VERSION 5.8 ;
BUSBITCHARS "[]" ;
DIVIDERCHAR "/" ;
UNITS
    DATABASE MICRONS 1000 ;
END UNITS

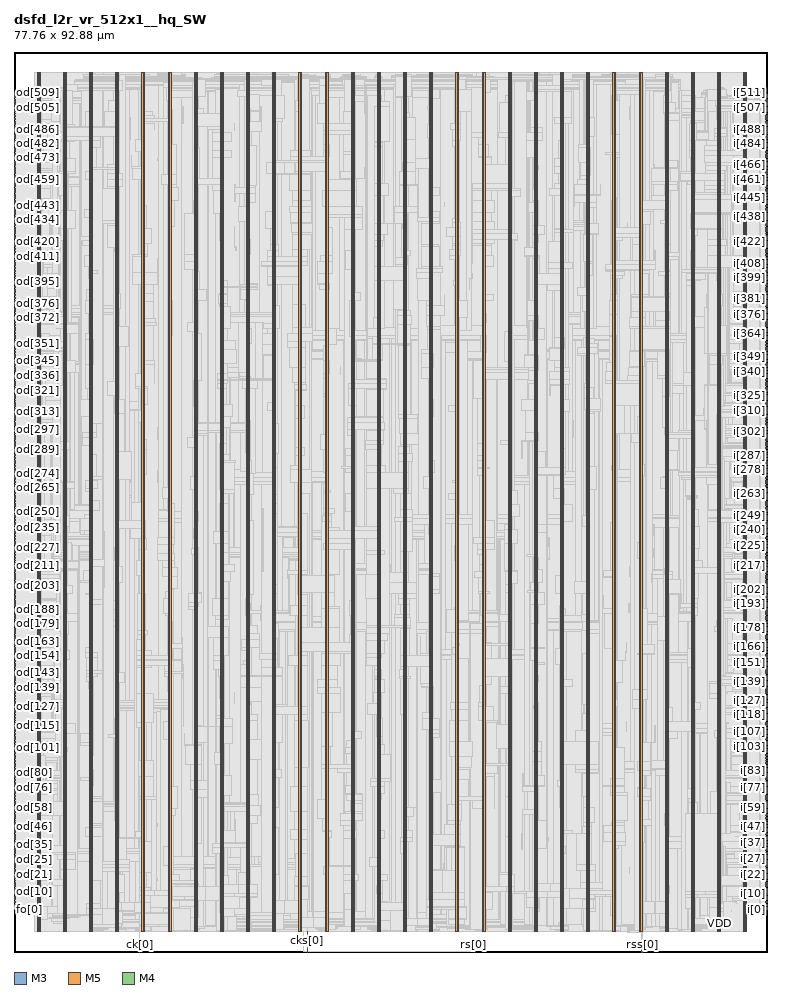
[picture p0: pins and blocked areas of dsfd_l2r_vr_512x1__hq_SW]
MACRO dsfd_l2r_vr_512x1__hq_SW
  FOREIGN dsfd_l2r_vr_512x1__hq_SW 0 0 ;
  CLASS BLOCK ;
  SIZE 77.76 BY 92.88 ;
  PIN ck[0]
    DIRECTION INPUT ;
    USE SIGNAL ;
    PORT
      LAYER M3 ;
        RECT  12.96 0 12.978 0.144 ;
    END
    PORT
      LAYER M3 ;
        RECT  12.96 0.108 12.978 0.173 ;
    END
  END ck[0]
  PIN cks[0]
    DIRECTION INPUT ;
    USE SIGNAL ;
    PORT
      LAYER M5 ;
        RECT  30.24 0 30.264 0.192 ;
    END
    PORT
      LAYER M5 ;
        RECT  30.24 0.144 30.264 2.137 ;
    END
  END cks[0]
  PIN fo[0]
    DIRECTION OUTPUT ;
    USE SIGNAL ;
    PORT
      LAYER M4 ;
        RECT  0 4.416 0.192 4.44 ;
    END
  END fo[0]
  PIN i[0]
    DIRECTION INPUT ;
    USE SIGNAL ;
    PORT
      LAYER M4 ;
        RECT  77.568 4.416 77.76 4.44 ;
    END
  END i[0]
  PIN i[100]
    DIRECTION INPUT ;
    USE SIGNAL ;
    PORT
      LAYER M4 ;
        RECT  77.568 20.736 77.76 20.76 ;
    END
  END i[100]
  PIN i[101]
    DIRECTION INPUT ;
    USE SIGNAL ;
    PORT
      LAYER M4 ;
        RECT  77.568 20.88 77.76 20.904 ;
    END
  END i[101]
  PIN i[102]
    DIRECTION INPUT ;
    USE SIGNAL ;
    PORT
      LAYER M4 ;
        RECT  77.568 21.072 77.76 21.096 ;
    END
  END i[102]
  PIN i[103]
    DIRECTION INPUT ;
    USE SIGNAL ;
    PORT
      LAYER M4 ;
        RECT  77.568 21.216 77.76 21.24 ;
    END
  END i[103]
  PIN i[104]
    DIRECTION INPUT ;
    USE SIGNAL ;
    PORT
      LAYER M4 ;
        RECT  77.568 21.408 77.76 21.432 ;
    END
  END i[104]
  PIN i[105]
    DIRECTION INPUT ;
    USE SIGNAL ;
    PORT
      LAYER M4 ;
        RECT  77.568 21.552 77.76 21.576 ;
    END
  END i[105]
  PIN i[106]
    DIRECTION INPUT ;
    USE SIGNAL ;
    PORT
      LAYER M4 ;
        RECT  77.568 21.696 77.76 21.72 ;
    END
  END i[106]
  PIN i[107]
    DIRECTION INPUT ;
    USE SIGNAL ;
    PORT
      LAYER M4 ;
        RECT  77.568 21.888 77.76 21.912 ;
    END
  END i[107]
  PIN i[108]
    DIRECTION INPUT ;
    USE SIGNAL ;
    PORT
      LAYER M4 ;
        RECT  77.568 22.032 77.76 22.056 ;
    END
  END i[108]
  PIN i[109]
    DIRECTION INPUT ;
    USE SIGNAL ;
    PORT
      LAYER M4 ;
        RECT  77.568 22.224 77.76 22.248 ;
    END
  END i[109]
  PIN i[10]
    DIRECTION INPUT ;
    USE SIGNAL ;
    PORT
      LAYER M4 ;
        RECT  77.568 6.048 77.76 6.072 ;
    END
  END i[10]
  PIN i[110]
    DIRECTION INPUT ;
    USE SIGNAL ;
    PORT
      LAYER M4 ;
        RECT  77.568 22.368 77.76 22.392 ;
    END
  END i[110]
  PIN i[111]
    DIRECTION INPUT ;
    USE SIGNAL ;
    PORT
      LAYER M4 ;
        RECT  77.568 22.512 77.76 22.536 ;
    END
  END i[111]
  PIN i[112]
    DIRECTION INPUT ;
    USE SIGNAL ;
    PORT
      LAYER M4 ;
        RECT  77.568 22.704 77.76 22.728 ;
    END
  END i[112]
  PIN i[113]
    DIRECTION INPUT ;
    USE SIGNAL ;
    PORT
      LAYER M4 ;
        RECT  77.568 22.848 77.76 22.872 ;
    END
  END i[113]
  PIN i[114]
    DIRECTION INPUT ;
    USE SIGNAL ;
    PORT
      LAYER M4 ;
        RECT  77.568 23.04 77.76 23.064 ;
    END
  END i[114]
  PIN i[115]
    DIRECTION INPUT ;
    USE SIGNAL ;
    PORT
      LAYER M4 ;
        RECT  77.568 23.184 77.76 23.208 ;
    END
  END i[115]
  PIN i[116]
    DIRECTION INPUT ;
    USE SIGNAL ;
    PORT
      LAYER M4 ;
        RECT  77.568 23.328 77.76 23.352 ;
    END
  END i[116]
  PIN i[117]
    DIRECTION INPUT ;
    USE SIGNAL ;
    PORT
      LAYER M4 ;
        RECT  77.568 23.52 77.76 23.544 ;
    END
  END i[117]
  PIN i[118]
    DIRECTION INPUT ;
    USE SIGNAL ;
    PORT
      LAYER M4 ;
        RECT  77.568 23.664 77.76 23.688 ;
    END
  END i[118]
  PIN i[119]
    DIRECTION INPUT ;
    USE SIGNAL ;
    PORT
      LAYER M4 ;
        RECT  77.568 23.856 77.76 23.88 ;
    END
  END i[119]
  PIN i[11]
    DIRECTION INPUT ;
    USE SIGNAL ;
    PORT
      LAYER M4 ;
        RECT  77.568 6.192 77.76 6.216 ;
    END
  END i[11]
  PIN i[120]
    DIRECTION INPUT ;
    USE SIGNAL ;
    PORT
      LAYER M4 ;
        RECT  77.568 24 77.76 24.024 ;
    END
  END i[120]
  PIN i[121]
    DIRECTION INPUT ;
    USE SIGNAL ;
    PORT
      LAYER M4 ;
        RECT  77.568 24.144 77.76 24.168 ;
    END
  END i[121]
  PIN i[122]
    DIRECTION INPUT ;
    USE SIGNAL ;
    PORT
      LAYER M4 ;
        RECT  77.568 24.336 77.76 24.36 ;
    END
  END i[122]
  PIN i[123]
    DIRECTION INPUT ;
    USE SIGNAL ;
    PORT
      LAYER M4 ;
        RECT  77.568 24.48 77.76 24.504 ;
    END
  END i[123]
  PIN i[124]
    DIRECTION INPUT ;
    USE SIGNAL ;
    PORT
      LAYER M4 ;
        RECT  77.568 24.672 77.76 24.696 ;
    END
  END i[124]
  PIN i[125]
    DIRECTION INPUT ;
    USE SIGNAL ;
    PORT
      LAYER M4 ;
        RECT  77.568 24.816 77.76 24.84 ;
    END
  END i[125]
  PIN i[126]
    DIRECTION INPUT ;
    USE SIGNAL ;
    PORT
      LAYER M4 ;
        RECT  77.568 24.96 77.76 24.984 ;
    END
  END i[126]
  PIN i[127]
    DIRECTION INPUT ;
    USE SIGNAL ;
    PORT
      LAYER M4 ;
        RECT  77.568 25.152 77.76 25.176 ;
    END
  END i[127]
  PIN i[128]
    DIRECTION INPUT ;
    USE SIGNAL ;
    PORT
      LAYER M4 ;
        RECT  77.568 25.296 77.76 25.32 ;
    END
  END i[128]
  PIN i[129]
    DIRECTION INPUT ;
    USE SIGNAL ;
    PORT
      LAYER M4 ;
        RECT  77.568 25.488 77.76 25.512 ;
    END
  END i[129]
  PIN i[12]
    DIRECTION INPUT ;
    USE SIGNAL ;
    PORT
      LAYER M4 ;
        RECT  77.568 6.384 77.76 6.408 ;
    END
  END i[12]
  PIN i[130]
    DIRECTION INPUT ;
    USE SIGNAL ;
    PORT
      LAYER M4 ;
        RECT  77.568 25.632 77.76 25.656 ;
    END
  END i[130]
  PIN i[131]
    DIRECTION INPUT ;
    USE SIGNAL ;
    PORT
      LAYER M4 ;
        RECT  77.568 25.824 77.76 25.848 ;
    END
  END i[131]
  PIN i[132]
    DIRECTION INPUT ;
    USE SIGNAL ;
    PORT
      LAYER M4 ;
        RECT  77.568 25.968 77.76 25.992 ;
    END
  END i[132]
  PIN i[133]
    DIRECTION INPUT ;
    USE SIGNAL ;
    PORT
      LAYER M4 ;
        RECT  77.568 26.112 77.76 26.136 ;
    END
  END i[133]
  PIN i[134]
    DIRECTION INPUT ;
    USE SIGNAL ;
    PORT
      LAYER M4 ;
        RECT  77.568 26.304 77.76 26.328 ;
    END
  END i[134]
  PIN i[135]
    DIRECTION INPUT ;
    USE SIGNAL ;
    PORT
      LAYER M4 ;
        RECT  77.568 26.448 77.76 26.472 ;
    END
  END i[135]
  PIN i[136]
    DIRECTION INPUT ;
    USE SIGNAL ;
    PORT
      LAYER M4 ;
        RECT  77.568 26.64 77.76 26.664 ;
    END
  END i[136]
  PIN i[137]
    DIRECTION INPUT ;
    USE SIGNAL ;
    PORT
      LAYER M4 ;
        RECT  77.568 26.784 77.76 26.808 ;
    END
  END i[137]
  PIN i[138]
    DIRECTION INPUT ;
    USE SIGNAL ;
    PORT
      LAYER M4 ;
        RECT  77.568 26.928 77.76 26.952 ;
    END
  END i[138]
  PIN i[139]
    DIRECTION INPUT ;
    USE SIGNAL ;
    PORT
      LAYER M4 ;
        RECT  77.568 27.12 77.76 27.144 ;
    END
  END i[139]
  PIN i[13]
    DIRECTION INPUT ;
    USE SIGNAL ;
    PORT
      LAYER M4 ;
        RECT  77.568 6.528 77.76 6.552 ;
    END
  END i[13]
  PIN i[140]
    DIRECTION INPUT ;
    USE SIGNAL ;
    PORT
      LAYER M4 ;
        RECT  77.568 27.264 77.76 27.288 ;
    END
  END i[140]
  PIN i[141]
    DIRECTION INPUT ;
    USE SIGNAL ;
    PORT
      LAYER M4 ;
        RECT  77.568 27.456 77.76 27.48 ;
    END
  END i[141]
  PIN i[142]
    DIRECTION INPUT ;
    USE SIGNAL ;
    PORT
      LAYER M4 ;
        RECT  77.568 27.6 77.76 27.624 ;
    END
  END i[142]
  PIN i[143]
    DIRECTION INPUT ;
    USE SIGNAL ;
    PORT
      LAYER M4 ;
        RECT  77.568 27.744 77.76 27.768 ;
    END
  END i[143]
  PIN i[144]
    DIRECTION INPUT ;
    USE SIGNAL ;
    PORT
      LAYER M4 ;
        RECT  77.568 27.936 77.76 27.96 ;
    END
  END i[144]
  PIN i[145]
    DIRECTION INPUT ;
    USE SIGNAL ;
    PORT
      LAYER M4 ;
        RECT  77.568 28.08 77.76 28.104 ;
    END
  END i[145]
  PIN i[146]
    DIRECTION INPUT ;
    USE SIGNAL ;
    PORT
      LAYER M4 ;
        RECT  77.568 28.272 77.76 28.296 ;
    END
  END i[146]
  PIN i[147]
    DIRECTION INPUT ;
    USE SIGNAL ;
    PORT
      LAYER M4 ;
        RECT  77.568 28.416 77.76 28.44 ;
    END
  END i[147]
  PIN i[148]
    DIRECTION INPUT ;
    USE SIGNAL ;
    PORT
      LAYER M4 ;
        RECT  77.568 28.56 77.76 28.584 ;
    END
  END i[148]
  PIN i[149]
    DIRECTION INPUT ;
    USE SIGNAL ;
    PORT
      LAYER M4 ;
        RECT  77.568 28.752 77.76 28.776 ;
    END
  END i[149]
  PIN i[14]
    DIRECTION INPUT ;
    USE SIGNAL ;
    PORT
      LAYER M4 ;
        RECT  77.568 6.72 77.76 6.744 ;
    END
  END i[14]
  PIN i[150]
    DIRECTION INPUT ;
    USE SIGNAL ;
    PORT
      LAYER M4 ;
        RECT  77.568 28.896 77.76 28.92 ;
    END
  END i[150]
  PIN i[151]
    DIRECTION INPUT ;
    USE SIGNAL ;
    PORT
      LAYER M4 ;
        RECT  77.568 29.088 77.76 29.112 ;
    END
  END i[151]
  PIN i[152]
    DIRECTION INPUT ;
    USE SIGNAL ;
    PORT
      LAYER M4 ;
        RECT  77.568 29.232 77.76 29.256 ;
    END
  END i[152]
  PIN i[153]
    DIRECTION INPUT ;
    USE SIGNAL ;
    PORT
      LAYER M4 ;
        RECT  77.568 29.376 77.76 29.4 ;
    END
  END i[153]
  PIN i[154]
    DIRECTION INPUT ;
    USE SIGNAL ;
    PORT
      LAYER M4 ;
        RECT  77.568 29.568 77.76 29.592 ;
    END
  END i[154]
  PIN i[155]
    DIRECTION INPUT ;
    USE SIGNAL ;
    PORT
      LAYER M4 ;
        RECT  77.568 29.712 77.76 29.736 ;
    END
  END i[155]
  PIN i[156]
    DIRECTION INPUT ;
    USE SIGNAL ;
    PORT
      LAYER M4 ;
        RECT  77.568 29.904 77.76 29.928 ;
    END
  END i[156]
  PIN i[157]
    DIRECTION INPUT ;
    USE SIGNAL ;
    PORT
      LAYER M4 ;
        RECT  77.568 30.048 77.76 30.072 ;
    END
  END i[157]
  PIN i[158]
    DIRECTION INPUT ;
    USE SIGNAL ;
    PORT
      LAYER M4 ;
        RECT  77.568 30.192 77.76 30.216 ;
    END
  END i[158]
  PIN i[159]
    DIRECTION INPUT ;
    USE SIGNAL ;
    PORT
      LAYER M4 ;
        RECT  77.568 30.384 77.76 30.408 ;
    END
  END i[159]
  PIN i[15]
    DIRECTION INPUT ;
    USE SIGNAL ;
    PORT
      LAYER M4 ;
        RECT  77.568 6.864 77.76 6.888 ;
    END
  END i[15]
  PIN i[160]
    DIRECTION INPUT ;
    USE SIGNAL ;
    PORT
      LAYER M4 ;
        RECT  77.568 30.528 77.76 30.552 ;
    END
  END i[160]
  PIN i[161]
    DIRECTION INPUT ;
    USE SIGNAL ;
    PORT
      LAYER M4 ;
        RECT  77.568 30.72 77.76 30.744 ;
    END
  END i[161]
  PIN i[162]
    DIRECTION INPUT ;
    USE SIGNAL ;
    PORT
      LAYER M4 ;
        RECT  77.568 30.864 77.76 30.888 ;
    END
  END i[162]
  PIN i[163]
    DIRECTION INPUT ;
    USE SIGNAL ;
    PORT
      LAYER M4 ;
        RECT  77.568 31.008 77.76 31.032 ;
    END
  END i[163]
  PIN i[164]
    DIRECTION INPUT ;
    USE SIGNAL ;
    PORT
      LAYER M4 ;
        RECT  77.568 31.2 77.76 31.224 ;
    END
  END i[164]
  PIN i[165]
    DIRECTION INPUT ;
    USE SIGNAL ;
    PORT
      LAYER M4 ;
        RECT  77.568 31.344 77.76 31.368 ;
    END
  END i[165]
  PIN i[166]
    DIRECTION INPUT ;
    USE SIGNAL ;
    PORT
      LAYER M4 ;
        RECT  77.568 31.536 77.76 31.56 ;
    END
  END i[166]
  PIN i[167]
    DIRECTION INPUT ;
    USE SIGNAL ;
    PORT
      LAYER M4 ;
        RECT  77.568 31.68 77.76 31.704 ;
    END
  END i[167]
  PIN i[168]
    DIRECTION INPUT ;
    USE SIGNAL ;
    PORT
      LAYER M4 ;
        RECT  77.568 31.824 77.76 31.848 ;
    END
  END i[168]
  PIN i[169]
    DIRECTION INPUT ;
    USE SIGNAL ;
    PORT
      LAYER M4 ;
        RECT  77.568 32.016 77.76 32.04 ;
    END
  END i[169]
  PIN i[16]
    DIRECTION INPUT ;
    USE SIGNAL ;
    PORT
      LAYER M4 ;
        RECT  77.568 7.008 77.76 7.032 ;
    END
  END i[16]
  PIN i[170]
    DIRECTION INPUT ;
    USE SIGNAL ;
    PORT
      LAYER M4 ;
        RECT  77.568 32.16 77.76 32.184 ;
    END
  END i[170]
  PIN i[171]
    DIRECTION INPUT ;
    USE SIGNAL ;
    PORT
      LAYER M4 ;
        RECT  77.568 32.352 77.76 32.376 ;
    END
  END i[171]
  PIN i[172]
    DIRECTION INPUT ;
    USE SIGNAL ;
    PORT
      LAYER M4 ;
        RECT  77.568 32.496 77.76 32.52 ;
    END
  END i[172]
  PIN i[173]
    DIRECTION INPUT ;
    USE SIGNAL ;
    PORT
      LAYER M4 ;
        RECT  77.568 32.64 77.76 32.664 ;
    END
  END i[173]
  PIN i[174]
    DIRECTION INPUT ;
    USE SIGNAL ;
    PORT
      LAYER M4 ;
        RECT  77.568 32.832 77.76 32.856 ;
    END
  END i[174]
  PIN i[175]
    DIRECTION INPUT ;
    USE SIGNAL ;
    PORT
      LAYER M4 ;
        RECT  77.568 32.976 77.76 33 ;
    END
  END i[175]
  PIN i[176]
    DIRECTION INPUT ;
    USE SIGNAL ;
    PORT
      LAYER M4 ;
        RECT  77.568 33.168 77.76 33.192 ;
    END
  END i[176]
  PIN i[177]
    DIRECTION INPUT ;
    USE SIGNAL ;
    PORT
      LAYER M4 ;
        RECT  77.568 33.312 77.76 33.336 ;
    END
  END i[177]
  PIN i[178]
    DIRECTION INPUT ;
    USE SIGNAL ;
    PORT
      LAYER M4 ;
        RECT  77.568 33.456 77.76 33.48 ;
    END
  END i[178]
  PIN i[179]
    DIRECTION INPUT ;
    USE SIGNAL ;
    PORT
      LAYER M4 ;
        RECT  77.568 33.648 77.76 33.672 ;
    END
  END i[179]
  PIN i[17]
    DIRECTION INPUT ;
    USE SIGNAL ;
    PORT
      LAYER M4 ;
        RECT  77.568 7.2 77.76 7.224 ;
    END
  END i[17]
  PIN i[180]
    DIRECTION INPUT ;
    USE SIGNAL ;
    PORT
      LAYER M4 ;
        RECT  77.568 33.792 77.76 33.816 ;
    END
  END i[180]
  PIN i[181]
    DIRECTION INPUT ;
    USE SIGNAL ;
    PORT
      LAYER M4 ;
        RECT  77.568 33.984 77.76 34.008 ;
    END
  END i[181]
  PIN i[182]
    DIRECTION INPUT ;
    USE SIGNAL ;
    PORT
      LAYER M4 ;
        RECT  77.568 34.128 77.76 34.152 ;
    END
  END i[182]
  PIN i[183]
    DIRECTION INPUT ;
    USE SIGNAL ;
    PORT
      LAYER M4 ;
        RECT  77.568 34.272 77.76 34.296 ;
    END
  END i[183]
  PIN i[184]
    DIRECTION INPUT ;
    USE SIGNAL ;
    PORT
      LAYER M4 ;
        RECT  77.568 34.464 77.76 34.488 ;
    END
  END i[184]
  PIN i[185]
    DIRECTION INPUT ;
    USE SIGNAL ;
    PORT
      LAYER M4 ;
        RECT  77.568 34.608 77.76 34.632 ;
    END
  END i[185]
  PIN i[186]
    DIRECTION INPUT ;
    USE SIGNAL ;
    PORT
      LAYER M4 ;
        RECT  77.568 34.8 77.76 34.824 ;
    END
  END i[186]
  PIN i[187]
    DIRECTION INPUT ;
    USE SIGNAL ;
    PORT
      LAYER M4 ;
        RECT  77.568 34.944 77.76 34.968 ;
    END
  END i[187]
  PIN i[188]
    DIRECTION INPUT ;
    USE SIGNAL ;
    PORT
      LAYER M4 ;
        RECT  77.568 35.088 77.76 35.112 ;
    END
  END i[188]
  PIN i[189]
    DIRECTION INPUT ;
    USE SIGNAL ;
    PORT
      LAYER M4 ;
        RECT  77.568 35.28 77.76 35.304 ;
    END
  END i[189]
  PIN i[18]
    DIRECTION INPUT ;
    USE SIGNAL ;
    PORT
      LAYER M4 ;
        RECT  77.568 7.344 77.76 7.368 ;
    END
  END i[18]
  PIN i[190]
    DIRECTION INPUT ;
    USE SIGNAL ;
    PORT
      LAYER M4 ;
        RECT  77.568 35.424 77.76 35.448 ;
    END
  END i[190]
  PIN i[191]
    DIRECTION INPUT ;
    USE SIGNAL ;
    PORT
      LAYER M4 ;
        RECT  77.568 35.616 77.76 35.64 ;
    END
  END i[191]
  PIN i[192]
    DIRECTION INPUT ;
    USE SIGNAL ;
    PORT
      LAYER M4 ;
        RECT  77.568 35.76 77.76 35.784 ;
    END
  END i[192]
  PIN i[193]
    DIRECTION INPUT ;
    USE SIGNAL ;
    PORT
      LAYER M4 ;
        RECT  77.568 35.904 77.76 35.928 ;
    END
  END i[193]
  PIN i[194]
    DIRECTION INPUT ;
    USE SIGNAL ;
    PORT
      LAYER M4 ;
        RECT  77.568 36.096 77.76 36.12 ;
    END
  END i[194]
  PIN i[195]
    DIRECTION INPUT ;
    USE SIGNAL ;
    PORT
      LAYER M4 ;
        RECT  77.568 36.24 77.76 36.264 ;
    END
  END i[195]
  PIN i[196]
    DIRECTION INPUT ;
    USE SIGNAL ;
    PORT
      LAYER M4 ;
        RECT  77.568 36.432 77.76 36.456 ;
    END
  END i[196]
  PIN i[197]
    DIRECTION INPUT ;
    USE SIGNAL ;
    PORT
      LAYER M4 ;
        RECT  77.568 36.576 77.76 36.6 ;
    END
  END i[197]
  PIN i[198]
    DIRECTION INPUT ;
    USE SIGNAL ;
    PORT
      LAYER M4 ;
        RECT  77.568 36.72 77.76 36.744 ;
    END
  END i[198]
  PIN i[199]
    DIRECTION INPUT ;
    USE SIGNAL ;
    PORT
      LAYER M4 ;
        RECT  77.568 36.912 77.76 36.936 ;
    END
  END i[199]
  PIN i[19]
    DIRECTION INPUT ;
    USE SIGNAL ;
    PORT
      LAYER M4 ;
        RECT  77.568 7.536 77.76 7.56 ;
    END
  END i[19]
  PIN i[1]
    DIRECTION INPUT ;
    USE SIGNAL ;
    PORT
      LAYER M4 ;
        RECT  77.568 4.56 77.76 4.584 ;
    END
  END i[1]
  PIN i[200]
    DIRECTION INPUT ;
    USE SIGNAL ;
    PORT
      LAYER M4 ;
        RECT  77.568 37.056 77.76 37.08 ;
    END
  END i[200]
  PIN i[201]
    DIRECTION INPUT ;
    USE SIGNAL ;
    PORT
      LAYER M4 ;
        RECT  77.568 37.248 77.76 37.272 ;
    END
  END i[201]
  PIN i[202]
    DIRECTION INPUT ;
    USE SIGNAL ;
    PORT
      LAYER M4 ;
        RECT  77.568 37.392 77.76 37.416 ;
    END
  END i[202]
  PIN i[203]
    DIRECTION INPUT ;
    USE SIGNAL ;
    PORT
      LAYER M4 ;
        RECT  77.568 37.536 77.76 37.56 ;
    END
  END i[203]
  PIN i[204]
    DIRECTION INPUT ;
    USE SIGNAL ;
    PORT
      LAYER M4 ;
        RECT  77.568 37.728 77.76 37.752 ;
    END
  END i[204]
  PIN i[205]
    DIRECTION INPUT ;
    USE SIGNAL ;
    PORT
      LAYER M4 ;
        RECT  77.568 37.872 77.76 37.896 ;
    END
  END i[205]
  PIN i[206]
    DIRECTION INPUT ;
    USE SIGNAL ;
    PORT
      LAYER M4 ;
        RECT  77.568 38.064 77.76 38.088 ;
    END
  END i[206]
  PIN i[207]
    DIRECTION INPUT ;
    USE SIGNAL ;
    PORT
      LAYER M4 ;
        RECT  77.568 38.208 77.76 38.232 ;
    END
  END i[207]
  PIN i[208]
    DIRECTION INPUT ;
    USE SIGNAL ;
    PORT
      LAYER M4 ;
        RECT  77.568 38.352 77.76 38.376 ;
    END
  END i[208]
  PIN i[209]
    DIRECTION INPUT ;
    USE SIGNAL ;
    PORT
      LAYER M4 ;
        RECT  77.568 38.544 77.76 38.568 ;
    END
  END i[209]
  PIN i[20]
    DIRECTION INPUT ;
    USE SIGNAL ;
    PORT
      LAYER M4 ;
        RECT  77.568 7.68 77.76 7.704 ;
    END
  END i[20]
  PIN i[210]
    DIRECTION INPUT ;
    USE SIGNAL ;
    PORT
      LAYER M4 ;
        RECT  77.568 38.688 77.76 38.712 ;
    END
  END i[210]
  PIN i[211]
    DIRECTION INPUT ;
    USE SIGNAL ;
    PORT
      LAYER M4 ;
        RECT  77.568 38.88 77.76 38.904 ;
    END
  END i[211]
  PIN i[212]
    DIRECTION INPUT ;
    USE SIGNAL ;
    PORT
      LAYER M4 ;
        RECT  77.568 39.024 77.76 39.048 ;
    END
  END i[212]
  PIN i[213]
    DIRECTION INPUT ;
    USE SIGNAL ;
    PORT
      LAYER M4 ;
        RECT  77.568 39.168 77.76 39.192 ;
    END
  END i[213]
  PIN i[214]
    DIRECTION INPUT ;
    USE SIGNAL ;
    PORT
      LAYER M4 ;
        RECT  77.568 39.36 77.76 39.384 ;
    END
  END i[214]
  PIN i[215]
    DIRECTION INPUT ;
    USE SIGNAL ;
    PORT
      LAYER M4 ;
        RECT  77.568 39.504 77.76 39.528 ;
    END
  END i[215]
  PIN i[216]
    DIRECTION INPUT ;
    USE SIGNAL ;
    PORT
      LAYER M4 ;
        RECT  77.568 39.696 77.76 39.72 ;
    END
  END i[216]
  PIN i[217]
    DIRECTION INPUT ;
    USE SIGNAL ;
    PORT
      LAYER M4 ;
        RECT  77.568 39.84 77.76 39.864 ;
    END
  END i[217]
  PIN i[218]
    DIRECTION INPUT ;
    USE SIGNAL ;
    PORT
      LAYER M4 ;
        RECT  77.568 39.984 77.76 40.008 ;
    END
  END i[218]
  PIN i[219]
    DIRECTION INPUT ;
    USE SIGNAL ;
    PORT
      LAYER M4 ;
        RECT  77.568 40.176 77.76 40.2 ;
    END
  END i[219]
  PIN i[21]
    DIRECTION INPUT ;
    USE SIGNAL ;
    PORT
      LAYER M4 ;
        RECT  77.568 7.824 77.76 7.848 ;
    END
  END i[21]
  PIN i[220]
    DIRECTION INPUT ;
    USE SIGNAL ;
    PORT
      LAYER M4 ;
        RECT  77.568 40.32 77.76 40.344 ;
    END
  END i[220]
  PIN i[221]
    DIRECTION INPUT ;
    USE SIGNAL ;
    PORT
      LAYER M4 ;
        RECT  77.568 40.512 77.76 40.536 ;
    END
  END i[221]
  PIN i[222]
    DIRECTION INPUT ;
    USE SIGNAL ;
    PORT
      LAYER M4 ;
        RECT  77.568 40.656 77.76 40.68 ;
    END
  END i[222]
  PIN i[223]
    DIRECTION INPUT ;
    USE SIGNAL ;
    PORT
      LAYER M4 ;
        RECT  77.568 40.8 77.76 40.824 ;
    END
  END i[223]
  PIN i[224]
    DIRECTION INPUT ;
    USE SIGNAL ;
    PORT
      LAYER M4 ;
        RECT  77.568 40.992 77.76 41.016 ;
    END
  END i[224]
  PIN i[225]
    DIRECTION INPUT ;
    USE SIGNAL ;
    PORT
      LAYER M4 ;
        RECT  77.568 41.136 77.76 41.16 ;
    END
  END i[225]
  PIN i[226]
    DIRECTION INPUT ;
    USE SIGNAL ;
    PORT
      LAYER M4 ;
        RECT  77.568 41.328 77.76 41.352 ;
    END
  END i[226]
  PIN i[227]
    DIRECTION INPUT ;
    USE SIGNAL ;
    PORT
      LAYER M4 ;
        RECT  77.568 41.472 77.76 41.496 ;
    END
  END i[227]
  PIN i[228]
    DIRECTION INPUT ;
    USE SIGNAL ;
    PORT
      LAYER M4 ;
        RECT  77.568 41.616 77.76 41.64 ;
    END
  END i[228]
  PIN i[229]
    DIRECTION INPUT ;
    USE SIGNAL ;
    PORT
      LAYER M4 ;
        RECT  77.568 41.808 77.76 41.832 ;
    END
  END i[229]
  PIN i[22]
    DIRECTION INPUT ;
    USE SIGNAL ;
    PORT
      LAYER M4 ;
        RECT  77.568 8.016 77.76 8.04 ;
    END
  END i[22]
  PIN i[230]
    DIRECTION INPUT ;
    USE SIGNAL ;
    PORT
      LAYER M4 ;
        RECT  77.568 41.952 77.76 41.976 ;
    END
  END i[230]
  PIN i[231]
    DIRECTION INPUT ;
    USE SIGNAL ;
    PORT
      LAYER M4 ;
        RECT  77.568 42.144 77.76 42.168 ;
    END
  END i[231]
  PIN i[232]
    DIRECTION INPUT ;
    USE SIGNAL ;
    PORT
      LAYER M4 ;
        RECT  77.568 42.288 77.76 42.312 ;
    END
  END i[232]
  PIN i[233]
    DIRECTION INPUT ;
    USE SIGNAL ;
    PORT
      LAYER M4 ;
        RECT  77.568 42.432 77.76 42.456 ;
    END
  END i[233]
  PIN i[234]
    DIRECTION INPUT ;
    USE SIGNAL ;
    PORT
      LAYER M4 ;
        RECT  77.568 42.624 77.76 42.648 ;
    END
  END i[234]
  PIN i[235]
    DIRECTION INPUT ;
    USE SIGNAL ;
    PORT
      LAYER M4 ;
        RECT  77.568 42.768 77.76 42.792 ;
    END
  END i[235]
  PIN i[236]
    DIRECTION INPUT ;
    USE SIGNAL ;
    PORT
      LAYER M4 ;
        RECT  77.568 42.96 77.76 42.984 ;
    END
  END i[236]
  PIN i[237]
    DIRECTION INPUT ;
    USE SIGNAL ;
    PORT
      LAYER M4 ;
        RECT  77.568 43.104 77.76 43.128 ;
    END
  END i[237]
  PIN i[238]
    DIRECTION INPUT ;
    USE SIGNAL ;
    PORT
      LAYER M4 ;
        RECT  77.568 43.248 77.76 43.272 ;
    END
  END i[238]
  PIN i[239]
    DIRECTION INPUT ;
    USE SIGNAL ;
    PORT
      LAYER M4 ;
        RECT  77.568 43.44 77.76 43.464 ;
    END
  END i[239]
  PIN i[23]
    DIRECTION INPUT ;
    USE SIGNAL ;
    PORT
      LAYER M4 ;
        RECT  77.568 8.16 77.76 8.184 ;
    END
  END i[23]
  PIN i[240]
    DIRECTION INPUT ;
    USE SIGNAL ;
    PORT
      LAYER M4 ;
        RECT  77.568 43.584 77.76 43.608 ;
    END
  END i[240]
  PIN i[241]
    DIRECTION INPUT ;
    USE SIGNAL ;
    PORT
      LAYER M4 ;
        RECT  77.568 43.776 77.76 43.8 ;
    END
  END i[241]
  PIN i[242]
    DIRECTION INPUT ;
    USE SIGNAL ;
    PORT
      LAYER M4 ;
        RECT  77.568 43.92 77.76 43.944 ;
    END
  END i[242]
  PIN i[243]
    DIRECTION INPUT ;
    USE SIGNAL ;
    PORT
      LAYER M4 ;
        RECT  77.568 44.064 77.76 44.088 ;
    END
  END i[243]
  PIN i[244]
    DIRECTION INPUT ;
    USE SIGNAL ;
    PORT
      LAYER M4 ;
        RECT  77.568 44.256 77.76 44.28 ;
    END
  END i[244]
  PIN i[245]
    DIRECTION INPUT ;
    USE SIGNAL ;
    PORT
      LAYER M4 ;
        RECT  77.568 44.4 77.76 44.424 ;
    END
  END i[245]
  PIN i[246]
    DIRECTION INPUT ;
    USE SIGNAL ;
    PORT
      LAYER M4 ;
        RECT  77.568 44.592 77.76 44.616 ;
    END
  END i[246]
  PIN i[247]
    DIRECTION INPUT ;
    USE SIGNAL ;
    PORT
      LAYER M4 ;
        RECT  77.568 44.736 77.76 44.76 ;
    END
  END i[247]
  PIN i[248]
    DIRECTION INPUT ;
    USE SIGNAL ;
    PORT
      LAYER M4 ;
        RECT  77.568 44.88 77.76 44.904 ;
    END
  END i[248]
  PIN i[249]
    DIRECTION INPUT ;
    USE SIGNAL ;
    PORT
      LAYER M4 ;
        RECT  77.568 45.072 77.76 45.096 ;
    END
  END i[249]
  PIN i[24]
    DIRECTION INPUT ;
    USE SIGNAL ;
    PORT
      LAYER M4 ;
        RECT  77.568 8.352 77.76 8.376 ;
    END
  END i[24]
  PIN i[250]
    DIRECTION INPUT ;
    USE SIGNAL ;
    PORT
      LAYER M4 ;
        RECT  77.568 45.216 77.76 45.24 ;
    END
  END i[250]
  PIN i[251]
    DIRECTION INPUT ;
    USE SIGNAL ;
    PORT
      LAYER M4 ;
        RECT  77.568 45.408 77.76 45.432 ;
    END
  END i[251]
  PIN i[252]
    DIRECTION INPUT ;
    USE SIGNAL ;
    PORT
      LAYER M4 ;
        RECT  77.568 45.552 77.76 45.576 ;
    END
  END i[252]
  PIN i[253]
    DIRECTION INPUT ;
    USE SIGNAL ;
    PORT
      LAYER M4 ;
        RECT  77.568 45.696 77.76 45.72 ;
    END
  END i[253]
  PIN i[254]
    DIRECTION INPUT ;
    USE SIGNAL ;
    PORT
      LAYER M4 ;
        RECT  77.568 45.888 77.76 45.912 ;
    END
  END i[254]
  PIN i[255]
    DIRECTION INPUT ;
    USE SIGNAL ;
    PORT
      LAYER M4 ;
        RECT  77.568 46.032 77.76 46.056 ;
    END
  END i[255]
  PIN i[256]
    DIRECTION INPUT ;
    USE SIGNAL ;
    PORT
      LAYER M4 ;
        RECT  77.568 46.224 77.76 46.248 ;
    END
  END i[256]
  PIN i[257]
    DIRECTION INPUT ;
    USE SIGNAL ;
    PORT
      LAYER M4 ;
        RECT  77.568 46.368 77.76 46.392 ;
    END
  END i[257]
  PIN i[258]
    DIRECTION INPUT ;
    USE SIGNAL ;
    PORT
      LAYER M4 ;
        RECT  77.568 46.512 77.76 46.536 ;
    END
  END i[258]
  PIN i[259]
    DIRECTION INPUT ;
    USE SIGNAL ;
    PORT
      LAYER M4 ;
        RECT  77.568 46.704 77.76 46.728 ;
    END
  END i[259]
  PIN i[25]
    DIRECTION INPUT ;
    USE SIGNAL ;
    PORT
      LAYER M4 ;
        RECT  77.568 8.496 77.76 8.52 ;
    END
  END i[25]
  PIN i[260]
    DIRECTION INPUT ;
    USE SIGNAL ;
    PORT
      LAYER M4 ;
        RECT  77.568 46.848 77.76 46.872 ;
    END
  END i[260]
  PIN i[261]
    DIRECTION INPUT ;
    USE SIGNAL ;
    PORT
      LAYER M4 ;
        RECT  77.568 47.04 77.76 47.064 ;
    END
  END i[261]
  PIN i[262]
    DIRECTION INPUT ;
    USE SIGNAL ;
    PORT
      LAYER M4 ;
        RECT  77.568 47.184 77.76 47.208 ;
    END
  END i[262]
  PIN i[263]
    DIRECTION INPUT ;
    USE SIGNAL ;
    PORT
      LAYER M4 ;
        RECT  77.568 47.328 77.76 47.352 ;
    END
  END i[263]
  PIN i[264]
    DIRECTION INPUT ;
    USE SIGNAL ;
    PORT
      LAYER M4 ;
        RECT  77.568 47.52 77.76 47.544 ;
    END
  END i[264]
  PIN i[265]
    DIRECTION INPUT ;
    USE SIGNAL ;
    PORT
      LAYER M4 ;
        RECT  77.568 47.664 77.76 47.688 ;
    END
  END i[265]
  PIN i[266]
    DIRECTION INPUT ;
    USE SIGNAL ;
    PORT
      LAYER M4 ;
        RECT  77.568 47.856 77.76 47.88 ;
    END
  END i[266]
  PIN i[267]
    DIRECTION INPUT ;
    USE SIGNAL ;
    PORT
      LAYER M4 ;
        RECT  77.568 48 77.76 48.024 ;
    END
  END i[267]
  PIN i[268]
    DIRECTION INPUT ;
    USE SIGNAL ;
    PORT
      LAYER M4 ;
        RECT  77.568 48.144 77.76 48.168 ;
    END
  END i[268]
  PIN i[269]
    DIRECTION INPUT ;
    USE SIGNAL ;
    PORT
      LAYER M4 ;
        RECT  77.568 48.336 77.76 48.36 ;
    END
  END i[269]
  PIN i[26]
    DIRECTION INPUT ;
    USE SIGNAL ;
    PORT
      LAYER M4 ;
        RECT  77.568 8.64 77.76 8.664 ;
    END
  END i[26]
  PIN i[270]
    DIRECTION INPUT ;
    USE SIGNAL ;
    PORT
      LAYER M4 ;
        RECT  77.568 48.48 77.76 48.504 ;
    END
  END i[270]
  PIN i[271]
    DIRECTION INPUT ;
    USE SIGNAL ;
    PORT
      LAYER M4 ;
        RECT  77.568 48.672 77.76 48.696 ;
    END
  END i[271]
  PIN i[272]
    DIRECTION INPUT ;
    USE SIGNAL ;
    PORT
      LAYER M4 ;
        RECT  77.568 48.816 77.76 48.84 ;
    END
  END i[272]
  PIN i[273]
    DIRECTION INPUT ;
    USE SIGNAL ;
    PORT
      LAYER M4 ;
        RECT  77.568 48.96 77.76 48.984 ;
    END
  END i[273]
  PIN i[274]
    DIRECTION INPUT ;
    USE SIGNAL ;
    PORT
      LAYER M4 ;
        RECT  77.568 49.152 77.76 49.176 ;
    END
  END i[274]
  PIN i[275]
    DIRECTION INPUT ;
    USE SIGNAL ;
    PORT
      LAYER M4 ;
        RECT  77.568 49.296 77.76 49.32 ;
    END
  END i[275]
  PIN i[276]
    DIRECTION INPUT ;
    USE SIGNAL ;
    PORT
      LAYER M4 ;
        RECT  77.568 49.488 77.76 49.512 ;
    END
  END i[276]
  PIN i[277]
    DIRECTION INPUT ;
    USE SIGNAL ;
    PORT
      LAYER M4 ;
        RECT  77.568 49.632 77.76 49.656 ;
    END
  END i[277]
  PIN i[278]
    DIRECTION INPUT ;
    USE SIGNAL ;
    PORT
      LAYER M4 ;
        RECT  77.568 49.776 77.76 49.8 ;
    END
  END i[278]
  PIN i[279]
    DIRECTION INPUT ;
    USE SIGNAL ;
    PORT
      LAYER M4 ;
        RECT  77.568 49.968 77.76 49.992 ;
    END
  END i[279]
  PIN i[27]
    DIRECTION INPUT ;
    USE SIGNAL ;
    PORT
      LAYER M4 ;
        RECT  77.568 8.832 77.76 8.856 ;
    END
  END i[27]
  PIN i[280]
    DIRECTION INPUT ;
    USE SIGNAL ;
    PORT
      LAYER M4 ;
        RECT  77.568 50.112 77.76 50.136 ;
    END
  END i[280]
  PIN i[281]
    DIRECTION INPUT ;
    USE SIGNAL ;
    PORT
      LAYER M4 ;
        RECT  77.568 50.304 77.76 50.328 ;
    END
  END i[281]
  PIN i[282]
    DIRECTION INPUT ;
    USE SIGNAL ;
    PORT
      LAYER M4 ;
        RECT  77.568 50.448 77.76 50.472 ;
    END
  END i[282]
  PIN i[283]
    DIRECTION INPUT ;
    USE SIGNAL ;
    PORT
      LAYER M4 ;
        RECT  77.568 50.592 77.76 50.616 ;
    END
  END i[283]
  PIN i[284]
    DIRECTION INPUT ;
    USE SIGNAL ;
    PORT
      LAYER M4 ;
        RECT  77.568 50.784 77.76 50.808 ;
    END
  END i[284]
  PIN i[285]
    DIRECTION INPUT ;
    USE SIGNAL ;
    PORT
      LAYER M4 ;
        RECT  77.568 50.928 77.76 50.952 ;
    END
  END i[285]
  PIN i[286]
    DIRECTION INPUT ;
    USE SIGNAL ;
    PORT
      LAYER M4 ;
        RECT  77.568 51.12 77.76 51.144 ;
    END
  END i[286]
  PIN i[287]
    DIRECTION INPUT ;
    USE SIGNAL ;
    PORT
      LAYER M4 ;
        RECT  77.568 51.264 77.76 51.288 ;
    END
  END i[287]
  PIN i[288]
    DIRECTION INPUT ;
    USE SIGNAL ;
    PORT
      LAYER M4 ;
        RECT  77.568 51.408 77.76 51.432 ;
    END
  END i[288]
  PIN i[289]
    DIRECTION INPUT ;
    USE SIGNAL ;
    PORT
      LAYER M4 ;
        RECT  77.568 51.6 77.76 51.624 ;
    END
  END i[289]
  PIN i[28]
    DIRECTION INPUT ;
    USE SIGNAL ;
    PORT
      LAYER M4 ;
        RECT  77.568 8.976 77.76 9 ;
    END
  END i[28]
  PIN i[290]
    DIRECTION INPUT ;
    USE SIGNAL ;
    PORT
      LAYER M4 ;
        RECT  77.568 51.744 77.76 51.768 ;
    END
  END i[290]
  PIN i[291]
    DIRECTION INPUT ;
    USE SIGNAL ;
    PORT
      LAYER M4 ;
        RECT  77.568 51.936 77.76 51.96 ;
    END
  END i[291]
  PIN i[292]
    DIRECTION INPUT ;
    USE SIGNAL ;
    PORT
      LAYER M4 ;
        RECT  77.568 52.08 77.76 52.104 ;
    END
  END i[292]
  PIN i[293]
    DIRECTION INPUT ;
    USE SIGNAL ;
    PORT
      LAYER M4 ;
        RECT  77.568 52.224 77.76 52.248 ;
    END
  END i[293]
  PIN i[294]
    DIRECTION INPUT ;
    USE SIGNAL ;
    PORT
      LAYER M4 ;
        RECT  77.568 52.416 77.76 52.44 ;
    END
  END i[294]
  PIN i[295]
    DIRECTION INPUT ;
    USE SIGNAL ;
    PORT
      LAYER M4 ;
        RECT  77.568 52.56 77.76 52.584 ;
    END
  END i[295]
  PIN i[296]
    DIRECTION INPUT ;
    USE SIGNAL ;
    PORT
      LAYER M4 ;
        RECT  77.568 52.752 77.76 52.776 ;
    END
  END i[296]
  PIN i[297]
    DIRECTION INPUT ;
    USE SIGNAL ;
    PORT
      LAYER M4 ;
        RECT  77.568 52.896 77.76 52.92 ;
    END
  END i[297]
  PIN i[298]
    DIRECTION INPUT ;
    USE SIGNAL ;
    PORT
      LAYER M4 ;
        RECT  77.568 53.04 77.76 53.064 ;
    END
  END i[298]
  PIN i[299]
    DIRECTION INPUT ;
    USE SIGNAL ;
    PORT
      LAYER M4 ;
        RECT  77.568 53.232 77.76 53.256 ;
    END
  END i[299]
  PIN i[29]
    DIRECTION INPUT ;
    USE SIGNAL ;
    PORT
      LAYER M4 ;
        RECT  77.568 9.168 77.76 9.192 ;
    END
  END i[29]
  PIN i[2]
    DIRECTION INPUT ;
    USE SIGNAL ;
    PORT
      LAYER M4 ;
        RECT  77.568 4.752 77.76 4.776 ;
    END
  END i[2]
  PIN i[300]
    DIRECTION INPUT ;
    USE SIGNAL ;
    PORT
      LAYER M4 ;
        RECT  77.568 53.376 77.76 53.4 ;
    END
  END i[300]
  PIN i[301]
    DIRECTION INPUT ;
    USE SIGNAL ;
    PORT
      LAYER M4 ;
        RECT  77.568 53.568 77.76 53.592 ;
    END
  END i[301]
  PIN i[302]
    DIRECTION INPUT ;
    USE SIGNAL ;
    PORT
      LAYER M4 ;
        RECT  77.568 53.712 77.76 53.736 ;
    END
  END i[302]
  PIN i[303]
    DIRECTION INPUT ;
    USE SIGNAL ;
    PORT
      LAYER M4 ;
        RECT  77.568 53.904 77.76 53.928 ;
    END
  END i[303]
  PIN i[304]
    DIRECTION INPUT ;
    USE SIGNAL ;
    PORT
      LAYER M4 ;
        RECT  77.568 54.048 77.76 54.072 ;
    END
  END i[304]
  PIN i[305]
    DIRECTION INPUT ;
    USE SIGNAL ;
    PORT
      LAYER M4 ;
        RECT  77.568 54.192 77.76 54.216 ;
    END
  END i[305]
  PIN i[306]
    DIRECTION INPUT ;
    USE SIGNAL ;
    PORT
      LAYER M4 ;
        RECT  77.568 54.384 77.76 54.408 ;
    END
  END i[306]
  PIN i[307]
    DIRECTION INPUT ;
    USE SIGNAL ;
    PORT
      LAYER M4 ;
        RECT  77.568 54.528 77.76 54.552 ;
    END
  END i[307]
  PIN i[308]
    DIRECTION INPUT ;
    USE SIGNAL ;
    PORT
      LAYER M4 ;
        RECT  77.568 54.72 77.76 54.744 ;
    END
  END i[308]
  PIN i[309]
    DIRECTION INPUT ;
    USE SIGNAL ;
    PORT
      LAYER M4 ;
        RECT  77.568 54.864 77.76 54.888 ;
    END
  END i[309]
  PIN i[30]
    DIRECTION INPUT ;
    USE SIGNAL ;
    PORT
      LAYER M4 ;
        RECT  77.568 9.312 77.76 9.336 ;
    END
  END i[30]
  PIN i[310]
    DIRECTION INPUT ;
    USE SIGNAL ;
    PORT
      LAYER M4 ;
        RECT  77.568 55.008 77.76 55.032 ;
    END
  END i[310]
  PIN i[311]
    DIRECTION INPUT ;
    USE SIGNAL ;
    PORT
      LAYER M4 ;
        RECT  77.568 55.2 77.76 55.224 ;
    END
  END i[311]
  PIN i[312]
    DIRECTION INPUT ;
    USE SIGNAL ;
    PORT
      LAYER M4 ;
        RECT  77.568 55.344 77.76 55.368 ;
    END
  END i[312]
  PIN i[313]
    DIRECTION INPUT ;
    USE SIGNAL ;
    PORT
      LAYER M4 ;
        RECT  77.568 55.536 77.76 55.56 ;
    END
  END i[313]
  PIN i[314]
    DIRECTION INPUT ;
    USE SIGNAL ;
    PORT
      LAYER M4 ;
        RECT  77.568 55.68 77.76 55.704 ;
    END
  END i[314]
  PIN i[315]
    DIRECTION INPUT ;
    USE SIGNAL ;
    PORT
      LAYER M4 ;
        RECT  77.568 55.824 77.76 55.848 ;
    END
  END i[315]
  PIN i[316]
    DIRECTION INPUT ;
    USE SIGNAL ;
    PORT
      LAYER M4 ;
        RECT  77.568 56.016 77.76 56.04 ;
    END
  END i[316]
  PIN i[317]
    DIRECTION INPUT ;
    USE SIGNAL ;
    PORT
      LAYER M4 ;
        RECT  77.568 56.16 77.76 56.184 ;
    END
  END i[317]
  PIN i[318]
    DIRECTION INPUT ;
    USE SIGNAL ;
    PORT
      LAYER M4 ;
        RECT  77.568 56.352 77.76 56.376 ;
    END
  END i[318]
  PIN i[319]
    DIRECTION INPUT ;
    USE SIGNAL ;
    PORT
      LAYER M4 ;
        RECT  77.568 56.496 77.76 56.52 ;
    END
  END i[319]
  PIN i[31]
    DIRECTION INPUT ;
    USE SIGNAL ;
    PORT
      LAYER M4 ;
        RECT  77.568 9.456 77.76 9.48 ;
    END
  END i[31]
  PIN i[320]
    DIRECTION INPUT ;
    USE SIGNAL ;
    PORT
      LAYER M4 ;
        RECT  77.568 56.64 77.76 56.664 ;
    END
  END i[320]
  PIN i[321]
    DIRECTION INPUT ;
    USE SIGNAL ;
    PORT
      LAYER M4 ;
        RECT  77.568 56.832 77.76 56.856 ;
    END
  END i[321]
  PIN i[322]
    DIRECTION INPUT ;
    USE SIGNAL ;
    PORT
      LAYER M4 ;
        RECT  77.568 56.976 77.76 57 ;
    END
  END i[322]
  PIN i[323]
    DIRECTION INPUT ;
    USE SIGNAL ;
    PORT
      LAYER M4 ;
        RECT  77.568 57.168 77.76 57.192 ;
    END
  END i[323]
  PIN i[324]
    DIRECTION INPUT ;
    USE SIGNAL ;
    PORT
      LAYER M4 ;
        RECT  77.568 57.312 77.76 57.336 ;
    END
  END i[324]
  PIN i[325]
    DIRECTION INPUT ;
    USE SIGNAL ;
    PORT
      LAYER M4 ;
        RECT  77.568 57.456 77.76 57.48 ;
    END
  END i[325]
  PIN i[326]
    DIRECTION INPUT ;
    USE SIGNAL ;
    PORT
      LAYER M4 ;
        RECT  77.568 57.648 77.76 57.672 ;
    END
  END i[326]
  PIN i[327]
    DIRECTION INPUT ;
    USE SIGNAL ;
    PORT
      LAYER M4 ;
        RECT  77.568 57.792 77.76 57.816 ;
    END
  END i[327]
  PIN i[328]
    DIRECTION INPUT ;
    USE SIGNAL ;
    PORT
      LAYER M4 ;
        RECT  77.568 57.984 77.76 58.008 ;
    END
  END i[328]
  PIN i[329]
    DIRECTION INPUT ;
    USE SIGNAL ;
    PORT
      LAYER M4 ;
        RECT  77.568 58.128 77.76 58.152 ;
    END
  END i[329]
  PIN i[32]
    DIRECTION INPUT ;
    USE SIGNAL ;
    PORT
      LAYER M4 ;
        RECT  77.568 9.648 77.76 9.672 ;
    END
  END i[32]
  PIN i[330]
    DIRECTION INPUT ;
    USE SIGNAL ;
    PORT
      LAYER M4 ;
        RECT  77.568 58.272 77.76 58.296 ;
    END
  END i[330]
  PIN i[331]
    DIRECTION INPUT ;
    USE SIGNAL ;
    PORT
      LAYER M4 ;
        RECT  77.568 58.464 77.76 58.488 ;
    END
  END i[331]
  PIN i[332]
    DIRECTION INPUT ;
    USE SIGNAL ;
    PORT
      LAYER M4 ;
        RECT  77.568 58.608 77.76 58.632 ;
    END
  END i[332]
  PIN i[333]
    DIRECTION INPUT ;
    USE SIGNAL ;
    PORT
      LAYER M4 ;
        RECT  77.568 58.8 77.76 58.824 ;
    END
  END i[333]
  PIN i[334]
    DIRECTION INPUT ;
    USE SIGNAL ;
    PORT
      LAYER M4 ;
        RECT  77.568 58.944 77.76 58.968 ;
    END
  END i[334]
  PIN i[335]
    DIRECTION INPUT ;
    USE SIGNAL ;
    PORT
      LAYER M4 ;
        RECT  77.568 59.088 77.76 59.112 ;
    END
  END i[335]
  PIN i[336]
    DIRECTION INPUT ;
    USE SIGNAL ;
    PORT
      LAYER M4 ;
        RECT  77.568 59.28 77.76 59.304 ;
    END
  END i[336]
  PIN i[337]
    DIRECTION INPUT ;
    USE SIGNAL ;
    PORT
      LAYER M4 ;
        RECT  77.568 59.424 77.76 59.448 ;
    END
  END i[337]
  PIN i[338]
    DIRECTION INPUT ;
    USE SIGNAL ;
    PORT
      LAYER M4 ;
        RECT  77.568 59.616 77.76 59.64 ;
    END
  END i[338]
  PIN i[339]
    DIRECTION INPUT ;
    USE SIGNAL ;
    PORT
      LAYER M4 ;
        RECT  77.568 59.76 77.76 59.784 ;
    END
  END i[339]
  PIN i[33]
    DIRECTION INPUT ;
    USE SIGNAL ;
    PORT
      LAYER M4 ;
        RECT  77.568 9.792 77.76 9.816 ;
    END
  END i[33]
  PIN i[340]
    DIRECTION INPUT ;
    USE SIGNAL ;
    PORT
      LAYER M4 ;
        RECT  77.568 59.904 77.76 59.928 ;
    END
  END i[340]
  PIN i[341]
    DIRECTION INPUT ;
    USE SIGNAL ;
    PORT
      LAYER M4 ;
        RECT  77.568 60.096 77.76 60.12 ;
    END
  END i[341]
  PIN i[342]
    DIRECTION INPUT ;
    USE SIGNAL ;
    PORT
      LAYER M4 ;
        RECT  77.568 60.24 77.76 60.264 ;
    END
  END i[342]
  PIN i[343]
    DIRECTION INPUT ;
    USE SIGNAL ;
    PORT
      LAYER M4 ;
        RECT  77.568 60.432 77.76 60.456 ;
    END
  END i[343]
  PIN i[344]
    DIRECTION INPUT ;
    USE SIGNAL ;
    PORT
      LAYER M4 ;
        RECT  77.568 60.576 77.76 60.6 ;
    END
  END i[344]
  PIN i[345]
    DIRECTION INPUT ;
    USE SIGNAL ;
    PORT
      LAYER M4 ;
        RECT  77.568 60.72 77.76 60.744 ;
    END
  END i[345]
  PIN i[346]
    DIRECTION INPUT ;
    USE SIGNAL ;
    PORT
      LAYER M4 ;
        RECT  77.568 60.912 77.76 60.936 ;
    END
  END i[346]
  PIN i[347]
    DIRECTION INPUT ;
    USE SIGNAL ;
    PORT
      LAYER M4 ;
        RECT  77.568 61.056 77.76 61.08 ;
    END
  END i[347]
  PIN i[348]
    DIRECTION INPUT ;
    USE SIGNAL ;
    PORT
      LAYER M4 ;
        RECT  77.568 61.248 77.76 61.272 ;
    END
  END i[348]
  PIN i[349]
    DIRECTION INPUT ;
    USE SIGNAL ;
    PORT
      LAYER M4 ;
        RECT  77.568 61.392 77.76 61.416 ;
    END
  END i[349]
  PIN i[34]
    DIRECTION INPUT ;
    USE SIGNAL ;
    PORT
      LAYER M4 ;
        RECT  77.568 9.984 77.76 10.008 ;
    END
  END i[34]
  PIN i[350]
    DIRECTION INPUT ;
    USE SIGNAL ;
    PORT
      LAYER M4 ;
        RECT  77.568 61.536 77.76 61.56 ;
    END
  END i[350]
  PIN i[351]
    DIRECTION INPUT ;
    USE SIGNAL ;
    PORT
      LAYER M4 ;
        RECT  77.568 61.728 77.76 61.752 ;
    END
  END i[351]
  PIN i[352]
    DIRECTION INPUT ;
    USE SIGNAL ;
    PORT
      LAYER M4 ;
        RECT  77.568 61.872 77.76 61.896 ;
    END
  END i[352]
  PIN i[353]
    DIRECTION INPUT ;
    USE SIGNAL ;
    PORT
      LAYER M4 ;
        RECT  77.568 62.064 77.76 62.088 ;
    END
  END i[353]
  PIN i[354]
    DIRECTION INPUT ;
    USE SIGNAL ;
    PORT
      LAYER M4 ;
        RECT  77.568 62.208 77.76 62.232 ;
    END
  END i[354]
  PIN i[355]
    DIRECTION INPUT ;
    USE SIGNAL ;
    PORT
      LAYER M4 ;
        RECT  77.568 62.352 77.76 62.376 ;
    END
  END i[355]
  PIN i[356]
    DIRECTION INPUT ;
    USE SIGNAL ;
    PORT
      LAYER M4 ;
        RECT  77.568 62.544 77.76 62.568 ;
    END
  END i[356]
  PIN i[357]
    DIRECTION INPUT ;
    USE SIGNAL ;
    PORT
      LAYER M4 ;
        RECT  77.568 62.688 77.76 62.712 ;
    END
  END i[357]
  PIN i[358]
    DIRECTION INPUT ;
    USE SIGNAL ;
    PORT
      LAYER M4 ;
        RECT  77.568 62.88 77.76 62.904 ;
    END
  END i[358]
  PIN i[359]
    DIRECTION INPUT ;
    USE SIGNAL ;
    PORT
      LAYER M4 ;
        RECT  77.568 63.024 77.76 63.048 ;
    END
  END i[359]
  PIN i[35]
    DIRECTION INPUT ;
    USE SIGNAL ;
    PORT
      LAYER M4 ;
        RECT  77.568 10.128 77.76 10.152 ;
    END
  END i[35]
  PIN i[360]
    DIRECTION INPUT ;
    USE SIGNAL ;
    PORT
      LAYER M4 ;
        RECT  77.568 63.168 77.76 63.192 ;
    END
  END i[360]
  PIN i[361]
    DIRECTION INPUT ;
    USE SIGNAL ;
    PORT
      LAYER M4 ;
        RECT  77.568 63.36 77.76 63.384 ;
    END
  END i[361]
  PIN i[362]
    DIRECTION INPUT ;
    USE SIGNAL ;
    PORT
      LAYER M4 ;
        RECT  77.568 63.504 77.76 63.528 ;
    END
  END i[362]
  PIN i[363]
    DIRECTION INPUT ;
    USE SIGNAL ;
    PORT
      LAYER M4 ;
        RECT  77.568 63.696 77.76 63.72 ;
    END
  END i[363]
  PIN i[364]
    DIRECTION INPUT ;
    USE SIGNAL ;
    PORT
      LAYER M4 ;
        RECT  77.568 63.84 77.76 63.864 ;
    END
  END i[364]
  PIN i[365]
    DIRECTION INPUT ;
    USE SIGNAL ;
    PORT
      LAYER M4 ;
        RECT  77.568 63.984 77.76 64.008 ;
    END
  END i[365]
  PIN i[366]
    DIRECTION INPUT ;
    USE SIGNAL ;
    PORT
      LAYER M4 ;
        RECT  77.568 64.176 77.76 64.2 ;
    END
  END i[366]
  PIN i[367]
    DIRECTION INPUT ;
    USE SIGNAL ;
    PORT
      LAYER M4 ;
        RECT  77.568 64.32 77.76 64.344 ;
    END
  END i[367]
  PIN i[368]
    DIRECTION INPUT ;
    USE SIGNAL ;
    PORT
      LAYER M4 ;
        RECT  77.568 64.512 77.76 64.536 ;
    END
  END i[368]
  PIN i[369]
    DIRECTION INPUT ;
    USE SIGNAL ;
    PORT
      LAYER M4 ;
        RECT  77.568 64.656 77.76 64.68 ;
    END
  END i[369]
  PIN i[36]
    DIRECTION INPUT ;
    USE SIGNAL ;
    PORT
      LAYER M4 ;
        RECT  77.568 10.272 77.76 10.296 ;
    END
  END i[36]
  PIN i[370]
    DIRECTION INPUT ;
    USE SIGNAL ;
    PORT
      LAYER M4 ;
        RECT  77.568 64.8 77.76 64.824 ;
    END
  END i[370]
  PIN i[371]
    DIRECTION INPUT ;
    USE SIGNAL ;
    PORT
      LAYER M4 ;
        RECT  77.568 64.992 77.76 65.016 ;
    END
  END i[371]
  PIN i[372]
    DIRECTION INPUT ;
    USE SIGNAL ;
    PORT
      LAYER M4 ;
        RECT  77.568 65.136 77.76 65.16 ;
    END
  END i[372]
  PIN i[373]
    DIRECTION INPUT ;
    USE SIGNAL ;
    PORT
      LAYER M4 ;
        RECT  77.568 65.328 77.76 65.352 ;
    END
  END i[373]
  PIN i[374]
    DIRECTION INPUT ;
    USE SIGNAL ;
    PORT
      LAYER M4 ;
        RECT  77.568 65.472 77.76 65.496 ;
    END
  END i[374]
  PIN i[375]
    DIRECTION INPUT ;
    USE SIGNAL ;
    PORT
      LAYER M4 ;
        RECT  77.568 65.616 77.76 65.64 ;
    END
  END i[375]
  PIN i[376]
    DIRECTION INPUT ;
    USE SIGNAL ;
    PORT
      LAYER M4 ;
        RECT  77.568 65.808 77.76 65.832 ;
    END
  END i[376]
  PIN i[377]
    DIRECTION INPUT ;
    USE SIGNAL ;
    PORT
      LAYER M4 ;
        RECT  77.568 65.952 77.76 65.976 ;
    END
  END i[377]
  PIN i[378]
    DIRECTION INPUT ;
    USE SIGNAL ;
    PORT
      LAYER M4 ;
        RECT  77.568 66.144 77.76 66.168 ;
    END
  END i[378]
  PIN i[379]
    DIRECTION INPUT ;
    USE SIGNAL ;
    PORT
      LAYER M4 ;
        RECT  77.568 66.288 77.76 66.312 ;
    END
  END i[379]
  PIN i[37]
    DIRECTION INPUT ;
    USE SIGNAL ;
    PORT
      LAYER M4 ;
        RECT  77.568 10.464 77.76 10.488 ;
    END
  END i[37]
  PIN i[380]
    DIRECTION INPUT ;
    USE SIGNAL ;
    PORT
      LAYER M4 ;
        RECT  77.568 66.432 77.76 66.456 ;
    END
  END i[380]
  PIN i[381]
    DIRECTION INPUT ;
    USE SIGNAL ;
    PORT
      LAYER M4 ;
        RECT  77.568 66.624 77.76 66.648 ;
    END
  END i[381]
  PIN i[382]
    DIRECTION INPUT ;
    USE SIGNAL ;
    PORT
      LAYER M4 ;
        RECT  77.568 66.768 77.76 66.792 ;
    END
  END i[382]
  PIN i[383]
    DIRECTION INPUT ;
    USE SIGNAL ;
    PORT
      LAYER M4 ;
        RECT  77.568 66.96 77.76 66.984 ;
    END
  END i[383]
  PIN i[384]
    DIRECTION INPUT ;
    USE SIGNAL ;
    PORT
      LAYER M4 ;
        RECT  77.568 67.104 77.76 67.128 ;
    END
  END i[384]
  PIN i[385]
    DIRECTION INPUT ;
    USE SIGNAL ;
    PORT
      LAYER M4 ;
        RECT  77.568 67.248 77.76 67.272 ;
    END
  END i[385]
  PIN i[386]
    DIRECTION INPUT ;
    USE SIGNAL ;
    PORT
      LAYER M4 ;
        RECT  77.568 67.44 77.76 67.464 ;
    END
  END i[386]
  PIN i[387]
    DIRECTION INPUT ;
    USE SIGNAL ;
    PORT
      LAYER M4 ;
        RECT  77.568 67.584 77.76 67.608 ;
    END
  END i[387]
  PIN i[388]
    DIRECTION INPUT ;
    USE SIGNAL ;
    PORT
      LAYER M4 ;
        RECT  77.568 67.776 77.76 67.8 ;
    END
  END i[388]
  PIN i[389]
    DIRECTION INPUT ;
    USE SIGNAL ;
    PORT
      LAYER M4 ;
        RECT  77.568 67.92 77.76 67.944 ;
    END
  END i[389]
  PIN i[38]
    DIRECTION INPUT ;
    USE SIGNAL ;
    PORT
      LAYER M4 ;
        RECT  77.568 10.608 77.76 10.632 ;
    END
  END i[38]
  PIN i[390]
    DIRECTION INPUT ;
    USE SIGNAL ;
    PORT
      LAYER M4 ;
        RECT  77.568 68.064 77.76 68.088 ;
    END
  END i[390]
  PIN i[391]
    DIRECTION INPUT ;
    USE SIGNAL ;
    PORT
      LAYER M4 ;
        RECT  77.568 68.256 77.76 68.28 ;
    END
  END i[391]
  PIN i[392]
    DIRECTION INPUT ;
    USE SIGNAL ;
    PORT
      LAYER M4 ;
        RECT  77.568 68.4 77.76 68.424 ;
    END
  END i[392]
  PIN i[393]
    DIRECTION INPUT ;
    USE SIGNAL ;
    PORT
      LAYER M4 ;
        RECT  77.568 68.592 77.76 68.616 ;
    END
  END i[393]
  PIN i[394]
    DIRECTION INPUT ;
    USE SIGNAL ;
    PORT
      LAYER M4 ;
        RECT  77.568 68.736 77.76 68.76 ;
    END
  END i[394]
  PIN i[395]
    DIRECTION INPUT ;
    USE SIGNAL ;
    PORT
      LAYER M4 ;
        RECT  77.568 68.88 77.76 68.904 ;
    END
  END i[395]
  PIN i[396]
    DIRECTION INPUT ;
    USE SIGNAL ;
    PORT
      LAYER M4 ;
        RECT  77.568 69.072 77.76 69.096 ;
    END
  END i[396]
  PIN i[397]
    DIRECTION INPUT ;
    USE SIGNAL ;
    PORT
      LAYER M4 ;
        RECT  77.568 69.216 77.76 69.24 ;
    END
  END i[397]
  PIN i[398]
    DIRECTION INPUT ;
    USE SIGNAL ;
    PORT
      LAYER M4 ;
        RECT  77.568 69.408 77.76 69.432 ;
    END
  END i[398]
  PIN i[399]
    DIRECTION INPUT ;
    USE SIGNAL ;
    PORT
      LAYER M4 ;
        RECT  77.568 69.552 77.76 69.576 ;
    END
  END i[399]
  PIN i[39]
    DIRECTION INPUT ;
    USE SIGNAL ;
    PORT
      LAYER M4 ;
        RECT  77.568 10.8 77.76 10.824 ;
    END
  END i[39]
  PIN i[3]
    DIRECTION INPUT ;
    USE SIGNAL ;
    PORT
      LAYER M4 ;
        RECT  77.568 4.896 77.76 4.92 ;
    END
  END i[3]
  PIN i[400]
    DIRECTION INPUT ;
    USE SIGNAL ;
    PORT
      LAYER M4 ;
        RECT  77.568 69.696 77.76 69.72 ;
    END
  END i[400]
  PIN i[401]
    DIRECTION INPUT ;
    USE SIGNAL ;
    PORT
      LAYER M4 ;
        RECT  77.568 69.888 77.76 69.912 ;
    END
  END i[401]
  PIN i[402]
    DIRECTION INPUT ;
    USE SIGNAL ;
    PORT
      LAYER M4 ;
        RECT  77.568 70.032 77.76 70.056 ;
    END
  END i[402]
  PIN i[403]
    DIRECTION INPUT ;
    USE SIGNAL ;
    PORT
      LAYER M4 ;
        RECT  77.568 70.224 77.76 70.248 ;
    END
  END i[403]
  PIN i[404]
    DIRECTION INPUT ;
    USE SIGNAL ;
    PORT
      LAYER M4 ;
        RECT  77.568 70.368 77.76 70.392 ;
    END
  END i[404]
  PIN i[405]
    DIRECTION INPUT ;
    USE SIGNAL ;
    PORT
      LAYER M4 ;
        RECT  77.568 70.512 77.76 70.536 ;
    END
  END i[405]
  PIN i[406]
    DIRECTION INPUT ;
    USE SIGNAL ;
    PORT
      LAYER M4 ;
        RECT  77.568 70.704 77.76 70.728 ;
    END
  END i[406]
  PIN i[407]
    DIRECTION INPUT ;
    USE SIGNAL ;
    PORT
      LAYER M4 ;
        RECT  77.568 70.848 77.76 70.872 ;
    END
  END i[407]
  PIN i[408]
    DIRECTION INPUT ;
    USE SIGNAL ;
    PORT
      LAYER M4 ;
        RECT  77.568 71.04 77.76 71.064 ;
    END
  END i[408]
  PIN i[409]
    DIRECTION INPUT ;
    USE SIGNAL ;
    PORT
      LAYER M4 ;
        RECT  77.568 71.184 77.76 71.208 ;
    END
  END i[409]
  PIN i[40]
    DIRECTION INPUT ;
    USE SIGNAL ;
    PORT
      LAYER M4 ;
        RECT  77.568 10.944 77.76 10.968 ;
    END
  END i[40]
  PIN i[410]
    DIRECTION INPUT ;
    USE SIGNAL ;
    PORT
      LAYER M4 ;
        RECT  77.568 71.328 77.76 71.352 ;
    END
  END i[410]
  PIN i[411]
    DIRECTION INPUT ;
    USE SIGNAL ;
    PORT
      LAYER M4 ;
        RECT  77.568 71.52 77.76 71.544 ;
    END
  END i[411]
  PIN i[412]
    DIRECTION INPUT ;
    USE SIGNAL ;
    PORT
      LAYER M4 ;
        RECT  77.568 71.664 77.76 71.688 ;
    END
  END i[412]
  PIN i[413]
    DIRECTION INPUT ;
    USE SIGNAL ;
    PORT
      LAYER M4 ;
        RECT  77.568 71.856 77.76 71.88 ;
    END
  END i[413]
  PIN i[414]
    DIRECTION INPUT ;
    USE SIGNAL ;
    PORT
      LAYER M4 ;
        RECT  77.568 72 77.76 72.024 ;
    END
  END i[414]
  PIN i[415]
    DIRECTION INPUT ;
    USE SIGNAL ;
    PORT
      LAYER M4 ;
        RECT  77.568 72.144 77.76 72.168 ;
    END
  END i[415]
  PIN i[416]
    DIRECTION INPUT ;
    USE SIGNAL ;
    PORT
      LAYER M4 ;
        RECT  77.568 72.336 77.76 72.36 ;
    END
  END i[416]
  PIN i[417]
    DIRECTION INPUT ;
    USE SIGNAL ;
    PORT
      LAYER M4 ;
        RECT  77.568 72.48 77.76 72.504 ;
    END
  END i[417]
  PIN i[418]
    DIRECTION INPUT ;
    USE SIGNAL ;
    PORT
      LAYER M4 ;
        RECT  77.568 72.672 77.76 72.696 ;
    END
  END i[418]
  PIN i[419]
    DIRECTION INPUT ;
    USE SIGNAL ;
    PORT
      LAYER M4 ;
        RECT  77.568 72.816 77.76 72.84 ;
    END
  END i[419]
  PIN i[41]
    DIRECTION INPUT ;
    USE SIGNAL ;
    PORT
      LAYER M4 ;
        RECT  77.568 11.088 77.76 11.112 ;
    END
  END i[41]
  PIN i[420]
    DIRECTION INPUT ;
    USE SIGNAL ;
    PORT
      LAYER M4 ;
        RECT  77.568 72.96 77.76 72.984 ;
    END
  END i[420]
  PIN i[421]
    DIRECTION INPUT ;
    USE SIGNAL ;
    PORT
      LAYER M4 ;
        RECT  77.568 73.152 77.76 73.176 ;
    END
  END i[421]
  PIN i[422]
    DIRECTION INPUT ;
    USE SIGNAL ;
    PORT
      LAYER M4 ;
        RECT  77.568 73.296 77.76 73.32 ;
    END
  END i[422]
  PIN i[423]
    DIRECTION INPUT ;
    USE SIGNAL ;
    PORT
      LAYER M4 ;
        RECT  77.568 73.488 77.76 73.512 ;
    END
  END i[423]
  PIN i[424]
    DIRECTION INPUT ;
    USE SIGNAL ;
    PORT
      LAYER M4 ;
        RECT  77.568 73.632 77.76 73.656 ;
    END
  END i[424]
  PIN i[425]
    DIRECTION INPUT ;
    USE SIGNAL ;
    PORT
      LAYER M4 ;
        RECT  77.568 73.776 77.76 73.8 ;
    END
  END i[425]
  PIN i[426]
    DIRECTION INPUT ;
    USE SIGNAL ;
    PORT
      LAYER M4 ;
        RECT  77.568 73.968 77.76 73.992 ;
    END
  END i[426]
  PIN i[427]
    DIRECTION INPUT ;
    USE SIGNAL ;
    PORT
      LAYER M4 ;
        RECT  77.568 74.112 77.76 74.136 ;
    END
  END i[427]
  PIN i[428]
    DIRECTION INPUT ;
    USE SIGNAL ;
    PORT
      LAYER M4 ;
        RECT  77.568 74.304 77.76 74.328 ;
    END
  END i[428]
  PIN i[429]
    DIRECTION INPUT ;
    USE SIGNAL ;
    PORT
      LAYER M4 ;
        RECT  77.568 74.448 77.76 74.472 ;
    END
  END i[429]
  PIN i[42]
    DIRECTION INPUT ;
    USE SIGNAL ;
    PORT
      LAYER M4 ;
        RECT  77.568 11.28 77.76 11.304 ;
    END
  END i[42]
  PIN i[430]
    DIRECTION INPUT ;
    USE SIGNAL ;
    PORT
      LAYER M4 ;
        RECT  77.568 74.592 77.76 74.616 ;
    END
  END i[430]
  PIN i[431]
    DIRECTION INPUT ;
    USE SIGNAL ;
    PORT
      LAYER M4 ;
        RECT  77.568 74.784 77.76 74.808 ;
    END
  END i[431]
  PIN i[432]
    DIRECTION INPUT ;
    USE SIGNAL ;
    PORT
      LAYER M4 ;
        RECT  77.568 74.928 77.76 74.952 ;
    END
  END i[432]
  PIN i[433]
    DIRECTION INPUT ;
    USE SIGNAL ;
    PORT
      LAYER M4 ;
        RECT  77.568 75.12 77.76 75.144 ;
    END
  END i[433]
  PIN i[434]
    DIRECTION INPUT ;
    USE SIGNAL ;
    PORT
      LAYER M4 ;
        RECT  77.568 75.264 77.76 75.288 ;
    END
  END i[434]
  PIN i[435]
    DIRECTION INPUT ;
    USE SIGNAL ;
    PORT
      LAYER M4 ;
        RECT  77.568 75.408 77.76 75.432 ;
    END
  END i[435]
  PIN i[436]
    DIRECTION INPUT ;
    USE SIGNAL ;
    PORT
      LAYER M4 ;
        RECT  77.568 75.6 77.76 75.624 ;
    END
  END i[436]
  PIN i[437]
    DIRECTION INPUT ;
    USE SIGNAL ;
    PORT
      LAYER M4 ;
        RECT  77.568 75.744 77.76 75.768 ;
    END
  END i[437]
  PIN i[438]
    DIRECTION INPUT ;
    USE SIGNAL ;
    PORT
      LAYER M4 ;
        RECT  77.568 75.936 77.76 75.96 ;
    END
  END i[438]
  PIN i[439]
    DIRECTION INPUT ;
    USE SIGNAL ;
    PORT
      LAYER M4 ;
        RECT  77.568 76.08 77.76 76.104 ;
    END
  END i[439]
  PIN i[43]
    DIRECTION INPUT ;
    USE SIGNAL ;
    PORT
      LAYER M4 ;
        RECT  77.568 11.424 77.76 11.448 ;
    END
  END i[43]
  PIN i[440]
    DIRECTION INPUT ;
    USE SIGNAL ;
    PORT
      LAYER M4 ;
        RECT  77.568 76.224 77.76 76.248 ;
    END
  END i[440]
  PIN i[441]
    DIRECTION INPUT ;
    USE SIGNAL ;
    PORT
      LAYER M4 ;
        RECT  77.568 76.416 77.76 76.44 ;
    END
  END i[441]
  PIN i[442]
    DIRECTION INPUT ;
    USE SIGNAL ;
    PORT
      LAYER M4 ;
        RECT  77.568 76.56 77.76 76.584 ;
    END
  END i[442]
  PIN i[443]
    DIRECTION INPUT ;
    USE SIGNAL ;
    PORT
      LAYER M4 ;
        RECT  77.568 76.752 77.76 76.776 ;
    END
  END i[443]
  PIN i[444]
    DIRECTION INPUT ;
    USE SIGNAL ;
    PORT
      LAYER M4 ;
        RECT  77.568 76.896 77.76 76.92 ;
    END
  END i[444]
  PIN i[445]
    DIRECTION INPUT ;
    USE SIGNAL ;
    PORT
      LAYER M4 ;
        RECT  77.568 77.04 77.76 77.064 ;
    END
  END i[445]
  PIN i[446]
    DIRECTION INPUT ;
    USE SIGNAL ;
    PORT
      LAYER M4 ;
        RECT  77.568 77.232 77.76 77.256 ;
    END
  END i[446]
  PIN i[447]
    DIRECTION INPUT ;
    USE SIGNAL ;
    PORT
      LAYER M4 ;
        RECT  77.568 77.376 77.76 77.4 ;
    END
  END i[447]
  PIN i[448]
    DIRECTION INPUT ;
    USE SIGNAL ;
    PORT
      LAYER M4 ;
        RECT  77.568 77.568 77.76 77.592 ;
    END
  END i[448]
  PIN i[449]
    DIRECTION INPUT ;
    USE SIGNAL ;
    PORT
      LAYER M4 ;
        RECT  77.568 77.712 77.76 77.736 ;
    END
  END i[449]
  PIN i[44]
    DIRECTION INPUT ;
    USE SIGNAL ;
    PORT
      LAYER M4 ;
        RECT  77.568 11.616 77.76 11.64 ;
    END
  END i[44]
  PIN i[450]
    DIRECTION INPUT ;
    USE SIGNAL ;
    PORT
      LAYER M4 ;
        RECT  77.568 77.856 77.76 77.88 ;
    END
  END i[450]
  PIN i[451]
    DIRECTION INPUT ;
    USE SIGNAL ;
    PORT
      LAYER M4 ;
        RECT  77.568 78.048 77.76 78.072 ;
    END
  END i[451]
  PIN i[452]
    DIRECTION INPUT ;
    USE SIGNAL ;
    PORT
      LAYER M4 ;
        RECT  77.568 78.192 77.76 78.216 ;
    END
  END i[452]
  PIN i[453]
    DIRECTION INPUT ;
    USE SIGNAL ;
    PORT
      LAYER M4 ;
        RECT  77.568 78.384 77.76 78.408 ;
    END
  END i[453]
  PIN i[454]
    DIRECTION INPUT ;
    USE SIGNAL ;
    PORT
      LAYER M4 ;
        RECT  77.568 78.528 77.76 78.552 ;
    END
  END i[454]
  PIN i[455]
    DIRECTION INPUT ;
    USE SIGNAL ;
    PORT
      LAYER M4 ;
        RECT  77.568 78.672 77.76 78.696 ;
    END
  END i[455]
  PIN i[456]
    DIRECTION INPUT ;
    USE SIGNAL ;
    PORT
      LAYER M4 ;
        RECT  77.568 78.864 77.76 78.888 ;
    END
  END i[456]
  PIN i[457]
    DIRECTION INPUT ;
    USE SIGNAL ;
    PORT
      LAYER M4 ;
        RECT  77.568 79.008 77.76 79.032 ;
    END
  END i[457]
  PIN i[458]
    DIRECTION INPUT ;
    USE SIGNAL ;
    PORT
      LAYER M4 ;
        RECT  77.568 79.2 77.76 79.224 ;
    END
  END i[458]
  PIN i[459]
    DIRECTION INPUT ;
    USE SIGNAL ;
    PORT
      LAYER M4 ;
        RECT  77.568 79.344 77.76 79.368 ;
    END
  END i[459]
  PIN i[45]
    DIRECTION INPUT ;
    USE SIGNAL ;
    PORT
      LAYER M4 ;
        RECT  77.568 11.76 77.76 11.784 ;
    END
  END i[45]
  PIN i[460]
    DIRECTION INPUT ;
    USE SIGNAL ;
    PORT
      LAYER M4 ;
        RECT  77.568 79.488 77.76 79.512 ;
    END
  END i[460]
  PIN i[461]
    DIRECTION INPUT ;
    USE SIGNAL ;
    PORT
      LAYER M4 ;
        RECT  77.568 79.68 77.76 79.704 ;
    END
  END i[461]
  PIN i[462]
    DIRECTION INPUT ;
    USE SIGNAL ;
    PORT
      LAYER M4 ;
        RECT  77.568 79.824 77.76 79.848 ;
    END
  END i[462]
  PIN i[463]
    DIRECTION INPUT ;
    USE SIGNAL ;
    PORT
      LAYER M4 ;
        RECT  77.568 80.016 77.76 80.04 ;
    END
  END i[463]
  PIN i[464]
    DIRECTION INPUT ;
    USE SIGNAL ;
    PORT
      LAYER M4 ;
        RECT  77.568 80.16 77.76 80.184 ;
    END
  END i[464]
  PIN i[465]
    DIRECTION INPUT ;
    USE SIGNAL ;
    PORT
      LAYER M4 ;
        RECT  77.568 80.304 77.76 80.328 ;
    END
  END i[465]
  PIN i[466]
    DIRECTION INPUT ;
    USE SIGNAL ;
    PORT
      LAYER M4 ;
        RECT  77.568 80.496 77.76 80.52 ;
    END
  END i[466]
  PIN i[467]
    DIRECTION INPUT ;
    USE SIGNAL ;
    PORT
      LAYER M4 ;
        RECT  77.568 80.64 77.76 80.664 ;
    END
  END i[467]
  PIN i[468]
    DIRECTION INPUT ;
    USE SIGNAL ;
    PORT
      LAYER M4 ;
        RECT  77.568 80.832 77.76 80.856 ;
    END
  END i[468]
  PIN i[469]
    DIRECTION INPUT ;
    USE SIGNAL ;
    PORT
      LAYER M4 ;
        RECT  77.568 80.976 77.76 81 ;
    END
  END i[469]
  PIN i[46]
    DIRECTION INPUT ;
    USE SIGNAL ;
    PORT
      LAYER M4 ;
        RECT  77.568 11.904 77.76 11.928 ;
    END
  END i[46]
  PIN i[470]
    DIRECTION INPUT ;
    USE SIGNAL ;
    PORT
      LAYER M4 ;
        RECT  77.568 81.12 77.76 81.144 ;
    END
  END i[470]
  PIN i[471]
    DIRECTION INPUT ;
    USE SIGNAL ;
    PORT
      LAYER M4 ;
        RECT  77.568 81.312 77.76 81.336 ;
    END
  END i[471]
  PIN i[472]
    DIRECTION INPUT ;
    USE SIGNAL ;
    PORT
      LAYER M4 ;
        RECT  77.568 81.456 77.76 81.48 ;
    END
  END i[472]
  PIN i[473]
    DIRECTION INPUT ;
    USE SIGNAL ;
    PORT
      LAYER M4 ;
        RECT  77.568 81.648 77.76 81.672 ;
    END
  END i[473]
  PIN i[474]
    DIRECTION INPUT ;
    USE SIGNAL ;
    PORT
      LAYER M4 ;
        RECT  77.568 81.792 77.76 81.816 ;
    END
  END i[474]
  PIN i[475]
    DIRECTION INPUT ;
    USE SIGNAL ;
    PORT
      LAYER M4 ;
        RECT  77.568 81.984 77.76 82.008 ;
    END
  END i[475]
  PIN i[476]
    DIRECTION INPUT ;
    USE SIGNAL ;
    PORT
      LAYER M4 ;
        RECT  77.568 82.128 77.76 82.152 ;
    END
  END i[476]
  PIN i[477]
    DIRECTION INPUT ;
    USE SIGNAL ;
    PORT
      LAYER M4 ;
        RECT  77.568 82.272 77.76 82.296 ;
    END
  END i[477]
  PIN i[478]
    DIRECTION INPUT ;
    USE SIGNAL ;
    PORT
      LAYER M4 ;
        RECT  77.568 82.464 77.76 82.488 ;
    END
  END i[478]
  PIN i[479]
    DIRECTION INPUT ;
    USE SIGNAL ;
    PORT
      LAYER M4 ;
        RECT  77.568 82.608 77.76 82.632 ;
    END
  END i[479]
  PIN i[47]
    DIRECTION INPUT ;
    USE SIGNAL ;
    PORT
      LAYER M4 ;
        RECT  77.568 12.096 77.76 12.12 ;
    END
  END i[47]
  PIN i[480]
    DIRECTION INPUT ;
    USE SIGNAL ;
    PORT
      LAYER M4 ;
        RECT  77.568 82.8 77.76 82.824 ;
    END
  END i[480]
  PIN i[481]
    DIRECTION INPUT ;
    USE SIGNAL ;
    PORT
      LAYER M4 ;
        RECT  77.568 82.944 77.76 82.968 ;
    END
  END i[481]
  PIN i[482]
    DIRECTION INPUT ;
    USE SIGNAL ;
    PORT
      LAYER M4 ;
        RECT  77.568 83.088 77.76 83.112 ;
    END
  END i[482]
  PIN i[483]
    DIRECTION INPUT ;
    USE SIGNAL ;
    PORT
      LAYER M4 ;
        RECT  77.568 83.28 77.76 83.304 ;
    END
  END i[483]
  PIN i[484]
    DIRECTION INPUT ;
    USE SIGNAL ;
    PORT
      LAYER M4 ;
        RECT  77.568 83.424 77.76 83.448 ;
    END
  END i[484]
  PIN i[485]
    DIRECTION INPUT ;
    USE SIGNAL ;
    PORT
      LAYER M4 ;
        RECT  77.568 83.616 77.76 83.64 ;
    END
  END i[485]
  PIN i[486]
    DIRECTION INPUT ;
    USE SIGNAL ;
    PORT
      LAYER M4 ;
        RECT  77.568 83.76 77.76 83.784 ;
    END
  END i[486]
  PIN i[487]
    DIRECTION INPUT ;
    USE SIGNAL ;
    PORT
      LAYER M4 ;
        RECT  77.568 83.904 77.76 83.928 ;
    END
  END i[487]
  PIN i[488]
    DIRECTION INPUT ;
    USE SIGNAL ;
    PORT
      LAYER M4 ;
        RECT  77.568 84.096 77.76 84.12 ;
    END
  END i[488]
  PIN i[489]
    DIRECTION INPUT ;
    USE SIGNAL ;
    PORT
      LAYER M4 ;
        RECT  77.568 84.24 77.76 84.264 ;
    END
  END i[489]
  PIN i[48]
    DIRECTION INPUT ;
    USE SIGNAL ;
    PORT
      LAYER M4 ;
        RECT  77.568 12.24 77.76 12.264 ;
    END
  END i[48]
  PIN i[490]
    DIRECTION INPUT ;
    USE SIGNAL ;
    PORT
      LAYER M4 ;
        RECT  77.568 84.432 77.76 84.456 ;
    END
  END i[490]
  PIN i[491]
    DIRECTION INPUT ;
    USE SIGNAL ;
    PORT
      LAYER M4 ;
        RECT  77.568 84.576 77.76 84.6 ;
    END
  END i[491]
  PIN i[492]
    DIRECTION INPUT ;
    USE SIGNAL ;
    PORT
      LAYER M4 ;
        RECT  77.568 84.72 77.76 84.744 ;
    END
  END i[492]
  PIN i[493]
    DIRECTION INPUT ;
    USE SIGNAL ;
    PORT
      LAYER M4 ;
        RECT  77.568 84.912 77.76 84.936 ;
    END
  END i[493]
  PIN i[494]
    DIRECTION INPUT ;
    USE SIGNAL ;
    PORT
      LAYER M4 ;
        RECT  77.568 85.056 77.76 85.08 ;
    END
  END i[494]
  PIN i[495]
    DIRECTION INPUT ;
    USE SIGNAL ;
    PORT
      LAYER M4 ;
        RECT  77.568 85.248 77.76 85.272 ;
    END
  END i[495]
  PIN i[496]
    DIRECTION INPUT ;
    USE SIGNAL ;
    PORT
      LAYER M4 ;
        RECT  77.568 85.392 77.76 85.416 ;
    END
  END i[496]
  PIN i[497]
    DIRECTION INPUT ;
    USE SIGNAL ;
    PORT
      LAYER M4 ;
        RECT  77.568 85.536 77.76 85.56 ;
    END
  END i[497]
  PIN i[498]
    DIRECTION INPUT ;
    USE SIGNAL ;
    PORT
      LAYER M4 ;
        RECT  77.568 85.728 77.76 85.752 ;
    END
  END i[498]
  PIN i[499]
    DIRECTION INPUT ;
    USE SIGNAL ;
    PORT
      LAYER M4 ;
        RECT  77.568 85.872 77.76 85.896 ;
    END
  END i[499]
  PIN i[49]
    DIRECTION INPUT ;
    USE SIGNAL ;
    PORT
      LAYER M4 ;
        RECT  77.568 12.432 77.76 12.456 ;
    END
  END i[49]
  PIN i[4]
    DIRECTION INPUT ;
    USE SIGNAL ;
    PORT
      LAYER M4 ;
        RECT  77.568 5.088 77.76 5.112 ;
    END
  END i[4]
  PIN i[500]
    DIRECTION INPUT ;
    USE SIGNAL ;
    PORT
      LAYER M4 ;
        RECT  77.568 86.064 77.76 86.088 ;
    END
  END i[500]
  PIN i[501]
    DIRECTION INPUT ;
    USE SIGNAL ;
    PORT
      LAYER M4 ;
        RECT  77.568 86.208 77.76 86.232 ;
    END
  END i[501]
  PIN i[502]
    DIRECTION INPUT ;
    USE SIGNAL ;
    PORT
      LAYER M4 ;
        RECT  77.568 86.352 77.76 86.376 ;
    END
  END i[502]
  PIN i[503]
    DIRECTION INPUT ;
    USE SIGNAL ;
    PORT
      LAYER M4 ;
        RECT  77.568 86.544 77.76 86.568 ;
    END
  END i[503]
  PIN i[504]
    DIRECTION INPUT ;
    USE SIGNAL ;
    PORT
      LAYER M4 ;
        RECT  77.568 86.688 77.76 86.712 ;
    END
  END i[504]
  PIN i[505]
    DIRECTION INPUT ;
    USE SIGNAL ;
    PORT
      LAYER M4 ;
        RECT  77.568 86.88 77.76 86.904 ;
    END
  END i[505]
  PIN i[506]
    DIRECTION INPUT ;
    USE SIGNAL ;
    PORT
      LAYER M4 ;
        RECT  77.568 87.024 77.76 87.048 ;
    END
  END i[506]
  PIN i[507]
    DIRECTION INPUT ;
    USE SIGNAL ;
    PORT
      LAYER M4 ;
        RECT  77.568 87.168 77.76 87.192 ;
    END
  END i[507]
  PIN i[508]
    DIRECTION INPUT ;
    USE SIGNAL ;
    PORT
      LAYER M4 ;
        RECT  77.568 87.36 77.76 87.384 ;
    END
  END i[508]
  PIN i[509]
    DIRECTION INPUT ;
    USE SIGNAL ;
    PORT
      LAYER M4 ;
        RECT  77.568 87.504 77.76 87.528 ;
    END
  END i[509]
  PIN i[50]
    DIRECTION INPUT ;
    USE SIGNAL ;
    PORT
      LAYER M4 ;
        RECT  77.568 12.576 77.76 12.6 ;
    END
  END i[50]
  PIN i[510]
    DIRECTION INPUT ;
    USE SIGNAL ;
    PORT
      LAYER M4 ;
        RECT  77.568 87.696 77.76 87.72 ;
    END
  END i[510]
  PIN i[511]
    DIRECTION INPUT ;
    USE SIGNAL ;
    PORT
      LAYER M4 ;
        RECT  77.568 87.84 77.76 87.864 ;
    END
  END i[511]
  PIN i[512]
    DIRECTION INPUT ;
    USE SIGNAL ;
    PORT
      LAYER M4 ;
        RECT  77.568 87.984 77.76 88.008 ;
    END
  END i[512]
  PIN i[51]
    DIRECTION INPUT ;
    USE SIGNAL ;
    PORT
      LAYER M4 ;
        RECT  77.568 12.72 77.76 12.744 ;
    END
  END i[51]
  PIN i[52]
    DIRECTION INPUT ;
    USE SIGNAL ;
    PORT
      LAYER M4 ;
        RECT  77.568 12.912 77.76 12.936 ;
    END
  END i[52]
  PIN i[53]
    DIRECTION INPUT ;
    USE SIGNAL ;
    PORT
      LAYER M4 ;
        RECT  77.568 13.056 77.76 13.08 ;
    END
  END i[53]
  PIN i[54]
    DIRECTION INPUT ;
    USE SIGNAL ;
    PORT
      LAYER M4 ;
        RECT  77.568 13.248 77.76 13.272 ;
    END
  END i[54]
  PIN i[55]
    DIRECTION INPUT ;
    USE SIGNAL ;
    PORT
      LAYER M4 ;
        RECT  77.568 13.392 77.76 13.416 ;
    END
  END i[55]
  PIN i[56]
    DIRECTION INPUT ;
    USE SIGNAL ;
    PORT
      LAYER M4 ;
        RECT  77.568 13.536 77.76 13.56 ;
    END
  END i[56]
  PIN i[57]
    DIRECTION INPUT ;
    USE SIGNAL ;
    PORT
      LAYER M4 ;
        RECT  77.568 13.728 77.76 13.752 ;
    END
  END i[57]
  PIN i[58]
    DIRECTION INPUT ;
    USE SIGNAL ;
    PORT
      LAYER M4 ;
        RECT  77.568 13.872 77.76 13.896 ;
    END
  END i[58]
  PIN i[59]
    DIRECTION INPUT ;
    USE SIGNAL ;
    PORT
      LAYER M4 ;
        RECT  77.568 14.064 77.76 14.088 ;
    END
  END i[59]
  PIN i[5]
    DIRECTION INPUT ;
    USE SIGNAL ;
    PORT
      LAYER M4 ;
        RECT  77.568 5.232 77.76 5.256 ;
    END
  END i[5]
  PIN i[60]
    DIRECTION INPUT ;
    USE SIGNAL ;
    PORT
      LAYER M4 ;
        RECT  77.568 14.208 77.76 14.232 ;
    END
  END i[60]
  PIN i[61]
    DIRECTION INPUT ;
    USE SIGNAL ;
    PORT
      LAYER M4 ;
        RECT  77.568 14.352 77.76 14.376 ;
    END
  END i[61]
  PIN i[62]
    DIRECTION INPUT ;
    USE SIGNAL ;
    PORT
      LAYER M4 ;
        RECT  77.568 14.544 77.76 14.568 ;
    END
  END i[62]
  PIN i[63]
    DIRECTION INPUT ;
    USE SIGNAL ;
    PORT
      LAYER M4 ;
        RECT  77.568 14.688 77.76 14.712 ;
    END
  END i[63]
  PIN i[64]
    DIRECTION INPUT ;
    USE SIGNAL ;
    PORT
      LAYER M4 ;
        RECT  77.568 14.88 77.76 14.904 ;
    END
  END i[64]
  PIN i[65]
    DIRECTION INPUT ;
    USE SIGNAL ;
    PORT
      LAYER M4 ;
        RECT  77.568 15.024 77.76 15.048 ;
    END
  END i[65]
  PIN i[66]
    DIRECTION INPUT ;
    USE SIGNAL ;
    PORT
      LAYER M4 ;
        RECT  77.568 15.168 77.76 15.192 ;
    END
  END i[66]
  PIN i[67]
    DIRECTION INPUT ;
    USE SIGNAL ;
    PORT
      LAYER M4 ;
        RECT  77.568 15.36 77.76 15.384 ;
    END
  END i[67]
  PIN i[68]
    DIRECTION INPUT ;
    USE SIGNAL ;
    PORT
      LAYER M4 ;
        RECT  77.568 15.504 77.76 15.528 ;
    END
  END i[68]
  PIN i[69]
    DIRECTION INPUT ;
    USE SIGNAL ;
    PORT
      LAYER M4 ;
        RECT  77.568 15.696 77.76 15.72 ;
    END
  END i[69]
  PIN i[6]
    DIRECTION INPUT ;
    USE SIGNAL ;
    PORT
      LAYER M4 ;
        RECT  77.568 5.376 77.76 5.4 ;
    END
  END i[6]
  PIN i[70]
    DIRECTION INPUT ;
    USE SIGNAL ;
    PORT
      LAYER M4 ;
        RECT  77.568 15.84 77.76 15.864 ;
    END
  END i[70]
  PIN i[71]
    DIRECTION INPUT ;
    USE SIGNAL ;
    PORT
      LAYER M4 ;
        RECT  77.568 15.984 77.76 16.008 ;
    END
  END i[71]
  PIN i[72]
    DIRECTION INPUT ;
    USE SIGNAL ;
    PORT
      LAYER M4 ;
        RECT  77.568 16.176 77.76 16.2 ;
    END
  END i[72]
  PIN i[73]
    DIRECTION INPUT ;
    USE SIGNAL ;
    PORT
      LAYER M4 ;
        RECT  77.568 16.32 77.76 16.344 ;
    END
  END i[73]
  PIN i[74]
    DIRECTION INPUT ;
    USE SIGNAL ;
    PORT
      LAYER M4 ;
        RECT  77.568 16.512 77.76 16.536 ;
    END
  END i[74]
  PIN i[75]
    DIRECTION INPUT ;
    USE SIGNAL ;
    PORT
      LAYER M4 ;
        RECT  77.568 16.656 77.76 16.68 ;
    END
  END i[75]
  PIN i[76]
    DIRECTION INPUT ;
    USE SIGNAL ;
    PORT
      LAYER M4 ;
        RECT  77.568 16.8 77.76 16.824 ;
    END
  END i[76]
  PIN i[77]
    DIRECTION INPUT ;
    USE SIGNAL ;
    PORT
      LAYER M4 ;
        RECT  77.568 16.992 77.76 17.016 ;
    END
  END i[77]
  PIN i[78]
    DIRECTION INPUT ;
    USE SIGNAL ;
    PORT
      LAYER M4 ;
        RECT  77.568 17.136 77.76 17.16 ;
    END
  END i[78]
  PIN i[79]
    DIRECTION INPUT ;
    USE SIGNAL ;
    PORT
      LAYER M4 ;
        RECT  77.568 17.328 77.76 17.352 ;
    END
  END i[79]
  PIN i[7]
    DIRECTION INPUT ;
    USE SIGNAL ;
    PORT
      LAYER M4 ;
        RECT  77.568 5.568 77.76 5.592 ;
    END
  END i[7]
  PIN i[80]
    DIRECTION INPUT ;
    USE SIGNAL ;
    PORT
      LAYER M4 ;
        RECT  77.568 17.472 77.76 17.496 ;
    END
  END i[80]
  PIN i[81]
    DIRECTION INPUT ;
    USE SIGNAL ;
    PORT
      LAYER M4 ;
        RECT  77.568 17.616 77.76 17.64 ;
    END
  END i[81]
  PIN i[82]
    DIRECTION INPUT ;
    USE SIGNAL ;
    PORT
      LAYER M4 ;
        RECT  77.568 17.808 77.76 17.832 ;
    END
  END i[82]
  PIN i[83]
    DIRECTION INPUT ;
    USE SIGNAL ;
    PORT
      LAYER M4 ;
        RECT  77.568 17.952 77.76 17.976 ;
    END
  END i[83]
  PIN i[84]
    DIRECTION INPUT ;
    USE SIGNAL ;
    PORT
      LAYER M4 ;
        RECT  77.568 18.144 77.76 18.168 ;
    END
  END i[84]
  PIN i[85]
    DIRECTION INPUT ;
    USE SIGNAL ;
    PORT
      LAYER M4 ;
        RECT  77.568 18.288 77.76 18.312 ;
    END
  END i[85]
  PIN i[86]
    DIRECTION INPUT ;
    USE SIGNAL ;
    PORT
      LAYER M4 ;
        RECT  77.568 18.432 77.76 18.456 ;
    END
  END i[86]
  PIN i[87]
    DIRECTION INPUT ;
    USE SIGNAL ;
    PORT
      LAYER M4 ;
        RECT  77.568 18.624 77.76 18.648 ;
    END
  END i[87]
  PIN i[88]
    DIRECTION INPUT ;
    USE SIGNAL ;
    PORT
      LAYER M4 ;
        RECT  77.568 18.768 77.76 18.792 ;
    END
  END i[88]
  PIN i[89]
    DIRECTION INPUT ;
    USE SIGNAL ;
    PORT
      LAYER M4 ;
        RECT  77.568 18.96 77.76 18.984 ;
    END
  END i[89]
  PIN i[8]
    DIRECTION INPUT ;
    USE SIGNAL ;
    PORT
      LAYER M4 ;
        RECT  77.568 5.712 77.76 5.736 ;
    END
  END i[8]
  PIN i[90]
    DIRECTION INPUT ;
    USE SIGNAL ;
    PORT
      LAYER M4 ;
        RECT  77.568 19.104 77.76 19.128 ;
    END
  END i[90]
  PIN i[91]
    DIRECTION INPUT ;
    USE SIGNAL ;
    PORT
      LAYER M4 ;
        RECT  77.568 19.248 77.76 19.272 ;
    END
  END i[91]
  PIN i[92]
    DIRECTION INPUT ;
    USE SIGNAL ;
    PORT
      LAYER M4 ;
        RECT  77.568 19.44 77.76 19.464 ;
    END
  END i[92]
  PIN i[93]
    DIRECTION INPUT ;
    USE SIGNAL ;
    PORT
      LAYER M4 ;
        RECT  77.568 19.584 77.76 19.608 ;
    END
  END i[93]
  PIN i[94]
    DIRECTION INPUT ;
    USE SIGNAL ;
    PORT
      LAYER M4 ;
        RECT  77.568 19.776 77.76 19.8 ;
    END
  END i[94]
  PIN i[95]
    DIRECTION INPUT ;
    USE SIGNAL ;
    PORT
      LAYER M4 ;
        RECT  77.568 19.92 77.76 19.944 ;
    END
  END i[95]
  PIN i[96]
    DIRECTION INPUT ;
    USE SIGNAL ;
    PORT
      LAYER M4 ;
        RECT  77.568 20.064 77.76 20.088 ;
    END
  END i[96]
  PIN i[97]
    DIRECTION INPUT ;
    USE SIGNAL ;
    PORT
      LAYER M4 ;
        RECT  77.568 20.256 77.76 20.28 ;
    END
  END i[97]
  PIN i[98]
    DIRECTION INPUT ;
    USE SIGNAL ;
    PORT
      LAYER M4 ;
        RECT  77.568 20.4 77.76 20.424 ;
    END
  END i[98]
  PIN i[99]
    DIRECTION INPUT ;
    USE SIGNAL ;
    PORT
      LAYER M4 ;
        RECT  77.568 20.592 77.76 20.616 ;
    END
  END i[99]
  PIN i[9]
    DIRECTION INPUT ;
    USE SIGNAL ;
    PORT
      LAYER M4 ;
        RECT  77.568 5.904 77.76 5.928 ;
    END
  END i[9]
  PIN od[0]
    DIRECTION OUTPUT ;
    USE SIGNAL ;
    PORT
      LAYER M4 ;
        RECT  0 4.56 0.192 4.584 ;
    END
  END od[0]
  PIN od[100]
    DIRECTION OUTPUT ;
    USE SIGNAL ;
    PORT
      LAYER M4 ;
        RECT  0 20.928 0.192 20.952 ;
    END
  END od[100]
  PIN od[101]
    DIRECTION OUTPUT ;
    USE SIGNAL ;
    PORT
      LAYER M4 ;
        RECT  0 21.12 0.192 21.144 ;
    END
  END od[101]
  PIN od[102]
    DIRECTION OUTPUT ;
    USE SIGNAL ;
    PORT
      LAYER M4 ;
        RECT  0 21.264 0.192 21.288 ;
    END
  END od[102]
  PIN od[103]
    DIRECTION OUTPUT ;
    USE SIGNAL ;
    PORT
      LAYER M4 ;
        RECT  0 21.408 0.192 21.432 ;
    END
  END od[103]
  PIN od[104]
    DIRECTION OUTPUT ;
    USE SIGNAL ;
    PORT
      LAYER M4 ;
        RECT  0 21.6 0.192 21.624 ;
    END
  END od[104]
  PIN od[105]
    DIRECTION OUTPUT ;
    USE SIGNAL ;
    PORT
      LAYER M4 ;
        RECT  0 21.744 0.192 21.768 ;
    END
  END od[105]
  PIN od[106]
    DIRECTION OUTPUT ;
    USE SIGNAL ;
    PORT
      LAYER M4 ;
        RECT  0 21.936 0.192 21.96 ;
    END
  END od[106]
  PIN od[107]
    DIRECTION OUTPUT ;
    USE SIGNAL ;
    PORT
      LAYER M4 ;
        RECT  0 22.08 0.192 22.104 ;
    END
  END od[107]
  PIN od[108]
    DIRECTION OUTPUT ;
    USE SIGNAL ;
    PORT
      LAYER M4 ;
        RECT  0 22.224 0.192 22.248 ;
    END
  END od[108]
  PIN od[109]
    DIRECTION OUTPUT ;
    USE SIGNAL ;
    PORT
      LAYER M4 ;
        RECT  0 22.416 0.192 22.44 ;
    END
  END od[109]
  PIN od[10]
    DIRECTION OUTPUT ;
    USE SIGNAL ;
    PORT
      LAYER M4 ;
        RECT  0 6.192 0.192 6.216 ;
    END
  END od[10]
  PIN od[110]
    DIRECTION OUTPUT ;
    USE SIGNAL ;
    PORT
      LAYER M4 ;
        RECT  0 22.56 0.192 22.584 ;
    END
  END od[110]
  PIN od[111]
    DIRECTION OUTPUT ;
    USE SIGNAL ;
    PORT
      LAYER M4 ;
        RECT  0 22.752 0.192 22.776 ;
    END
  END od[111]
  PIN od[112]
    DIRECTION OUTPUT ;
    USE SIGNAL ;
    PORT
      LAYER M4 ;
        RECT  0 22.896 0.192 22.92 ;
    END
  END od[112]
  PIN od[113]
    DIRECTION OUTPUT ;
    USE SIGNAL ;
    PORT
      LAYER M4 ;
        RECT  0 23.04 0.192 23.064 ;
    END
  END od[113]
  PIN od[114]
    DIRECTION OUTPUT ;
    USE SIGNAL ;
    PORT
      LAYER M4 ;
        RECT  0 23.232 0.192 23.256 ;
    END
  END od[114]
  PIN od[115]
    DIRECTION OUTPUT ;
    USE SIGNAL ;
    PORT
      LAYER M4 ;
        RECT  0 23.376 0.192 23.4 ;
    END
  END od[115]
  PIN od[116]
    DIRECTION OUTPUT ;
    USE SIGNAL ;
    PORT
      LAYER M4 ;
        RECT  0 23.568 0.192 23.592 ;
    END
  END od[116]
  PIN od[117]
    DIRECTION OUTPUT ;
    USE SIGNAL ;
    PORT
      LAYER M4 ;
        RECT  0 23.712 0.192 23.736 ;
    END
  END od[117]
  PIN od[118]
    DIRECTION OUTPUT ;
    USE SIGNAL ;
    PORT
      LAYER M4 ;
        RECT  0 23.856 0.192 23.88 ;
    END
  END od[118]
  PIN od[119]
    DIRECTION OUTPUT ;
    USE SIGNAL ;
    PORT
      LAYER M4 ;
        RECT  0 24.048 0.192 24.072 ;
    END
  END od[119]
  PIN od[11]
    DIRECTION OUTPUT ;
    USE SIGNAL ;
    PORT
      LAYER M4 ;
        RECT  0 6.384 0.192 6.408 ;
    END
  END od[11]
  PIN od[120]
    DIRECTION OUTPUT ;
    USE SIGNAL ;
    PORT
      LAYER M4 ;
        RECT  0 24.192 0.192 24.216 ;
    END
  END od[120]
  PIN od[121]
    DIRECTION OUTPUT ;
    USE SIGNAL ;
    PORT
      LAYER M4 ;
        RECT  0 24.384 0.192 24.408 ;
    END
  END od[121]
  PIN od[122]
    DIRECTION OUTPUT ;
    USE SIGNAL ;
    PORT
      LAYER M4 ;
        RECT  0 24.528 0.192 24.552 ;
    END
  END od[122]
  PIN od[123]
    DIRECTION OUTPUT ;
    USE SIGNAL ;
    PORT
      LAYER M4 ;
        RECT  0 24.72 0.192 24.744 ;
    END
  END od[123]
  PIN od[124]
    DIRECTION OUTPUT ;
    USE SIGNAL ;
    PORT
      LAYER M4 ;
        RECT  0 24.864 0.192 24.888 ;
    END
  END od[124]
  PIN od[125]
    DIRECTION OUTPUT ;
    USE SIGNAL ;
    PORT
      LAYER M4 ;
        RECT  0 25.008 0.192 25.032 ;
    END
  END od[125]
  PIN od[126]
    DIRECTION OUTPUT ;
    USE SIGNAL ;
    PORT
      LAYER M4 ;
        RECT  0 25.2 0.192 25.224 ;
    END
  END od[126]
  PIN od[127]
    DIRECTION OUTPUT ;
    USE SIGNAL ;
    PORT
      LAYER M4 ;
        RECT  0 25.344 0.192 25.368 ;
    END
  END od[127]
  PIN od[128]
    DIRECTION OUTPUT ;
    USE SIGNAL ;
    PORT
      LAYER M4 ;
        RECT  0 25.536 0.192 25.56 ;
    END
  END od[128]
  PIN od[129]
    DIRECTION OUTPUT ;
    USE SIGNAL ;
    PORT
      LAYER M4 ;
        RECT  0 25.68 0.192 25.704 ;
    END
  END od[129]
  PIN od[12]
    DIRECTION OUTPUT ;
    USE SIGNAL ;
    PORT
      LAYER M4 ;
        RECT  0 6.528 0.192 6.552 ;
    END
  END od[12]
  PIN od[130]
    DIRECTION OUTPUT ;
    USE SIGNAL ;
    PORT
      LAYER M4 ;
        RECT  0 25.824 0.192 25.848 ;
    END
  END od[130]
  PIN od[131]
    DIRECTION OUTPUT ;
    USE SIGNAL ;
    PORT
      LAYER M4 ;
        RECT  0 26.016 0.192 26.04 ;
    END
  END od[131]
  PIN od[132]
    DIRECTION OUTPUT ;
    USE SIGNAL ;
    PORT
      LAYER M4 ;
        RECT  0 26.16 0.192 26.184 ;
    END
  END od[132]
  PIN od[133]
    DIRECTION OUTPUT ;
    USE SIGNAL ;
    PORT
      LAYER M4 ;
        RECT  0 26.352 0.192 26.376 ;
    END
  END od[133]
  PIN od[134]
    DIRECTION OUTPUT ;
    USE SIGNAL ;
    PORT
      LAYER M4 ;
        RECT  0 26.496 0.192 26.52 ;
    END
  END od[134]
  PIN od[135]
    DIRECTION OUTPUT ;
    USE SIGNAL ;
    PORT
      LAYER M4 ;
        RECT  0 26.64 0.192 26.664 ;
    END
  END od[135]
  PIN od[136]
    DIRECTION OUTPUT ;
    USE SIGNAL ;
    PORT
      LAYER M4 ;
        RECT  0 26.832 0.192 26.856 ;
    END
  END od[136]
  PIN od[137]
    DIRECTION OUTPUT ;
    USE SIGNAL ;
    PORT
      LAYER M4 ;
        RECT  0 26.976 0.192 27 ;
    END
  END od[137]
  PIN od[138]
    DIRECTION OUTPUT ;
    USE SIGNAL ;
    PORT
      LAYER M4 ;
        RECT  0 27.168 0.192 27.192 ;
    END
  END od[138]
  PIN od[139]
    DIRECTION OUTPUT ;
    USE SIGNAL ;
    PORT
      LAYER M4 ;
        RECT  0 27.312 0.192 27.336 ;
    END
  END od[139]
  PIN od[13]
    DIRECTION OUTPUT ;
    USE SIGNAL ;
    PORT
      LAYER M4 ;
        RECT  0 6.72 0.192 6.744 ;
    END
  END od[13]
  PIN od[140]
    DIRECTION OUTPUT ;
    USE SIGNAL ;
    PORT
      LAYER M4 ;
        RECT  0 27.456 0.192 27.48 ;
    END
  END od[140]
  PIN od[141]
    DIRECTION OUTPUT ;
    USE SIGNAL ;
    PORT
      LAYER M4 ;
        RECT  0 27.648 0.192 27.672 ;
    END
  END od[141]
  PIN od[142]
    DIRECTION OUTPUT ;
    USE SIGNAL ;
    PORT
      LAYER M4 ;
        RECT  0 27.792 0.192 27.816 ;
    END
  END od[142]
  PIN od[143]
    DIRECTION OUTPUT ;
    USE SIGNAL ;
    PORT
      LAYER M4 ;
        RECT  0 27.984 0.192 28.008 ;
    END
  END od[143]
  PIN od[144]
    DIRECTION OUTPUT ;
    USE SIGNAL ;
    PORT
      LAYER M4 ;
        RECT  0 28.128 0.192 28.152 ;
    END
  END od[144]
  PIN od[145]
    DIRECTION OUTPUT ;
    USE SIGNAL ;
    PORT
      LAYER M4 ;
        RECT  0 28.272 0.192 28.296 ;
    END
  END od[145]
  PIN od[146]
    DIRECTION OUTPUT ;
    USE SIGNAL ;
    PORT
      LAYER M4 ;
        RECT  0 28.464 0.192 28.488 ;
    END
  END od[146]
  PIN od[147]
    DIRECTION OUTPUT ;
    USE SIGNAL ;
    PORT
      LAYER M4 ;
        RECT  0 28.608 0.192 28.632 ;
    END
  END od[147]
  PIN od[148]
    DIRECTION OUTPUT ;
    USE SIGNAL ;
    PORT
      LAYER M4 ;
        RECT  0 28.8 0.192 28.824 ;
    END
  END od[148]
  PIN od[149]
    DIRECTION OUTPUT ;
    USE SIGNAL ;
    PORT
      LAYER M4 ;
        RECT  0 28.944 0.192 28.968 ;
    END
  END od[149]
  PIN od[14]
    DIRECTION OUTPUT ;
    USE SIGNAL ;
    PORT
      LAYER M4 ;
        RECT  0 6.864 0.192 6.888 ;
    END
  END od[14]
  PIN od[150]
    DIRECTION OUTPUT ;
    USE SIGNAL ;
    PORT
      LAYER M4 ;
        RECT  0 29.136 0.192 29.16 ;
    END
  END od[150]
  PIN od[151]
    DIRECTION OUTPUT ;
    USE SIGNAL ;
    PORT
      LAYER M4 ;
        RECT  0 29.28 0.192 29.304 ;
    END
  END od[151]
  PIN od[152]
    DIRECTION OUTPUT ;
    USE SIGNAL ;
    PORT
      LAYER M4 ;
        RECT  0 29.424 0.192 29.448 ;
    END
  END od[152]
  PIN od[153]
    DIRECTION OUTPUT ;
    USE SIGNAL ;
    PORT
      LAYER M4 ;
        RECT  0 29.616 0.192 29.64 ;
    END
  END od[153]
  PIN od[154]
    DIRECTION OUTPUT ;
    USE SIGNAL ;
    PORT
      LAYER M4 ;
        RECT  0 29.76 0.192 29.784 ;
    END
  END od[154]
  PIN od[155]
    DIRECTION OUTPUT ;
    USE SIGNAL ;
    PORT
      LAYER M4 ;
        RECT  0 29.952 0.192 29.976 ;
    END
  END od[155]
  PIN od[156]
    DIRECTION OUTPUT ;
    USE SIGNAL ;
    PORT
      LAYER M4 ;
        RECT  0 30.096 0.192 30.12 ;
    END
  END od[156]
  PIN od[157]
    DIRECTION OUTPUT ;
    USE SIGNAL ;
    PORT
      LAYER M4 ;
        RECT  0 30.24 0.192 30.264 ;
    END
  END od[157]
  PIN od[158]
    DIRECTION OUTPUT ;
    USE SIGNAL ;
    PORT
      LAYER M4 ;
        RECT  0 30.432 0.192 30.456 ;
    END
  END od[158]
  PIN od[159]
    DIRECTION OUTPUT ;
    USE SIGNAL ;
    PORT
      LAYER M4 ;
        RECT  0 30.576 0.192 30.6 ;
    END
  END od[159]
  PIN od[15]
    DIRECTION OUTPUT ;
    USE SIGNAL ;
    PORT
      LAYER M4 ;
        RECT  0 7.008 0.192 7.032 ;
    END
  END od[15]
  PIN od[160]
    DIRECTION OUTPUT ;
    USE SIGNAL ;
    PORT
      LAYER M4 ;
        RECT  0 30.768 0.192 30.792 ;
    END
  END od[160]
  PIN od[161]
    DIRECTION OUTPUT ;
    USE SIGNAL ;
    PORT
      LAYER M4 ;
        RECT  0 30.912 0.192 30.936 ;
    END
  END od[161]
  PIN od[162]
    DIRECTION OUTPUT ;
    USE SIGNAL ;
    PORT
      LAYER M4 ;
        RECT  0 31.056 0.192 31.08 ;
    END
  END od[162]
  PIN od[163]
    DIRECTION OUTPUT ;
    USE SIGNAL ;
    PORT
      LAYER M4 ;
        RECT  0 31.248 0.192 31.272 ;
    END
  END od[163]
  PIN od[164]
    DIRECTION OUTPUT ;
    USE SIGNAL ;
    PORT
      LAYER M4 ;
        RECT  0 31.392 0.192 31.416 ;
    END
  END od[164]
  PIN od[165]
    DIRECTION OUTPUT ;
    USE SIGNAL ;
    PORT
      LAYER M4 ;
        RECT  0 31.584 0.192 31.608 ;
    END
  END od[165]
  PIN od[166]
    DIRECTION OUTPUT ;
    USE SIGNAL ;
    PORT
      LAYER M4 ;
        RECT  0 31.728 0.192 31.752 ;
    END
  END od[166]
  PIN od[167]
    DIRECTION OUTPUT ;
    USE SIGNAL ;
    PORT
      LAYER M4 ;
        RECT  0 31.872 0.192 31.896 ;
    END
  END od[167]
  PIN od[168]
    DIRECTION OUTPUT ;
    USE SIGNAL ;
    PORT
      LAYER M4 ;
        RECT  0 32.064 0.192 32.088 ;
    END
  END od[168]
  PIN od[169]
    DIRECTION OUTPUT ;
    USE SIGNAL ;
    PORT
      LAYER M4 ;
        RECT  0 32.208 0.192 32.232 ;
    END
  END od[169]
  PIN od[16]
    DIRECTION OUTPUT ;
    USE SIGNAL ;
    PORT
      LAYER M4 ;
        RECT  0 7.2 0.192 7.224 ;
    END
  END od[16]
  PIN od[170]
    DIRECTION OUTPUT ;
    USE SIGNAL ;
    PORT
      LAYER M4 ;
        RECT  0 32.4 0.192 32.424 ;
    END
  END od[170]
  PIN od[171]
    DIRECTION OUTPUT ;
    USE SIGNAL ;
    PORT
      LAYER M4 ;
        RECT  0 32.544 0.192 32.568 ;
    END
  END od[171]
  PIN od[172]
    DIRECTION OUTPUT ;
    USE SIGNAL ;
    PORT
      LAYER M4 ;
        RECT  0 32.688 0.192 32.712 ;
    END
  END od[172]
  PIN od[173]
    DIRECTION OUTPUT ;
    USE SIGNAL ;
    PORT
      LAYER M4 ;
        RECT  0 32.88 0.192 32.904 ;
    END
  END od[173]
  PIN od[174]
    DIRECTION OUTPUT ;
    USE SIGNAL ;
    PORT
      LAYER M4 ;
        RECT  0 33.024 0.192 33.048 ;
    END
  END od[174]
  PIN od[175]
    DIRECTION OUTPUT ;
    USE SIGNAL ;
    PORT
      LAYER M4 ;
        RECT  0 33.216 0.192 33.24 ;
    END
  END od[175]
  PIN od[176]
    DIRECTION OUTPUT ;
    USE SIGNAL ;
    PORT
      LAYER M4 ;
        RECT  0 33.36 0.192 33.384 ;
    END
  END od[176]
  PIN od[177]
    DIRECTION OUTPUT ;
    USE SIGNAL ;
    PORT
      LAYER M4 ;
        RECT  0 33.552 0.192 33.576 ;
    END
  END od[177]
  PIN od[178]
    DIRECTION OUTPUT ;
    USE SIGNAL ;
    PORT
      LAYER M4 ;
        RECT  0 33.696 0.192 33.72 ;
    END
  END od[178]
  PIN od[179]
    DIRECTION OUTPUT ;
    USE SIGNAL ;
    PORT
      LAYER M4 ;
        RECT  0 33.84 0.192 33.864 ;
    END
  END od[179]
  PIN od[17]
    DIRECTION OUTPUT ;
    USE SIGNAL ;
    PORT
      LAYER M4 ;
        RECT  0 7.344 0.192 7.368 ;
    END
  END od[17]
  PIN od[180]
    DIRECTION OUTPUT ;
    USE SIGNAL ;
    PORT
      LAYER M4 ;
        RECT  0 34.032 0.192 34.056 ;
    END
  END od[180]
  PIN od[181]
    DIRECTION OUTPUT ;
    USE SIGNAL ;
    PORT
      LAYER M4 ;
        RECT  0 34.176 0.192 34.2 ;
    END
  END od[181]
  PIN od[182]
    DIRECTION OUTPUT ;
    USE SIGNAL ;
    PORT
      LAYER M4 ;
        RECT  0 34.368 0.192 34.392 ;
    END
  END od[182]
  PIN od[183]
    DIRECTION OUTPUT ;
    USE SIGNAL ;
    PORT
      LAYER M4 ;
        RECT  0 34.512 0.192 34.536 ;
    END
  END od[183]
  PIN od[184]
    DIRECTION OUTPUT ;
    USE SIGNAL ;
    PORT
      LAYER M4 ;
        RECT  0 34.656 0.192 34.68 ;
    END
  END od[184]
  PIN od[185]
    DIRECTION OUTPUT ;
    USE SIGNAL ;
    PORT
      LAYER M4 ;
        RECT  0 34.848 0.192 34.872 ;
    END
  END od[185]
  PIN od[186]
    DIRECTION OUTPUT ;
    USE SIGNAL ;
    PORT
      LAYER M4 ;
        RECT  0 34.992 0.192 35.016 ;
    END
  END od[186]
  PIN od[187]
    DIRECTION OUTPUT ;
    USE SIGNAL ;
    PORT
      LAYER M4 ;
        RECT  0 35.184 0.192 35.208 ;
    END
  END od[187]
  PIN od[188]
    DIRECTION OUTPUT ;
    USE SIGNAL ;
    PORT
      LAYER M4 ;
        RECT  0 35.328 0.192 35.352 ;
    END
  END od[188]
  PIN od[189]
    DIRECTION OUTPUT ;
    USE SIGNAL ;
    PORT
      LAYER M4 ;
        RECT  0 35.472 0.192 35.496 ;
    END
  END od[189]
  PIN od[18]
    DIRECTION OUTPUT ;
    USE SIGNAL ;
    PORT
      LAYER M4 ;
        RECT  0 7.536 0.192 7.56 ;
    END
  END od[18]
  PIN od[190]
    DIRECTION OUTPUT ;
    USE SIGNAL ;
    PORT
      LAYER M4 ;
        RECT  0 35.664 0.192 35.688 ;
    END
  END od[190]
  PIN od[191]
    DIRECTION OUTPUT ;
    USE SIGNAL ;
    PORT
      LAYER M4 ;
        RECT  0 35.808 0.192 35.832 ;
    END
  END od[191]
  PIN od[192]
    DIRECTION OUTPUT ;
    USE SIGNAL ;
    PORT
      LAYER M4 ;
        RECT  0 36 0.192 36.024 ;
    END
  END od[192]
  PIN od[193]
    DIRECTION OUTPUT ;
    USE SIGNAL ;
    PORT
      LAYER M4 ;
        RECT  0 36.144 0.192 36.168 ;
    END
  END od[193]
  PIN od[194]
    DIRECTION OUTPUT ;
    USE SIGNAL ;
    PORT
      LAYER M4 ;
        RECT  0 36.288 0.192 36.312 ;
    END
  END od[194]
  PIN od[195]
    DIRECTION OUTPUT ;
    USE SIGNAL ;
    PORT
      LAYER M4 ;
        RECT  0 36.48 0.192 36.504 ;
    END
  END od[195]
  PIN od[196]
    DIRECTION OUTPUT ;
    USE SIGNAL ;
    PORT
      LAYER M4 ;
        RECT  0 36.624 0.192 36.648 ;
    END
  END od[196]
  PIN od[197]
    DIRECTION OUTPUT ;
    USE SIGNAL ;
    PORT
      LAYER M4 ;
        RECT  0 36.816 0.192 36.84 ;
    END
  END od[197]
  PIN od[198]
    DIRECTION OUTPUT ;
    USE SIGNAL ;
    PORT
      LAYER M4 ;
        RECT  0 36.96 0.192 36.984 ;
    END
  END od[198]
  PIN od[199]
    DIRECTION OUTPUT ;
    USE SIGNAL ;
    PORT
      LAYER M4 ;
        RECT  0 37.152 0.192 37.176 ;
    END
  END od[199]
  PIN od[19]
    DIRECTION OUTPUT ;
    USE SIGNAL ;
    PORT
      LAYER M4 ;
        RECT  0 7.68 0.192 7.704 ;
    END
  END od[19]
  PIN od[1]
    DIRECTION OUTPUT ;
    USE SIGNAL ;
    PORT
      LAYER M4 ;
        RECT  0 4.752 0.192 4.776 ;
    END
  END od[1]
  PIN od[200]
    DIRECTION OUTPUT ;
    USE SIGNAL ;
    PORT
      LAYER M4 ;
        RECT  0 37.296 0.192 37.32 ;
    END
  END od[200]
  PIN od[201]
    DIRECTION OUTPUT ;
    USE SIGNAL ;
    PORT
      LAYER M4 ;
        RECT  0 37.44 0.192 37.464 ;
    END
  END od[201]
  PIN od[202]
    DIRECTION OUTPUT ;
    USE SIGNAL ;
    PORT
      LAYER M4 ;
        RECT  0 37.632 0.192 37.656 ;
    END
  END od[202]
  PIN od[203]
    DIRECTION OUTPUT ;
    USE SIGNAL ;
    PORT
      LAYER M4 ;
        RECT  0 37.776 0.192 37.8 ;
    END
  END od[203]
  PIN od[204]
    DIRECTION OUTPUT ;
    USE SIGNAL ;
    PORT
      LAYER M4 ;
        RECT  0 37.968 0.192 37.992 ;
    END
  END od[204]
  PIN od[205]
    DIRECTION OUTPUT ;
    USE SIGNAL ;
    PORT
      LAYER M4 ;
        RECT  0 38.112 0.192 38.136 ;
    END
  END od[205]
  PIN od[206]
    DIRECTION OUTPUT ;
    USE SIGNAL ;
    PORT
      LAYER M4 ;
        RECT  0 38.256 0.192 38.28 ;
    END
  END od[206]
  PIN od[207]
    DIRECTION OUTPUT ;
    USE SIGNAL ;
    PORT
      LAYER M4 ;
        RECT  0 38.448 0.192 38.472 ;
    END
  END od[207]
  PIN od[208]
    DIRECTION OUTPUT ;
    USE SIGNAL ;
    PORT
      LAYER M4 ;
        RECT  0 38.592 0.192 38.616 ;
    END
  END od[208]
  PIN od[209]
    DIRECTION OUTPUT ;
    USE SIGNAL ;
    PORT
      LAYER M4 ;
        RECT  0 38.784 0.192 38.808 ;
    END
  END od[209]
  PIN od[20]
    DIRECTION OUTPUT ;
    USE SIGNAL ;
    PORT
      LAYER M4 ;
        RECT  0 7.872 0.192 7.896 ;
    END
  END od[20]
  PIN od[210]
    DIRECTION OUTPUT ;
    USE SIGNAL ;
    PORT
      LAYER M4 ;
        RECT  0 38.928 0.192 38.952 ;
    END
  END od[210]
  PIN od[211]
    DIRECTION OUTPUT ;
    USE SIGNAL ;
    PORT
      LAYER M4 ;
        RECT  0 39.072 0.192 39.096 ;
    END
  END od[211]
  PIN od[212]
    DIRECTION OUTPUT ;
    USE SIGNAL ;
    PORT
      LAYER M4 ;
        RECT  0 39.264 0.192 39.288 ;
    END
  END od[212]
  PIN od[213]
    DIRECTION OUTPUT ;
    USE SIGNAL ;
    PORT
      LAYER M4 ;
        RECT  0 39.408 0.192 39.432 ;
    END
  END od[213]
  PIN od[214]
    DIRECTION OUTPUT ;
    USE SIGNAL ;
    PORT
      LAYER M4 ;
        RECT  0 39.6 0.192 39.624 ;
    END
  END od[214]
  PIN od[215]
    DIRECTION OUTPUT ;
    USE SIGNAL ;
    PORT
      LAYER M4 ;
        RECT  0 39.744 0.192 39.768 ;
    END
  END od[215]
  PIN od[216]
    DIRECTION OUTPUT ;
    USE SIGNAL ;
    PORT
      LAYER M4 ;
        RECT  0 39.888 0.192 39.912 ;
    END
  END od[216]
  PIN od[217]
    DIRECTION OUTPUT ;
    USE SIGNAL ;
    PORT
      LAYER M4 ;
        RECT  0 40.08 0.192 40.104 ;
    END
  END od[217]
  PIN od[218]
    DIRECTION OUTPUT ;
    USE SIGNAL ;
    PORT
      LAYER M4 ;
        RECT  0 40.224 0.192 40.248 ;
    END
  END od[218]
  PIN od[219]
    DIRECTION OUTPUT ;
    USE SIGNAL ;
    PORT
      LAYER M4 ;
        RECT  0 40.416 0.192 40.44 ;
    END
  END od[219]
  PIN od[21]
    DIRECTION OUTPUT ;
    USE SIGNAL ;
    PORT
      LAYER M4 ;
        RECT  0 8.016 0.192 8.04 ;
    END
  END od[21]
  PIN od[220]
    DIRECTION OUTPUT ;
    USE SIGNAL ;
    PORT
      LAYER M4 ;
        RECT  0 40.56 0.192 40.584 ;
    END
  END od[220]
  PIN od[221]
    DIRECTION OUTPUT ;
    USE SIGNAL ;
    PORT
      LAYER M4 ;
        RECT  0 40.704 0.192 40.728 ;
    END
  END od[221]
  PIN od[222]
    DIRECTION OUTPUT ;
    USE SIGNAL ;
    PORT
      LAYER M4 ;
        RECT  0 40.896 0.192 40.92 ;
    END
  END od[222]
  PIN od[223]
    DIRECTION OUTPUT ;
    USE SIGNAL ;
    PORT
      LAYER M4 ;
        RECT  0 41.04 0.192 41.064 ;
    END
  END od[223]
  PIN od[224]
    DIRECTION OUTPUT ;
    USE SIGNAL ;
    PORT
      LAYER M4 ;
        RECT  0 41.232 0.192 41.256 ;
    END
  END od[224]
  PIN od[225]
    DIRECTION OUTPUT ;
    USE SIGNAL ;
    PORT
      LAYER M4 ;
        RECT  0 41.376 0.192 41.4 ;
    END
  END od[225]
  PIN od[226]
    DIRECTION OUTPUT ;
    USE SIGNAL ;
    PORT
      LAYER M4 ;
        RECT  0 41.568 0.192 41.592 ;
    END
  END od[226]
  PIN od[227]
    DIRECTION OUTPUT ;
    USE SIGNAL ;
    PORT
      LAYER M4 ;
        RECT  0 41.712 0.192 41.736 ;
    END
  END od[227]
  PIN od[228]
    DIRECTION OUTPUT ;
    USE SIGNAL ;
    PORT
      LAYER M4 ;
        RECT  0 41.856 0.192 41.88 ;
    END
  END od[228]
  PIN od[229]
    DIRECTION OUTPUT ;
    USE SIGNAL ;
    PORT
      LAYER M4 ;
        RECT  0 42.048 0.192 42.072 ;
    END
  END od[229]
  PIN od[22]
    DIRECTION OUTPUT ;
    USE SIGNAL ;
    PORT
      LAYER M4 ;
        RECT  0 8.16 0.192 8.184 ;
    END
  END od[22]
  PIN od[230]
    DIRECTION OUTPUT ;
    USE SIGNAL ;
    PORT
      LAYER M4 ;
        RECT  0 42.192 0.192 42.216 ;
    END
  END od[230]
  PIN od[231]
    DIRECTION OUTPUT ;
    USE SIGNAL ;
    PORT
      LAYER M4 ;
        RECT  0 42.384 0.192 42.408 ;
    END
  END od[231]
  PIN od[232]
    DIRECTION OUTPUT ;
    USE SIGNAL ;
    PORT
      LAYER M4 ;
        RECT  0 42.528 0.192 42.552 ;
    END
  END od[232]
  PIN od[233]
    DIRECTION OUTPUT ;
    USE SIGNAL ;
    PORT
      LAYER M4 ;
        RECT  0 42.672 0.192 42.696 ;
    END
  END od[233]
  PIN od[234]
    DIRECTION OUTPUT ;
    USE SIGNAL ;
    PORT
      LAYER M4 ;
        RECT  0 42.864 0.192 42.888 ;
    END
  END od[234]
  PIN od[235]
    DIRECTION OUTPUT ;
    USE SIGNAL ;
    PORT
      LAYER M4 ;
        RECT  0 43.008 0.192 43.032 ;
    END
  END od[235]
  PIN od[236]
    DIRECTION OUTPUT ;
    USE SIGNAL ;
    PORT
      LAYER M4 ;
        RECT  0 43.2 0.192 43.224 ;
    END
  END od[236]
  PIN od[237]
    DIRECTION OUTPUT ;
    USE SIGNAL ;
    PORT
      LAYER M4 ;
        RECT  0 43.344 0.192 43.368 ;
    END
  END od[237]
  PIN od[238]
    DIRECTION OUTPUT ;
    USE SIGNAL ;
    PORT
      LAYER M4 ;
        RECT  0 43.488 0.192 43.512 ;
    END
  END od[238]
  PIN od[239]
    DIRECTION OUTPUT ;
    USE SIGNAL ;
    PORT
      LAYER M4 ;
        RECT  0 43.68 0.192 43.704 ;
    END
  END od[239]
  PIN od[23]
    DIRECTION OUTPUT ;
    USE SIGNAL ;
    PORT
      LAYER M4 ;
        RECT  0 8.352 0.192 8.376 ;
    END
  END od[23]
  PIN od[240]
    DIRECTION OUTPUT ;
    USE SIGNAL ;
    PORT
      LAYER M4 ;
        RECT  0 43.824 0.192 43.848 ;
    END
  END od[240]
  PIN od[241]
    DIRECTION OUTPUT ;
    USE SIGNAL ;
    PORT
      LAYER M4 ;
        RECT  0 44.016 0.192 44.04 ;
    END
  END od[241]
  PIN od[242]
    DIRECTION OUTPUT ;
    USE SIGNAL ;
    PORT
      LAYER M4 ;
        RECT  0 44.16 0.192 44.184 ;
    END
  END od[242]
  PIN od[243]
    DIRECTION OUTPUT ;
    USE SIGNAL ;
    PORT
      LAYER M4 ;
        RECT  0 44.304 0.192 44.328 ;
    END
  END od[243]
  PIN od[244]
    DIRECTION OUTPUT ;
    USE SIGNAL ;
    PORT
      LAYER M4 ;
        RECT  0 44.496 0.192 44.52 ;
    END
  END od[244]
  PIN od[245]
    DIRECTION OUTPUT ;
    USE SIGNAL ;
    PORT
      LAYER M4 ;
        RECT  0 44.64 0.192 44.664 ;
    END
  END od[245]
  PIN od[246]
    DIRECTION OUTPUT ;
    USE SIGNAL ;
    PORT
      LAYER M4 ;
        RECT  0 44.832 0.192 44.856 ;
    END
  END od[246]
  PIN od[247]
    DIRECTION OUTPUT ;
    USE SIGNAL ;
    PORT
      LAYER M4 ;
        RECT  0 44.976 0.192 45 ;
    END
  END od[247]
  PIN od[248]
    DIRECTION OUTPUT ;
    USE SIGNAL ;
    PORT
      LAYER M4 ;
        RECT  0 45.12 0.192 45.144 ;
    END
  END od[248]
  PIN od[249]
    DIRECTION OUTPUT ;
    USE SIGNAL ;
    PORT
      LAYER M4 ;
        RECT  0 45.312 0.192 45.336 ;
    END
  END od[249]
  PIN od[24]
    DIRECTION OUTPUT ;
    USE SIGNAL ;
    PORT
      LAYER M4 ;
        RECT  0 8.496 0.192 8.52 ;
    END
  END od[24]
  PIN od[250]
    DIRECTION OUTPUT ;
    USE SIGNAL ;
    PORT
      LAYER M4 ;
        RECT  0 45.456 0.192 45.48 ;
    END
  END od[250]
  PIN od[251]
    DIRECTION OUTPUT ;
    USE SIGNAL ;
    PORT
      LAYER M4 ;
        RECT  0 45.648 0.192 45.672 ;
    END
  END od[251]
  PIN od[252]
    DIRECTION OUTPUT ;
    USE SIGNAL ;
    PORT
      LAYER M4 ;
        RECT  0 45.792 0.192 45.816 ;
    END
  END od[252]
  PIN od[253]
    DIRECTION OUTPUT ;
    USE SIGNAL ;
    PORT
      LAYER M4 ;
        RECT  0 45.984 0.192 46.008 ;
    END
  END od[253]
  PIN od[254]
    DIRECTION OUTPUT ;
    USE SIGNAL ;
    PORT
      LAYER M4 ;
        RECT  0 46.128 0.192 46.152 ;
    END
  END od[254]
  PIN od[255]
    DIRECTION OUTPUT ;
    USE SIGNAL ;
    PORT
      LAYER M4 ;
        RECT  0 46.272 0.192 46.296 ;
    END
  END od[255]
  PIN od[256]
    DIRECTION OUTPUT ;
    USE SIGNAL ;
    PORT
      LAYER M4 ;
        RECT  0 46.464 0.192 46.488 ;
    END
  END od[256]
  PIN od[257]
    DIRECTION OUTPUT ;
    USE SIGNAL ;
    PORT
      LAYER M4 ;
        RECT  0 46.608 0.192 46.632 ;
    END
  END od[257]
  PIN od[258]
    DIRECTION OUTPUT ;
    USE SIGNAL ;
    PORT
      LAYER M4 ;
        RECT  0 46.8 0.192 46.824 ;
    END
  END od[258]
  PIN od[259]
    DIRECTION OUTPUT ;
    USE SIGNAL ;
    PORT
      LAYER M4 ;
        RECT  0 46.944 0.192 46.968 ;
    END
  END od[259]
  PIN od[25]
    DIRECTION OUTPUT ;
    USE SIGNAL ;
    PORT
      LAYER M4 ;
        RECT  0 8.688 0.192 8.712 ;
    END
  END od[25]
  PIN od[260]
    DIRECTION OUTPUT ;
    USE SIGNAL ;
    PORT
      LAYER M4 ;
        RECT  0 47.088 0.192 47.112 ;
    END
  END od[260]
  PIN od[261]
    DIRECTION OUTPUT ;
    USE SIGNAL ;
    PORT
      LAYER M4 ;
        RECT  0 47.28 0.192 47.304 ;
    END
  END od[261]
  PIN od[262]
    DIRECTION OUTPUT ;
    USE SIGNAL ;
    PORT
      LAYER M4 ;
        RECT  0 47.424 0.192 47.448 ;
    END
  END od[262]
  PIN od[263]
    DIRECTION OUTPUT ;
    USE SIGNAL ;
    PORT
      LAYER M4 ;
        RECT  0 47.616 0.192 47.64 ;
    END
  END od[263]
  PIN od[264]
    DIRECTION OUTPUT ;
    USE SIGNAL ;
    PORT
      LAYER M4 ;
        RECT  0 47.76 0.192 47.784 ;
    END
  END od[264]
  PIN od[265]
    DIRECTION OUTPUT ;
    USE SIGNAL ;
    PORT
      LAYER M4 ;
        RECT  0 47.904 0.192 47.928 ;
    END
  END od[265]
  PIN od[266]
    DIRECTION OUTPUT ;
    USE SIGNAL ;
    PORT
      LAYER M4 ;
        RECT  0 48.096 0.192 48.12 ;
    END
  END od[266]
  PIN od[267]
    DIRECTION OUTPUT ;
    USE SIGNAL ;
    PORT
      LAYER M4 ;
        RECT  0 48.24 0.192 48.264 ;
    END
  END od[267]
  PIN od[268]
    DIRECTION OUTPUT ;
    USE SIGNAL ;
    PORT
      LAYER M4 ;
        RECT  0 48.432 0.192 48.456 ;
    END
  END od[268]
  PIN od[269]
    DIRECTION OUTPUT ;
    USE SIGNAL ;
    PORT
      LAYER M4 ;
        RECT  0 48.576 0.192 48.6 ;
    END
  END od[269]
  PIN od[26]
    DIRECTION OUTPUT ;
    USE SIGNAL ;
    PORT
      LAYER M4 ;
        RECT  0 8.832 0.192 8.856 ;
    END
  END od[26]
  PIN od[270]
    DIRECTION OUTPUT ;
    USE SIGNAL ;
    PORT
      LAYER M4 ;
        RECT  0 48.72 0.192 48.744 ;
    END
  END od[270]
  PIN od[271]
    DIRECTION OUTPUT ;
    USE SIGNAL ;
    PORT
      LAYER M4 ;
        RECT  0 48.912 0.192 48.936 ;
    END
  END od[271]
  PIN od[272]
    DIRECTION OUTPUT ;
    USE SIGNAL ;
    PORT
      LAYER M4 ;
        RECT  0 49.056 0.192 49.08 ;
    END
  END od[272]
  PIN od[273]
    DIRECTION OUTPUT ;
    USE SIGNAL ;
    PORT
      LAYER M4 ;
        RECT  0 49.248 0.192 49.272 ;
    END
  END od[273]
  PIN od[274]
    DIRECTION OUTPUT ;
    USE SIGNAL ;
    PORT
      LAYER M4 ;
        RECT  0 49.392 0.192 49.416 ;
    END
  END od[274]
  PIN od[275]
    DIRECTION OUTPUT ;
    USE SIGNAL ;
    PORT
      LAYER M4 ;
        RECT  0 49.536 0.192 49.56 ;
    END
  END od[275]
  PIN od[276]
    DIRECTION OUTPUT ;
    USE SIGNAL ;
    PORT
      LAYER M4 ;
        RECT  0 49.728 0.192 49.752 ;
    END
  END od[276]
  PIN od[277]
    DIRECTION OUTPUT ;
    USE SIGNAL ;
    PORT
      LAYER M4 ;
        RECT  0 49.872 0.192 49.896 ;
    END
  END od[277]
  PIN od[278]
    DIRECTION OUTPUT ;
    USE SIGNAL ;
    PORT
      LAYER M4 ;
        RECT  0 50.064 0.192 50.088 ;
    END
  END od[278]
  PIN od[279]
    DIRECTION OUTPUT ;
    USE SIGNAL ;
    PORT
      LAYER M4 ;
        RECT  0 50.208 0.192 50.232 ;
    END
  END od[279]
  PIN od[27]
    DIRECTION OUTPUT ;
    USE SIGNAL ;
    PORT
      LAYER M4 ;
        RECT  0 8.976 0.192 9 ;
    END
  END od[27]
  PIN od[280]
    DIRECTION OUTPUT ;
    USE SIGNAL ;
    PORT
      LAYER M4 ;
        RECT  0 50.4 0.192 50.424 ;
    END
  END od[280]
  PIN od[281]
    DIRECTION OUTPUT ;
    USE SIGNAL ;
    PORT
      LAYER M4 ;
        RECT  0 50.544 0.192 50.568 ;
    END
  END od[281]
  PIN od[282]
    DIRECTION OUTPUT ;
    USE SIGNAL ;
    PORT
      LAYER M4 ;
        RECT  0 50.688 0.192 50.712 ;
    END
  END od[282]
  PIN od[283]
    DIRECTION OUTPUT ;
    USE SIGNAL ;
    PORT
      LAYER M4 ;
        RECT  0 50.88 0.192 50.904 ;
    END
  END od[283]
  PIN od[284]
    DIRECTION OUTPUT ;
    USE SIGNAL ;
    PORT
      LAYER M4 ;
        RECT  0 51.024 0.192 51.048 ;
    END
  END od[284]
  PIN od[285]
    DIRECTION OUTPUT ;
    USE SIGNAL ;
    PORT
      LAYER M4 ;
        RECT  0 51.216 0.192 51.24 ;
    END
  END od[285]
  PIN od[286]
    DIRECTION OUTPUT ;
    USE SIGNAL ;
    PORT
      LAYER M4 ;
        RECT  0 51.36 0.192 51.384 ;
    END
  END od[286]
  PIN od[287]
    DIRECTION OUTPUT ;
    USE SIGNAL ;
    PORT
      LAYER M4 ;
        RECT  0 51.504 0.192 51.528 ;
    END
  END od[287]
  PIN od[288]
    DIRECTION OUTPUT ;
    USE SIGNAL ;
    PORT
      LAYER M4 ;
        RECT  0 51.696 0.192 51.72 ;
    END
  END od[288]
  PIN od[289]
    DIRECTION OUTPUT ;
    USE SIGNAL ;
    PORT
      LAYER M4 ;
        RECT  0 51.84 0.192 51.864 ;
    END
  END od[289]
  PIN od[28]
    DIRECTION OUTPUT ;
    USE SIGNAL ;
    PORT
      LAYER M4 ;
        RECT  0 9.168 0.192 9.192 ;
    END
  END od[28]
  PIN od[290]
    DIRECTION OUTPUT ;
    USE SIGNAL ;
    PORT
      LAYER M4 ;
        RECT  0 52.032 0.192 52.056 ;
    END
  END od[290]
  PIN od[291]
    DIRECTION OUTPUT ;
    USE SIGNAL ;
    PORT
      LAYER M4 ;
        RECT  0 52.176 0.192 52.2 ;
    END
  END od[291]
  PIN od[292]
    DIRECTION OUTPUT ;
    USE SIGNAL ;
    PORT
      LAYER M4 ;
        RECT  0 52.32 0.192 52.344 ;
    END
  END od[292]
  PIN od[293]
    DIRECTION OUTPUT ;
    USE SIGNAL ;
    PORT
      LAYER M4 ;
        RECT  0 52.512 0.192 52.536 ;
    END
  END od[293]
  PIN od[294]
    DIRECTION OUTPUT ;
    USE SIGNAL ;
    PORT
      LAYER M4 ;
        RECT  0 52.656 0.192 52.68 ;
    END
  END od[294]
  PIN od[295]
    DIRECTION OUTPUT ;
    USE SIGNAL ;
    PORT
      LAYER M4 ;
        RECT  0 52.848 0.192 52.872 ;
    END
  END od[295]
  PIN od[296]
    DIRECTION OUTPUT ;
    USE SIGNAL ;
    PORT
      LAYER M4 ;
        RECT  0 52.992 0.192 53.016 ;
    END
  END od[296]
  PIN od[297]
    DIRECTION OUTPUT ;
    USE SIGNAL ;
    PORT
      LAYER M4 ;
        RECT  0 53.136 0.192 53.16 ;
    END
  END od[297]
  PIN od[298]
    DIRECTION OUTPUT ;
    USE SIGNAL ;
    PORT
      LAYER M4 ;
        RECT  0 53.328 0.192 53.352 ;
    END
  END od[298]
  PIN od[299]
    DIRECTION OUTPUT ;
    USE SIGNAL ;
    PORT
      LAYER M4 ;
        RECT  0 53.472 0.192 53.496 ;
    END
  END od[299]
  PIN od[29]
    DIRECTION OUTPUT ;
    USE SIGNAL ;
    PORT
      LAYER M4 ;
        RECT  0 9.312 0.192 9.336 ;
    END
  END od[29]
  PIN od[2]
    DIRECTION OUTPUT ;
    USE SIGNAL ;
    PORT
      LAYER M4 ;
        RECT  0 4.896 0.192 4.92 ;
    END
  END od[2]
  PIN od[300]
    DIRECTION OUTPUT ;
    USE SIGNAL ;
    PORT
      LAYER M4 ;
        RECT  0 53.664 0.192 53.688 ;
    END
  END od[300]
  PIN od[301]
    DIRECTION OUTPUT ;
    USE SIGNAL ;
    PORT
      LAYER M4 ;
        RECT  0 53.808 0.192 53.832 ;
    END
  END od[301]
  PIN od[302]
    DIRECTION OUTPUT ;
    USE SIGNAL ;
    PORT
      LAYER M4 ;
        RECT  0 54 0.192 54.024 ;
    END
  END od[302]
  PIN od[303]
    DIRECTION OUTPUT ;
    USE SIGNAL ;
    PORT
      LAYER M4 ;
        RECT  0 54.144 0.192 54.168 ;
    END
  END od[303]
  PIN od[304]
    DIRECTION OUTPUT ;
    USE SIGNAL ;
    PORT
      LAYER M4 ;
        RECT  0 54.288 0.192 54.312 ;
    END
  END od[304]
  PIN od[305]
    DIRECTION OUTPUT ;
    USE SIGNAL ;
    PORT
      LAYER M4 ;
        RECT  0 54.48 0.192 54.504 ;
    END
  END od[305]
  PIN od[306]
    DIRECTION OUTPUT ;
    USE SIGNAL ;
    PORT
      LAYER M4 ;
        RECT  0 54.624 0.192 54.648 ;
    END
  END od[306]
  PIN od[307]
    DIRECTION OUTPUT ;
    USE SIGNAL ;
    PORT
      LAYER M4 ;
        RECT  0 54.816 0.192 54.84 ;
    END
  END od[307]
  PIN od[308]
    DIRECTION OUTPUT ;
    USE SIGNAL ;
    PORT
      LAYER M4 ;
        RECT  0 54.96 0.192 54.984 ;
    END
  END od[308]
  PIN od[309]
    DIRECTION OUTPUT ;
    USE SIGNAL ;
    PORT
      LAYER M4 ;
        RECT  0 55.104 0.192 55.128 ;
    END
  END od[309]
  PIN od[30]
    DIRECTION OUTPUT ;
    USE SIGNAL ;
    PORT
      LAYER M4 ;
        RECT  0 9.504 0.192 9.528 ;
    END
  END od[30]
  PIN od[310]
    DIRECTION OUTPUT ;
    USE SIGNAL ;
    PORT
      LAYER M4 ;
        RECT  0 55.296 0.192 55.32 ;
    END
  END od[310]
  PIN od[311]
    DIRECTION OUTPUT ;
    USE SIGNAL ;
    PORT
      LAYER M4 ;
        RECT  0 55.44 0.192 55.464 ;
    END
  END od[311]
  PIN od[312]
    DIRECTION OUTPUT ;
    USE SIGNAL ;
    PORT
      LAYER M4 ;
        RECT  0 55.632 0.192 55.656 ;
    END
  END od[312]
  PIN od[313]
    DIRECTION OUTPUT ;
    USE SIGNAL ;
    PORT
      LAYER M4 ;
        RECT  0 55.776 0.192 55.8 ;
    END
  END od[313]
  PIN od[314]
    DIRECTION OUTPUT ;
    USE SIGNAL ;
    PORT
      LAYER M4 ;
        RECT  0 55.92 0.192 55.944 ;
    END
  END od[314]
  PIN od[315]
    DIRECTION OUTPUT ;
    USE SIGNAL ;
    PORT
      LAYER M4 ;
        RECT  0 56.112 0.192 56.136 ;
    END
  END od[315]
  PIN od[316]
    DIRECTION OUTPUT ;
    USE SIGNAL ;
    PORT
      LAYER M4 ;
        RECT  0 56.256 0.192 56.28 ;
    END
  END od[316]
  PIN od[317]
    DIRECTION OUTPUT ;
    USE SIGNAL ;
    PORT
      LAYER M4 ;
        RECT  0 56.448 0.192 56.472 ;
    END
  END od[317]
  PIN od[318]
    DIRECTION OUTPUT ;
    USE SIGNAL ;
    PORT
      LAYER M4 ;
        RECT  0 56.592 0.192 56.616 ;
    END
  END od[318]
  PIN od[319]
    DIRECTION OUTPUT ;
    USE SIGNAL ;
    PORT
      LAYER M4 ;
        RECT  0 56.736 0.192 56.76 ;
    END
  END od[319]
  PIN od[31]
    DIRECTION OUTPUT ;
    USE SIGNAL ;
    PORT
      LAYER M4 ;
        RECT  0 9.648 0.192 9.672 ;
    END
  END od[31]
  PIN od[320]
    DIRECTION OUTPUT ;
    USE SIGNAL ;
    PORT
      LAYER M4 ;
        RECT  0 56.928 0.192 56.952 ;
    END
  END od[320]
  PIN od[321]
    DIRECTION OUTPUT ;
    USE SIGNAL ;
    PORT
      LAYER M4 ;
        RECT  0 57.072 0.192 57.096 ;
    END
  END od[321]
  PIN od[322]
    DIRECTION OUTPUT ;
    USE SIGNAL ;
    PORT
      LAYER M4 ;
        RECT  0 57.264 0.192 57.288 ;
    END
  END od[322]
  PIN od[323]
    DIRECTION OUTPUT ;
    USE SIGNAL ;
    PORT
      LAYER M4 ;
        RECT  0 57.408 0.192 57.432 ;
    END
  END od[323]
  PIN od[324]
    DIRECTION OUTPUT ;
    USE SIGNAL ;
    PORT
      LAYER M4 ;
        RECT  0 57.552 0.192 57.576 ;
    END
  END od[324]
  PIN od[325]
    DIRECTION OUTPUT ;
    USE SIGNAL ;
    PORT
      LAYER M4 ;
        RECT  0 57.744 0.192 57.768 ;
    END
  END od[325]
  PIN od[326]
    DIRECTION OUTPUT ;
    USE SIGNAL ;
    PORT
      LAYER M4 ;
        RECT  0 57.888 0.192 57.912 ;
    END
  END od[326]
  PIN od[327]
    DIRECTION OUTPUT ;
    USE SIGNAL ;
    PORT
      LAYER M4 ;
        RECT  0 58.08 0.192 58.104 ;
    END
  END od[327]
  PIN od[328]
    DIRECTION OUTPUT ;
    USE SIGNAL ;
    PORT
      LAYER M4 ;
        RECT  0 58.224 0.192 58.248 ;
    END
  END od[328]
  PIN od[329]
    DIRECTION OUTPUT ;
    USE SIGNAL ;
    PORT
      LAYER M4 ;
        RECT  0 58.416 0.192 58.44 ;
    END
  END od[329]
  PIN od[32]
    DIRECTION OUTPUT ;
    USE SIGNAL ;
    PORT
      LAYER M4 ;
        RECT  0 9.792 0.192 9.816 ;
    END
  END od[32]
  PIN od[330]
    DIRECTION OUTPUT ;
    USE SIGNAL ;
    PORT
      LAYER M4 ;
        RECT  0 58.56 0.192 58.584 ;
    END
  END od[330]
  PIN od[331]
    DIRECTION OUTPUT ;
    USE SIGNAL ;
    PORT
      LAYER M4 ;
        RECT  0 58.704 0.192 58.728 ;
    END
  END od[331]
  PIN od[332]
    DIRECTION OUTPUT ;
    USE SIGNAL ;
    PORT
      LAYER M4 ;
        RECT  0 58.896 0.192 58.92 ;
    END
  END od[332]
  PIN od[333]
    DIRECTION OUTPUT ;
    USE SIGNAL ;
    PORT
      LAYER M4 ;
        RECT  0 59.04 0.192 59.064 ;
    END
  END od[333]
  PIN od[334]
    DIRECTION OUTPUT ;
    USE SIGNAL ;
    PORT
      LAYER M4 ;
        RECT  0 59.232 0.192 59.256 ;
    END
  END od[334]
  PIN od[335]
    DIRECTION OUTPUT ;
    USE SIGNAL ;
    PORT
      LAYER M4 ;
        RECT  0 59.376 0.192 59.4 ;
    END
  END od[335]
  PIN od[336]
    DIRECTION OUTPUT ;
    USE SIGNAL ;
    PORT
      LAYER M4 ;
        RECT  0 59.52 0.192 59.544 ;
    END
  END od[336]
  PIN od[337]
    DIRECTION OUTPUT ;
    USE SIGNAL ;
    PORT
      LAYER M4 ;
        RECT  0 59.712 0.192 59.736 ;
    END
  END od[337]
  PIN od[338]
    DIRECTION OUTPUT ;
    USE SIGNAL ;
    PORT
      LAYER M4 ;
        RECT  0 59.856 0.192 59.88 ;
    END
  END od[338]
  PIN od[339]
    DIRECTION OUTPUT ;
    USE SIGNAL ;
    PORT
      LAYER M4 ;
        RECT  0 60.048 0.192 60.072 ;
    END
  END od[339]
  PIN od[33]
    DIRECTION OUTPUT ;
    USE SIGNAL ;
    PORT
      LAYER M4 ;
        RECT  0 9.984 0.192 10.008 ;
    END
  END od[33]
  PIN od[340]
    DIRECTION OUTPUT ;
    USE SIGNAL ;
    PORT
      LAYER M4 ;
        RECT  0 60.192 0.192 60.216 ;
    END
  END od[340]
  PIN od[341]
    DIRECTION OUTPUT ;
    USE SIGNAL ;
    PORT
      LAYER M4 ;
        RECT  0 60.336 0.192 60.36 ;
    END
  END od[341]
  PIN od[342]
    DIRECTION OUTPUT ;
    USE SIGNAL ;
    PORT
      LAYER M4 ;
        RECT  0 60.528 0.192 60.552 ;
    END
  END od[342]
  PIN od[343]
    DIRECTION OUTPUT ;
    USE SIGNAL ;
    PORT
      LAYER M4 ;
        RECT  0 60.672 0.192 60.696 ;
    END
  END od[343]
  PIN od[344]
    DIRECTION OUTPUT ;
    USE SIGNAL ;
    PORT
      LAYER M4 ;
        RECT  0 60.864 0.192 60.888 ;
    END
  END od[344]
  PIN od[345]
    DIRECTION OUTPUT ;
    USE SIGNAL ;
    PORT
      LAYER M4 ;
        RECT  0 61.008 0.192 61.032 ;
    END
  END od[345]
  PIN od[346]
    DIRECTION OUTPUT ;
    USE SIGNAL ;
    PORT
      LAYER M4 ;
        RECT  0 61.152 0.192 61.176 ;
    END
  END od[346]
  PIN od[347]
    DIRECTION OUTPUT ;
    USE SIGNAL ;
    PORT
      LAYER M4 ;
        RECT  0 61.344 0.192 61.368 ;
    END
  END od[347]
  PIN od[348]
    DIRECTION OUTPUT ;
    USE SIGNAL ;
    PORT
      LAYER M4 ;
        RECT  0 61.488 0.192 61.512 ;
    END
  END od[348]
  PIN od[349]
    DIRECTION OUTPUT ;
    USE SIGNAL ;
    PORT
      LAYER M4 ;
        RECT  0 61.68 0.192 61.704 ;
    END
  END od[349]
  PIN od[34]
    DIRECTION OUTPUT ;
    USE SIGNAL ;
    PORT
      LAYER M4 ;
        RECT  0 10.128 0.192 10.152 ;
    END
  END od[34]
  PIN od[350]
    DIRECTION OUTPUT ;
    USE SIGNAL ;
    PORT
      LAYER M4 ;
        RECT  0 61.824 0.192 61.848 ;
    END
  END od[350]
  PIN od[351]
    DIRECTION OUTPUT ;
    USE SIGNAL ;
    PORT
      LAYER M4 ;
        RECT  0 61.968 0.192 61.992 ;
    END
  END od[351]
  PIN od[352]
    DIRECTION OUTPUT ;
    USE SIGNAL ;
    PORT
      LAYER M4 ;
        RECT  0 62.16 0.192 62.184 ;
    END
  END od[352]
  PIN od[353]
    DIRECTION OUTPUT ;
    USE SIGNAL ;
    PORT
      LAYER M4 ;
        RECT  0 62.304 0.192 62.328 ;
    END
  END od[353]
  PIN od[354]
    DIRECTION OUTPUT ;
    USE SIGNAL ;
    PORT
      LAYER M4 ;
        RECT  0 62.496 0.192 62.52 ;
    END
  END od[354]
  PIN od[355]
    DIRECTION OUTPUT ;
    USE SIGNAL ;
    PORT
      LAYER M4 ;
        RECT  0 62.64 0.192 62.664 ;
    END
  END od[355]
  PIN od[356]
    DIRECTION OUTPUT ;
    USE SIGNAL ;
    PORT
      LAYER M4 ;
        RECT  0 62.832 0.192 62.856 ;
    END
  END od[356]
  PIN od[357]
    DIRECTION OUTPUT ;
    USE SIGNAL ;
    PORT
      LAYER M4 ;
        RECT  0 62.976 0.192 63 ;
    END
  END od[357]
  PIN od[358]
    DIRECTION OUTPUT ;
    USE SIGNAL ;
    PORT
      LAYER M4 ;
        RECT  0 63.12 0.192 63.144 ;
    END
  END od[358]
  PIN od[359]
    DIRECTION OUTPUT ;
    USE SIGNAL ;
    PORT
      LAYER M4 ;
        RECT  0 63.312 0.192 63.336 ;
    END
  END od[359]
  PIN od[35]
    DIRECTION OUTPUT ;
    USE SIGNAL ;
    PORT
      LAYER M4 ;
        RECT  0 10.32 0.192 10.344 ;
    END
  END od[35]
  PIN od[360]
    DIRECTION OUTPUT ;
    USE SIGNAL ;
    PORT
      LAYER M4 ;
        RECT  0 63.456 0.192 63.48 ;
    END
  END od[360]
  PIN od[361]
    DIRECTION OUTPUT ;
    USE SIGNAL ;
    PORT
      LAYER M4 ;
        RECT  0 63.648 0.192 63.672 ;
    END
  END od[361]
  PIN od[362]
    DIRECTION OUTPUT ;
    USE SIGNAL ;
    PORT
      LAYER M4 ;
        RECT  0 63.792 0.192 63.816 ;
    END
  END od[362]
  PIN od[363]
    DIRECTION OUTPUT ;
    USE SIGNAL ;
    PORT
      LAYER M4 ;
        RECT  0 63.936 0.192 63.96 ;
    END
  END od[363]
  PIN od[364]
    DIRECTION OUTPUT ;
    USE SIGNAL ;
    PORT
      LAYER M4 ;
        RECT  0 64.128 0.192 64.152 ;
    END
  END od[364]
  PIN od[365]
    DIRECTION OUTPUT ;
    USE SIGNAL ;
    PORT
      LAYER M4 ;
        RECT  0 64.272 0.192 64.296 ;
    END
  END od[365]
  PIN od[366]
    DIRECTION OUTPUT ;
    USE SIGNAL ;
    PORT
      LAYER M4 ;
        RECT  0 64.464 0.192 64.488 ;
    END
  END od[366]
  PIN od[367]
    DIRECTION OUTPUT ;
    USE SIGNAL ;
    PORT
      LAYER M4 ;
        RECT  0 64.608 0.192 64.632 ;
    END
  END od[367]
  PIN od[368]
    DIRECTION OUTPUT ;
    USE SIGNAL ;
    PORT
      LAYER M4 ;
        RECT  0 64.752 0.192 64.776 ;
    END
  END od[368]
  PIN od[369]
    DIRECTION OUTPUT ;
    USE SIGNAL ;
    PORT
      LAYER M4 ;
        RECT  0 64.944 0.192 64.968 ;
    END
  END od[369]
  PIN od[36]
    DIRECTION OUTPUT ;
    USE SIGNAL ;
    PORT
      LAYER M4 ;
        RECT  0 10.464 0.192 10.488 ;
    END
  END od[36]
  PIN od[370]
    DIRECTION OUTPUT ;
    USE SIGNAL ;
    PORT
      LAYER M4 ;
        RECT  0 65.088 0.192 65.112 ;
    END
  END od[370]
  PIN od[371]
    DIRECTION OUTPUT ;
    USE SIGNAL ;
    PORT
      LAYER M4 ;
        RECT  0 65.28 0.192 65.304 ;
    END
  END od[371]
  PIN od[372]
    DIRECTION OUTPUT ;
    USE SIGNAL ;
    PORT
      LAYER M4 ;
        RECT  0 65.424 0.192 65.448 ;
    END
  END od[372]
  PIN od[373]
    DIRECTION OUTPUT ;
    USE SIGNAL ;
    PORT
      LAYER M4 ;
        RECT  0 65.568 0.192 65.592 ;
    END
  END od[373]
  PIN od[374]
    DIRECTION OUTPUT ;
    USE SIGNAL ;
    PORT
      LAYER M4 ;
        RECT  0 65.76 0.192 65.784 ;
    END
  END od[374]
  PIN od[375]
    DIRECTION OUTPUT ;
    USE SIGNAL ;
    PORT
      LAYER M4 ;
        RECT  0 65.904 0.192 65.928 ;
    END
  END od[375]
  PIN od[376]
    DIRECTION OUTPUT ;
    USE SIGNAL ;
    PORT
      LAYER M4 ;
        RECT  0 66.096 0.192 66.12 ;
    END
  END od[376]
  PIN od[377]
    DIRECTION OUTPUT ;
    USE SIGNAL ;
    PORT
      LAYER M4 ;
        RECT  0 66.24 0.192 66.264 ;
    END
  END od[377]
  PIN od[378]
    DIRECTION OUTPUT ;
    USE SIGNAL ;
    PORT
      LAYER M4 ;
        RECT  0 66.384 0.192 66.408 ;
    END
  END od[378]
  PIN od[379]
    DIRECTION OUTPUT ;
    USE SIGNAL ;
    PORT
      LAYER M4 ;
        RECT  0 66.576 0.192 66.6 ;
    END
  END od[379]
  PIN od[37]
    DIRECTION OUTPUT ;
    USE SIGNAL ;
    PORT
      LAYER M4 ;
        RECT  0 10.608 0.192 10.632 ;
    END
  END od[37]
  PIN od[380]
    DIRECTION OUTPUT ;
    USE SIGNAL ;
    PORT
      LAYER M4 ;
        RECT  0 66.72 0.192 66.744 ;
    END
  END od[380]
  PIN od[381]
    DIRECTION OUTPUT ;
    USE SIGNAL ;
    PORT
      LAYER M4 ;
        RECT  0 66.912 0.192 66.936 ;
    END
  END od[381]
  PIN od[382]
    DIRECTION OUTPUT ;
    USE SIGNAL ;
    PORT
      LAYER M4 ;
        RECT  0 67.056 0.192 67.08 ;
    END
  END od[382]
  PIN od[383]
    DIRECTION OUTPUT ;
    USE SIGNAL ;
    PORT
      LAYER M4 ;
        RECT  0 67.248 0.192 67.272 ;
    END
  END od[383]
  PIN od[384]
    DIRECTION OUTPUT ;
    USE SIGNAL ;
    PORT
      LAYER M4 ;
        RECT  0 67.392 0.192 67.416 ;
    END
  END od[384]
  PIN od[385]
    DIRECTION OUTPUT ;
    USE SIGNAL ;
    PORT
      LAYER M4 ;
        RECT  0 67.536 0.192 67.56 ;
    END
  END od[385]
  PIN od[386]
    DIRECTION OUTPUT ;
    USE SIGNAL ;
    PORT
      LAYER M4 ;
        RECT  0 67.728 0.192 67.752 ;
    END
  END od[386]
  PIN od[387]
    DIRECTION OUTPUT ;
    USE SIGNAL ;
    PORT
      LAYER M4 ;
        RECT  0 67.872 0.192 67.896 ;
    END
  END od[387]
  PIN od[388]
    DIRECTION OUTPUT ;
    USE SIGNAL ;
    PORT
      LAYER M4 ;
        RECT  0 68.064 0.192 68.088 ;
    END
  END od[388]
  PIN od[389]
    DIRECTION OUTPUT ;
    USE SIGNAL ;
    PORT
      LAYER M4 ;
        RECT  0 68.208 0.192 68.232 ;
    END
  END od[389]
  PIN od[38]
    DIRECTION OUTPUT ;
    USE SIGNAL ;
    PORT
      LAYER M4 ;
        RECT  0 10.8 0.192 10.824 ;
    END
  END od[38]
  PIN od[390]
    DIRECTION OUTPUT ;
    USE SIGNAL ;
    PORT
      LAYER M4 ;
        RECT  0 68.352 0.192 68.376 ;
    END
  END od[390]
  PIN od[391]
    DIRECTION OUTPUT ;
    USE SIGNAL ;
    PORT
      LAYER M4 ;
        RECT  0 68.544 0.192 68.568 ;
    END
  END od[391]
  PIN od[392]
    DIRECTION OUTPUT ;
    USE SIGNAL ;
    PORT
      LAYER M4 ;
        RECT  0 68.688 0.192 68.712 ;
    END
  END od[392]
  PIN od[393]
    DIRECTION OUTPUT ;
    USE SIGNAL ;
    PORT
      LAYER M4 ;
        RECT  0 68.88 0.192 68.904 ;
    END
  END od[393]
  PIN od[394]
    DIRECTION OUTPUT ;
    USE SIGNAL ;
    PORT
      LAYER M4 ;
        RECT  0 69.024 0.192 69.048 ;
    END
  END od[394]
  PIN od[395]
    DIRECTION OUTPUT ;
    USE SIGNAL ;
    PORT
      LAYER M4 ;
        RECT  0 69.168 0.192 69.192 ;
    END
  END od[395]
  PIN od[396]
    DIRECTION OUTPUT ;
    USE SIGNAL ;
    PORT
      LAYER M4 ;
        RECT  0 69.36 0.192 69.384 ;
    END
  END od[396]
  PIN od[397]
    DIRECTION OUTPUT ;
    USE SIGNAL ;
    PORT
      LAYER M4 ;
        RECT  0 69.504 0.192 69.528 ;
    END
  END od[397]
  PIN od[398]
    DIRECTION OUTPUT ;
    USE SIGNAL ;
    PORT
      LAYER M4 ;
        RECT  0 69.696 0.192 69.72 ;
    END
  END od[398]
  PIN od[399]
    DIRECTION OUTPUT ;
    USE SIGNAL ;
    PORT
      LAYER M4 ;
        RECT  0 69.84 0.192 69.864 ;
    END
  END od[399]
  PIN od[39]
    DIRECTION OUTPUT ;
    USE SIGNAL ;
    PORT
      LAYER M4 ;
        RECT  0 10.944 0.192 10.968 ;
    END
  END od[39]
  PIN od[3]
    DIRECTION OUTPUT ;
    USE SIGNAL ;
    PORT
      LAYER M4 ;
        RECT  0 5.088 0.192 5.112 ;
    END
  END od[3]
  PIN od[400]
    DIRECTION OUTPUT ;
    USE SIGNAL ;
    PORT
      LAYER M4 ;
        RECT  0 69.984 0.192 70.008 ;
    END
  END od[400]
  PIN od[401]
    DIRECTION OUTPUT ;
    USE SIGNAL ;
    PORT
      LAYER M4 ;
        RECT  0 70.176 0.192 70.2 ;
    END
  END od[401]
  PIN od[402]
    DIRECTION OUTPUT ;
    USE SIGNAL ;
    PORT
      LAYER M4 ;
        RECT  0 70.32 0.192 70.344 ;
    END
  END od[402]
  PIN od[403]
    DIRECTION OUTPUT ;
    USE SIGNAL ;
    PORT
      LAYER M4 ;
        RECT  0 70.512 0.192 70.536 ;
    END
  END od[403]
  PIN od[404]
    DIRECTION OUTPUT ;
    USE SIGNAL ;
    PORT
      LAYER M4 ;
        RECT  0 70.656 0.192 70.68 ;
    END
  END od[404]
  PIN od[405]
    DIRECTION OUTPUT ;
    USE SIGNAL ;
    PORT
      LAYER M4 ;
        RECT  0 70.848 0.192 70.872 ;
    END
  END od[405]
  PIN od[406]
    DIRECTION OUTPUT ;
    USE SIGNAL ;
    PORT
      LAYER M4 ;
        RECT  0 70.992 0.192 71.016 ;
    END
  END od[406]
  PIN od[407]
    DIRECTION OUTPUT ;
    USE SIGNAL ;
    PORT
      LAYER M4 ;
        RECT  0 71.136 0.192 71.16 ;
    END
  END od[407]
  PIN od[408]
    DIRECTION OUTPUT ;
    USE SIGNAL ;
    PORT
      LAYER M4 ;
        RECT  0 71.328 0.192 71.352 ;
    END
  END od[408]
  PIN od[409]
    DIRECTION OUTPUT ;
    USE SIGNAL ;
    PORT
      LAYER M4 ;
        RECT  0 71.472 0.192 71.496 ;
    END
  END od[409]
  PIN od[40]
    DIRECTION OUTPUT ;
    USE SIGNAL ;
    PORT
      LAYER M4 ;
        RECT  0 11.136 0.192 11.16 ;
    END
  END od[40]
  PIN od[410]
    DIRECTION OUTPUT ;
    USE SIGNAL ;
    PORT
      LAYER M4 ;
        RECT  0 71.664 0.192 71.688 ;
    END
  END od[410]
  PIN od[411]
    DIRECTION OUTPUT ;
    USE SIGNAL ;
    PORT
      LAYER M4 ;
        RECT  0 71.808 0.192 71.832 ;
    END
  END od[411]
  PIN od[412]
    DIRECTION OUTPUT ;
    USE SIGNAL ;
    PORT
      LAYER M4 ;
        RECT  0 71.952 0.192 71.976 ;
    END
  END od[412]
  PIN od[413]
    DIRECTION OUTPUT ;
    USE SIGNAL ;
    PORT
      LAYER M4 ;
        RECT  0 72.144 0.192 72.168 ;
    END
  END od[413]
  PIN od[414]
    DIRECTION OUTPUT ;
    USE SIGNAL ;
    PORT
      LAYER M4 ;
        RECT  0 72.288 0.192 72.312 ;
    END
  END od[414]
  PIN od[415]
    DIRECTION OUTPUT ;
    USE SIGNAL ;
    PORT
      LAYER M4 ;
        RECT  0 72.48 0.192 72.504 ;
    END
  END od[415]
  PIN od[416]
    DIRECTION OUTPUT ;
    USE SIGNAL ;
    PORT
      LAYER M4 ;
        RECT  0 72.624 0.192 72.648 ;
    END
  END od[416]
  PIN od[417]
    DIRECTION OUTPUT ;
    USE SIGNAL ;
    PORT
      LAYER M4 ;
        RECT  0 72.768 0.192 72.792 ;
    END
  END od[417]
  PIN od[418]
    DIRECTION OUTPUT ;
    USE SIGNAL ;
    PORT
      LAYER M4 ;
        RECT  0 72.96 0.192 72.984 ;
    END
  END od[418]
  PIN od[419]
    DIRECTION OUTPUT ;
    USE SIGNAL ;
    PORT
      LAYER M4 ;
        RECT  0 73.104 0.192 73.128 ;
    END
  END od[419]
  PIN od[41]
    DIRECTION OUTPUT ;
    USE SIGNAL ;
    PORT
      LAYER M4 ;
        RECT  0 11.28 0.192 11.304 ;
    END
  END od[41]
  PIN od[420]
    DIRECTION OUTPUT ;
    USE SIGNAL ;
    PORT
      LAYER M4 ;
        RECT  0 73.296 0.192 73.32 ;
    END
  END od[420]
  PIN od[421]
    DIRECTION OUTPUT ;
    USE SIGNAL ;
    PORT
      LAYER M4 ;
        RECT  0 73.44 0.192 73.464 ;
    END
  END od[421]
  PIN od[422]
    DIRECTION OUTPUT ;
    USE SIGNAL ;
    PORT
      LAYER M4 ;
        RECT  0 73.584 0.192 73.608 ;
    END
  END od[422]
  PIN od[423]
    DIRECTION OUTPUT ;
    USE SIGNAL ;
    PORT
      LAYER M4 ;
        RECT  0 73.776 0.192 73.8 ;
    END
  END od[423]
  PIN od[424]
    DIRECTION OUTPUT ;
    USE SIGNAL ;
    PORT
      LAYER M4 ;
        RECT  0 73.92 0.192 73.944 ;
    END
  END od[424]
  PIN od[425]
    DIRECTION OUTPUT ;
    USE SIGNAL ;
    PORT
      LAYER M4 ;
        RECT  0 74.112 0.192 74.136 ;
    END
  END od[425]
  PIN od[426]
    DIRECTION OUTPUT ;
    USE SIGNAL ;
    PORT
      LAYER M4 ;
        RECT  0 74.256 0.192 74.28 ;
    END
  END od[426]
  PIN od[427]
    DIRECTION OUTPUT ;
    USE SIGNAL ;
    PORT
      LAYER M4 ;
        RECT  0 74.4 0.192 74.424 ;
    END
  END od[427]
  PIN od[428]
    DIRECTION OUTPUT ;
    USE SIGNAL ;
    PORT
      LAYER M4 ;
        RECT  0 74.592 0.192 74.616 ;
    END
  END od[428]
  PIN od[429]
    DIRECTION OUTPUT ;
    USE SIGNAL ;
    PORT
      LAYER M4 ;
        RECT  0 74.736 0.192 74.76 ;
    END
  END od[429]
  PIN od[42]
    DIRECTION OUTPUT ;
    USE SIGNAL ;
    PORT
      LAYER M4 ;
        RECT  0 11.424 0.192 11.448 ;
    END
  END od[42]
  PIN od[430]
    DIRECTION OUTPUT ;
    USE SIGNAL ;
    PORT
      LAYER M4 ;
        RECT  0 74.928 0.192 74.952 ;
    END
  END od[430]
  PIN od[431]
    DIRECTION OUTPUT ;
    USE SIGNAL ;
    PORT
      LAYER M4 ;
        RECT  0 75.072 0.192 75.096 ;
    END
  END od[431]
  PIN od[432]
    DIRECTION OUTPUT ;
    USE SIGNAL ;
    PORT
      LAYER M4 ;
        RECT  0 75.264 0.192 75.288 ;
    END
  END od[432]
  PIN od[433]
    DIRECTION OUTPUT ;
    USE SIGNAL ;
    PORT
      LAYER M4 ;
        RECT  0 75.408 0.192 75.432 ;
    END
  END od[433]
  PIN od[434]
    DIRECTION OUTPUT ;
    USE SIGNAL ;
    PORT
      LAYER M4 ;
        RECT  0 75.552 0.192 75.576 ;
    END
  END od[434]
  PIN od[435]
    DIRECTION OUTPUT ;
    USE SIGNAL ;
    PORT
      LAYER M4 ;
        RECT  0 75.744 0.192 75.768 ;
    END
  END od[435]
  PIN od[436]
    DIRECTION OUTPUT ;
    USE SIGNAL ;
    PORT
      LAYER M4 ;
        RECT  0 75.888 0.192 75.912 ;
    END
  END od[436]
  PIN od[437]
    DIRECTION OUTPUT ;
    USE SIGNAL ;
    PORT
      LAYER M4 ;
        RECT  0 76.08 0.192 76.104 ;
    END
  END od[437]
  PIN od[438]
    DIRECTION OUTPUT ;
    USE SIGNAL ;
    PORT
      LAYER M4 ;
        RECT  0 76.224 0.192 76.248 ;
    END
  END od[438]
  PIN od[439]
    DIRECTION OUTPUT ;
    USE SIGNAL ;
    PORT
      LAYER M4 ;
        RECT  0 76.368 0.192 76.392 ;
    END
  END od[439]
  PIN od[43]
    DIRECTION OUTPUT ;
    USE SIGNAL ;
    PORT
      LAYER M4 ;
        RECT  0 11.616 0.192 11.64 ;
    END
  END od[43]
  PIN od[440]
    DIRECTION OUTPUT ;
    USE SIGNAL ;
    PORT
      LAYER M4 ;
        RECT  0 76.56 0.192 76.584 ;
    END
  END od[440]
  PIN od[441]
    DIRECTION OUTPUT ;
    USE SIGNAL ;
    PORT
      LAYER M4 ;
        RECT  0 76.704 0.192 76.728 ;
    END
  END od[441]
  PIN od[442]
    DIRECTION OUTPUT ;
    USE SIGNAL ;
    PORT
      LAYER M4 ;
        RECT  0 76.896 0.192 76.92 ;
    END
  END od[442]
  PIN od[443]
    DIRECTION OUTPUT ;
    USE SIGNAL ;
    PORT
      LAYER M4 ;
        RECT  0 77.04 0.192 77.064 ;
    END
  END od[443]
  PIN od[444]
    DIRECTION OUTPUT ;
    USE SIGNAL ;
    PORT
      LAYER M4 ;
        RECT  0 77.184 0.192 77.208 ;
    END
  END od[444]
  PIN od[445]
    DIRECTION OUTPUT ;
    USE SIGNAL ;
    PORT
      LAYER M4 ;
        RECT  0 77.376 0.192 77.4 ;
    END
  END od[445]
  PIN od[446]
    DIRECTION OUTPUT ;
    USE SIGNAL ;
    PORT
      LAYER M4 ;
        RECT  0 77.52 0.192 77.544 ;
    END
  END od[446]
  PIN od[447]
    DIRECTION OUTPUT ;
    USE SIGNAL ;
    PORT
      LAYER M4 ;
        RECT  0 77.712 0.192 77.736 ;
    END
  END od[447]
  PIN od[448]
    DIRECTION OUTPUT ;
    USE SIGNAL ;
    PORT
      LAYER M4 ;
        RECT  0 77.856 0.192 77.88 ;
    END
  END od[448]
  PIN od[449]
    DIRECTION OUTPUT ;
    USE SIGNAL ;
    PORT
      LAYER M4 ;
        RECT  0 78 0.192 78.024 ;
    END
  END od[449]
  PIN od[44]
    DIRECTION OUTPUT ;
    USE SIGNAL ;
    PORT
      LAYER M4 ;
        RECT  0 11.76 0.192 11.784 ;
    END
  END od[44]
  PIN od[450]
    DIRECTION OUTPUT ;
    USE SIGNAL ;
    PORT
      LAYER M4 ;
        RECT  0 78.192 0.192 78.216 ;
    END
  END od[450]
  PIN od[451]
    DIRECTION OUTPUT ;
    USE SIGNAL ;
    PORT
      LAYER M4 ;
        RECT  0 78.336 0.192 78.36 ;
    END
  END od[451]
  PIN od[452]
    DIRECTION OUTPUT ;
    USE SIGNAL ;
    PORT
      LAYER M4 ;
        RECT  0 78.528 0.192 78.552 ;
    END
  END od[452]
  PIN od[453]
    DIRECTION OUTPUT ;
    USE SIGNAL ;
    PORT
      LAYER M4 ;
        RECT  0 78.672 0.192 78.696 ;
    END
  END od[453]
  PIN od[454]
    DIRECTION OUTPUT ;
    USE SIGNAL ;
    PORT
      LAYER M4 ;
        RECT  0 78.816 0.192 78.84 ;
    END
  END od[454]
  PIN od[455]
    DIRECTION OUTPUT ;
    USE SIGNAL ;
    PORT
      LAYER M4 ;
        RECT  0 79.008 0.192 79.032 ;
    END
  END od[455]
  PIN od[456]
    DIRECTION OUTPUT ;
    USE SIGNAL ;
    PORT
      LAYER M4 ;
        RECT  0 79.152 0.192 79.176 ;
    END
  END od[456]
  PIN od[457]
    DIRECTION OUTPUT ;
    USE SIGNAL ;
    PORT
      LAYER M4 ;
        RECT  0 79.344 0.192 79.368 ;
    END
  END od[457]
  PIN od[458]
    DIRECTION OUTPUT ;
    USE SIGNAL ;
    PORT
      LAYER M4 ;
        RECT  0 79.488 0.192 79.512 ;
    END
  END od[458]
  PIN od[459]
    DIRECTION OUTPUT ;
    USE SIGNAL ;
    PORT
      LAYER M4 ;
        RECT  0 79.68 0.192 79.704 ;
    END
  END od[459]
  PIN od[45]
    DIRECTION OUTPUT ;
    USE SIGNAL ;
    PORT
      LAYER M4 ;
        RECT  0 11.952 0.192 11.976 ;
    END
  END od[45]
  PIN od[460]
    DIRECTION OUTPUT ;
    USE SIGNAL ;
    PORT
      LAYER M4 ;
        RECT  0 79.824 0.192 79.848 ;
    END
  END od[460]
  PIN od[461]
    DIRECTION OUTPUT ;
    USE SIGNAL ;
    PORT
      LAYER M4 ;
        RECT  0 79.968 0.192 79.992 ;
    END
  END od[461]
  PIN od[462]
    DIRECTION OUTPUT ;
    USE SIGNAL ;
    PORT
      LAYER M4 ;
        RECT  0 80.16 0.192 80.184 ;
    END
  END od[462]
  PIN od[463]
    DIRECTION OUTPUT ;
    USE SIGNAL ;
    PORT
      LAYER M4 ;
        RECT  0 80.304 0.192 80.328 ;
    END
  END od[463]
  PIN od[464]
    DIRECTION OUTPUT ;
    USE SIGNAL ;
    PORT
      LAYER M4 ;
        RECT  0 80.496 0.192 80.52 ;
    END
  END od[464]
  PIN od[465]
    DIRECTION OUTPUT ;
    USE SIGNAL ;
    PORT
      LAYER M4 ;
        RECT  0 80.64 0.192 80.664 ;
    END
  END od[465]
  PIN od[466]
    DIRECTION OUTPUT ;
    USE SIGNAL ;
    PORT
      LAYER M4 ;
        RECT  0 80.784 0.192 80.808 ;
    END
  END od[466]
  PIN od[467]
    DIRECTION OUTPUT ;
    USE SIGNAL ;
    PORT
      LAYER M4 ;
        RECT  0 80.976 0.192 81 ;
    END
  END od[467]
  PIN od[468]
    DIRECTION OUTPUT ;
    USE SIGNAL ;
    PORT
      LAYER M4 ;
        RECT  0 81.12 0.192 81.144 ;
    END
  END od[468]
  PIN od[469]
    DIRECTION OUTPUT ;
    USE SIGNAL ;
    PORT
      LAYER M4 ;
        RECT  0 81.312 0.192 81.336 ;
    END
  END od[469]
  PIN od[46]
    DIRECTION OUTPUT ;
    USE SIGNAL ;
    PORT
      LAYER M4 ;
        RECT  0 12.096 0.192 12.12 ;
    END
  END od[46]
  PIN od[470]
    DIRECTION OUTPUT ;
    USE SIGNAL ;
    PORT
      LAYER M4 ;
        RECT  0 81.456 0.192 81.48 ;
    END
  END od[470]
  PIN od[471]
    DIRECTION OUTPUT ;
    USE SIGNAL ;
    PORT
      LAYER M4 ;
        RECT  0 81.6 0.192 81.624 ;
    END
  END od[471]
  PIN od[472]
    DIRECTION OUTPUT ;
    USE SIGNAL ;
    PORT
      LAYER M4 ;
        RECT  0 81.792 0.192 81.816 ;
    END
  END od[472]
  PIN od[473]
    DIRECTION OUTPUT ;
    USE SIGNAL ;
    PORT
      LAYER M4 ;
        RECT  0 81.936 0.192 81.96 ;
    END
  END od[473]
  PIN od[474]
    DIRECTION OUTPUT ;
    USE SIGNAL ;
    PORT
      LAYER M4 ;
        RECT  0 82.128 0.192 82.152 ;
    END
  END od[474]
  PIN od[475]
    DIRECTION OUTPUT ;
    USE SIGNAL ;
    PORT
      LAYER M4 ;
        RECT  0 82.272 0.192 82.296 ;
    END
  END od[475]
  PIN od[476]
    DIRECTION OUTPUT ;
    USE SIGNAL ;
    PORT
      LAYER M4 ;
        RECT  0 82.416 0.192 82.44 ;
    END
  END od[476]
  PIN od[477]
    DIRECTION OUTPUT ;
    USE SIGNAL ;
    PORT
      LAYER M4 ;
        RECT  0 82.608 0.192 82.632 ;
    END
  END od[477]
  PIN od[478]
    DIRECTION OUTPUT ;
    USE SIGNAL ;
    PORT
      LAYER M4 ;
        RECT  0 82.752 0.192 82.776 ;
    END
  END od[478]
  PIN od[479]
    DIRECTION OUTPUT ;
    USE SIGNAL ;
    PORT
      LAYER M4 ;
        RECT  0 82.944 0.192 82.968 ;
    END
  END od[479]
  PIN od[47]
    DIRECTION OUTPUT ;
    USE SIGNAL ;
    PORT
      LAYER M4 ;
        RECT  0 12.288 0.192 12.312 ;
    END
  END od[47]
  PIN od[480]
    DIRECTION OUTPUT ;
    USE SIGNAL ;
    PORT
      LAYER M4 ;
        RECT  0 83.088 0.192 83.112 ;
    END
  END od[480]
  PIN od[481]
    DIRECTION OUTPUT ;
    USE SIGNAL ;
    PORT
      LAYER M4 ;
        RECT  0 83.232 0.192 83.256 ;
    END
  END od[481]
  PIN od[482]
    DIRECTION OUTPUT ;
    USE SIGNAL ;
    PORT
      LAYER M4 ;
        RECT  0 83.424 0.192 83.448 ;
    END
  END od[482]
  PIN od[483]
    DIRECTION OUTPUT ;
    USE SIGNAL ;
    PORT
      LAYER M4 ;
        RECT  0 83.568 0.192 83.592 ;
    END
  END od[483]
  PIN od[484]
    DIRECTION OUTPUT ;
    USE SIGNAL ;
    PORT
      LAYER M4 ;
        RECT  0 83.76 0.192 83.784 ;
    END
  END od[484]
  PIN od[485]
    DIRECTION OUTPUT ;
    USE SIGNAL ;
    PORT
      LAYER M4 ;
        RECT  0 83.904 0.192 83.928 ;
    END
  END od[485]
  PIN od[486]
    DIRECTION OUTPUT ;
    USE SIGNAL ;
    PORT
      LAYER M4 ;
        RECT  0 84.096 0.192 84.12 ;
    END
  END od[486]
  PIN od[487]
    DIRECTION OUTPUT ;
    USE SIGNAL ;
    PORT
      LAYER M4 ;
        RECT  0 84.24 0.192 84.264 ;
    END
  END od[487]
  PIN od[488]
    DIRECTION OUTPUT ;
    USE SIGNAL ;
    PORT
      LAYER M4 ;
        RECT  0 84.384 0.192 84.408 ;
    END
  END od[488]
  PIN od[489]
    DIRECTION OUTPUT ;
    USE SIGNAL ;
    PORT
      LAYER M4 ;
        RECT  0 84.576 0.192 84.6 ;
    END
  END od[489]
  PIN od[48]
    DIRECTION OUTPUT ;
    USE SIGNAL ;
    PORT
      LAYER M4 ;
        RECT  0 12.432 0.192 12.456 ;
    END
  END od[48]
  PIN od[490]
    DIRECTION OUTPUT ;
    USE SIGNAL ;
    PORT
      LAYER M4 ;
        RECT  0 84.72 0.192 84.744 ;
    END
  END od[490]
  PIN od[491]
    DIRECTION OUTPUT ;
    USE SIGNAL ;
    PORT
      LAYER M4 ;
        RECT  0 84.912 0.192 84.936 ;
    END
  END od[491]
  PIN od[492]
    DIRECTION OUTPUT ;
    USE SIGNAL ;
    PORT
      LAYER M4 ;
        RECT  0 85.056 0.192 85.08 ;
    END
  END od[492]
  PIN od[493]
    DIRECTION OUTPUT ;
    USE SIGNAL ;
    PORT
      LAYER M4 ;
        RECT  0 85.2 0.192 85.224 ;
    END
  END od[493]
  PIN od[494]
    DIRECTION OUTPUT ;
    USE SIGNAL ;
    PORT
      LAYER M4 ;
        RECT  0 85.392 0.192 85.416 ;
    END
  END od[494]
  PIN od[495]
    DIRECTION OUTPUT ;
    USE SIGNAL ;
    PORT
      LAYER M4 ;
        RECT  0 85.536 0.192 85.56 ;
    END
  END od[495]
  PIN od[496]
    DIRECTION OUTPUT ;
    USE SIGNAL ;
    PORT
      LAYER M4 ;
        RECT  0 85.728 0.192 85.752 ;
    END
  END od[496]
  PIN od[497]
    DIRECTION OUTPUT ;
    USE SIGNAL ;
    PORT
      LAYER M4 ;
        RECT  0 85.872 0.192 85.896 ;
    END
  END od[497]
  PIN od[498]
    DIRECTION OUTPUT ;
    USE SIGNAL ;
    PORT
      LAYER M4 ;
        RECT  0 86.016 0.192 86.04 ;
    END
  END od[498]
  PIN od[499]
    DIRECTION OUTPUT ;
    USE SIGNAL ;
    PORT
      LAYER M4 ;
        RECT  0 86.208 0.192 86.232 ;
    END
  END od[499]
  PIN od[49]
    DIRECTION OUTPUT ;
    USE SIGNAL ;
    PORT
      LAYER M4 ;
        RECT  0 12.576 0.192 12.6 ;
    END
  END od[49]
  PIN od[4]
    DIRECTION OUTPUT ;
    USE SIGNAL ;
    PORT
      LAYER M4 ;
        RECT  0 5.232 0.192 5.256 ;
    END
  END od[4]
  PIN od[500]
    DIRECTION OUTPUT ;
    USE SIGNAL ;
    PORT
      LAYER M4 ;
        RECT  0 86.352 0.192 86.376 ;
    END
  END od[500]
  PIN od[501]
    DIRECTION OUTPUT ;
    USE SIGNAL ;
    PORT
      LAYER M4 ;
        RECT  0 86.544 0.192 86.568 ;
    END
  END od[501]
  PIN od[502]
    DIRECTION OUTPUT ;
    USE SIGNAL ;
    PORT
      LAYER M4 ;
        RECT  0 86.688 0.192 86.712 ;
    END
  END od[502]
  PIN od[503]
    DIRECTION OUTPUT ;
    USE SIGNAL ;
    PORT
      LAYER M4 ;
        RECT  0 86.832 0.192 86.856 ;
    END
  END od[503]
  PIN od[504]
    DIRECTION OUTPUT ;
    USE SIGNAL ;
    PORT
      LAYER M4 ;
        RECT  0 87.024 0.192 87.048 ;
    END
  END od[504]
  PIN od[505]
    DIRECTION OUTPUT ;
    USE SIGNAL ;
    PORT
      LAYER M4 ;
        RECT  0 87.168 0.192 87.192 ;
    END
  END od[505]
  PIN od[506]
    DIRECTION OUTPUT ;
    USE SIGNAL ;
    PORT
      LAYER M4 ;
        RECT  0 87.36 0.192 87.384 ;
    END
  END od[506]
  PIN od[507]
    DIRECTION OUTPUT ;
    USE SIGNAL ;
    PORT
      LAYER M4 ;
        RECT  0 87.504 0.192 87.528 ;
    END
  END od[507]
  PIN od[508]
    DIRECTION OUTPUT ;
    USE SIGNAL ;
    PORT
      LAYER M4 ;
        RECT  0 87.696 0.192 87.72 ;
    END
  END od[508]
  PIN od[509]
    DIRECTION OUTPUT ;
    USE SIGNAL ;
    PORT
      LAYER M4 ;
        RECT  0 87.84 0.192 87.864 ;
    END
  END od[509]
  PIN od[50]
    DIRECTION OUTPUT ;
    USE SIGNAL ;
    PORT
      LAYER M4 ;
        RECT  0 12.768 0.192 12.792 ;
    END
  END od[50]
  PIN od[510]
    DIRECTION OUTPUT ;
    USE SIGNAL ;
    PORT
      LAYER M4 ;
        RECT  0 87.984 0.192 88.008 ;
    END
  END od[510]
  PIN od[511]
    DIRECTION OUTPUT ;
    USE SIGNAL ;
    PORT
      LAYER M4 ;
        RECT  0 88.176 0.192 88.2 ;
    END
  END od[511]
  PIN od[512]
    DIRECTION OUTPUT ;
    USE SIGNAL ;
    PORT
      LAYER M4 ;
        RECT  0 88.32 0.192 88.344 ;
    END
  END od[512]
  PIN od[513]
    DIRECTION OUTPUT ;
    USE SIGNAL ;
    PORT
      LAYER M4 ;
        RECT  0 88.512 0.192 88.536 ;
    END
  END od[513]
  PIN od[51]
    DIRECTION OUTPUT ;
    USE SIGNAL ;
    PORT
      LAYER M4 ;
        RECT  0 12.912 0.192 12.936 ;
    END
  END od[51]
  PIN od[52]
    DIRECTION OUTPUT ;
    USE SIGNAL ;
    PORT
      LAYER M4 ;
        RECT  0 13.104 0.192 13.128 ;
    END
  END od[52]
  PIN od[53]
    DIRECTION OUTPUT ;
    USE SIGNAL ;
    PORT
      LAYER M4 ;
        RECT  0 13.248 0.192 13.272 ;
    END
  END od[53]
  PIN od[54]
    DIRECTION OUTPUT ;
    USE SIGNAL ;
    PORT
      LAYER M4 ;
        RECT  0 13.392 0.192 13.416 ;
    END
  END od[54]
  PIN od[55]
    DIRECTION OUTPUT ;
    USE SIGNAL ;
    PORT
      LAYER M4 ;
        RECT  0 13.584 0.192 13.608 ;
    END
  END od[55]
  PIN od[56]
    DIRECTION OUTPUT ;
    USE SIGNAL ;
    PORT
      LAYER M4 ;
        RECT  0 13.728 0.192 13.752 ;
    END
  END od[56]
  PIN od[57]
    DIRECTION OUTPUT ;
    USE SIGNAL ;
    PORT
      LAYER M4 ;
        RECT  0 13.92 0.192 13.944 ;
    END
  END od[57]
  PIN od[58]
    DIRECTION OUTPUT ;
    USE SIGNAL ;
    PORT
      LAYER M4 ;
        RECT  0 14.064 0.192 14.088 ;
    END
  END od[58]
  PIN od[59]
    DIRECTION OUTPUT ;
    USE SIGNAL ;
    PORT
      LAYER M4 ;
        RECT  0 14.208 0.192 14.232 ;
    END
  END od[59]
  PIN od[5]
    DIRECTION OUTPUT ;
    USE SIGNAL ;
    PORT
      LAYER M4 ;
        RECT  0 5.376 0.192 5.4 ;
    END
  END od[5]
  PIN od[60]
    DIRECTION OUTPUT ;
    USE SIGNAL ;
    PORT
      LAYER M4 ;
        RECT  0 14.4 0.192 14.424 ;
    END
  END od[60]
  PIN od[61]
    DIRECTION OUTPUT ;
    USE SIGNAL ;
    PORT
      LAYER M4 ;
        RECT  0 14.544 0.192 14.568 ;
    END
  END od[61]
  PIN od[62]
    DIRECTION OUTPUT ;
    USE SIGNAL ;
    PORT
      LAYER M4 ;
        RECT  0 14.736 0.192 14.76 ;
    END
  END od[62]
  PIN od[63]
    DIRECTION OUTPUT ;
    USE SIGNAL ;
    PORT
      LAYER M4 ;
        RECT  0 14.88 0.192 14.904 ;
    END
  END od[63]
  PIN od[64]
    DIRECTION OUTPUT ;
    USE SIGNAL ;
    PORT
      LAYER M4 ;
        RECT  0 15.024 0.192 15.048 ;
    END
  END od[64]
  PIN od[65]
    DIRECTION OUTPUT ;
    USE SIGNAL ;
    PORT
      LAYER M4 ;
        RECT  0 15.216 0.192 15.24 ;
    END
  END od[65]
  PIN od[66]
    DIRECTION OUTPUT ;
    USE SIGNAL ;
    PORT
      LAYER M4 ;
        RECT  0 15.36 0.192 15.384 ;
    END
  END od[66]
  PIN od[67]
    DIRECTION OUTPUT ;
    USE SIGNAL ;
    PORT
      LAYER M4 ;
        RECT  0 15.552 0.192 15.576 ;
    END
  END od[67]
  PIN od[68]
    DIRECTION OUTPUT ;
    USE SIGNAL ;
    PORT
      LAYER M4 ;
        RECT  0 15.696 0.192 15.72 ;
    END
  END od[68]
  PIN od[69]
    DIRECTION OUTPUT ;
    USE SIGNAL ;
    PORT
      LAYER M4 ;
        RECT  0 15.84 0.192 15.864 ;
    END
  END od[69]
  PIN od[6]
    DIRECTION OUTPUT ;
    USE SIGNAL ;
    PORT
      LAYER M4 ;
        RECT  0 5.568 0.192 5.592 ;
    END
  END od[6]
  PIN od[70]
    DIRECTION OUTPUT ;
    USE SIGNAL ;
    PORT
      LAYER M4 ;
        RECT  0 16.032 0.192 16.056 ;
    END
  END od[70]
  PIN od[71]
    DIRECTION OUTPUT ;
    USE SIGNAL ;
    PORT
      LAYER M4 ;
        RECT  0 16.176 0.192 16.2 ;
    END
  END od[71]
  PIN od[72]
    DIRECTION OUTPUT ;
    USE SIGNAL ;
    PORT
      LAYER M4 ;
        RECT  0 16.368 0.192 16.392 ;
    END
  END od[72]
  PIN od[73]
    DIRECTION OUTPUT ;
    USE SIGNAL ;
    PORT
      LAYER M4 ;
        RECT  0 16.512 0.192 16.536 ;
    END
  END od[73]
  PIN od[74]
    DIRECTION OUTPUT ;
    USE SIGNAL ;
    PORT
      LAYER M4 ;
        RECT  0 16.704 0.192 16.728 ;
    END
  END od[74]
  PIN od[75]
    DIRECTION OUTPUT ;
    USE SIGNAL ;
    PORT
      LAYER M4 ;
        RECT  0 16.848 0.192 16.872 ;
    END
  END od[75]
  PIN od[76]
    DIRECTION OUTPUT ;
    USE SIGNAL ;
    PORT
      LAYER M4 ;
        RECT  0 16.992 0.192 17.016 ;
    END
  END od[76]
  PIN od[77]
    DIRECTION OUTPUT ;
    USE SIGNAL ;
    PORT
      LAYER M4 ;
        RECT  0 17.184 0.192 17.208 ;
    END
  END od[77]
  PIN od[78]
    DIRECTION OUTPUT ;
    USE SIGNAL ;
    PORT
      LAYER M4 ;
        RECT  0 17.328 0.192 17.352 ;
    END
  END od[78]
  PIN od[79]
    DIRECTION OUTPUT ;
    USE SIGNAL ;
    PORT
      LAYER M4 ;
        RECT  0 17.52 0.192 17.544 ;
    END
  END od[79]
  PIN od[7]
    DIRECTION OUTPUT ;
    USE SIGNAL ;
    PORT
      LAYER M4 ;
        RECT  0 5.712 0.192 5.736 ;
    END
  END od[7]
  PIN od[80]
    DIRECTION OUTPUT ;
    USE SIGNAL ;
    PORT
      LAYER M4 ;
        RECT  0 17.664 0.192 17.688 ;
    END
  END od[80]
  PIN od[81]
    DIRECTION OUTPUT ;
    USE SIGNAL ;
    PORT
      LAYER M4 ;
        RECT  0 17.808 0.192 17.832 ;
    END
  END od[81]
  PIN od[82]
    DIRECTION OUTPUT ;
    USE SIGNAL ;
    PORT
      LAYER M4 ;
        RECT  0 18 0.192 18.024 ;
    END
  END od[82]
  PIN od[83]
    DIRECTION OUTPUT ;
    USE SIGNAL ;
    PORT
      LAYER M4 ;
        RECT  0 18.144 0.192 18.168 ;
    END
  END od[83]
  PIN od[84]
    DIRECTION OUTPUT ;
    USE SIGNAL ;
    PORT
      LAYER M4 ;
        RECT  0 18.336 0.192 18.36 ;
    END
  END od[84]
  PIN od[85]
    DIRECTION OUTPUT ;
    USE SIGNAL ;
    PORT
      LAYER M4 ;
        RECT  0 18.48 0.192 18.504 ;
    END
  END od[85]
  PIN od[86]
    DIRECTION OUTPUT ;
    USE SIGNAL ;
    PORT
      LAYER M4 ;
        RECT  0 18.624 0.192 18.648 ;
    END
  END od[86]
  PIN od[87]
    DIRECTION OUTPUT ;
    USE SIGNAL ;
    PORT
      LAYER M4 ;
        RECT  0 18.816 0.192 18.84 ;
    END
  END od[87]
  PIN od[88]
    DIRECTION OUTPUT ;
    USE SIGNAL ;
    PORT
      LAYER M4 ;
        RECT  0 18.96 0.192 18.984 ;
    END
  END od[88]
  PIN od[89]
    DIRECTION OUTPUT ;
    USE SIGNAL ;
    PORT
      LAYER M4 ;
        RECT  0 19.152 0.192 19.176 ;
    END
  END od[89]
  PIN od[8]
    DIRECTION OUTPUT ;
    USE SIGNAL ;
    PORT
      LAYER M4 ;
        RECT  0 5.904 0.192 5.928 ;
    END
  END od[8]
  PIN od[90]
    DIRECTION OUTPUT ;
    USE SIGNAL ;
    PORT
      LAYER M4 ;
        RECT  0 19.296 0.192 19.32 ;
    END
  END od[90]
  PIN od[91]
    DIRECTION OUTPUT ;
    USE SIGNAL ;
    PORT
      LAYER M4 ;
        RECT  0 19.44 0.192 19.464 ;
    END
  END od[91]
  PIN od[92]
    DIRECTION OUTPUT ;
    USE SIGNAL ;
    PORT
      LAYER M4 ;
        RECT  0 19.632 0.192 19.656 ;
    END
  END od[92]
  PIN od[93]
    DIRECTION OUTPUT ;
    USE SIGNAL ;
    PORT
      LAYER M4 ;
        RECT  0 19.776 0.192 19.8 ;
    END
  END od[93]
  PIN od[94]
    DIRECTION OUTPUT ;
    USE SIGNAL ;
    PORT
      LAYER M4 ;
        RECT  0 19.968 0.192 19.992 ;
    END
  END od[94]
  PIN od[95]
    DIRECTION OUTPUT ;
    USE SIGNAL ;
    PORT
      LAYER M4 ;
        RECT  0 20.112 0.192 20.136 ;
    END
  END od[95]
  PIN od[96]
    DIRECTION OUTPUT ;
    USE SIGNAL ;
    PORT
      LAYER M4 ;
        RECT  0 20.304 0.192 20.328 ;
    END
  END od[96]
  PIN od[97]
    DIRECTION OUTPUT ;
    USE SIGNAL ;
    PORT
      LAYER M4 ;
        RECT  0 20.448 0.192 20.472 ;
    END
  END od[97]
  PIN od[98]
    DIRECTION OUTPUT ;
    USE SIGNAL ;
    PORT
      LAYER M4 ;
        RECT  0 20.592 0.192 20.616 ;
    END
  END od[98]
  PIN od[99]
    DIRECTION OUTPUT ;
    USE SIGNAL ;
    PORT
      LAYER M4 ;
        RECT  0 20.784 0.192 20.808 ;
    END
  END od[99]
  PIN od[9]
    DIRECTION OUTPUT ;
    USE SIGNAL ;
    PORT
      LAYER M4 ;
        RECT  0 6.048 0.192 6.072 ;
    END
  END od[9]
  PIN rs[0]
    DIRECTION INPUT ;
    USE SIGNAL ;
    PORT
      LAYER M3 ;
        RECT  47.52 0 47.538 0.144 ;
    END
    PORT
      LAYER M3 ;
        RECT  47.304 0.108 47.538 0.167 ;
    END
  END rs[0]
  PIN rss[0]
    DIRECTION INPUT ;
    USE SIGNAL ;
    PORT
      LAYER M5 ;
        RECT  64.8 0 64.824 0.192 ;
    END
    PORT
      LAYER M5 ;
        RECT  64.8 0.144 64.824 0.611 ;
    END
  END rss[0]
  PIN st[0]
    DIRECTION OUTPUT ;
    USE SIGNAL ;
    PORT
      LAYER M4 ;
        RECT  77.568 88.176 77.76 88.2 ;
    END
  END st[0]
  PIN st[1]
    DIRECTION OUTPUT ;
    USE SIGNAL ;
    PORT
      LAYER M4 ;
        RECT  77.568 88.32 77.76 88.344 ;
    END
  END st[1]
  PIN st[2]
    DIRECTION OUTPUT ;
    USE SIGNAL ;
    PORT
      LAYER M4 ;
        RECT  77.568 88.512 77.76 88.536 ;
    END
  END st[2]
  PIN VDD
    DIRECTION INOUT ;
    USE POWER ;
    PORT
      LAYER M5 ;
        RECT  75.492 2.151 75.612 90.729 ;
        RECT  72.792 2.151 72.912 90.729 ;
        RECT  70.092 2.151 70.212 90.729 ;
        RECT  67.392 2.151 67.512 90.729 ;
        RECT  64.692 2.151 64.812 90.729 ;
        RECT  61.992 2.151 62.112 90.729 ;
        RECT  59.292 2.151 59.412 90.729 ;
        RECT  56.592 2.151 56.712 90.729 ;
        RECT  53.892 2.151 54.012 90.729 ;
        RECT  51.192 2.151 51.312 90.729 ;
        RECT  48.492 2.151 48.612 90.729 ;
        RECT  45.792 2.151 45.912 90.729 ;
        RECT  43.092 2.151 43.212 90.729 ;
        RECT  40.392 2.151 40.512 90.729 ;
        RECT  37.692 2.151 37.812 90.729 ;
        RECT  34.992 2.151 35.112 90.729 ;
        RECT  32.292 2.151 32.412 90.729 ;
        RECT  29.592 2.151 29.712 90.729 ;
        RECT  26.892 2.151 27.012 90.729 ;
        RECT  24.192 2.151 24.312 90.729 ;
        RECT  21.492 2.151 21.612 90.729 ;
        RECT  18.792 2.151 18.912 90.729 ;
        RECT  16.092 2.151 16.212 90.729 ;
        RECT  13.392 2.151 13.512 90.729 ;
        RECT  10.692 2.151 10.812 90.729 ;
        RECT  7.992 2.151 8.112 90.729 ;
        RECT  5.292 2.151 5.412 90.729 ;
        RECT  2.592 2.151 2.712 90.729 ;
    END
  END VDD
  PIN VSS
    DIRECTION INOUT ;
    USE GROUND ;
    PORT
      LAYER M5 ;
        RECT  75.3 2.137 75.42 90.743 ;
        RECT  72.6 2.137 72.72 90.743 ;
        RECT  69.9 2.137 70.02 90.743 ;
        RECT  67.2 2.137 67.32 90.743 ;
        RECT  64.5 2.137 64.62 90.743 ;
        RECT  61.8 2.137 61.92 90.743 ;
        RECT  59.1 2.137 59.22 90.743 ;
        RECT  56.4 2.137 56.52 90.743 ;
        RECT  53.7 2.137 53.82 90.743 ;
        RECT  51 2.137 51.12 90.743 ;
        RECT  48.3 2.137 48.42 90.743 ;
        RECT  45.6 2.137 45.72 90.743 ;
        RECT  42.9 2.137 43.02 90.743 ;
        RECT  40.2 2.137 40.32 90.743 ;
        RECT  37.5 2.137 37.62 90.743 ;
        RECT  34.8 2.137 34.92 90.743 ;
        RECT  32.1 2.137 32.22 90.743 ;
        RECT  29.4 2.137 29.52 90.743 ;
        RECT  26.7 2.137 26.82 90.743 ;
        RECT  24 2.137 24.12 90.743 ;
        RECT  21.3 2.137 21.42 90.743 ;
        RECT  18.6 2.137 18.72 90.743 ;
        RECT  15.9 2.137 16.02 90.743 ;
        RECT  13.2 2.137 13.32 90.743 ;
        RECT  10.5 2.137 10.62 90.743 ;
        RECT  7.8 2.137 7.92 90.743 ;
        RECT  5.1 2.137 5.22 90.743 ;
        RECT  2.4 2.137 2.52 90.743 ;
    END
  END VSS
  # OT_OBS_CLOSED layer=M5 d_um=1.536 added=953
  OBS
    LAYER RVTN ;
     RECT  2.16 2.16 75.6 2.295 ;
     RECT  2.16 2.565 75.6 2.835 ;
     RECT  2.16 3.105 75.6 3.375 ;
     RECT  2.16 3.645 75.6 3.915 ;
     RECT  2.16 4.185 75.6 4.455 ;
     RECT  2.16 4.725 75.6 4.995 ;
     RECT  2.16 5.265 75.6 5.535 ;
     RECT  2.16 5.805 75.6 6.075 ;
     RECT  2.16 6.345 75.6 6.615 ;
     RECT  2.16 6.885 75.6 7.155 ;
     RECT  2.16 7.425 75.6 7.695 ;
     RECT  2.16 7.965 75.6 8.235 ;
     RECT  2.16 8.505 75.6 8.775 ;
     RECT  2.16 9.045 75.6 9.315 ;
     RECT  2.16 9.585 75.6 9.855 ;
     RECT  2.16 10.125 75.6 10.395 ;
     RECT  2.16 10.665 75.6 10.935 ;
     RECT  2.16 11.205 75.6 11.475 ;
     RECT  2.16 11.745 75.6 12.015 ;
     RECT  2.16 12.285 75.6 12.555 ;
     RECT  2.16 12.825 75.6 13.095 ;
     RECT  2.16 13.365 75.6 13.635 ;
     RECT  2.16 13.905 75.6 14.175 ;
     RECT  2.16 14.445 75.6 14.715 ;
     RECT  2.16 14.985 75.6 15.255 ;
     RECT  2.16 15.525 75.6 15.795 ;
     RECT  2.16 16.065 75.6 16.335 ;
     RECT  2.16 16.605 75.6 16.875 ;
     RECT  2.16 17.145 75.6 17.415 ;
     RECT  2.16 17.685 75.6 17.955 ;
     RECT  2.16 18.225 75.6 18.495 ;
     RECT  2.16 18.765 75.6 19.035 ;
     RECT  2.16 19.305 75.6 19.575 ;
     RECT  2.16 19.845 75.6 20.115 ;
     RECT  2.16 20.385 75.6 20.655 ;
     RECT  2.16 20.925 75.6 21.195 ;
     RECT  2.16 21.465 75.6 21.735 ;
     RECT  2.16 22.005 75.6 22.275 ;
     RECT  2.16 22.545 75.6 22.815 ;
     RECT  2.16 23.085 75.6 23.355 ;
     RECT  2.16 23.625 75.6 23.895 ;
     RECT  2.16 24.165 75.6 24.435 ;
     RECT  2.16 24.705 75.6 24.975 ;
     RECT  2.16 25.245 75.6 25.515 ;
     RECT  2.16 25.785 75.6 26.055 ;
     RECT  2.16 26.325 75.6 26.595 ;
     RECT  2.16 26.865 75.6 27.135 ;
     RECT  2.16 27.405 75.6 27.675 ;
     RECT  2.16 27.945 75.6 28.215 ;
     RECT  2.16 28.485 75.6 28.755 ;
     RECT  2.16 29.025 75.6 29.295 ;
     RECT  2.16 29.565 75.6 29.835 ;
     RECT  2.16 30.105 75.6 30.375 ;
     RECT  2.16 30.645 75.6 30.915 ;
     RECT  2.16 31.185 75.6 31.455 ;
     RECT  2.16 31.725 75.6 31.995 ;
     RECT  2.16 32.265 75.6 32.535 ;
     RECT  2.16 32.805 75.6 33.075 ;
     RECT  2.16 33.345 75.6 33.615 ;
     RECT  2.16 33.885 75.6 34.155 ;
     RECT  2.16 34.425 75.6 34.695 ;
     RECT  2.16 34.965 75.6 35.235 ;
     RECT  2.16 35.505 75.6 35.775 ;
     RECT  2.16 36.045 75.6 36.315 ;
     RECT  2.16 36.585 75.6 36.855 ;
     RECT  2.16 37.125 75.6 37.395 ;
     RECT  2.16 37.665 75.6 37.935 ;
     RECT  2.16 38.205 75.6 38.475 ;
     RECT  2.16 38.745 75.6 39.015 ;
     RECT  2.16 39.285 75.6 39.555 ;
     RECT  2.16 39.825 75.6 40.095 ;
     RECT  2.16 40.365 75.6 40.635 ;
     RECT  2.16 40.905 75.6 41.175 ;
     RECT  2.16 41.445 75.6 41.715 ;
     RECT  2.16 41.985 75.6 42.255 ;
     RECT  2.16 42.525 75.6 42.795 ;
     RECT  2.16 43.065 75.6 43.335 ;
     RECT  2.16 43.605 75.6 43.875 ;
     RECT  2.16 44.145 75.6 44.415 ;
     RECT  2.16 44.685 75.6 44.955 ;
     RECT  2.16 45.225 75.6 45.495 ;
     RECT  2.16 45.765 75.6 46.035 ;
     RECT  2.16 46.305 75.6 46.575 ;
     RECT  2.16 46.845 75.6 47.115 ;
     RECT  2.16 47.385 75.6 47.655 ;
     RECT  2.16 47.925 75.6 48.195 ;
     RECT  2.16 48.465 75.6 48.735 ;
     RECT  2.16 49.005 75.6 49.275 ;
     RECT  2.16 49.545 75.6 49.815 ;
     RECT  2.16 50.085 75.6 50.355 ;
     RECT  2.16 50.625 75.6 50.895 ;
     RECT  2.16 51.165 75.6 51.435 ;
     RECT  2.16 51.705 75.6 51.975 ;
     RECT  2.16 52.245 75.6 52.515 ;
     RECT  2.16 52.785 75.6 53.055 ;
     RECT  2.16 53.325 75.6 53.595 ;
     RECT  2.16 53.865 75.6 54.135 ;
     RECT  2.16 54.405 75.6 54.675 ;
     RECT  2.16 54.945 75.6 55.215 ;
     RECT  2.16 55.485 75.6 55.755 ;
     RECT  2.16 56.025 75.6 56.295 ;
     RECT  2.16 56.565 75.6 56.835 ;
     RECT  2.16 57.105 75.6 57.375 ;
     RECT  2.16 57.645 75.6 57.915 ;
     RECT  2.16 58.185 75.6 58.455 ;
     RECT  2.16 58.725 75.6 58.995 ;
     RECT  2.16 59.265 75.6 59.535 ;
     RECT  2.16 59.805 75.6 60.075 ;
     RECT  2.16 60.345 75.6 60.615 ;
     RECT  2.16 60.885 75.6 61.155 ;
     RECT  2.16 61.425 75.6 61.695 ;
     RECT  2.16 61.965 75.6 62.235 ;
     RECT  2.16 62.505 75.6 62.775 ;
     RECT  2.16 63.045 75.6 63.315 ;
     RECT  2.16 63.585 75.6 63.855 ;
     RECT  2.16 64.125 75.6 64.395 ;
     RECT  2.16 64.665 75.6 64.935 ;
     RECT  2.16 65.205 75.6 65.475 ;
     RECT  2.16 65.745 75.6 66.015 ;
     RECT  2.16 66.285 75.6 66.555 ;
     RECT  2.16 66.825 75.6 67.095 ;
     RECT  2.16 67.365 75.6 67.635 ;
     RECT  2.16 67.905 75.6 68.175 ;
     RECT  2.16 68.445 75.6 68.715 ;
     RECT  2.16 68.985 75.6 69.255 ;
     RECT  2.16 69.525 75.6 69.795 ;
     RECT  2.16 70.065 75.6 70.335 ;
     RECT  2.16 70.605 75.6 70.875 ;
     RECT  2.16 71.145 75.6 71.415 ;
     RECT  2.16 71.685 75.6 71.955 ;
     RECT  2.16 72.225 75.6 72.495 ;
     RECT  2.16 72.765 75.6 73.035 ;
     RECT  2.16 73.305 75.6 73.575 ;
     RECT  2.16 73.845 75.6 74.115 ;
     RECT  2.16 74.385 75.6 74.655 ;
     RECT  2.16 74.925 75.6 75.195 ;
     RECT  2.16 75.465 75.6 75.735 ;
     RECT  2.16 76.005 75.6 76.275 ;
     RECT  2.16 76.545 75.6 76.815 ;
     RECT  2.16 77.085 75.6 77.355 ;
     RECT  2.16 77.625 75.6 77.895 ;
     RECT  2.16 78.165 75.6 78.435 ;
     RECT  2.16 78.705 75.6 78.975 ;
     RECT  2.16 79.245 75.6 79.515 ;
     RECT  2.16 79.785 75.6 80.055 ;
     RECT  2.16 80.325 75.6 80.595 ;
     RECT  2.16 80.865 75.6 81.135 ;
     RECT  2.16 81.405 75.6 81.675 ;
     RECT  2.16 81.945 75.6 82.215 ;
     RECT  2.16 82.485 75.6 82.755 ;
     RECT  2.16 83.025 75.6 83.295 ;
     RECT  2.16 83.565 75.6 83.835 ;
     RECT  2.16 84.105 75.6 84.375 ;
     RECT  2.16 84.645 75.6 84.915 ;
     RECT  2.16 85.185 75.6 85.455 ;
     RECT  2.16 85.725 75.6 85.995 ;
     RECT  2.16 86.265 75.6 86.535 ;
     RECT  2.16 86.805 75.6 87.075 ;
     RECT  2.16 87.345 75.6 87.615 ;
     RECT  2.16 87.885 75.6 88.155 ;
     RECT  2.16 88.425 75.6 88.695 ;
     RECT  2.16 88.965 75.6 89.235 ;
     RECT  2.16 89.505 75.6 89.775 ;
     RECT  2.16 90.045 75.6 90.315 ;
     RECT  2.16 90.585 75.6 90.72 ;
    LAYER RVTP ;
     RECT  2.16 2.295 75.6 2.565 ;
     RECT  2.16 2.835 75.6 3.105 ;
     RECT  2.16 3.375 75.6 3.645 ;
     RECT  2.16 3.915 75.6 4.185 ;
     RECT  2.16 4.455 75.6 4.725 ;
     RECT  2.16 4.995 75.6 5.265 ;
     RECT  2.16 5.535 75.6 5.805 ;
     RECT  2.16 6.075 75.6 6.345 ;
     RECT  2.16 6.615 75.6 6.885 ;
     RECT  2.16 7.155 75.6 7.425 ;
     RECT  2.16 7.695 75.6 7.965 ;
     RECT  2.16 8.235 75.6 8.505 ;
     RECT  2.16 8.775 75.6 9.045 ;
     RECT  2.16 9.315 75.6 9.585 ;
     RECT  2.16 9.855 75.6 10.125 ;
     RECT  2.16 10.395 75.6 10.665 ;
     RECT  2.16 10.935 75.6 11.205 ;
     RECT  2.16 11.475 75.6 11.745 ;
     RECT  2.16 12.015 75.6 12.285 ;
     RECT  2.16 12.555 75.6 12.825 ;
     RECT  2.16 13.095 75.6 13.365 ;
     RECT  2.16 13.635 75.6 13.905 ;
     RECT  2.16 14.175 75.6 14.445 ;
     RECT  2.16 14.715 75.6 14.985 ;
     RECT  2.16 15.255 75.6 15.525 ;
     RECT  2.16 15.795 75.6 16.065 ;
     RECT  2.16 16.335 75.6 16.605 ;
     RECT  2.16 16.875 75.6 17.145 ;
     RECT  2.16 17.415 75.6 17.685 ;
     RECT  2.16 17.955 75.6 18.225 ;
     RECT  2.16 18.495 75.6 18.765 ;
     RECT  2.16 19.035 75.6 19.305 ;
     RECT  2.16 19.575 75.6 19.845 ;
     RECT  2.16 20.115 75.6 20.385 ;
     RECT  2.16 20.655 75.6 20.925 ;
     RECT  2.16 21.195 75.6 21.465 ;
     RECT  2.16 21.735 75.6 22.005 ;
     RECT  2.16 22.275 75.6 22.545 ;
     RECT  2.16 22.815 75.6 23.085 ;
     RECT  2.16 23.355 75.6 23.625 ;
     RECT  2.16 23.895 75.6 24.165 ;
     RECT  2.16 24.435 75.6 24.705 ;
     RECT  2.16 24.975 75.6 25.245 ;
     RECT  2.16 25.515 75.6 25.785 ;
     RECT  2.16 26.055 75.6 26.325 ;
     RECT  2.16 26.595 75.6 26.865 ;
     RECT  2.16 27.135 75.6 27.405 ;
     RECT  2.16 27.675 75.6 27.945 ;
     RECT  2.16 28.215 75.6 28.485 ;
     RECT  2.16 28.755 75.6 29.025 ;
     RECT  2.16 29.295 75.6 29.565 ;
     RECT  2.16 29.835 75.6 30.105 ;
     RECT  2.16 30.375 75.6 30.645 ;
     RECT  2.16 30.915 75.6 31.185 ;
     RECT  2.16 31.455 75.6 31.725 ;
     RECT  2.16 31.995 75.6 32.265 ;
     RECT  2.16 32.535 75.6 32.805 ;
     RECT  2.16 33.075 75.6 33.345 ;
     RECT  2.16 33.615 75.6 33.885 ;
     RECT  2.16 34.155 75.6 34.425 ;
     RECT  2.16 34.695 75.6 34.965 ;
     RECT  2.16 35.235 75.6 35.505 ;
     RECT  2.16 35.775 75.6 36.045 ;
     RECT  2.16 36.315 75.6 36.585 ;
     RECT  2.16 36.855 75.6 37.125 ;
     RECT  2.16 37.395 75.6 37.665 ;
     RECT  2.16 37.935 75.6 38.205 ;
     RECT  2.16 38.475 75.6 38.745 ;
     RECT  2.16 39.015 75.6 39.285 ;
     RECT  2.16 39.555 75.6 39.825 ;
     RECT  2.16 40.095 75.6 40.365 ;
     RECT  2.16 40.635 75.6 40.905 ;
     RECT  2.16 41.175 75.6 41.445 ;
     RECT  2.16 41.715 75.6 41.985 ;
     RECT  2.16 42.255 75.6 42.525 ;
     RECT  2.16 42.795 75.6 43.065 ;
     RECT  2.16 43.335 75.6 43.605 ;
     RECT  2.16 43.875 75.6 44.145 ;
     RECT  2.16 44.415 75.6 44.685 ;
     RECT  2.16 44.955 75.6 45.225 ;
     RECT  2.16 45.495 75.6 45.765 ;
     RECT  2.16 46.035 75.6 46.305 ;
     RECT  2.16 46.575 75.6 46.845 ;
     RECT  2.16 47.115 75.6 47.385 ;
     RECT  2.16 47.655 75.6 47.925 ;
     RECT  2.16 48.195 75.6 48.465 ;
     RECT  2.16 48.735 75.6 49.005 ;
     RECT  2.16 49.275 75.6 49.545 ;
     RECT  2.16 49.815 75.6 50.085 ;
     RECT  2.16 50.355 75.6 50.625 ;
     RECT  2.16 50.895 75.6 51.165 ;
     RECT  2.16 51.435 75.6 51.705 ;
     RECT  2.16 51.975 75.6 52.245 ;
     RECT  2.16 52.515 75.6 52.785 ;
     RECT  2.16 53.055 75.6 53.325 ;
     RECT  2.16 53.595 75.6 53.865 ;
     RECT  2.16 54.135 75.6 54.405 ;
     RECT  2.16 54.675 75.6 54.945 ;
     RECT  2.16 55.215 75.6 55.485 ;
     RECT  2.16 55.755 75.6 56.025 ;
     RECT  2.16 56.295 75.6 56.565 ;
     RECT  2.16 56.835 75.6 57.105 ;
     RECT  2.16 57.375 75.6 57.645 ;
     RECT  2.16 57.915 75.6 58.185 ;
     RECT  2.16 58.455 75.6 58.725 ;
     RECT  2.16 58.995 75.6 59.265 ;
     RECT  2.16 59.535 75.6 59.805 ;
     RECT  2.16 60.075 75.6 60.345 ;
     RECT  2.16 60.615 75.6 60.885 ;
     RECT  2.16 61.155 75.6 61.425 ;
     RECT  2.16 61.695 75.6 61.965 ;
     RECT  2.16 62.235 75.6 62.505 ;
     RECT  2.16 62.775 75.6 63.045 ;
     RECT  2.16 63.315 75.6 63.585 ;
     RECT  2.16 63.855 75.6 64.125 ;
     RECT  2.16 64.395 75.6 64.665 ;
     RECT  2.16 64.935 75.6 65.205 ;
     RECT  2.16 65.475 75.6 65.745 ;
     RECT  2.16 66.015 75.6 66.285 ;
     RECT  2.16 66.555 75.6 66.825 ;
     RECT  2.16 67.095 75.6 67.365 ;
     RECT  2.16 67.635 75.6 67.905 ;
     RECT  2.16 68.175 75.6 68.445 ;
     RECT  2.16 68.715 75.6 68.985 ;
     RECT  2.16 69.255 75.6 69.525 ;
     RECT  2.16 69.795 75.6 70.065 ;
     RECT  2.16 70.335 75.6 70.605 ;
     RECT  2.16 70.875 75.6 71.145 ;
     RECT  2.16 71.415 75.6 71.685 ;
     RECT  2.16 71.955 75.6 72.225 ;
     RECT  2.16 72.495 75.6 72.765 ;
     RECT  2.16 73.035 75.6 73.305 ;
     RECT  2.16 73.575 75.6 73.845 ;
     RECT  2.16 74.115 75.6 74.385 ;
     RECT  2.16 74.655 75.6 74.925 ;
     RECT  2.16 75.195 75.6 75.465 ;
     RECT  2.16 75.735 75.6 76.005 ;
     RECT  2.16 76.275 75.6 76.545 ;
     RECT  2.16 76.815 75.6 77.085 ;
     RECT  2.16 77.355 75.6 77.625 ;
     RECT  2.16 77.895 75.6 78.165 ;
     RECT  2.16 78.435 75.6 78.705 ;
     RECT  2.16 78.975 75.6 79.245 ;
     RECT  2.16 79.515 75.6 79.785 ;
     RECT  2.16 80.055 75.6 80.325 ;
     RECT  2.16 80.595 75.6 80.865 ;
     RECT  2.16 81.135 75.6 81.405 ;
     RECT  2.16 81.675 75.6 81.945 ;
     RECT  2.16 82.215 75.6 82.485 ;
     RECT  2.16 82.755 75.6 83.025 ;
     RECT  2.16 83.295 75.6 83.565 ;
     RECT  2.16 83.835 75.6 84.105 ;
     RECT  2.16 84.375 75.6 84.645 ;
     RECT  2.16 84.915 75.6 85.185 ;
     RECT  2.16 85.455 75.6 85.725 ;
     RECT  2.16 85.995 75.6 86.265 ;
     RECT  2.16 86.535 75.6 86.805 ;
     RECT  2.16 87.075 75.6 87.345 ;
     RECT  2.16 87.615 75.6 87.885 ;
     RECT  2.16 88.155 75.6 88.425 ;
     RECT  2.16 88.695 75.6 88.965 ;
     RECT  2.16 89.235 75.6 89.505 ;
     RECT  2.16 89.775 75.6 90.045 ;
     RECT  2.16 90.315 75.6 90.585 ;
    LAYER M1 ;
     RECT  2.16 2.151 75.6 90.729 ;
    LAYER M2 ;
     RECT  0.211 81.846 0.247 81.864 ;
     RECT  0.247 21.636 0.535 21.654 ;
     RECT  0.211 38.106 0.535 38.736 ;
     RECT  0.211 58.626 0.535 58.644 ;
     RECT  0.211 73.476 0.535 74.034 ;
     RECT  0.211 78.606 0.535 78.624 ;
     RECT  0.499 83.106 0.535 83.124 ;
     RECT  0.535 28.836 1.147 28.854 ;
     RECT  1.147 28.566 1.175 28.854 ;
     RECT  0.535 6.696 2.16 6.714 ;
     RECT  0.535 7.866 2.16 7.884 ;
     RECT  0.535 9.666 2.16 9.684 ;
     RECT  0.211 11.376 2.16 11.394 ;
     RECT  0.535 15.192 2.16 15.21 ;
     RECT  0.211 17.586 2.16 18.684 ;
     RECT  0.211 19.818 2.16 19.836 ;
     RECT  0.535 21.366 2.16 21.654 ;
     RECT  0.319 22.986 2.16 23.004 ;
     RECT  0.211 24.336 2.16 25.074 ;
     RECT  0.535 26.496 2.16 26.514 ;
     RECT  0.535 27.756 2.16 27.774 ;
     RECT  1.175 28.566 2.16 28.584 ;
     RECT  0.211 32.436 2.16 32.454 ;
     RECT  0.535 35.244 2.16 35.262 ;
     RECT  0.535 37.566 2.16 38.736 ;
     RECT  0.535 42.066 2.16 42.084 ;
     RECT  0.535 43.686 2.16 44.334 ;
     RECT  0.535 47.088 2.16 47.106 ;
     RECT  0.535 53.946 2.16 53.964 ;
     RECT  0.535 58.086 2.16 58.644 ;
     RECT  0.211 61.596 2.16 61.614 ;
     RECT  0.211 62.406 2.16 62.424 ;
     RECT  0.211 64.296 2.16 64.314 ;
     RECT  0.211 67.806 2.16 67.824 ;
     RECT  0.211 68.886 2.16 68.904 ;
     RECT  0.535 72.234 2.16 74.034 ;
     RECT  0.535 76.014 2.16 76.032 ;
     RECT  0.535 77.832 2.16 77.85 ;
     RECT  0.535 78.606 2.16 79.038 ;
     RECT  0.247 81.846 2.16 82.134 ;
     RECT  0.535 83.106 2.16 83.214 ;
     RECT  0.535 84.69 2.16 84.708 ;
     RECT  1.975 88.398 2.16 88.416 ;
     RECT  2.16 2.151 8.419 90.729 ;
     RECT  8.419 2.106 9.203 90.729 ;
     RECT  9.203 2.151 24.835 90.729 ;
     RECT  24.835 2.106 26.591 90.729 ;
     RECT  29.875 0.036 47.299 0.054 ;
     RECT  47.299 0.036 47.327 0.162 ;
     RECT  47.327 0.144 47.543 0.162 ;
     RECT  26.591 2.151 47.767 90.729 ;
     RECT  47.767 2.106 63.355 90.729 ;
     RECT  63.355 2.034 64.823 90.729 ;
     RECT  64.823 2.151 75.6 90.729 ;
     RECT  75.6 2.421 75.612 90.459 ;
     RECT  75.612 4.23 75.839 88.794 ;
     RECT  75.839 4.968 75.875 11.502 ;
     RECT  75.839 12.258 75.875 38.574 ;
     RECT  75.839 39.528 75.875 50.346 ;
     RECT  75.839 51.21 75.875 74.376 ;
     RECT  75.839 75.168 75.875 77.652 ;
     RECT  75.839 78.408 75.875 88.794 ;
     RECT  75.875 7.398 75.911 8.766 ;
     RECT  75.875 12.258 75.911 13.086 ;
     RECT  75.875 13.878 75.911 15.318 ;
     RECT  75.875 23.904 75.911 29.016 ;
     RECT  75.875 29.808 75.911 30.978 ;
     RECT  75.875 31.968 75.911 37.62 ;
     RECT  75.875 41.148 75.911 43.596 ;
     RECT  75.875 44.658 75.911 46.026 ;
     RECT  75.875 46.854 75.911 47.88 ;
     RECT  75.875 48.978 75.911 50.346 ;
     RECT  75.875 51.408 75.911 54.432 ;
     RECT  75.875 60.318 75.911 66.006 ;
     RECT  75.875 67.14 75.911 70.902 ;
     RECT  75.875 78.408 75.911 82.782 ;
     RECT  75.875 86.814 75.911 88.794 ;
     RECT  75.875 9.828 75.947 11.502 ;
     RECT  75.911 14.688 75.947 15.318 ;
     RECT  75.911 31.968 75.947 35.568 ;
     RECT  75.911 67.14 75.983 68.274 ;
     RECT  75.911 24.678 76.307 29.016 ;
     RECT  76.307 24.678 76.379 27.666 ;
     RECT  75.875 5.508 76.415 6.408 ;
     RECT  75.911 7.398 76.415 7.416 ;
     RECT  75.911 8.208 76.415 8.766 ;
     RECT  75.947 9.828 76.415 11.466 ;
     RECT  75.911 12.258 76.415 12.276 ;
     RECT  75.911 13.068 76.415 13.086 ;
     RECT  75.911 13.878 76.415 13.896 ;
     RECT  75.947 14.688 76.415 15.246 ;
     RECT  75.875 16.308 76.415 16.866 ;
     RECT  75.875 17.658 76.415 23.076 ;
     RECT  76.379 24.678 76.415 26.928 ;
     RECT  75.911 29.808 76.415 30.906 ;
     RECT  75.947 31.968 76.415 34.254 ;
     RECT  75.911 36.558 76.415 37.62 ;
     RECT  75.875 38.448 76.415 38.538 ;
     RECT  75.911 41.148 76.415 43.326 ;
     RECT  75.911 44.73 76.415 46.026 ;
     RECT  75.911 47.394 76.415 47.88 ;
     RECT  75.911 49.248 76.415 50.346 ;
     RECT  75.911 51.408 76.415 54.396 ;
     RECT  75.875 55.188 76.415 57.906 ;
     RECT  75.875 58.662 76.415 58.788 ;
     RECT  75.911 60.318 76.415 64.116 ;
     RECT  75.911 64.908 76.415 64.926 ;
     RECT  75.911 65.718 76.415 66.006 ;
     RECT  75.983 67.446 76.415 68.274 ;
     RECT  75.911 69.228 76.415 70.866 ;
     RECT  75.875 71.658 76.415 73.026 ;
     RECT  75.875 73.818 76.415 73.836 ;
     RECT  75.875 75.168 76.415 75.456 ;
     RECT  75.875 76.248 76.415 76.536 ;
     RECT  75.875 77.598 76.415 77.652 ;
     RECT  75.911 78.786 76.415 79.236 ;
     RECT  75.911 80.838 76.415 81.198 ;
     RECT  75.911 82.188 76.415 82.782 ;
     RECT  75.875 83.772 76.415 84.366 ;
     RECT  75.875 85.158 76.415 85.176 ;
     RECT  75.911 87.318 76.415 88.794 ;
     RECT  76.415 19.548 76.451 19.566 ;
     RECT  76.415 20.358 76.451 20.646 ;
     RECT  76.415 21.708 76.451 21.726 ;
     RECT  76.415 23.058 76.451 23.076 ;
     RECT  76.415 30.078 76.451 30.672 ;
     RECT  76.415 32.778 76.451 34.254 ;
     RECT  75.947 35.208 76.451 35.568 ;
     RECT  75.875 39.528 76.451 39.924 ;
     RECT  76.415 41.22 76.451 42.516 ;
     RECT  76.415 54.378 76.451 54.396 ;
     RECT  76.415 62.208 76.451 62.262 ;
     RECT  76.415 65.718 76.451 65.736 ;
     RECT  76.415 67.446 76.451 68.166 ;
     RECT  76.415 71.928 76.451 73.026 ;
     RECT  76.415 25.416 76.847 26.856 ;
     RECT  76.847 25.416 76.883 26.046 ;
     RECT  76.307 28.728 76.883 28.746 ;
     RECT  76.415 5.778 76.991 6.408 ;
     RECT  76.415 10.476 76.991 11.196 ;
     RECT  76.415 16.308 76.991 16.326 ;
     RECT  76.415 18.306 76.991 18.792 ;
     RECT  76.451 20.628 76.991 20.646 ;
     RECT  76.883 25.416 76.991 25.776 ;
     RECT  76.847 26.838 76.991 26.856 ;
     RECT  76.451 30.654 76.991 30.672 ;
     RECT  76.451 33.426 76.991 34.254 ;
     RECT  76.451 35.55 76.991 35.568 ;
     RECT  76.415 38.52 76.991 38.538 ;
     RECT  76.451 39.906 76.991 39.924 ;
     RECT  76.451 41.22 76.991 41.778 ;
     RECT  76.415 44.73 76.991 44.748 ;
     RECT  76.415 47.394 76.991 47.682 ;
     RECT  76.415 52.218 76.991 53.01 ;
     RECT  76.415 55.53 76.991 56.628 ;
     RECT  76.415 58.77 76.991 58.788 ;
     RECT  76.415 60.588 76.991 61.218 ;
     RECT  76.451 62.244 76.991 62.262 ;
     RECT  76.415 64.098 76.991 64.116 ;
     RECT  76.451 67.446 76.991 67.968 ;
     RECT  76.415 69.606 76.991 69.624 ;
     RECT  76.451 72.468 76.991 72.486 ;
     RECT  76.415 75.276 76.991 75.294 ;
     RECT  76.415 77.634 76.991 77.652 ;
     RECT  76.415 78.786 76.991 78.804 ;
     RECT  76.415 81.18 76.991 81.198 ;
     RECT  76.415 82.728 76.991 82.746 ;
     RECT  76.415 88.056 76.991 88.794 ;
     RECT  76.991 47.664 77.027 47.682 ;
     RECT  76.991 52.218 77.027 52.236 ;
     RECT  76.991 88.056 77.027 88.524 ;
     RECT  76.991 41.256 77.063 41.274 ;
    LAYER M3 ;
     RECT  47.304 0.031 47.322 0.108 ;
     RECT  63.36 2.029 63.378 2.101 ;
     RECT  8.424 2.101 8.442 2.143 ;
     RECT  26.388 2.101 26.586 2.143 ;
     RECT  29.88 0.031 29.898 2.143 ;
     RECT  47.772 2.101 47.79 2.143 ;
     RECT  64.8 0.571 64.818 2.143 ;
     RECT  9.18 2.101 9.198 2.191 ;
     RECT  13.215 2.143 13.305 2.191 ;
     RECT  15.915 2.143 16.005 2.191 ;
     RECT  24.015 2.143 24.105 2.191 ;
     RECT  32.115 2.143 32.205 2.191 ;
     RECT  47.772 2.143 48.405 2.191 ;
     RECT  53.715 2.143 53.805 2.191 ;
     RECT  59.115 2.143 59.205 2.191 ;
     RECT  61.815 2.143 61.905 2.191 ;
     RECT  13.215 2.191 13.662 2.227 ;
     RECT  21.315 2.143 21.405 2.227 ;
     RECT  26.388 2.143 26.805 2.227 ;
     RECT  37.515 2.143 37.605 2.227 ;
     RECT  59.115 2.191 59.742 2.227 ;
     RECT  61.815 2.191 62.262 2.227 ;
     RECT  63.36 2.101 63.522 2.227 ;
     RECT  64.515 2.143 64.818 2.227 ;
     RECT  21.315 2.227 21.474 2.251 ;
     RECT  23.508 2.191 24.105 2.251 ;
     RECT  63.36 2.227 64.818 2.251 ;
     RECT  7.815 2.143 8.442 2.263 ;
     RECT  9.18 2.191 9.27 2.263 ;
     RECT  12.636 2.227 14.022 2.263 ;
     RECT  24.84 2.101 24.858 2.263 ;
     RECT  25.632 2.227 26.805 2.263 ;
     RECT  37.044 2.227 37.605 2.263 ;
     RECT  41.436 2.227 41.454 2.263 ;
     RECT  42.915 2.143 43.005 2.263 ;
     RECT  43.884 2.227 43.902 2.263 ;
     RECT  56.415 2.143 56.505 2.263 ;
     RECT  57.24 2.227 57.258 2.263 ;
     RECT  60.984 2.251 61.002 2.263 ;
     RECT  61.815 2.227 62.622 2.263 ;
     RECT  67.215 2.143 67.305 2.263 ;
     RECT  68.94 2.227 68.958 2.263 ;
     RECT  69.915 2.143 70.005 2.263 ;
     RECT  70.884 2.191 70.902 2.263 ;
     RECT  10.515 2.143 10.605 2.299 ;
     RECT  11.592 2.263 11.61 2.299 ;
     RECT  29.415 2.143 29.898 2.299 ;
     RECT  31.428 2.191 32.205 2.299 ;
     RECT  33.12 2.293 33.138 2.299 ;
     RECT  36.9 2.263 37.605 2.299 ;
     RECT  45.615 2.143 45.705 2.299 ;
     RECT  47.628 2.191 48.474 2.299 ;
     RECT  51.015 2.143 51.105 2.299 ;
     RECT  55.872 2.263 57.258 2.299 ;
     RECT  68.544 2.263 68.958 2.299 ;
     RECT  7.815 2.263 9.27 2.335 ;
     RECT  20.916 2.251 22.122 2.335 ;
     RECT  29.16 2.299 29.898 2.335 ;
     RECT  34.815 2.143 34.905 2.335 ;
     RECT  42.768 2.263 43.902 2.335 ;
     RECT  47.124 2.299 48.69 2.335 ;
     RECT  50.904 2.299 51.105 2.335 ;
     RECT  52.344 2.299 52.866 2.335 ;
     RECT  53.604 2.191 53.805 2.335 ;
     RECT  63.36 2.251 64.926 2.335 ;
     RECT  68.472 2.299 68.958 2.335 ;
     RECT  69.915 2.263 70.902 2.335 ;
     RECT  12.564 2.263 14.022 2.371 ;
     RECT  15.915 2.191 16.254 2.371 ;
     RECT  17.136 2.203 17.154 2.371 ;
     RECT  18.615 2.143 18.705 2.371 ;
     RECT  20.916 2.335 22.338 2.371 ;
     RECT  23.184 2.251 24.105 2.371 ;
     RECT  24.84 2.263 26.805 2.371 ;
     RECT  27.792 2.335 27.81 2.371 ;
     RECT  28.62 2.335 29.898 2.371 ;
     RECT  38.772 2.191 38.79 2.371 ;
     RECT  40.215 2.143 40.305 2.371 ;
     RECT  41.436 2.263 41.634 2.371 ;
     RECT  42.48 2.335 43.902 2.371 ;
     RECT  2.415 2.143 2.505 2.413 ;
     RECT  5.115 2.143 5.205 2.413 ;
     RECT  20.916 2.371 26.805 2.413 ;
     RECT  31.248 2.299 32.205 2.413 ;
     RECT  32.94 2.299 33.138 2.413 ;
     RECT  36.468 2.299 37.605 2.413 ;
     RECT  38.772 2.371 40.305 2.413 ;
     RECT  45.615 2.299 45.774 2.413 ;
     RECT  46.548 2.335 48.906 2.413 ;
     RECT  50.688 2.335 53.805 2.413 ;
     RECT  66.708 2.263 67.305 2.413 ;
     RECT  72.615 2.143 72.705 2.413 ;
     RECT  75.315 2.143 75.405 2.413 ;
     RECT  7.815 2.335 9.63 2.461 ;
     RECT  10.515 2.299 11.61 2.461 ;
     RECT  12.492 2.371 14.022 2.461 ;
     RECT  15.915 2.371 17.694 2.461 ;
     RECT  18.615 2.371 19.17 2.461 ;
     RECT  31.248 2.413 33.138 2.461 ;
     RECT  44.748 2.335 44.766 2.461 ;
     RECT  45.615 2.413 48.906 2.461 ;
     RECT  58.788 2.227 59.742 2.461 ;
     RECT  63.36 2.335 65.142 2.461 ;
     RECT  66.708 2.413 67.497 2.461 ;
     RECT  69.84 2.335 70.938 2.461 ;
     RECT  27.792 2.371 29.898 2.488 ;
     RECT  31.104 2.461 33.354 2.488 ;
     RECT  68.472 2.335 69.066 2.491 ;
     RECT  36.468 2.413 37.797 2.497 ;
     RECT  38.772 2.413 40.497 2.497 ;
     RECT  44.748 2.461 48.906 2.497 ;
     RECT  50.688 2.413 53.997 2.497 ;
     RECT  69.84 2.461 71.55 2.497 ;
     RECT  7.815 2.461 9.702 2.533 ;
     RECT  10.515 2.461 14.022 2.533 ;
     RECT  41.436 2.371 43.902 2.533 ;
     RECT  44.748 2.497 53.997 2.533 ;
     RECT  63.36 2.461 65.214 2.569 ;
     RECT  69.84 2.497 71.658 2.569 ;
     RECT  72.615 2.413 72.897 2.569 ;
     RECT  15.915 2.461 19.674 2.587 ;
     RECT  34.815 2.335 35.73 2.587 ;
     RECT  41.436 2.533 53.997 2.605 ;
     RECT  55.404 2.299 57.258 2.605 ;
     RECT  58.788 2.461 59.85 2.605 ;
     RECT  68.472 2.491 69.102 2.605 ;
     RECT  69.84 2.569 72.897 2.605 ;
     RECT  15.915 2.587 19.71 2.641 ;
     RECT  20.916 2.413 26.997 2.641 ;
     RECT  27.792 2.488 33.354 2.641 ;
     RECT  34.128 2.587 35.73 2.641 ;
     RECT  36.468 2.497 40.497 2.641 ;
     RECT  58.716 2.605 59.85 2.641 ;
     RECT  60.984 2.263 62.622 2.641 ;
     RECT  63.36 2.569 65.898 2.641 ;
     RECT  66.636 2.461 67.497 2.641 ;
     RECT  68.364 2.605 69.102 2.641 ;
     RECT  69.84 2.605 73.242 2.641 ;
     RECT  41.436 2.605 54.054 2.731 ;
     RECT  54.936 2.605 57.258 2.731 ;
     RECT  60.984 2.641 65.898 2.731 ;
     RECT  66.636 2.641 73.242 2.731 ;
     RECT  14.904 2.641 40.497 2.767 ;
     RECT  58.716 2.641 60.03 2.803 ;
     RECT  54.9 2.731 57.258 2.827 ;
     RECT  58.716 2.803 60.066 2.839 ;
     RECT  60.984 2.731 73.242 2.839 ;
     RECT  54.9 2.827 57.51 2.875 ;
     RECT  5.115 2.413 5.397 2.911 ;
     RECT  14.904 2.767 40.626 3.019 ;
     RECT  41.436 2.731 54.126 3.019 ;
     RECT  54.9 2.875 57.906 3.019 ;
     RECT  7.815 2.533 14.022 3.073 ;
     RECT  54.9 3.019 57.942 3.073 ;
     RECT  4.032 2.911 5.397 3.109 ;
     RECT  14.904 3.019 54.126 3.109 ;
     RECT  54.9 3.073 57.978 3.109 ;
     RECT  7.815 3.073 14.166 3.145 ;
     RECT  7.74 3.145 14.166 3.181 ;
     RECT  14.904 3.109 57.978 3.181 ;
     RECT  7.74 3.181 57.978 3.371 ;
     RECT  3.852 3.109 5.397 3.415 ;
     RECT  29.34 3.371 57.978 3.451 ;
     RECT  58.716 2.839 73.242 3.451 ;
     RECT  3.672 3.415 5.742 3.569 ;
     RECT  3.96 3.569 5.742 3.577 ;
     RECT  6.552 3.451 6.57 3.577 ;
     RECT  3.96 3.577 6.678 3.613 ;
     RECT  3.96 3.613 6.822 3.721 ;
     RECT  7.74 3.371 28.494 3.721 ;
     RECT  2.415 2.413 2.697 4.081 ;
     RECT  3.96 3.721 28.494 4.219 ;
     RECT  29.34 3.451 73.242 4.219 ;
     RECT  75.315 2.413 75.597 4.225 ;
     RECT  74.016 4.189 74.034 4.289 ;
     RECT  2.415 4.081 3.15 4.495 ;
     RECT  2.376 4.495 3.15 4.531 ;
     RECT  3.96 4.219 73.242 4.531 ;
     RECT  75.315 4.225 75.834 4.747 ;
     RECT  0.252 4.699 0.27 4.891 ;
     RECT  0.252 4.891 0.45 5.021 ;
     RECT  74.52 4.963 74.538 5.071 ;
     RECT  0.252 5.021 0.27 5.117 ;
     RECT  2.376 4.531 73.242 5.161 ;
     RECT  74.376 5.071 74.538 5.161 ;
     RECT  75.315 4.747 75.87 5.227 ;
     RECT  2.304 5.161 73.242 5.275 ;
     RECT  74.196 5.161 74.538 5.341 ;
     RECT  75.315 5.227 76.41 5.341 ;
     RECT  74.196 5.341 76.41 5.531 ;
     RECT  2.304 5.275 73.278 5.701 ;
     RECT  74.196 5.531 75.87 5.701 ;
     RECT  76.968 5.707 76.986 6.413 ;
     RECT  0.54 6.691 0.558 6.715 ;
     RECT  0.252 6.715 0.558 6.845 ;
     RECT  2.304 5.701 75.87 6.859 ;
     RECT  0.54 6.845 0.558 6.893 ;
     RECT  0.54 7.861 0.558 8.045 ;
     RECT  2.304 6.859 76.41 8.771 ;
     RECT  2.304 8.771 75.87 9.041 ;
     RECT  25.236 9.041 75.87 9.239 ;
     RECT  44.604 9.239 75.87 9.643 ;
     RECT  44.604 9.643 76.41 9.653 ;
     RECT  0.54 9.661 0.558 9.821 ;
     RECT  25.236 9.239 43.83 9.931 ;
     RECT  75.24 9.653 76.41 9.979 ;
     RECT  25.2 9.931 43.83 10.021 ;
     RECT  44.604 9.653 74.394 10.021 ;
     RECT  2.304 9.041 24.462 10.129 ;
     RECT  25.2 10.021 74.394 10.129 ;
     RECT  2.304 10.129 74.394 10.399 ;
     RECT  75.24 9.979 76.986 10.399 ;
     RECT  2.304 10.399 76.986 10.661 ;
     RECT  76.968 10.661 76.986 11.201 ;
     RECT  2.304 10.661 75.942 11.419 ;
     RECT  0.216 11.371 0.234 11.453 ;
     RECT  2.304 11.419 76.41 12.289 ;
     RECT  2.268 12.289 76.41 12.461 ;
     RECT  2.304 12.461 76.41 13.091 ;
     RECT  0.252 13.147 0.27 13.277 ;
     RECT  2.304 13.091 75.906 13.867 ;
     RECT  2.304 13.867 76.41 15.053 ;
     RECT  2.412 15.053 76.41 15.251 ;
     RECT  2.412 15.251 75.942 15.323 ;
     RECT  2.412 15.323 75.87 15.629 ;
     RECT  2.412 15.629 65.358 15.719 ;
     RECT  0.54 15.187 0.558 15.725 ;
     RECT  2.412 15.719 30.186 15.869 ;
     RECT  2.412 15.869 30.15 16.171 ;
     RECT  66.096 15.629 75.87 16.171 ;
     RECT  31.068 15.719 65.358 16.375 ;
     RECT  66.096 16.171 75.906 16.375 ;
     RECT  31.068 16.375 75.906 16.507 ;
     RECT  76.968 16.303 76.986 16.507 ;
     RECT  2.304 16.171 30.15 16.645 ;
     RECT  31.068 16.507 76.986 16.645 ;
     RECT  2.304 16.645 76.986 16.829 ;
     RECT  2.304 16.829 76.41 17.933 ;
     RECT  2.412 17.933 76.41 18.059 ;
     RECT  2.412 18.059 75.906 18.173 ;
     RECT  2.415 18.173 75.906 18.797 ;
     RECT  76.968 18.139 76.986 18.797 ;
     RECT  0.216 17.581 0.234 18.845 ;
     RECT  26.136 18.797 75.906 18.955 ;
     RECT  2.415 18.797 25.326 19.201 ;
     RECT  2.412 19.201 25.326 19.345 ;
     RECT  2.304 19.345 25.326 19.435 ;
     RECT  2.268 19.435 25.326 19.741 ;
     RECT  2.268 19.741 25.362 19.805 ;
     RECT  2.268 19.805 14.526 20.039 ;
     RECT  15.372 19.805 25.362 20.155 ;
     RECT  26.136 18.955 76.446 20.155 ;
     RECT  15.372 20.155 76.446 20.251 ;
     RECT  0.216 19.813 0.234 20.333 ;
     RECT  2.304 20.039 14.526 20.551 ;
     RECT  15.372 20.251 76.986 20.551 ;
     RECT  2.304 20.551 76.986 20.651 ;
     RECT  2.304 20.651 76.446 21.299 ;
     RECT  0.54 21.361 0.558 21.499 ;
     RECT  0.216 21.499 0.558 21.629 ;
     RECT  2.412 21.299 76.446 21.731 ;
     RECT  0.252 21.629 0.558 21.773 ;
     RECT  2.412 21.731 76.41 22.075 ;
     RECT  0.252 21.773 0.27 22.253 ;
     RECT  2.304 22.075 76.41 22.699 ;
     RECT  2.304 22.699 76.446 23.081 ;
     RECT  0.324 22.981 0.342 23.227 ;
     RECT  0.252 23.227 0.342 23.357 ;
     RECT  0.324 23.357 0.342 23.405 ;
     RECT  2.304 23.081 75.906 24.475 ;
     RECT  2.304 24.475 75.942 24.667 ;
     RECT  0.216 24.331 0.234 24.859 ;
     RECT  0.216 24.859 0.27 24.989 ;
     RECT  2.304 24.667 76.41 25.147 ;
     RECT  0.216 24.989 0.234 25.229 ;
     RECT  2.304 25.147 76.986 25.241 ;
     RECT  2.304 25.241 76.086 25.439 ;
     RECT  2.304 25.439 73.386 25.469 ;
     RECT  2.304 25.469 73.278 25.483 ;
     RECT  74.124 25.439 76.086 25.511 ;
     RECT  1.98 25.483 73.278 25.709 ;
     RECT  74.124 25.511 74.538 25.709 ;
     RECT  76.86 25.241 76.986 25.781 ;
     RECT  76.86 25.781 76.878 25.963 ;
     RECT  74.124 25.709 74.43 26.051 ;
     RECT  76.824 25.963 76.878 26.051 ;
     RECT  2.304 25.709 73.278 26.221 ;
     RECT  75.315 25.511 76.086 26.299 ;
     RECT  76.824 26.051 76.842 26.299 ;
     RECT  2.304 26.221 73.386 26.671 ;
     RECT  75.315 26.299 76.842 26.779 ;
     RECT  2.304 26.671 73.602 26.833 ;
     RECT  74.412 26.051 74.43 26.833 ;
     RECT  0.54 26.491 0.558 26.861 ;
     RECT  75.315 26.779 76.986 26.861 ;
     RECT  2.304 26.833 74.43 26.923 ;
     RECT  75.315 26.861 76.41 26.923 ;
     RECT  2.304 26.923 76.41 26.933 ;
     RECT  2.304 26.933 76.374 27.341 ;
     RECT  2.412 27.341 76.374 27.671 ;
     RECT  0.54 27.751 0.558 28.013 ;
     RECT  2.412 27.671 76.302 28.123 ;
     RECT  2.304 28.123 76.302 28.411 ;
     RECT  2.304 28.411 76.878 28.751 ;
     RECT  1.152 28.561 1.17 28.831 ;
     RECT  0.54 28.831 1.17 28.859 ;
     RECT  0.54 28.859 0.558 29.165 ;
     RECT  2.304 28.751 76.41 29.563 ;
     RECT  2.304 29.563 76.446 30.187 ;
     RECT  2.304 30.187 76.986 30.235 ;
     RECT  2.268 30.235 76.986 30.569 ;
     RECT  2.304 30.569 76.986 30.677 ;
     RECT  0.252 30.763 0.27 30.893 ;
     RECT  2.304 30.677 76.41 32.395 ;
     RECT  2.268 32.395 76.41 32.491 ;
     RECT  0.216 32.431 0.234 32.573 ;
     RECT  2.268 32.491 76.446 32.635 ;
     RECT  2.268 32.635 76.986 32.639 ;
     RECT  2.304 32.639 76.986 33.269 ;
     RECT  2.415 33.269 76.986 34.027 ;
     RECT  2.304 34.027 76.986 34.151 ;
     RECT  76.968 34.151 76.986 34.259 ;
     RECT  2.304 34.151 75.942 34.939 ;
     RECT  2.304 34.939 76.41 35.083 ;
     RECT  2.304 35.083 76.446 35.275 ;
     RECT  0.54 35.239 0.558 35.357 ;
     RECT  2.304 35.275 76.986 35.501 ;
     RECT  76.968 35.501 76.986 35.573 ;
     RECT  2.304 35.501 75.906 36.239 ;
     RECT  2.34 36.239 75.906 36.427 ;
     RECT  2.34 36.427 76.41 36.653 ;
     RECT  2.34 36.653 73.818 37.147 ;
     RECT  2.304 37.147 73.818 37.291 ;
     RECT  2.268 37.291 73.818 37.391 ;
     RECT  2.304 37.391 73.818 37.427 ;
     RECT  39.096 37.427 73.818 37.561 ;
     RECT  74.628 36.653 76.41 37.561 ;
     RECT  0.54 37.561 0.558 37.661 ;
     RECT  2.304 37.427 38.358 37.859 ;
     RECT  1.152 37.915 1.17 38.141 ;
     RECT  39.096 37.561 76.41 38.471 ;
     RECT  2.415 37.859 38.358 38.551 ;
     RECT  39.096 38.471 75.87 38.551 ;
     RECT  76.968 38.515 76.986 38.717 ;
     RECT  0.216 38.101 0.234 38.813 ;
     RECT  2.415 38.551 75.87 38.911 ;
     RECT  2.304 38.911 75.87 39.355 ;
     RECT  2.304 39.355 76.41 39.499 ;
     RECT  2.304 39.499 76.446 39.623 ;
     RECT  74.808 39.623 76.446 39.691 ;
     RECT  74.808 39.691 76.986 39.821 ;
     RECT  76.968 39.821 76.986 39.929 ;
     RECT  2.304 39.623 74.034 40.289 ;
     RECT  2.415 40.289 74.034 40.531 ;
     RECT  74.808 39.821 75.87 40.531 ;
     RECT  2.415 40.531 75.87 40.651 ;
     RECT  2.415 40.651 76.41 40.795 ;
     RECT  2.415 40.795 76.986 40.987 ;
     RECT  2.415 40.987 77.058 41.035 ;
     RECT  2.304 41.035 77.058 41.279 ;
     RECT  2.304 41.279 76.986 41.783 ;
     RECT  0.54 42.061 0.558 42.221 ;
     RECT  2.304 41.783 76.446 42.521 ;
     RECT  2.304 42.521 76.41 42.667 ;
     RECT  1.98 42.667 76.41 42.845 ;
     RECT  2.304 42.845 76.41 43.331 ;
     RECT  2.304 43.331 75.906 43.771 ;
     RECT  2.196 43.771 75.906 43.853 ;
     RECT  0.54 43.681 0.558 44.299 ;
     RECT  0.216 44.299 0.558 44.669 ;
     RECT  2.304 43.853 75.906 44.753 ;
     RECT  76.968 44.587 76.986 44.753 ;
     RECT  57.744 44.753 75.906 44.875 ;
     RECT  0.216 44.669 0.234 45.245 ;
     RECT  2.304 44.753 57.006 45.535 ;
     RECT  57.744 44.875 76.41 45.535 ;
     RECT  2.304 45.535 76.41 46.031 ;
     RECT  2.304 46.031 75.906 46.139 ;
     RECT  0.252 46.027 0.27 46.157 ;
     RECT  2.304 46.139 73.566 46.769 ;
     RECT  74.376 46.139 75.906 46.877 ;
     RECT  57.708 46.769 73.566 46.885 ;
     RECT  74.376 46.877 75.87 46.885 ;
     RECT  2.304 46.769 56.862 47.075 ;
     RECT  2.304 47.075 56.826 47.309 ;
     RECT  76.968 46.843 76.986 47.323 ;
     RECT  0.54 47.083 0.558 47.453 ;
     RECT  57.708 46.885 75.87 47.551 ;
     RECT  76.968 47.323 77.022 47.687 ;
     RECT  2.415 47.309 56.826 47.803 ;
     RECT  57.672 47.551 75.87 47.803 ;
     RECT  2.415 47.803 75.87 47.851 ;
     RECT  2.415 47.851 76.41 47.891 ;
     RECT  2.415 47.891 75.906 48.091 ;
     RECT  2.304 48.091 75.906 48.541 ;
     RECT  2.268 48.541 75.906 48.605 ;
     RECT  2.304 48.605 75.906 48.955 ;
     RECT  2.304 48.955 76.41 50.351 ;
     RECT  2.304 50.351 19.53 50.717 ;
     RECT  20.268 50.351 75.906 51.089 ;
     RECT  20.448 51.089 75.906 51.115 ;
     RECT  2.304 50.717 19.458 51.197 ;
     RECT  0.252 51.739 0.27 51.869 ;
     RECT  20.448 51.115 76.41 51.943 ;
     RECT  20.268 51.943 76.41 52.015 ;
     RECT  2.304 51.197 19.314 52.051 ;
     RECT  20.232 52.015 76.41 52.075 ;
     RECT  20.232 52.075 76.986 52.213 ;
     RECT  2.304 52.051 19.386 52.249 ;
     RECT  20.232 52.213 77.022 52.249 ;
     RECT  2.304 52.249 77.022 52.253 ;
     RECT  2.304 52.253 76.986 52.511 ;
     RECT  76.968 52.511 76.986 53.069 ;
     RECT  2.304 52.511 75.87 53.131 ;
     RECT  1.98 53.131 75.87 53.293 ;
     RECT  1.98 53.293 76.41 53.309 ;
     RECT  2.268 53.309 76.41 53.501 ;
     RECT  2.304 53.501 76.41 53.789 ;
     RECT  0.252 53.611 0.27 53.837 ;
     RECT  54.9 53.789 76.41 54.043 ;
     RECT  0.54 53.941 0.558 54.173 ;
     RECT  2.304 53.789 54.126 54.571 ;
     RECT  54.9 54.043 76.446 54.571 ;
     RECT  2.304 54.571 76.446 55.003 ;
     RECT  2.304 55.003 76.986 55.627 ;
     RECT  2.268 55.627 76.986 55.751 ;
     RECT  2.304 55.751 76.986 55.949 ;
     RECT  41.58 55.949 76.986 56.633 ;
     RECT  41.58 56.633 76.41 56.669 ;
     RECT  0.216 56.731 0.234 56.861 ;
     RECT  2.304 55.949 40.842 56.911 ;
     RECT  41.58 56.669 73.386 56.911 ;
     RECT  2.304 56.911 73.386 57.451 ;
     RECT  74.16 56.669 76.41 57.451 ;
     RECT  0.54 58.081 0.558 58.253 ;
     RECT  2.304 57.451 76.41 58.459 ;
     RECT  2.304 58.459 76.986 58.685 ;
     RECT  0.216 58.621 0.234 58.733 ;
     RECT  76.968 58.685 76.986 58.793 ;
     RECT  1.152 58.891 1.17 59.021 ;
     RECT  2.304 58.685 75.87 59.765 ;
     RECT  47.628 59.765 75.87 60.091 ;
     RECT  47.628 60.091 76.41 60.427 ;
     RECT  2.304 59.765 46.89 60.611 ;
     RECT  3.852 60.611 46.89 60.691 ;
     RECT  47.628 60.427 76.986 60.691 ;
     RECT  2.304 60.611 2.754 60.893 ;
     RECT  3.852 60.691 76.986 61.151 ;
     RECT  3.852 61.151 73.782 61.223 ;
     RECT  3.852 61.223 5.706 61.699 ;
     RECT  2.304 60.893 2.697 61.771 ;
     RECT  3.42 61.699 5.706 61.771 ;
     RECT  2.304 61.771 5.706 61.963 ;
     RECT  6.48 61.223 73.782 61.963 ;
     RECT  2.304 61.963 73.782 62.041 ;
     RECT  74.628 61.151 76.986 62.267 ;
     RECT  2.304 62.041 73.854 62.303 ;
     RECT  4.032 62.303 73.854 62.401 ;
     RECT  74.628 62.267 76.41 62.401 ;
     RECT  77.544 62.683 77.562 62.813 ;
     RECT  2.304 62.303 3.294 63.205 ;
     RECT  4.032 62.401 76.41 63.205 ;
     RECT  0.216 61.591 0.234 63.341 ;
     RECT  2.304 63.205 76.41 63.581 ;
     RECT  76.968 63.979 76.986 64.121 ;
     RECT  0.216 64.291 0.234 64.637 ;
     RECT  2.304 63.581 75.87 64.741 ;
     RECT  2.304 64.741 75.906 64.903 ;
     RECT  2.304 64.903 76.41 65.611 ;
     RECT  2.304 65.611 76.446 65.741 ;
     RECT  2.304 65.741 76.41 66.011 ;
     RECT  2.304 66.011 75.978 66.389 ;
     RECT  53.028 66.389 75.978 66.587 ;
     RECT  2.304 66.389 52.182 67.243 ;
     RECT  53.028 66.587 73.638 67.243 ;
     RECT  74.412 66.587 75.978 67.579 ;
     RECT  76.968 66.955 76.986 67.579 ;
     RECT  2.304 67.243 73.638 67.675 ;
     RECT  74.412 67.579 76.986 67.675 ;
     RECT  0.216 67.801 0.234 67.901 ;
     RECT  2.304 67.675 76.986 67.973 ;
     RECT  2.304 67.973 76.446 68.171 ;
     RECT  0.216 68.881 0.234 69.053 ;
     RECT  2.304 68.171 76.41 69.403 ;
     RECT  2.304 69.403 76.986 69.629 ;
     RECT  2.304 69.629 76.41 70.169 ;
     RECT  2.304 70.169 73.746 70.529 ;
     RECT  2.412 70.529 73.746 70.951 ;
     RECT  74.52 70.169 76.41 70.951 ;
     RECT  2.412 70.951 76.41 71.323 ;
     RECT  2.304 71.323 76.41 71.659 ;
     RECT  2.304 71.659 76.446 72.023 ;
     RECT  76.392 72.023 76.446 72.331 ;
     RECT  76.392 72.331 76.986 72.491 ;
     RECT  2.304 72.023 75.597 72.955 ;
     RECT  76.392 72.491 76.446 72.955 ;
     RECT  0.54 72.229 0.558 72.989 ;
     RECT  2.304 72.955 76.446 73.031 ;
     RECT  2.304 73.031 76.41 73.841 ;
     RECT  0.216 73.471 0.234 74.141 ;
     RECT  2.304 73.841 75.87 74.309 ;
     RECT  2.415 74.309 75.87 74.923 ;
     RECT  76.968 74.587 76.986 74.923 ;
     RECT  2.415 74.923 76.986 75.067 ;
     RECT  2.304 75.067 76.986 75.299 ;
     RECT  0.54 76.009 0.558 76.397 ;
     RECT  2.304 75.299 76.41 76.541 ;
     RECT  2.304 76.541 75.87 76.883 ;
     RECT  69.516 76.883 75.87 76.973 ;
     RECT  69.552 76.973 75.87 77.563 ;
     RECT  76.968 77.035 76.986 77.563 ;
     RECT  69.552 77.563 76.986 77.621 ;
     RECT  76.968 77.621 76.986 77.657 ;
     RECT  2.304 76.883 68.742 77.791 ;
     RECT  69.552 77.621 75.906 77.791 ;
     RECT  0.54 77.827 0.558 78.601 ;
     RECT  0.216 78.601 0.558 78.701 ;
     RECT  76.968 78.523 76.986 78.809 ;
     RECT  2.304 77.791 75.906 79.003 ;
     RECT  2.304 79.003 76.41 79.205 ;
     RECT  2.34 79.205 76.41 79.241 ;
     RECT  0.54 78.701 0.558 79.373 ;
     RECT  2.34 79.241 75.906 79.951 ;
     RECT  2.304 79.951 75.906 80.635 ;
     RECT  76.968 80.491 76.986 80.635 ;
     RECT  2.304 80.635 76.986 80.861 ;
     RECT  76.968 80.861 76.986 81.203 ;
     RECT  2.304 80.861 75.906 81.979 ;
     RECT  0.216 81.841 0.234 82.111 ;
     RECT  0.216 82.111 0.27 82.157 ;
     RECT  2.304 81.979 76.41 82.267 ;
     RECT  2.304 82.267 76.986 82.603 ;
     RECT  2.268 82.603 76.986 82.751 ;
     RECT  2.268 82.751 76.41 82.787 ;
     RECT  0.252 82.157 0.27 82.973 ;
     RECT  2.268 82.787 75.87 83.101 ;
     RECT  0.504 83.101 0.522 83.191 ;
     RECT  0.504 83.191 0.558 83.261 ;
     RECT  2.232 83.101 75.87 83.399 ;
     RECT  0.504 83.261 0.522 83.453 ;
     RECT  2.304 83.399 75.87 83.755 ;
     RECT  2.304 83.755 76.41 83.867 ;
     RECT  4.356 83.867 76.41 84.613 ;
     RECT  2.304 83.867 3.474 84.685 ;
     RECT  4.284 84.613 76.41 84.685 ;
     RECT  2.304 84.685 76.41 84.713 ;
     RECT  0.54 84.685 0.558 85.085 ;
     RECT  53.352 84.713 76.41 85.181 ;
     RECT  2.304 84.713 52.614 85.459 ;
     RECT  53.352 85.181 75.87 85.459 ;
     RECT  2.304 85.459 75.87 85.919 ;
     RECT  2.376 85.919 75.87 86.347 ;
     RECT  2.376 86.347 75.906 86.459 ;
     RECT  0.252 86.347 0.27 86.525 ;
     RECT  2.376 86.459 71.514 86.683 ;
     RECT  72.54 86.459 75.906 87.019 ;
     RECT  72.54 87.019 76.41 87.241 ;
     RECT  72.36 87.241 76.41 87.341 ;
     RECT  2.304 86.683 71.514 87.499 ;
     RECT  2.268 87.499 71.514 87.539 ;
     RECT  0.216 87.595 0.234 87.725 ;
     RECT  2.304 87.539 71.514 87.883 ;
     RECT  72.36 87.341 75.906 87.883 ;
     RECT  2.304 87.883 75.906 88.079 ;
     RECT  74.556 88.079 75.906 88.151 ;
     RECT  3.528 88.079 73.674 88.157 ;
     RECT  77.004 88.051 77.022 88.171 ;
     RECT  74.592 88.151 75.87 88.349 ;
     RECT  2.304 88.079 2.79 88.393 ;
     RECT  70.992 88.157 73.674 88.493 ;
     RECT  1.98 88.393 2.79 88.541 ;
     RECT  76.968 88.171 77.022 88.541 ;
     RECT  2.376 88.541 2.79 88.619 ;
     RECT  70.992 88.493 73.35 88.619 ;
     RECT  74.916 88.349 75.87 88.619 ;
     RECT  70.992 88.619 71.55 88.655 ;
     RECT  75.315 88.619 75.87 88.691 ;
     RECT  76.968 88.541 76.986 88.799 ;
     RECT  2.415 88.619 2.79 88.889 ;
     RECT  3.528 88.157 70.197 88.889 ;
     RECT  71.136 88.655 71.55 88.889 ;
     RECT  3.528 88.889 68.814 88.891 ;
     RECT  72.396 88.619 73.35 88.925 ;
     RECT  3.456 88.891 68.814 89.159 ;
     RECT  72.615 88.925 73.35 89.159 ;
     RECT  72.615 89.159 73.206 89.195 ;
     RECT  3.996 89.159 68.814 89.231 ;
     RECT  4.68 89.231 68.814 89.267 ;
     RECT  5.115 89.267 68.814 89.549 ;
     RECT  6.228 89.549 68.814 89.879 ;
     RECT  6.228 89.879 56.697 89.969 ;
     RECT  57.492 89.879 68.814 89.969 ;
     RECT  6.336 89.969 56.697 90.005 ;
     RECT  6.336 90.005 36.342 90.041 ;
     RECT  37.224 90.005 38.178 90.041 ;
     RECT  57.6 89.969 68.814 90.041 ;
     RECT  7.128 90.041 36.342 90.149 ;
     RECT  7.128 90.149 19.494 90.239 ;
     RECT  20.376 90.149 32.706 90.239 ;
     RECT  33.588 90.149 36.342 90.239 ;
     RECT  37.224 90.041 38.07 90.239 ;
     RECT  38.916 90.005 56.697 90.239 ;
     RECT  57.6 90.041 68.094 90.239 ;
     RECT  7.128 90.239 17.802 90.275 ;
     RECT  18.615 90.239 19.386 90.275 ;
     RECT  20.484 90.239 32.706 90.275 ;
     RECT  37.224 90.239 37.998 90.275 ;
     RECT  48.315 90.239 50.274 90.275 ;
     RECT  57.6 90.239 65.43 90.275 ;
     RECT  7.128 90.275 17.73 90.311 ;
     RECT  20.7 90.275 32.706 90.311 ;
     RECT  33.804 90.239 36.342 90.311 ;
     RECT  37.224 90.275 37.89 90.311 ;
     RECT  57.6 90.275 64.797 90.311 ;
     RECT  38.916 90.239 47.394 90.32 ;
     RECT  29.415 90.311 32.634 90.347 ;
     RECT  48.315 90.275 49.482 90.347 ;
     RECT  7.128 90.311 14.058 90.383 ;
     RECT  33.948 90.311 35.982 90.383 ;
     RECT  37.224 90.311 37.797 90.383 ;
     RECT  14.832 90.311 17.73 90.419 ;
     RECT  29.415 90.347 31.122 90.419 ;
     RECT  38.916 90.32 47.322 90.419 ;
     RECT  2.415 88.889 2.697 90.467 ;
     RECT  5.115 89.549 5.397 90.467 ;
     RECT  18.615 90.275 18.897 90.467 ;
     RECT  33.948 90.383 35.73 90.467 ;
     RECT  37.332 90.383 37.797 90.467 ;
     RECT  39.348 90.419 40.497 90.467 ;
     RECT  51.015 90.239 56.697 90.467 ;
     RECT  57.6 90.311 59.397 90.467 ;
     RECT  60.588 90.311 64.797 90.467 ;
     RECT  69.915 88.889 70.197 90.467 ;
     RECT  72.615 89.195 72.897 90.467 ;
     RECT  75.315 88.691 75.597 90.467 ;
     RECT  7.128 90.383 13.95 90.509 ;
     RECT  14.832 90.419 16.398 90.509 ;
     RECT  17.244 90.419 17.73 90.509 ;
     RECT  20.7 90.311 28.278 90.509 ;
     RECT  31.104 90.419 31.122 90.509 ;
     RECT  32.112 90.347 32.634 90.509 ;
     RECT  33.948 90.467 34.905 90.509 ;
     RECT  35.712 90.467 35.73 90.509 ;
     RECT  37.332 90.467 37.605 90.509 ;
     RECT  39.348 90.467 40.305 90.509 ;
     RECT  41.508 90.419 47.322 90.509 ;
     RECT  51.015 90.467 56.505 90.509 ;
     RECT  57.6 90.467 59.205 90.509 ;
     RECT  60.588 90.467 64.638 90.509 ;
     RECT  66.204 90.239 67.986 90.509 ;
     RECT  7.128 90.509 8.946 90.545 ;
     RECT  13.215 90.509 13.878 90.545 ;
     RECT  17.244 90.509 17.658 90.545 ;
     RECT  20.7 90.509 21.405 90.545 ;
     RECT  22.644 90.509 22.662 90.545 ;
     RECT  24.015 90.509 26.805 90.545 ;
     RECT  29.415 90.419 30.366 90.545 ;
     RECT  32.112 90.509 32.49 90.545 ;
     RECT  33.948 90.509 33.966 90.545 ;
     RECT  39.348 90.509 39.366 90.545 ;
     RECT  41.508 90.509 41.526 90.545 ;
     RECT  44.208 90.509 44.874 90.545 ;
     RECT  45.615 90.509 46.71 90.545 ;
     RECT  48.315 90.347 49.122 90.545 ;
     RECT  53.715 90.509 55.674 90.545 ;
     RECT  57.6 90.509 57.618 90.545 ;
     RECT  58.572 90.509 59.205 90.545 ;
     RECT  61.56 90.509 63.126 90.545 ;
     RECT  64.188 90.509 64.605 90.545 ;
     RECT  7.128 90.545 8.154 90.557 ;
     RECT  8.928 90.545 8.946 90.557 ;
     RECT  9.9 90.509 11.178 90.557 ;
     RECT  12.456 90.509 12.474 90.557 ;
     RECT  10.515 90.557 11.178 90.568 ;
     RECT  48.315 90.545 49.05 90.581 ;
     RECT  51.015 90.509 52.074 90.581 ;
     RECT  64.476 90.545 64.605 90.581 ;
     RECT  7.815 90.557 8.154 90.617 ;
     RECT  14.832 90.509 16.005 90.617 ;
     RECT  17.28 90.545 17.298 90.617 ;
     RECT  20.88 90.545 21.405 90.617 ;
     RECT  25.092 90.545 25.11 90.617 ;
     RECT  32.115 90.545 32.49 90.617 ;
     RECT  42.915 90.509 43.326 90.617 ;
     RECT  51.015 90.581 51.39 90.617 ;
     RECT  53.715 90.545 54.198 90.617 ;
     RECT  55.296 90.545 55.314 90.617 ;
     RECT  61.56 90.545 62.154 90.617 ;
     RECT  2.415 90.467 2.505 90.737 ;
     RECT  5.115 90.467 5.205 90.737 ;
     RECT  7.815 90.617 7.905 90.737 ;
     RECT  10.515 90.568 10.605 90.737 ;
     RECT  13.215 90.545 13.305 90.737 ;
     RECT  15.915 90.617 16.005 90.737 ;
     RECT  18.615 90.467 18.705 90.737 ;
     RECT  21.315 90.617 21.405 90.737 ;
     RECT  24.015 90.545 24.105 90.737 ;
     RECT  26.715 90.545 26.805 90.737 ;
     RECT  29.415 90.545 29.505 90.737 ;
     RECT  32.115 90.617 32.205 90.737 ;
     RECT  34.815 90.509 34.905 90.737 ;
     RECT  37.515 90.509 37.605 90.737 ;
     RECT  40.215 90.509 40.305 90.737 ;
     RECT  42.915 90.617 43.005 90.737 ;
     RECT  45.615 90.545 45.705 90.737 ;
     RECT  48.315 90.581 48.405 90.737 ;
     RECT  51.015 90.617 51.105 90.737 ;
     RECT  53.715 90.617 53.805 90.737 ;
     RECT  56.415 90.509 56.505 90.737 ;
     RECT  59.115 90.545 59.205 90.737 ;
     RECT  61.815 90.617 61.905 90.737 ;
     RECT  64.515 90.581 64.605 90.737 ;
     RECT  67.215 90.509 67.305 90.737 ;
     RECT  69.915 90.467 70.005 90.737 ;
     RECT  72.615 90.467 72.705 90.737 ;
     RECT  75.315 90.467 75.405 90.737 ;
    LAYER M4 ;
     RECT  0.156 4.416 2.408 88.536 ;
     RECT  2.408 2.148 2.512 90.732 ;
     RECT  2.512 2.418 2.704 90.462 ;
     RECT  2.704 10.08 2.729 21.528 ;
     RECT  2.704 27.456 2.729 31.8 ;
     RECT  2.704 84.912 2.729 87.864 ;
     RECT  2.729 10.08 2.765 16.296 ;
     RECT  2.729 27.456 2.765 29.304 ;
     RECT  2.704 54.672 2.765 60.888 ;
     RECT  2.704 67.632 2.765 71.256 ;
     RECT  2.704 78.816 2.765 83.784 ;
     RECT  2.729 85.2 2.765 87.864 ;
     RECT  2.704 61.92 2.801 63.864 ;
     RECT  2.704 72.384 2.801 77.736 ;
     RECT  2.704 22.752 2.837 26.376 ;
     RECT  2.765 27.648 2.837 29.304 ;
     RECT  2.729 30.576 2.837 31.8 ;
     RECT  2.704 33.36 2.837 38.184 ;
     RECT  2.704 39.264 2.837 53.64 ;
     RECT  2.765 54.672 2.837 60.408 ;
     RECT  2.704 64.944 2.837 66.6 ;
     RECT  2.801 73.824 2.837 77.736 ;
     RECT  2.765 81.456 2.837 83.784 ;
     RECT  2.765 85.728 2.837 87.864 ;
     RECT  2.837 55.776 2.873 60.408 ;
     RECT  2.837 33.36 2.945 34.248 ;
     RECT  2.837 65.328 2.945 66.6 ;
     RECT  2.873 55.776 2.981 59.016 ;
     RECT  2.765 67.68 2.981 71.256 ;
     RECT  2.981 69.984 3.004 71.256 ;
     RECT  2.837 81.456 3.053 83.544 ;
     RECT  2.729 17.376 3.089 21.528 ;
     RECT  2.837 40.32 3.197 43.032 ;
     RECT  2.837 44.4 3.197 53.64 ;
     RECT  2.981 55.872 3.269 59.016 ;
     RECT  3.089 17.376 3.299 20.28 ;
     RECT  3.299 17.376 3.305 19.512 ;
     RECT  3.305 17.424 3.377 19.512 ;
     RECT  3.004 69.984 3.413 70.632 ;
     RECT  2.981 67.68 3.449 68.952 ;
     RECT  2.801 63.264 3.629 63.864 ;
     RECT  2.837 73.824 3.665 75.192 ;
     RECT  2.704 6.816 3.697 7.368 ;
     RECT  2.945 65.328 3.701 66.264 ;
     RECT  2.837 54.672 3.733 54.696 ;
     RECT  3.665 73.824 3.769 74.952 ;
     RECT  2.837 77.04 3.769 77.736 ;
     RECT  2.765 78.816 3.769 80.424 ;
     RECT  2.801 72.384 3.788 72.408 ;
     RECT  3.197 44.592 3.805 53.64 ;
     RECT  3.733 54.624 3.805 54.696 ;
     RECT  3.788 72 3.829 72.408 ;
     RECT  3.769 73.536 3.829 74.952 ;
     RECT  3.697 6.816 3.841 7.464 ;
     RECT  2.704 8.496 3.841 9.048 ;
     RECT  2.837 22.752 3.841 22.776 ;
     RECT  2.837 23.856 3.841 26.376 ;
     RECT  2.837 27.888 3.841 27.96 ;
     RECT  2.873 60.384 3.841 60.408 ;
     RECT  2.837 85.872 3.841 87.864 ;
     RECT  3.629 63.264 3.877 63.288 ;
     RECT  2.704 3.408 3.881 3.432 ;
     RECT  3.805 44.592 3.881 54.696 ;
     RECT  2.704 4.656 3.913 5.688 ;
     RECT  3.841 6.816 3.913 9.048 ;
     RECT  3.197 40.416 3.913 43.032 ;
     RECT  3.841 85.728 3.913 87.864 ;
     RECT  2.704 88.896 3.913 88.92 ;
     RECT  3.913 4.656 3.949 9.048 ;
     RECT  2.945 33.552 3.949 34.248 ;
     RECT  3.881 45.984 3.985 54.696 ;
     RECT  3.269 55.872 3.985 55.896 ;
     RECT  3.769 77.04 3.985 80.424 ;
     RECT  3.053 81.456 3.985 81.48 ;
     RECT  3.949 3.936 4.021 9.048 ;
     RECT  2.765 10.08 4.021 14.136 ;
     RECT  3.841 22.752 4.021 27.96 ;
     RECT  2.837 28.944 4.021 29.304 ;
     RECT  3.413 70.032 4.021 70.632 ;
     RECT  3.829 72 4.021 74.952 ;
     RECT  4.021 22.752 4.057 29.304 ;
     RECT  4.057 22.752 4.061 29.928 ;
     RECT  3.913 40.416 4.061 43.56 ;
     RECT  2.765 15.504 4.069 16.296 ;
     RECT  3.841 60.384 4.093 60.984 ;
     RECT  3.089 21.456 4.165 21.48 ;
     RECT  4.061 26.016 4.165 29.928 ;
     RECT  2.837 31.44 4.165 31.8 ;
     RECT  3.949 33.552 4.201 34.968 ;
     RECT  4.165 21.456 4.237 21.528 ;
     RECT  4.061 22.752 4.237 25.032 ;
     RECT  4.061 41.472 4.237 43.56 ;
     RECT  3.881 44.592 4.237 45 ;
     RECT  3.877 63.216 4.273 63.288 ;
     RECT  3.053 82.464 4.273 83.544 ;
     RECT  4.201 33.552 4.345 35.304 ;
     RECT  2.837 36.48 4.345 38.184 ;
     RECT  3.377 18.768 4.381 19.512 ;
     RECT  3.701 66.048 4.417 66.264 ;
     RECT  3.449 67.68 4.417 68.424 ;
     RECT  4.381 18.72 4.489 19.512 ;
     RECT  3.269 57.36 4.489 59.016 ;
     RECT  4.069 15.408 4.525 16.296 ;
     RECT  3.377 17.424 4.525 17.688 ;
     RECT  4.489 18.72 4.525 19.896 ;
     RECT  4.237 75.936 4.525 75.96 ;
     RECT  3.985 77.04 4.525 81.48 ;
     RECT  4.417 66.048 4.561 68.424 ;
     RECT  4.021 70.032 4.561 74.952 ;
     RECT  4.489 57.312 4.597 59.016 ;
     RECT  4.093 60.384 4.597 61.944 ;
     RECT  4.345 33.552 4.669 38.184 ;
     RECT  2.837 39.264 4.669 39.288 ;
     RECT  4.525 75.936 4.669 81.48 ;
     RECT  4.273 82.464 4.669 83.592 ;
     RECT  3.913 85.728 4.669 88.92 ;
     RECT  4.561 66.048 4.7 74.952 ;
     RECT  4.669 75.936 4.7 83.592 ;
     RECT  4.525 18.72 4.705 20.04 ;
     RECT  4.669 33.552 4.705 39.288 ;
     RECT  4.021 3.936 4.708 14.136 ;
     RECT  4.708 3.936 4.741 14.184 ;
     RECT  4.525 15.408 4.741 17.688 ;
     RECT  4.669 85.488 4.741 88.92 ;
     RECT  4.741 85.152 4.777 88.92 ;
     RECT  4.741 3.936 4.813 17.688 ;
     RECT  4.705 18.72 4.813 20.136 ;
     RECT  4.165 26.016 4.813 31.8 ;
     RECT  4.705 33.12 4.813 39.288 ;
     RECT  4.273 62.976 4.813 63.288 ;
     RECT  4.345 64.368 4.813 64.392 ;
     RECT  4.237 41.472 4.849 45 ;
     RECT  3.985 45.984 4.849 55.896 ;
     RECT  4.7 66.048 4.849 83.592 ;
     RECT  4.813 3.936 4.921 20.136 ;
     RECT  4.237 21.456 4.921 25.032 ;
     RECT  4.849 41.472 4.993 56.088 ;
     RECT  4.597 57.312 4.993 61.944 ;
     RECT  4.849 66.048 5.029 83.64 ;
     RECT  4.777 84.672 5.029 88.92 ;
     RECT  5.029 66.048 5.065 88.92 ;
     RECT  4.813 62.976 5.101 64.392 ;
     RECT  4.921 3.936 5.108 25.032 ;
     RECT  4.813 26.016 5.108 39.288 ;
     RECT  4.061 40.416 5.108 40.44 ;
     RECT  4.993 41.472 5.108 61.944 ;
     RECT  5.101 62.976 5.108 64.968 ;
     RECT  5.065 65.952 5.108 88.92 ;
     RECT  5.108 2.148 5.212 90.732 ;
     RECT  5.212 2.418 5.404 90.462 ;
     RECT  5.404 40.416 5.501 63.864 ;
     RECT  5.404 64.944 5.555 87.864 ;
     RECT  5.555 64.944 5.609 87.576 ;
     RECT  5.501 43.296 5.699 63.864 ;
     RECT  5.699 45.648 5.789 63.864 ;
     RECT  5.609 64.944 5.897 78.984 ;
     RECT  5.501 40.416 5.969 42.264 ;
     RECT  5.969 40.416 6.005 42.024 ;
     RECT  5.789 45.648 6.257 59.832 ;
     RECT  5.404 3.888 6.545 39.336 ;
     RECT  5.404 88.848 6.581 89.544 ;
     RECT  6.257 46.176 6.617 59.832 ;
     RECT  5.789 60.96 6.649 63.864 ;
     RECT  5.897 64.944 6.649 65.448 ;
     RECT  6.545 10.656 6.685 39.336 ;
     RECT  6.005 40.416 6.685 41.976 ;
     RECT  6.617 46.224 6.757 59.832 ;
     RECT  6.649 60.96 6.757 65.448 ;
     RECT  5.699 43.296 6.793 44.472 ;
     RECT  5.897 66.72 6.793 78.984 ;
     RECT  5.609 80.016 6.793 87.576 ;
     RECT  6.685 10.656 6.796 41.976 ;
     RECT  6.793 43.296 6.829 44.76 ;
     RECT  6.757 46.224 6.865 65.448 ;
     RECT  6.793 66.72 6.865 87.576 ;
     RECT  6.865 46.224 7.009 87.576 ;
     RECT  6.581 88.848 7.009 88.872 ;
     RECT  6.829 43.056 7.225 44.76 ;
     RECT  6.545 3.888 7.765 9.384 ;
     RECT  7.765 3.888 7.808 9.624 ;
     RECT  6.796 10.656 7.808 40.392 ;
     RECT  6.796 41.376 7.808 41.976 ;
     RECT  7.225 43.056 7.808 45.192 ;
     RECT  7.009 46.224 7.808 88.872 ;
     RECT  7.117 90.528 7.808 90.552 ;
     RECT  7.808 2.148 7.912 90.732 ;
     RECT  7.912 2.418 8.104 90.552 ;
     RECT  8.104 2.832 8.129 9.384 ;
     RECT  8.129 4.176 9.107 9.384 ;
     RECT  9.107 9.36 9.133 9.384 ;
     RECT  8.104 10.368 9.133 88.872 ;
     RECT  9.133 9.36 9.281 88.872 ;
     RECT  8.129 2.832 9.673 3.048 ;
     RECT  9.107 4.176 9.673 8.328 ;
     RECT  9.281 15.504 10.249 65.784 ;
     RECT  9.281 66.768 10.249 88.872 ;
     RECT  9.673 2.832 10.508 8.328 ;
     RECT  9.281 9.36 10.508 14.52 ;
     RECT  10.249 15.504 10.508 88.872 ;
     RECT  8.104 90.528 10.508 90.552 ;
     RECT  10.508 2.148 10.612 90.732 ;
     RECT  10.612 2.418 10.804 90.552 ;
     RECT  10.804 9.552 10.937 90.552 ;
     RECT  10.804 2.64 10.973 8.328 ;
     RECT  10.973 2.688 11.164 8.328 ;
     RECT  11.164 2.928 11.171 8.328 ;
     RECT  10.937 25.968 11.513 90.552 ;
     RECT  10.937 9.552 11.603 24.936 ;
     RECT  11.171 3.888 11.905 8.328 ;
     RECT  11.603 9.552 11.905 9.576 ;
     RECT  11.513 25.968 11.909 88.968 ;
     RECT  11.905 3.888 11.945 9.576 ;
     RECT  11.603 10.656 12.409 24.936 ;
     RECT  12.409 10.656 12.481 24.984 ;
     RECT  11.909 25.968 12.481 55.848 ;
     RECT  11.945 3.888 12.517 9.384 ;
     RECT  12.481 10.656 12.877 55.848 ;
     RECT  11.909 56.832 12.877 88.968 ;
     RECT  12.908 0.144 12.995 0.168 ;
     RECT  12.877 10.656 13.093 88.968 ;
     RECT  12.517 3.36 13.208 9.384 ;
     RECT  13.093 10.656 13.208 89.448 ;
     RECT  11.513 90.528 13.208 90.552 ;
     RECT  13.208 2.148 13.312 90.732 ;
     RECT  13.312 2.256 13.504 90.462 ;
     RECT  13.504 2.256 13.709 24.936 ;
     RECT  13.709 2.256 14.147 24.744 ;
     RECT  14.147 2.688 14.677 24.744 ;
     RECT  13.504 26.064 14.861 89.448 ;
     RECT  14.677 2.688 15.073 24.792 ;
     RECT  14.861 45.696 15.445 89.448 ;
     RECT  15.445 45.696 15.829 89.688 ;
     RECT  15.073 2.688 15.908 25.032 ;
     RECT  14.861 26.064 15.908 44.424 ;
     RECT  15.829 45.456 15.908 89.688 ;
     RECT  15.908 2.148 16.012 90.732 ;
     RECT  16.012 2.208 16.204 90.462 ;
     RECT  16.204 89.184 16.337 89.832 ;
     RECT  16.204 2.208 16.445 44.376 ;
     RECT  16.445 9.84 17.269 44.376 ;
     RECT  16.204 45.456 17.269 88.2 ;
     RECT  16.445 2.208 18.169 8.52 ;
     RECT  17.269 9.84 18.421 88.2 ;
     RECT  16.337 89.424 18.421 89.832 ;
     RECT  18.169 2.208 18.608 8.568 ;
     RECT  18.421 9.84 18.608 89.832 ;
     RECT  18.608 2.148 18.712 90.732 ;
     RECT  18.712 2.418 18.904 90.462 ;
     RECT  18.904 54.624 19.001 88.824 ;
     RECT  18.904 89.808 19.289 90.072 ;
     RECT  18.904 2.592 19.541 53.304 ;
     RECT  19.541 2.592 19.721 8.664 ;
     RECT  19.541 9.84 19.964 53.304 ;
     RECT  19.001 54.672 19.964 88.824 ;
     RECT  19.964 9.84 20.051 88.824 ;
     RECT  19.721 2.736 20.761 8.664 ;
     RECT  20.051 9.84 20.761 53.64 ;
     RECT  20.051 54.672 20.761 88.824 ;
     RECT  20.761 54.672 20.773 88.92 ;
     RECT  20.761 2.736 20.905 53.64 ;
     RECT  20.905 2.256 21.308 53.64 ;
     RECT  20.773 54.672 21.308 89.016 ;
     RECT  19.289 90.048 21.308 90.072 ;
     RECT  21.308 2.148 21.412 90.732 ;
     RECT  21.412 2.256 21.604 90.462 ;
     RECT  21.604 2.256 21.737 48.168 ;
     RECT  21.604 49.248 21.953 64.968 ;
     RECT  21.737 2.256 22.061 14.472 ;
     RECT  21.737 15.456 22.205 48.168 ;
     RECT  21.953 49.248 22.277 59.256 ;
     RECT  22.061 9.744 22.313 14.472 ;
     RECT  22.277 49.776 22.355 59.256 ;
     RECT  22.205 41.76 22.693 48.168 ;
     RECT  22.693 41.76 22.781 48.696 ;
     RECT  22.061 2.256 22.997 8.52 ;
     RECT  22.355 54.672 23.181 59.256 ;
     RECT  21.953 60.336 23.181 64.968 ;
     RECT  21.604 65.952 23.245 89.16 ;
     RECT  22.205 15.456 23.353 40.68 ;
     RECT  22.781 41.76 23.353 48.264 ;
     RECT  22.355 49.776 23.425 53.64 ;
     RECT  22.997 3.408 23.713 8.52 ;
     RECT  23.245 65.952 23.785 89.544 ;
     RECT  22.997 2.256 24.008 2.28 ;
     RECT  23.713 3.408 24.008 8.808 ;
     RECT  22.313 9.792 24.008 14.472 ;
     RECT  23.353 15.456 24.008 48.264 ;
     RECT  23.425 49.584 24.008 53.64 ;
     RECT  23.181 54.672 24.008 64.968 ;
     RECT  23.785 65.952 24.008 90.072 ;
     RECT  24.008 2.148 24.112 90.732 ;
     RECT  24.112 2.256 24.304 90.462 ;
     RECT  24.304 2.256 24.437 8.808 ;
     RECT  24.437 2.256 24.481 3 ;
     RECT  24.304 9.84 24.545 48.264 ;
     RECT  24.304 49.344 24.905 64.968 ;
     RECT  24.304 65.952 25.337 88.488 ;
     RECT  24.437 4.08 25.513 8.808 ;
     RECT  24.545 9.84 25.513 48.216 ;
     RECT  24.304 90.048 25.585 90.072 ;
     RECT  24.481 2.256 25.661 2.28 ;
     RECT  24.905 49.488 25.667 64.968 ;
     RECT  25.667 64.32 25.697 64.968 ;
     RECT  26.305 2.736 26.708 2.76 ;
     RECT  25.513 4.08 26.708 48.216 ;
     RECT  25.667 49.488 26.708 63.096 ;
     RECT  25.697 64.32 26.708 64.872 ;
     RECT  25.337 65.952 26.708 88.392 ;
     RECT  25.585 89.424 26.708 90.072 ;
     RECT  26.708 2.148 26.812 90.732 ;
     RECT  26.812 2.418 27.004 90.462 ;
     RECT  27.004 35.28 27.173 90.072 ;
     RECT  27.004 3.984 27.347 33.864 ;
     RECT  27.347 3.984 27.353 33.144 ;
     RECT  27.173 43.872 27.635 90.072 ;
     RECT  27.173 35.28 27.749 42.84 ;
     RECT  27.004 2.418 27.781 2.808 ;
     RECT  27.749 41.76 27.785 42.84 ;
     RECT  27.781 2.352 27.865 2.808 ;
     RECT  27.353 3.984 27.971 33.048 ;
     RECT  27.971 4.176 28.217 33.048 ;
     RECT  27.749 35.28 28.285 40.728 ;
     RECT  28.285 34.896 28.289 40.728 ;
     RECT  28.289 34.896 28.429 40.392 ;
     RECT  27.785 41.76 28.861 42.744 ;
     RECT  28.217 9.6 28.897 33.048 ;
     RECT  28.861 41.76 28.969 42.792 ;
     RECT  27.635 43.872 28.969 89.736 ;
     RECT  28.897 9.6 29.041 33.144 ;
     RECT  28.969 41.712 29.041 42.792 ;
     RECT  29.041 9.6 29.077 33.288 ;
     RECT  28.429 34.752 29.077 40.392 ;
     RECT  29.041 41.712 29.257 42.84 ;
     RECT  28.969 43.872 29.257 90.024 ;
     RECT  27.865 2.784 29.408 2.808 ;
     RECT  28.217 4.176 29.408 8.52 ;
     RECT  29.077 9.6 29.408 40.392 ;
     RECT  29.257 41.712 29.408 90.024 ;
     RECT  29.408 2.148 29.512 90.732 ;
     RECT  29.512 2.418 29.704 90.462 ;
     RECT  29.704 4.176 30.521 90.12 ;
     RECT  30.521 4.176 30.707 88.968 ;
     RECT  30.707 49.536 30.737 88.968 ;
     RECT  29.704 2.496 30.757 2.52 ;
     RECT  30.757 2.496 30.769 2.952 ;
     RECT  30.707 4.176 30.769 48.456 ;
     RECT  30.769 2.496 30.773 48.456 ;
     RECT  30.773 34.656 30.809 48.456 ;
     RECT  30.737 62.16 30.851 88.44 ;
     RECT  30.773 2.496 30.899 33.528 ;
     RECT  30.851 64.128 31.133 88.44 ;
     RECT  30.521 90 31.525 90.12 ;
     RECT  30.809 34.656 31.777 42.552 ;
     RECT  30.809 43.536 31.777 48.456 ;
     RECT  30.737 49.536 31.896 61.128 ;
     RECT  30.899 2.496 32.108 2.904 ;
     RECT  30.899 4.176 32.108 33.528 ;
     RECT  31.777 34.656 32.108 48.456 ;
     RECT  31.896 49.488 32.108 61.128 ;
     RECT  30.851 62.16 32.108 63.096 ;
     RECT  31.133 64.128 32.108 88.392 ;
     RECT  31.525 89.424 32.108 90.12 ;
     RECT  32.108 2.148 32.212 90.732 ;
     RECT  32.212 2.304 32.404 90.462 ;
     RECT  32.404 2.304 33.149 2.856 ;
     RECT  32.404 64.32 33.577 88.2 ;
     RECT  32.404 89.424 33.937 89.448 ;
     RECT  33.149 2.832 34.045 2.856 ;
     RECT  32.404 4.08 34.045 63.096 ;
     RECT  34.045 2.832 34.117 63.096 ;
     RECT  34.117 2.592 34.153 63.096 ;
     RECT  33.577 64.128 34.153 88.2 ;
     RECT  33.937 89.424 34.153 90.072 ;
     RECT  34.153 2.592 34.808 90.072 ;
     RECT  34.808 2.148 34.912 90.732 ;
     RECT  34.912 2.418 35.104 90.462 ;
     RECT  35.104 4.176 35.165 90.072 ;
     RECT  35.165 4.176 35.201 63.144 ;
     RECT  35.201 4.176 35.219 42.744 ;
     RECT  35.165 64.128 35.237 90.072 ;
     RECT  35.104 2.592 35.309 2.616 ;
     RECT  35.219 4.176 35.381 38.952 ;
     RECT  35.201 43.872 35.381 63.144 ;
     RECT  35.219 40.08 36.169 42.744 ;
     RECT  35.381 43.872 36.169 63.096 ;
     RECT  35.237 89.472 36.179 90.024 ;
     RECT  35.237 64.128 36.241 88.44 ;
     RECT  36.179 89.472 36.241 89.496 ;
     RECT  35.381 4.176 36.277 33.048 ;
     RECT  36.169 40.08 36.38 63.096 ;
     RECT  36.241 64.128 36.38 89.496 ;
     RECT  36.38 40.08 36.389 89.496 ;
     RECT  36.389 40.08 36.467 88.44 ;
     RECT  35.381 34.032 36.497 38.952 ;
     RECT  36.277 3.408 37.033 33.048 ;
     RECT  36.497 34.032 37.033 38.712 ;
     RECT  36.467 40.08 37.141 63.288 ;
     RECT  37.033 3.408 37.249 38.712 ;
     RECT  37.249 3.024 37.465 38.712 ;
     RECT  37.465 3.024 37.508 38.76 ;
     RECT  37.141 39.792 37.508 63.288 ;
     RECT  36.467 64.32 37.508 88.44 ;
     RECT  36.389 89.472 37.508 89.496 ;
     RECT  37.508 2.148 37.612 90.732 ;
     RECT  37.612 2.418 37.804 90.462 ;
     RECT  37.804 64.368 38.189 88.968 ;
     RECT  37.804 2.418 38.761 63.288 ;
     RECT  38.761 2.208 38.915 63.288 ;
     RECT  38.189 64.416 39.193 88.968 ;
     RECT  38.915 2.832 39.337 63.288 ;
     RECT  39.193 64.416 39.337 89.352 ;
     RECT  39.337 2.832 39.949 89.352 ;
     RECT  39.337 90.336 39.949 90.36 ;
     RECT  39.949 2.832 40.208 90.36 ;
     RECT  40.208 2.148 40.312 90.732 ;
     RECT  40.312 2.418 40.504 90.504 ;
     RECT  40.504 3.024 40.739 90.504 ;
     RECT  40.739 3.024 40.745 63.096 ;
     RECT  40.739 64.32 40.745 90.504 ;
     RECT  40.745 43.536 41.027 63.096 ;
     RECT  40.745 81.936 41.075 88.968 ;
     RECT  40.745 3.024 41.537 42.552 ;
     RECT  40.745 90.48 41.537 90.504 ;
     RECT  41.537 3.024 41.605 32.856 ;
     RECT  41.605 2.736 41.681 32.856 ;
     RECT  41.681 2.736 41.689 3.144 ;
     RECT  41.537 34.032 41.753 42.552 ;
     RECT  41.027 45.168 41.785 63.096 ;
     RECT  40.745 64.32 41.785 80.904 ;
     RECT  41.753 40.08 42.325 42.552 ;
     RECT  41.027 43.536 42.325 44.136 ;
     RECT  41.681 4.128 42.613 32.856 ;
     RECT  42.613 4.128 42.757 33.048 ;
     RECT  41.753 34.032 42.757 39 ;
     RECT  41.785 45.168 42.757 80.904 ;
     RECT  41.075 81.936 42.757 88.2 ;
     RECT  42.757 4.128 42.865 39 ;
     RECT  42.325 40.08 42.865 44.136 ;
     RECT  41.689 2.88 42.908 3.144 ;
     RECT  42.865 4.128 42.908 44.136 ;
     RECT  42.757 45.12 42.908 80.904 ;
     RECT  42.757 81.936 42.908 89.016 ;
     RECT  42.908 2.148 43.012 90.732 ;
     RECT  43.012 2.304 43.204 90.462 ;
     RECT  43.204 2.304 43.625 2.904 ;
     RECT  43.204 3.888 44.003 89.016 ;
     RECT  44.003 3.888 44.021 63.672 ;
     RECT  44.021 3.888 44.093 63.624 ;
     RECT  44.093 31.2 44.525 63.096 ;
     RECT  43.625 2.592 44.665 2.904 ;
     RECT  44.093 3.888 44.665 30.168 ;
     RECT  44.665 2.592 45.169 30.168 ;
     RECT  44.525 31.2 45.169 44.184 ;
     RECT  44.003 64.656 45.457 89.016 ;
     RECT  45.169 2.592 45.608 44.184 ;
     RECT  44.525 45.168 45.608 63.096 ;
     RECT  45.457 64.608 45.608 89.016 ;
     RECT  43.204 90.048 45.608 90.072 ;
     RECT  45.608 2.148 45.712 90.732 ;
     RECT  45.712 2.418 45.904 90.462 ;
     RECT  45.904 45.168 45.965 90.312 ;
     RECT  45.965 64.176 46.721 90.312 ;
     RECT  45.965 45.168 46.757 63.096 ;
     RECT  45.904 34.176 46.937 44.136 ;
     RECT  45.904 2.784 46.981 32.904 ;
     RECT  46.981 2.784 47.041 33.912 ;
     RECT  47.041 2.736 47.068 33.912 ;
     RECT  47.068 2.736 47.113 32.856 ;
     RECT  46.721 64.176 47.225 89.256 ;
     RECT  46.937 35.28 47.293 44.136 ;
     RECT  46.757 45.168 47.293 61.032 ;
     RECT  47.068 33.888 48.049 33.912 ;
     RECT  47.293 35.28 48.049 61.032 ;
     RECT  46.757 62.016 48.121 63.096 ;
     RECT  48.121 62.016 48.193 63.576 ;
     RECT  48.193 62.016 48.301 63.624 ;
     RECT  47.225 64.704 48.301 89.256 ;
     RECT  47.113 2.304 48.308 32.856 ;
     RECT  48.049 33.888 48.308 61.032 ;
     RECT  48.301 62.016 48.308 89.256 ;
     RECT  46.721 90.288 48.308 90.312 ;
     RECT  48.308 2.148 48.412 90.732 ;
     RECT  48.412 2.418 48.604 90.462 ;
     RECT  48.604 60.288 48.629 89.016 ;
     RECT  48.604 2.688 48.755 33.624 ;
     RECT  48.604 35.232 48.773 59.064 ;
     RECT  48.773 35.28 49.745 59.064 ;
     RECT  48.629 60.288 49.885 88.968 ;
     RECT  48.604 90.048 49.885 90.072 ;
     RECT  49.745 35.28 49.921 42.552 ;
     RECT  49.745 43.536 49.925 59.064 ;
     RECT  48.755 3.36 49.993 33.624 ;
     RECT  49.921 34.8 49.993 42.552 ;
     RECT  49.993 3.36 50.065 42.552 ;
     RECT  50.065 3.312 50.245 42.552 ;
     RECT  50.245 2.832 50.713 42.552 ;
     RECT  50.713 2.352 51.008 42.552 ;
     RECT  49.925 43.536 51.008 44.184 ;
     RECT  49.925 45.168 51.008 59.064 ;
     RECT  49.885 60.288 51.008 90.072 ;
     RECT  51.008 2.148 51.112 90.732 ;
     RECT  51.112 2.352 51.304 90.462 ;
     RECT  51.304 2.352 51.473 30.168 ;
     RECT  51.304 31.2 51.473 89.832 ;
     RECT  51.473 2.352 51.581 2.376 ;
     RECT  51.473 31.2 51.653 63.24 ;
     RECT  51.473 64.656 51.653 89.832 ;
     RECT  51.653 49.2 51.689 63.24 ;
     RECT  51.473 3.36 52.657 30.168 ;
     RECT  52.657 2.88 52.729 30.168 ;
     RECT  51.653 31.2 52.729 48.216 ;
     RECT  51.653 64.704 52.909 89.832 ;
     RECT  51.689 60.288 52.981 63.24 ;
     RECT  52.909 64.416 52.981 89.832 ;
     RECT  51.689 49.2 53.017 59.064 ;
     RECT  53.017 49.2 53.084 59.112 ;
     RECT  52.981 60.288 53.084 89.832 ;
     RECT  52.729 2.88 53.233 48.216 ;
     RECT  53.084 49.2 53.233 89.832 ;
     RECT  53.233 2.88 53.485 89.832 ;
     RECT  53.485 2.784 53.708 89.832 ;
     RECT  53.708 2.148 53.812 90.732 ;
     RECT  53.812 2.418 54.004 90.462 ;
     RECT  54.004 2.784 54.929 89.832 ;
     RECT  54.929 2.784 55.073 61.128 ;
     RECT  54.929 62.16 55.573 89.832 ;
     RECT  55.073 2.784 55.717 33.192 ;
     RECT  55.717 2.736 56.408 33.192 ;
     RECT  55.073 34.368 56.408 44.136 ;
     RECT  55.073 45.168 56.408 61.128 ;
     RECT  55.573 62.16 56.408 90.504 ;
     RECT  56.408 2.148 56.512 90.732 ;
     RECT  56.512 2.418 56.704 90.462 ;
     RECT  56.704 49.296 56.963 88.968 ;
     RECT  56.704 2.832 57.017 33.096 ;
     RECT  56.963 49.584 57.197 88.968 ;
     RECT  57.197 49.584 57.629 64.728 ;
     RECT  57.197 66 57.772 88.968 ;
     RECT  56.704 34.752 57.985 48.216 ;
     RECT  57.629 49.584 57.985 63.096 ;
     RECT  57.772 75.456 58.381 88.968 ;
     RECT  56.704 90.048 58.381 90.072 ;
     RECT  57.629 64.368 58.453 64.728 ;
     RECT  57.772 66 58.453 74.424 ;
     RECT  57.017 2.832 58.549 33.048 ;
     RECT  57.985 34.752 58.549 63.096 ;
     RECT  58.549 2.832 58.777 33.144 ;
     RECT  58.549 34.128 58.813 63.096 ;
     RECT  58.381 75.456 58.813 90.072 ;
     RECT  58.453 64.368 58.921 74.424 ;
     RECT  58.813 75.408 58.921 90.072 ;
     RECT  58.813 34.128 59.029 63.384 ;
     RECT  58.921 64.368 59.029 90.072 ;
     RECT  58.777 2.256 59.108 33.144 ;
     RECT  59.029 34.128 59.108 90.072 ;
     RECT  59.108 2.148 59.212 90.732 ;
     RECT  59.212 2.256 59.404 90.462 ;
     RECT  59.404 64.32 59.753 90.024 ;
     RECT  59.404 34.224 59.933 63.288 ;
     RECT  59.753 64.32 60.113 89.544 ;
     RECT  59.933 34.224 60.275 63.096 ;
     RECT  59.404 2.256 60.397 32.904 ;
     RECT  60.275 34.224 60.397 61.128 ;
     RECT  60.397 2.256 60.725 61.128 ;
     RECT  60.275 62.16 61.441 63.096 ;
     RECT  61.441 62.16 61.513 63.576 ;
     RECT  60.113 64.56 61.513 89.544 ;
     RECT  60.725 2.256 61.808 22.296 ;
     RECT  60.725 23.568 61.808 61.128 ;
     RECT  61.513 62.16 61.808 89.544 ;
     RECT  61.808 2.148 61.912 90.732 ;
     RECT  61.912 2.418 62.104 90.462 ;
     RECT  62.104 2.784 62.201 89.832 ;
     RECT  62.201 19.632 62.309 88.488 ;
     RECT  62.309 49.776 62.453 88.488 ;
     RECT  62.201 2.784 62.669 18.504 ;
     RECT  62.201 89.52 63.097 89.832 ;
     RECT  62.309 19.632 63.637 48.504 ;
     RECT  62.453 49.824 63.637 88.488 ;
     RECT  62.669 2.832 64.069 18.504 ;
     RECT  63.637 19.632 64.069 88.488 ;
     RECT  64.069 2.256 64.508 88.488 ;
     RECT  63.097 89.52 64.508 90.072 ;
     RECT  64.508 2.148 64.612 90.732 ;
     RECT  64.612 2.256 64.804 90.462 ;
     RECT  64.789 0.576 64.873 0.6 ;
     RECT  64.804 2.256 64.937 90.024 ;
     RECT  64.937 2.496 65.153 90.024 ;
     RECT  65.153 2.592 65.189 90.024 ;
     RECT  65.189 2.592 65.261 60.936 ;
     RECT  65.189 61.968 65.621 88.872 ;
     RECT  65.261 2.592 65.765 33.816 ;
     RECT  65.261 34.944 65.873 60.936 ;
     RECT  65.873 34.944 65.901 44.088 ;
     RECT  65.621 62.16 65.945 88.872 ;
     RECT  65.901 39.504 66.076 44.088 ;
     RECT  65.765 2.592 66.161 18.744 ;
     RECT  65.189 90 66.193 90.024 ;
     RECT  65.765 19.776 66.421 33.816 ;
     RECT  65.901 34.944 66.421 38.52 ;
     RECT  66.161 2.592 66.625 18.264 ;
     RECT  66.421 19.776 67.021 38.52 ;
     RECT  66.076 39.504 67.021 43.848 ;
     RECT  65.945 62.16 67.165 88.776 ;
     RECT  66.625 2.496 67.208 18.264 ;
     RECT  67.021 19.776 67.208 43.848 ;
     RECT  65.873 45.168 67.208 60.936 ;
     RECT  67.165 62.16 67.208 88.968 ;
     RECT  66.193 90 67.208 90.36 ;
     RECT  67.208 2.148 67.312 90.732 ;
     RECT  67.312 2.418 67.504 90.462 ;
     RECT  67.504 45.024 67.565 90.36 ;
     RECT  67.504 11.952 67.601 43.848 ;
     RECT  67.565 45.024 67.715 86.04 ;
     RECT  67.565 87.072 67.811 90.36 ;
     RECT  67.715 45.024 67.961 62.856 ;
     RECT  67.504 2.418 68.461 10.632 ;
     RECT  67.601 30.864 68.537 43.848 ;
     RECT  67.811 87.072 68.573 89.736 ;
     RECT  67.715 63.84 68.605 86.04 ;
     RECT  68.605 63.84 68.677 86.088 ;
     RECT  68.573 87.072 68.677 88.872 ;
     RECT  68.537 35.184 68.713 43.848 ;
     RECT  67.961 45.024 68.713 57.672 ;
     RECT  68.677 63.84 68.861 88.872 ;
     RECT  68.461 2.352 68.893 10.632 ;
     RECT  67.601 11.952 68.893 29.88 ;
     RECT  68.713 35.184 69.109 57.672 ;
     RECT  67.961 58.656 69.109 62.856 ;
     RECT  69.109 35.184 69.397 62.856 ;
     RECT  68.861 63.84 69.397 86.088 ;
     RECT  68.893 2.352 69.541 29.88 ;
     RECT  68.537 30.864 69.541 34.104 ;
     RECT  69.541 2.352 69.613 34.104 ;
     RECT  69.613 2.352 69.908 34.152 ;
     RECT  69.397 35.184 69.908 86.088 ;
     RECT  68.861 87.072 69.908 88.872 ;
     RECT  69.908 2.148 70.012 90.732 ;
     RECT  70.012 2.352 70.204 90.462 ;
     RECT  70.204 87.072 70.355 88.392 ;
     RECT  70.204 3.408 70.373 83.784 ;
     RECT  70.373 3.408 70.733 22.584 ;
     RECT  70.204 2.352 70.769 2.376 ;
     RECT  70.733 3.648 70.841 22.584 ;
     RECT  70.204 84.768 71.221 86.04 ;
     RECT  70.355 87.072 71.221 88.2 ;
     RECT  71.221 84.768 71.413 88.2 ;
     RECT  70.373 23.616 71.525 83.784 ;
     RECT  71.413 84.768 71.525 88.968 ;
     RECT  70.841 3.744 71.557 22.584 ;
     RECT  71.525 23.616 71.557 44.472 ;
     RECT  71.525 45.696 71.665 83.784 ;
     RECT  71.525 84.768 71.665 86.76 ;
     RECT  71.629 2.544 72.608 2.568 ;
     RECT  71.557 3.744 72.608 44.472 ;
     RECT  71.665 45.696 72.608 86.76 ;
     RECT  71.525 87.888 72.608 88.968 ;
     RECT  72.608 2.148 72.712 90.732 ;
     RECT  72.712 2.418 72.904 90.462 ;
     RECT  72.904 5.04 72.929 44.472 ;
     RECT  72.904 45.696 72.965 86.76 ;
     RECT  72.904 88.128 72.965 89.016 ;
     RECT  72.929 5.04 73.037 44.376 ;
     RECT  73.037 12.24 73.043 44.376 ;
     RECT  73.037 5.04 73.145 6.792 ;
     RECT  73.037 7.92 73.145 11.256 ;
     RECT  72.965 45.696 73.145 55.176 ;
     RECT  73.043 28.512 73.181 44.376 ;
     RECT  73.181 35.76 73.217 44.376 ;
     RECT  73.145 7.92 73.253 11.016 ;
     RECT  73.217 35.76 73.253 40.584 ;
     RECT  72.965 56.256 73.253 86.76 ;
     RECT  73.253 36.288 73.289 40.584 ;
     RECT  73.145 45.696 73.289 50.952 ;
     RECT  73.253 56.256 73.289 56.616 ;
     RECT  73.289 46.848 73.325 50.952 ;
     RECT  73.253 7.92 73.397 10.872 ;
     RECT  73.043 12.24 73.397 27.528 ;
     RECT  73.289 45.696 73.397 45.768 ;
     RECT  73.253 57.6 73.397 86.76 ;
     RECT  73.397 18.72 73.433 24.744 ;
     RECT  73.145 52.464 73.433 55.176 ;
     RECT  73.181 28.512 73.469 34.392 ;
     RECT  73.145 5.232 73.505 6.792 ;
     RECT  73.397 7.92 73.505 10.2 ;
     RECT  73.289 36.288 73.505 38.136 ;
     RECT  72.965 88.272 73.523 89.016 ;
     RECT  73.433 18.72 73.541 23.688 ;
     RECT  73.217 41.712 73.541 44.376 ;
     RECT  73.397 12.24 73.577 17.496 ;
     RECT  73.541 23.04 73.577 23.688 ;
     RECT  73.505 7.92 73.613 9.048 ;
     RECT  73.433 24.72 73.613 24.744 ;
     RECT  73.469 28.8 73.613 34.392 ;
     RECT  73.433 52.464 73.613 53.016 ;
     RECT  73.613 30.576 73.649 34.392 ;
     RECT  73.397 58.704 73.649 86.76 ;
     RECT  73.505 10.176 73.685 10.2 ;
     RECT  73.577 23.616 73.685 23.688 ;
     RECT  73.685 23.616 73.757 23.64 ;
     RECT  73.433 54.432 73.757 55.176 ;
     RECT  73.649 58.704 73.763 70.68 ;
     RECT  73.541 42.192 73.793 44.376 ;
     RECT  73.763 58.704 73.793 70.632 ;
     RECT  73.325 46.848 73.829 50.664 ;
     RECT  73.793 61.728 73.829 63.816 ;
     RECT  73.577 16.512 73.901 17.496 ;
     RECT  73.829 49.824 73.901 50.664 ;
     RECT  73.397 57.6 73.901 57.72 ;
     RECT  73.793 58.704 73.901 60.072 ;
     RECT  73.577 12.24 73.937 15.24 ;
     RECT  73.829 46.848 73.937 48.84 ;
     RECT  73.649 71.664 73.937 86.76 ;
     RECT  73.541 18.72 73.973 22.008 ;
     RECT  73.973 18.72 74.009 20.664 ;
     RECT  73.937 46.848 74.009 48.792 ;
     RECT  73.901 58.704 74.009 59.88 ;
     RECT  73.505 36.624 74.045 38.136 ;
     RECT  73.289 39.216 74.045 40.584 ;
     RECT  73.757 54.432 74.117 55.128 ;
     RECT  73.397 26.928 74.153 27.528 ;
     RECT  73.649 31.872 74.153 34.392 ;
     RECT  73.901 50.592 74.153 50.664 ;
     RECT  73.613 52.464 74.153 52.536 ;
     RECT  73.937 71.76 74.153 86.76 ;
     RECT  74.045 40.56 74.185 40.584 ;
     RECT  73.289 56.448 74.189 56.616 ;
     RECT  73.505 5.232 74.225 5.256 ;
     RECT  74.009 46.848 74.225 48.456 ;
     RECT  73.793 65.328 74.225 70.632 ;
     RECT  74.153 71.76 74.225 86.616 ;
     RECT  73.613 28.8 74.261 29.592 ;
     RECT  74.045 39.216 74.261 39.24 ;
     RECT  74.225 65.328 74.261 67.176 ;
     RECT  74.009 20.64 74.297 20.664 ;
     RECT  74.045 36.624 74.333 37.944 ;
     RECT  74.185 40.56 74.333 41.16 ;
     RECT  73.397 45.696 74.653 45.72 ;
     RECT  73.829 61.728 74.869 62.76 ;
     RECT  73.937 13.104 74.905 15.24 ;
     RECT  74.653 45.696 74.905 45.816 ;
     RECT  73.505 6.768 75.157 6.792 ;
     RECT  73.613 7.92 75.157 7.944 ;
     RECT  74.333 37.92 75.157 37.944 ;
     RECT  73.793 42.576 75.157 44.376 ;
     RECT  74.153 50.64 75.157 50.664 ;
     RECT  74.473 11.904 75.229 11.928 ;
     RECT  74.905 13.104 75.229 15.288 ;
     RECT  73.973 21.696 75.229 22.008 ;
     RECT  74.153 31.872 75.229 33.912 ;
     RECT  74.653 35.424 75.229 35.448 ;
     RECT  74.333 36.624 75.229 36.648 ;
     RECT  75.157 42.528 75.229 44.376 ;
     RECT  74.905 45.504 75.229 45.816 ;
     RECT  74.225 46.848 75.229 48.408 ;
     RECT  75.157 50.304 75.229 50.664 ;
     RECT  73.901 57.696 75.229 57.72 ;
     RECT  74.009 58.704 75.229 58.728 ;
     RECT  74.869 61.728 75.229 62.808 ;
     RECT  74.261 67.104 75.229 67.176 ;
     RECT  75.229 20.88 75.265 22.008 ;
     RECT  75.157 6.768 75.308 7.944 ;
     RECT  73.613 9.024 75.308 9.048 ;
     RECT  75.229 11.904 75.308 15.528 ;
     RECT  73.901 16.512 75.308 17.064 ;
     RECT  74.009 18.72 75.308 19.32 ;
     RECT  75.265 20.88 75.308 22.056 ;
     RECT  74.905 23.04 75.308 23.064 ;
     RECT  74.153 26.928 75.308 27.096 ;
     RECT  75.229 29.232 75.308 29.256 ;
     RECT  73.649 30.576 75.308 30.6 ;
     RECT  75.229 31.68 75.308 33.912 ;
     RECT  75.229 35.424 75.308 36.648 ;
     RECT  75.157 37.92 75.308 38.232 ;
     RECT  74.333 41.136 75.308 41.16 ;
     RECT  75.229 42.528 75.308 45.816 ;
     RECT  75.229 46.848 75.308 48.696 ;
     RECT  75.229 50.304 75.308 50.952 ;
     RECT  74.153 52.512 75.308 52.536 ;
     RECT  74.117 54.48 75.308 55.128 ;
     RECT  74.473 56.64 75.308 56.664 ;
     RECT  75.229 57.648 75.308 57.72 ;
     RECT  75.229 58.704 75.308 59.304 ;
     RECT  75.229 61.728 75.308 63.384 ;
     RECT  74.261 65.52 75.308 65.544 ;
     RECT  75.229 66.768 75.308 67.176 ;
     RECT  74.225 68.16 75.308 70.632 ;
     RECT  74.225 71.808 75.308 86.616 ;
     RECT  73.523 88.272 75.308 88.344 ;
     RECT  75.308 2.148 75.412 90.732 ;
     RECT  75.412 2.418 75.604 90.462 ;
     RECT  75.604 4.416 76.957 88.008 ;
     RECT  76.957 4.416 76.993 88.2 ;
     RECT  76.993 4.416 77.58 88.536 ;
    LAYER M5 ;
     RECT  12.96 0.133 12.984 2.137 ;
     RECT  2.4 2.137 2.52 2.151 ;
     RECT  5.1 2.137 5.22 2.151 ;
     RECT  7.8 2.137 7.92 2.151 ;
     RECT  10.5 2.137 10.62 2.151 ;
     RECT  12.96 2.137 13.32 2.151 ;
     RECT  15.9 2.137 16.02 2.151 ;
     RECT  18.6 2.137 18.72 2.151 ;
     RECT  21.3 2.137 21.42 2.151 ;
     RECT  24 2.137 24.12 2.151 ;
     RECT  26.7 2.137 26.82 2.151 ;
     RECT  32.1 2.137 32.22 2.151 ;
     RECT  34.8 2.137 34.92 2.151 ;
     RECT  37.5 2.137 37.62 2.151 ;
     RECT  40.2 2.137 40.32 2.151 ;
     RECT  42.9 2.137 43.02 2.151 ;
     RECT  45.6 2.137 45.72 2.151 ;
     RECT  48.3 2.137 48.42 2.151 ;
     RECT  51 2.137 51.12 2.151 ;
     RECT  53.7 2.137 53.82 2.151 ;
     RECT  56.4 2.137 56.52 2.151 ;
     RECT  59.1 2.137 59.22 2.151 ;
     RECT  61.8 2.137 61.92 2.151 ;
     RECT  64.5 2.137 64.62 2.151 ;
     RECT  67.2 2.137 67.32 2.151 ;
     RECT  69.9 2.137 70.02 2.151 ;
     RECT  72.6 2.137 72.72 2.151 ;
     RECT  75.3 2.137 75.42 2.151 ;
     RECT  18.6 2.151 18.912 2.197 ;
     RECT  12.96 2.151 13.512 2.245 ;
     RECT  24 2.151 24.312 2.245 ;
     RECT  26.7 2.151 27.012 2.341 ;
     RECT  29.4 2.137 30.264 2.485 ;
     RECT  72.6 2.151 72.912 2.533 ;
     RECT  10.5 2.151 10.812 2.677 ;
     RECT  12.96 2.245 14.136 2.677 ;
     RECT  48.3 2.151 48.612 2.677 ;
     RECT  67.2 2.151 67.512 2.677 ;
     RECT  64.5 2.151 64.812 2.773 ;
     RECT  7.8 2.151 8.112 2.821 ;
     RECT  12.96 2.677 14.904 2.821 ;
     RECT  15.9 2.151 16.212 2.821 ;
     RECT  45.6 2.151 45.912 2.821 ;
     RECT  56.4 2.151 56.712 2.821 ;
     RECT  10.5 2.677 11.112 2.917 ;
     RECT  24 2.245 24.456 3.011 ;
     RECT  56.208 2.821 56.712 3.011 ;
     RECT  37.5 2.151 37.812 3.301 ;
     RECT  38.88 2.197 38.904 3.301 ;
     RECT  2.4 2.151 2.712 3.397 ;
     RECT  44.832 2.821 46.536 3.397 ;
     RECT  41.616 2.725 41.64 3.443 ;
     RECT  44.832 3.397 46.728 3.443 ;
     RECT  48.3 2.677 48.744 3.443 ;
     RECT  29.4 2.485 30.888 3.539 ;
     RECT  18.24 2.197 18.912 3.589 ;
     RECT  61.8 2.151 62.112 3.733 ;
     RECT  22.8 3.637 22.824 3.829 ;
     RECT  24 3.011 24.312 3.829 ;
     RECT  7.8 2.821 9.096 3.877 ;
     RECT  66.624 2.677 67.512 3.925 ;
     RECT  66.144 3.925 67.512 3.971 ;
     RECT  5.1 2.151 5.412 3.973 ;
     RECT  12.96 2.821 16.212 3.973 ;
     RECT  26.7 2.341 27.816 3.973 ;
     RECT  21.3 2.151 21.612 4.069 ;
     RECT  12.432 3.973 16.212 4.115 ;
     RECT  10.5 2.917 11.16 4.163 ;
     RECT  53.7 2.151 54.012 4.165 ;
     RECT  59.1 2.151 59.412 4.165 ;
     RECT  37.5 3.301 38.904 4.261 ;
     RECT  40.2 2.151 40.512 4.261 ;
     RECT  10.5 4.163 11.112 4.307 ;
     RECT  42.9 2.151 43.212 4.357 ;
     RECT  34.8 2.151 35.112 4.405 ;
     RECT  48.3 3.443 48.612 4.405 ;
     RECT  7.44 3.877 9.096 4.451 ;
     RECT  15.408 4.115 16.212 4.453 ;
     RECT  22.8 3.829 24.312 4.499 ;
     RECT  53.7 4.165 54.264 4.499 ;
     RECT  59.1 4.165 60.024 4.499 ;
     RECT  56.4 3.011 56.712 4.501 ;
     RECT  59.1 4.499 59.832 4.501 ;
     RECT  69.9 2.151 70.212 4.501 ;
     RECT  42.9 4.357 44.136 4.549 ;
     RECT  45.6 3.443 46.728 4.549 ;
     RECT  53.7 4.499 54.168 4.549 ;
     RECT  15.408 4.453 17.064 4.595 ;
     RECT  71.808 2.533 72.912 4.595 ;
     RECT  2.4 3.397 3.432 4.691 ;
     RECT  18.24 3.589 19.08 4.691 ;
     RECT  42.576 4.549 46.728 4.691 ;
     RECT  7.44 4.451 8.952 4.979 ;
     RECT  10.5 4.307 11.064 5.075 ;
     RECT  12.432 4.115 14.136 5.123 ;
     RECT  37.5 4.261 40.512 5.123 ;
     RECT  37.5 5.123 38.568 5.171 ;
     RECT  66.144 3.971 66.168 5.171 ;
     RECT  15.9 4.595 17.064 5.267 ;
     RECT  26.7 3.973 27.96 5.363 ;
     RECT  18.6 4.691 19.08 5.365 ;
     RECT  42.576 4.691 46.536 5.459 ;
     RECT  29.4 3.539 30.264 5.461 ;
     RECT  58.656 4.501 59.832 5.461 ;
     RECT  58.656 5.461 59.928 5.507 ;
     RECT  23.28 4.499 24.312 5.605 ;
     RECT  69.312 4.501 70.212 5.605 ;
     RECT  52.896 4.549 54.168 5.653 ;
     RECT  61.584 3.733 62.112 5.701 ;
     RECT  17.568 5.461 17.592 5.747 ;
     RECT  23.28 5.605 25.128 5.749 ;
     RECT  12.96 5.123 14.136 5.797 ;
     RECT  59.1 5.507 59.928 5.893 ;
     RECT  61.008 5.701 62.112 5.893 ;
     RECT  69.312 5.605 70.584 5.893 ;
     RECT  34.08 4.405 35.112 5.989 ;
     RECT  37.5 5.171 37.992 5.989 ;
     RECT  67.2 3.971 67.512 5.989 ;
     RECT  22.8 5.749 25.128 6.083 ;
     RECT  37.392 5.989 37.992 6.083 ;
     RECT  51 2.151 51.312 6.085 ;
     RECT  42.9 5.459 46.536 6.131 ;
     RECT  48.3 4.405 49.416 6.179 ;
     RECT  10.5 5.075 10.92 6.181 ;
     RECT  51 6.085 51.624 6.229 ;
     RECT  69.312 5.893 71.4 6.229 ;
     RECT  72.6 4.595 72.912 6.229 ;
     RECT  52.896 5.653 55.032 6.275 ;
     RECT  53.7 6.275 55.032 6.277 ;
     RECT  12.96 5.797 14.52 6.323 ;
     RECT  59.1 5.893 62.112 6.323 ;
     RECT  59.1 6.323 60.744 6.517 ;
     RECT  56.4 4.501 57.288 6.563 ;
     RECT  12.96 6.323 14.136 6.659 ;
     RECT  18.6 5.365 19.8 6.755 ;
     RECT  15.9 5.267 16.344 6.805 ;
     RECT  29.4 5.461 30.36 6.805 ;
     RECT  50.784 6.229 51.624 6.805 ;
     RECT  37.392 6.083 37.812 6.851 ;
     RECT  67.2 5.989 67.608 6.851 ;
     RECT  4.512 3.973 5.412 6.853 ;
     RECT  28.944 6.805 30.36 6.899 ;
     RECT  15.9 6.805 16.824 6.949 ;
     RECT  18.6 6.755 19.08 6.949 ;
     RECT  21.168 4.069 21.612 6.949 ;
     RECT  23.136 6.083 25.128 6.995 ;
     RECT  53.7 6.277 55.416 7.043 ;
     RECT  15.9 6.949 19.08 7.091 ;
     RECT  58.464 6.517 60.744 7.139 ;
     RECT  15.9 7.091 18.912 7.379 ;
     RECT  37.5 6.851 37.812 7.381 ;
     RECT  7.8 4.979 8.952 7.429 ;
     RECT  33.984 5.989 35.112 7.429 ;
     RECT  3.936 6.853 5.412 7.475 ;
     RECT  14.832 7.429 14.856 7.571 ;
     RECT  28.944 6.899 30.264 7.811 ;
     RECT  21.168 6.949 22.104 7.907 ;
     RECT  10.5 6.181 11.4 7.955 ;
     RECT  15.9 7.379 17.112 7.955 ;
     RECT  26.7 5.363 27.384 7.955 ;
     RECT  33.984 7.429 35.544 7.955 ;
     RECT  50.064 6.805 51.624 7.955 ;
     RECT  32.1 2.151 32.412 7.957 ;
     RECT  37.5 7.381 38.568 8.003 ;
     RECT  23.136 6.995 24.312 8.195 ;
     RECT  12.96 6.659 13.512 8.197 ;
     RECT  10.5 7.955 10.92 8.243 ;
     RECT  50.064 7.955 51.312 8.243 ;
     RECT  42.9 6.131 44.232 8.389 ;
     RECT  42.9 8.389 44.328 8.437 ;
     RECT  58.464 7.139 60.024 8.437 ;
     RECT  18.24 7.379 18.912 8.483 ;
     RECT  41.568 7.909 41.592 8.483 ;
     RECT  42.9 8.437 44.424 8.483 ;
     RECT  4.752 7.475 5.412 8.533 ;
     RECT  63.504 8.149 63.528 8.675 ;
     RECT  31.968 7.957 32.412 8.821 ;
     RECT  33.984 7.955 35.112 8.821 ;
     RECT  37.5 8.003 37.812 8.821 ;
     RECT  31.968 8.821 35.112 8.867 ;
     RECT  32.1 8.867 35.112 8.963 ;
     RECT  15.9 7.955 16.212 8.965 ;
     RECT  58.032 8.437 60.024 9.059 ;
     RECT  44.304 8.483 44.424 9.155 ;
     RECT  4.752 8.533 6.312 9.541 ;
     RECT  10.5 8.243 10.812 9.541 ;
     RECT  36.72 8.821 37.812 9.731 ;
     RECT  64.5 2.773 64.968 9.827 ;
     RECT  4.512 9.541 6.312 10.069 ;
     RECT  29.04 7.811 30.264 10.117 ;
     RECT  56.4 6.563 56.712 10.165 ;
     RECT  21.168 7.907 21.612 10.213 ;
     RECT  40.2 5.123 40.512 10.213 ;
     RECT  3.984 10.069 6.312 10.259 ;
     RECT  53.7 7.043 55.032 10.643 ;
     RECT  61.8 6.323 62.112 10.693 ;
     RECT  44.4 9.155 44.424 10.741 ;
     RECT  45.6 6.131 46.536 10.741 ;
     RECT  48.3 6.179 48.612 10.741 ;
     RECT  20.496 10.213 21.612 10.789 ;
     RECT  23.328 8.195 24.312 10.789 ;
     RECT  15.408 8.965 16.212 10.883 ;
     RECT  56.4 10.165 56.904 10.883 ;
     RECT  44.4 10.741 46.536 10.931 ;
     RECT  3.984 10.259 5.412 10.979 ;
     RECT  42.9 8.483 43.212 10.981 ;
     RECT  44.4 10.931 46.056 10.981 ;
     RECT  61.8 10.693 62.424 10.981 ;
     RECT  20.496 10.789 24.312 11.171 ;
     RECT  18.6 8.483 18.912 11.221 ;
     RECT  21.3 11.171 24.312 11.267 ;
     RECT  48.3 10.741 48.744 11.267 ;
     RECT  64.5 9.827 64.92 11.317 ;
     RECT  39.84 10.213 40.512 11.365 ;
     RECT  55.008 10.643 55.032 11.365 ;
     RECT  61.8 10.981 63.144 11.365 ;
     RECT  12.96 8.197 14.232 11.411 ;
     RECT  52.416 10.597 52.44 11.461 ;
     RECT  28.896 10.117 30.264 11.653 ;
     RECT  37.5 9.731 37.812 11.701 ;
     RECT  10.5 9.541 11.592 11.749 ;
     RECT  12.96 11.411 13.512 11.749 ;
     RECT  33.984 8.963 35.112 11.749 ;
     RECT  10.5 11.749 13.512 11.795 ;
     RECT  55.008 11.365 55.176 11.795 ;
     RECT  39.84 11.365 41.16 11.843 ;
     RECT  32.1 8.963 32.52 11.845 ;
     RECT  7.8 7.429 9.096 11.941 ;
     RECT  50.736 8.243 51.312 11.941 ;
     RECT  42.9 10.981 46.056 12.131 ;
     RECT  52.416 11.461 52.488 12.227 ;
     RECT  56.4 10.883 56.712 12.229 ;
     RECT  58.032 9.059 59.64 12.229 ;
     RECT  56.4 12.229 59.64 12.275 ;
     RECT  60.816 11.365 63.144 12.371 ;
     RECT  12.528 11.795 13.512 12.419 ;
     RECT  32.1 11.845 32.76 12.469 ;
     RECT  31.872 12.469 32.76 12.515 ;
     RECT  33.984 11.749 35.304 12.515 ;
     RECT  37.5 11.701 38.184 12.515 ;
     RECT  56.4 12.275 57.624 12.515 ;
     RECT  21.3 11.267 22.824 12.563 ;
     RECT  40.2 11.843 41.16 12.563 ;
     RECT  28.512 11.653 30.264 12.659 ;
     RECT  26.7 7.955 27.012 12.853 ;
     RECT  7.392 11.941 9.096 12.899 ;
     RECT  58.704 12.275 59.64 12.995 ;
     RECT  60.816 12.371 63.048 13.043 ;
     RECT  33.984 12.515 35.112 13.045 ;
     RECT  64.5 11.317 65.016 13.045 ;
     RECT  67.2 6.851 67.512 13.045 ;
     RECT  7.8 12.899 9.096 13.093 ;
     RECT  44.4 12.131 46.056 13.139 ;
     RECT  14.832 12.949 14.856 13.235 ;
     RECT  7.8 13.093 9.144 13.283 ;
     RECT  24 11.267 24.312 13.285 ;
     RECT  61.68 13.043 63.048 13.331 ;
     RECT  58.752 12.995 59.64 13.381 ;
     RECT  53.7 10.643 54.012 13.525 ;
     RECT  55.008 11.795 55.032 13.525 ;
     RECT  53.7 13.525 55.032 13.571 ;
     RECT  44.736 13.139 46.056 13.573 ;
     RECT  61.8 13.331 63.048 13.573 ;
     RECT  10.5 11.795 10.812 13.621 ;
     RECT  33.648 13.045 35.112 13.621 ;
     RECT  22.752 12.563 22.824 13.715 ;
     RECT  64.5 13.045 65.832 13.715 ;
     RECT  31.872 12.515 32.412 13.813 ;
     RECT  40.2 12.563 40.512 13.957 ;
     RECT  15.9 10.883 16.212 14.053 ;
     RECT  24 13.285 25.128 14.053 ;
     RECT  4.752 10.979 5.412 14.101 ;
     RECT  42.9 12.131 43.32 14.101 ;
     RECT  52.464 12.227 52.488 14.149 ;
     RECT  53.7 13.571 54.12 14.149 ;
     RECT  69.312 6.229 72.912 14.291 ;
     RECT  33.648 13.621 35.928 14.339 ;
     RECT  67.104 13.045 67.512 14.339 ;
     RECT  22.752 13.715 22.776 14.387 ;
     RECT  28.896 12.659 30.264 14.485 ;
     RECT  34.224 14.339 35.928 14.531 ;
     RECT  52.464 14.149 54.12 14.675 ;
     RECT  15.9 14.053 16.68 14.773 ;
     RECT  48.3 11.267 48.612 14.773 ;
     RECT  26.7 12.853 27.384 14.867 ;
     RECT  58.752 13.381 59.88 14.867 ;
     RECT  40.2 13.957 41.256 14.917 ;
     RECT  56.4 12.515 56.712 14.917 ;
     RECT  40.2 14.917 41.544 14.963 ;
     RECT  24 14.053 25.464 15.107 ;
     RECT  44.736 13.573 46.152 15.251 ;
     RECT  34.704 14.531 35.928 15.349 ;
     RECT  69.6 14.291 70.488 15.443 ;
     RECT  7.8 13.283 9.096 15.493 ;
     RECT  4.08 14.101 5.412 15.539 ;
     RECT  45.6 15.251 46.152 15.589 ;
     RECT  47.328 14.773 48.612 15.589 ;
     RECT  64.5 13.715 65.496 15.589 ;
     RECT  34.704 15.349 35.976 15.637 ;
     RECT  12.96 12.419 13.512 15.733 ;
     RECT  14.688 13.813 14.712 15.733 ;
     RECT  31.344 13.813 32.412 15.779 ;
     RECT  37.5 12.515 37.812 15.781 ;
     RECT  69.6 15.443 70.212 15.829 ;
     RECT  7.8 15.493 9.144 15.875 ;
     RECT  18.6 11.221 19.32 15.973 ;
     RECT  7.8 15.875 9.096 16.019 ;
     RECT  12.96 15.733 14.712 16.019 ;
     RECT  42.768 14.101 43.32 16.019 ;
     RECT  45.6 15.589 48.612 16.019 ;
     RECT  50.688 11.941 51.312 16.019 ;
     RECT  58.752 14.867 59.412 16.021 ;
     RECT  64.5 15.589 65.736 16.021 ;
     RECT  61.8 13.573 63.336 16.117 ;
     RECT  21.3 12.563 21.612 16.165 ;
     RECT  24 15.107 25.272 16.211 ;
     RECT  34.272 15.637 35.976 16.261 ;
     RECT  37.5 15.781 37.944 16.309 ;
     RECT  34.224 16.261 35.976 16.355 ;
     RECT  61.584 16.117 63.336 16.499 ;
     RECT  42.9 16.019 43.32 16.501 ;
     RECT  41.52 14.963 41.544 16.547 ;
     RECT  52.944 14.675 54.12 16.549 ;
     RECT  71.856 14.291 72.912 16.595 ;
     RECT  18.6 15.973 19.944 16.789 ;
     RECT  64.368 16.021 65.736 16.835 ;
     RECT  69.552 15.829 70.212 16.835 ;
     RECT  64.368 16.835 65.064 16.979 ;
     RECT  52.512 16.549 54.12 17.029 ;
     RECT  56.304 14.917 56.712 17.029 ;
     RECT  28.512 14.485 30.264 17.075 ;
     RECT  37.5 16.309 38.232 17.077 ;
     RECT  61.584 16.499 63.048 17.077 ;
     RECT  15.9 14.773 16.92 17.123 ;
     RECT  34.224 16.355 35.112 17.171 ;
     RECT  7.8 16.019 8.112 17.173 ;
     RECT  52.464 17.029 54.744 17.219 ;
     RECT  60.72 17.077 63.048 17.219 ;
     RECT  36.768 17.077 38.232 17.605 ;
     RECT  18.24 16.789 19.944 17.651 ;
     RECT  7.8 17.173 8.232 17.701 ;
     RECT  52.464 17.219 52.536 17.747 ;
     RECT  56.064 17.029 56.712 17.747 ;
     RECT  42.9 16.501 44.136 17.795 ;
     RECT  45.6 16.019 46.872 17.845 ;
     RECT  36.768 17.605 38.808 17.891 ;
     RECT  61.584 17.219 63.048 17.939 ;
     RECT  6.864 17.701 8.232 17.987 ;
     RECT  26.7 14.867 27.012 18.037 ;
     RECT  12.96 16.019 14.424 18.133 ;
     RECT  48.3 16.019 48.612 18.133 ;
     RECT  49.584 14.773 49.608 18.133 ;
     RECT  64.5 16.979 65.064 18.181 ;
     RECT  21.3 16.165 22.44 18.227 ;
     RECT  53.7 17.219 54.744 18.227 ;
     RECT  52.512 17.747 52.536 18.419 ;
     RECT  48.3 18.133 49.608 18.469 ;
     RECT  58.704 16.021 59.412 18.469 ;
     RECT  34.272 17.171 35.112 18.565 ;
     RECT  58.704 18.469 60.36 18.565 ;
     RECT  64.5 18.181 65.736 18.709 ;
     RECT  2.4 4.691 2.712 18.757 ;
     RECT  45.6 17.845 47.016 18.805 ;
     RECT  7.8 17.987 8.232 18.851 ;
     RECT  26.7 18.037 27.624 18.851 ;
     RECT  57.936 18.565 60.36 18.851 ;
     RECT  31.728 15.779 32.412 18.949 ;
     RECT  33.408 18.565 35.112 18.949 ;
     RECT  28.896 17.075 30.264 19.045 ;
     RECT  45.6 18.805 47.112 19.045 ;
     RECT  48.3 18.469 49.896 19.237 ;
     RECT  51 16.019 51.312 19.237 ;
     RECT  56.304 17.747 56.712 19.333 ;
     RECT  57.936 18.851 60.312 19.333 ;
     RECT  31.728 18.949 35.112 19.379 ;
     RECT  18.24 17.651 19.32 19.381 ;
     RECT  21.3 18.227 21.612 19.381 ;
     RECT  48.3 19.237 51.312 19.427 ;
     RECT  49.872 19.427 51.312 19.475 ;
     RECT  64.368 18.709 65.736 19.667 ;
     RECT  53.7 18.227 54.408 19.669 ;
     RECT  12.864 18.133 14.424 19.811 ;
     RECT  24 16.211 25.128 19.909 ;
     RECT  4.944 15.539 5.412 20.195 ;
     RECT  45.6 19.045 47.256 20.197 ;
     RECT  2.4 18.757 3.288 20.291 ;
     RECT  7.8 18.851 8.112 20.293 ;
     RECT  37.5 17.891 38.808 20.339 ;
     RECT  34.272 19.379 35.112 20.485 ;
     RECT  10.32 13.621 10.812 20.579 ;
     RECT  20.64 19.381 21.612 20.579 ;
     RECT  53.472 19.669 54.408 20.675 ;
     RECT  5.1 20.195 5.412 20.725 ;
     RECT  50.784 19.475 51.312 20.965 ;
     RECT  5.1 20.725 5.544 21.059 ;
     RECT  34.176 20.485 35.112 21.155 ;
     RECT  61.8 17.939 63.048 21.155 ;
     RECT  10.368 20.579 10.812 21.205 ;
     RECT  31.728 19.379 32.664 21.205 ;
     RECT  7.8 20.293 8.232 21.301 ;
     RECT  17.664 19.381 19.32 21.349 ;
     RECT  17.568 21.349 19.32 21.395 ;
     RECT  21.168 20.579 21.612 21.397 ;
     RECT  37.5 20.339 38.232 21.443 ;
     RECT  21.168 21.397 21.72 21.541 ;
     RECT  10.368 21.205 10.92 21.587 ;
     RECT  64.5 19.667 65.736 21.589 ;
     RECT  64.5 21.589 66.168 21.635 ;
     RECT  6.864 21.301 8.232 21.637 ;
     RECT  18.6 21.395 19.32 21.637 ;
     RECT  26.7 18.851 27.012 21.637 ;
     RECT  44.976 20.197 47.304 21.683 ;
     RECT  53.7 20.675 54.408 21.683 ;
     RECT  56.304 19.333 60.312 21.683 ;
     RECT  34.272 21.155 35.112 21.779 ;
     RECT  24 19.909 25.56 21.971 ;
     RECT  15.9 17.123 16.212 21.973 ;
     RECT  34.8 21.779 35.112 22.069 ;
     RECT  67.2 14.339 67.512 22.069 ;
     RECT  10.368 21.587 10.812 22.165 ;
     RECT  42.9 17.795 43.32 22.165 ;
     RECT  72.48 16.595 72.912 22.165 ;
     RECT  37.5 21.443 38.04 22.261 ;
     RECT  9.792 22.165 10.812 22.403 ;
     RECT  64.5 21.635 64.92 22.499 ;
     RECT  5.1 21.059 5.412 22.501 ;
     RECT  6.816 21.637 8.232 22.501 ;
     RECT  42.9 22.165 43.944 22.501 ;
     RECT  5.1 22.501 8.232 22.547 ;
     RECT  17.568 21.395 17.592 22.547 ;
     RECT  67.2 22.069 68.424 22.741 ;
     RECT  69.9 16.835 70.212 22.741 ;
     RECT  34.8 22.069 35.88 22.787 ;
     RECT  57.936 21.683 59.412 22.835 ;
     RECT  72.336 22.165 72.912 22.835 ;
     RECT  42.768 22.501 43.944 22.981 ;
     RECT  12.96 19.811 13.512 23.173 ;
     RECT  18.6 21.637 19.992 23.269 ;
     RECT  21.168 21.541 22.536 23.269 ;
     RECT  18.6 23.269 22.536 23.315 ;
     RECT  18.6 23.315 19.32 23.363 ;
     RECT  66.144 21.635 66.168 23.363 ;
     RECT  49.824 20.965 51.312 23.507 ;
     RECT  5.1 22.547 6.312 23.555 ;
     RECT  12.624 23.173 13.512 23.701 ;
     RECT  48.3 19.427 48.612 23.701 ;
     RECT  49.824 23.507 49.848 23.701 ;
     RECT  15.456 21.973 16.212 23.747 ;
     RECT  63.168 22.741 63.192 23.795 ;
     RECT  67.2 22.741 70.212 23.795 ;
     RECT  48.3 23.701 49.848 23.843 ;
     RECT  24 21.971 25.128 23.845 ;
     RECT  48.3 23.843 49.512 23.845 ;
     RECT  3.984 22.741 4.008 23.891 ;
     RECT  44.976 21.683 46.872 23.891 ;
     RECT  28.896 19.045 30.36 23.939 ;
     RECT  20.88 23.315 22.536 24.083 ;
     RECT  10.368 22.403 10.812 24.131 ;
     RECT  37.392 22.261 38.04 24.131 ;
     RECT  42.144 22.981 43.944 24.131 ;
     RECT  20.88 24.083 21.72 24.371 ;
     RECT  34.8 22.787 35.208 24.419 ;
     RECT  26.7 21.637 27.72 24.469 ;
     RECT  28.896 23.939 30.264 24.469 ;
     RECT  37.392 24.131 37.944 24.469 ;
     RECT  40.2 14.963 40.512 24.469 ;
     RECT  24 23.845 25.176 24.515 ;
     RECT  58.656 22.835 59.412 24.563 ;
     RECT  42.144 24.131 43.32 24.707 ;
     RECT  31.728 21.205 32.856 24.757 ;
     RECT  45.6 23.891 46.872 25.045 ;
     RECT  69.9 23.795 70.212 25.045 ;
     RECT  53.7 21.683 54.168 25.093 ;
     RECT  64.5 22.499 64.812 25.093 ;
     RECT  67.2 23.795 67.992 25.235 ;
     RECT  61.8 21.155 62.112 25.285 ;
     RECT  26.7 24.469 30.264 25.331 ;
     RECT  47.952 23.845 49.512 25.331 ;
     RECT  53.568 25.093 54.168 25.475 ;
     RECT  26.7 25.331 28.248 25.523 ;
     RECT  24 24.515 24.312 25.573 ;
     RECT  58.848 24.563 59.412 25.573 ;
     RECT  36.432 24.469 37.944 25.667 ;
     RECT  45.024 25.045 46.872 25.715 ;
     RECT  47.952 25.331 48.612 25.715 ;
     RECT  69.9 25.045 70.872 25.715 ;
     RECT  3.936 25.477 3.96 25.763 ;
     RECT  53.7 25.475 54.168 25.763 ;
     RECT  24 25.573 24.408 25.861 ;
     RECT  25.536 25.285 25.56 25.861 ;
     RECT  61.8 25.285 62.232 26.051 ;
     RECT  63.84 25.093 64.812 26.101 ;
     RECT  72.6 22.835 72.912 26.149 ;
     RECT  21.3 24.371 21.72 26.197 ;
     RECT  12.624 23.701 14.424 26.627 ;
     RECT  71.76 26.149 72.912 26.629 ;
     RECT  51 23.507 51.312 26.677 ;
     RECT  31.728 24.757 33.672 26.725 ;
     RECT  37.104 25.667 37.944 26.771 ;
     RECT  37.248 26.771 37.944 26.773 ;
     RECT  22.752 25.621 22.776 26.819 ;
     RECT  15.9 23.747 16.212 26.869 ;
     RECT  63.84 26.101 65.352 27.059 ;
     RECT  21.168 26.197 21.72 27.107 ;
     RECT  7.8 22.547 8.232 27.205 ;
     RECT  24 25.861 25.56 27.301 ;
     RECT  42.9 24.707 43.32 27.301 ;
     RECT  31.344 26.725 33.672 27.347 ;
     RECT  56.304 21.683 56.712 27.349 ;
     RECT  42.048 27.301 43.32 27.395 ;
     RECT  50.16 26.677 51.312 27.395 ;
     RECT  48 25.715 48.612 27.491 ;
     RECT  48.3 27.491 48.612 27.589 ;
     RECT  42.048 27.395 43.212 27.685 ;
     RECT  61.8 26.051 62.112 27.685 ;
     RECT  71.76 26.629 73.032 27.731 ;
     RECT  10.5 24.131 10.812 27.829 ;
     RECT  61.8 27.685 62.232 27.829 ;
     RECT  7.68 27.205 8.232 27.877 ;
     RECT  53.7 25.763 54.012 27.877 ;
     RECT  71.76 27.731 72.912 27.923 ;
     RECT  34.8 24.419 35.112 27.925 ;
     RECT  31.344 27.347 33.336 28.115 ;
     RECT  37.248 26.773 38.184 28.163 ;
     RECT  56.304 27.349 57.624 28.163 ;
     RECT  17.472 23.317 17.496 28.213 ;
     RECT  39.888 24.469 40.512 28.213 ;
     RECT  37.248 28.163 37.944 28.261 ;
     RECT  37.152 28.261 37.944 28.451 ;
     RECT  39.744 28.213 40.872 28.451 ;
     RECT  7.44 27.877 8.232 28.453 ;
     RECT  15.792 26.869 16.212 28.453 ;
     RECT  21.168 27.107 21.612 28.453 ;
     RECT  23.328 27.301 25.56 28.453 ;
     RECT  26.7 25.523 27.72 28.453 ;
     RECT  48.3 27.589 49.272 28.453 ;
     RECT  51 27.395 51.312 28.453 ;
     RECT  23.328 28.453 27.72 28.547 ;
     RECT  53.7 27.877 54.168 28.547 ;
     RECT  34.8 27.925 35.208 28.691 ;
     RECT  7.44 28.453 8.664 28.741 ;
     RECT  15.552 28.453 16.212 28.789 ;
     RECT  17.376 28.213 17.496 28.789 ;
     RECT  10.5 27.829 11.448 28.835 ;
     RECT  15.552 28.789 17.496 28.931 ;
     RECT  7.44 28.741 9.144 29.027 ;
     RECT  37.248 28.451 37.944 29.123 ;
     RECT  39.744 28.451 40.512 29.123 ;
     RECT  21.072 28.453 21.612 29.173 ;
     RECT  25.536 28.547 27.72 29.363 ;
     RECT  12.624 26.627 13.512 29.365 ;
     RECT  69.9 25.715 70.212 29.365 ;
     RECT  39.888 29.123 40.512 29.413 ;
     RECT  41.904 27.685 43.212 29.413 ;
     RECT  12.624 29.365 14.232 29.605 ;
     RECT  15.552 28.931 16.212 29.605 ;
     RECT  29.232 25.331 30.264 29.605 ;
     RECT  31.728 28.115 33.336 29.605 ;
     RECT  37.248 29.123 37.812 29.605 ;
     RECT  23.328 28.547 24.312 29.651 ;
     RECT  17.376 28.931 17.496 29.699 ;
     RECT  53.7 28.547 54.012 29.701 ;
     RECT  56.304 28.163 56.712 29.701 ;
     RECT  53.7 29.701 54.744 29.843 ;
     RECT  12.624 29.605 16.212 30.037 ;
     RECT  17.376 29.699 17.4 30.037 ;
     RECT  53.7 29.843 54.012 30.037 ;
     RECT  61.8 27.829 62.76 30.037 ;
     RECT  23.712 29.651 24.312 30.083 ;
     RECT  61.8 30.037 63.144 30.083 ;
     RECT  20.592 29.173 21.612 30.133 ;
     RECT  5.1 23.555 5.412 30.181 ;
     RECT  25.536 29.363 27.144 30.181 ;
     RECT  12.624 30.037 17.4 30.227 ;
     RECT  45.6 25.715 46.872 30.275 ;
     RECT  48.3 28.453 51.312 30.275 ;
     RECT  7.44 29.027 8.664 30.373 ;
     RECT  36.384 29.605 37.812 30.421 ;
     RECT  39.888 29.413 43.212 30.563 ;
     RECT  12.624 30.227 16.344 30.611 ;
     RECT  28.368 29.605 30.264 30.611 ;
     RECT  20.544 30.133 21.612 30.613 ;
     RECT  64.5 27.059 65.352 30.661 ;
     RECT  45.6 30.275 45.912 30.709 ;
     RECT  64.368 30.661 65.352 30.709 ;
     RECT  36.384 30.421 37.944 30.757 ;
     RECT  41.904 30.563 43.212 30.803 ;
     RECT  64.368 30.709 66.12 30.803 ;
     RECT  58.656 25.573 59.412 30.805 ;
     RECT  25.344 30.181 27.144 30.851 ;
     RECT  31.728 29.605 33.672 30.853 ;
     RECT  34.8 28.691 35.112 30.853 ;
     RECT  7.392 30.373 8.664 30.947 ;
     RECT  63.12 30.083 63.144 30.949 ;
     RECT  63.12 30.949 63.24 30.995 ;
     RECT  29.232 30.611 30.264 31.045 ;
     RECT  31.728 30.853 35.112 31.045 ;
     RECT  5.1 30.181 5.736 31.139 ;
     RECT  12.624 30.611 14.232 31.139 ;
     RECT  24 30.083 24.312 31.141 ;
     RECT  69.552 29.365 70.212 31.283 ;
     RECT  15.792 30.611 16.344 31.285 ;
     RECT  17.376 30.227 17.4 31.285 ;
     RECT  53.28 30.037 54.012 31.285 ;
     RECT  61.8 30.083 62.112 31.285 ;
     RECT  55.92 29.701 56.712 31.331 ;
     RECT  7.392 30.947 8.112 31.379 ;
     RECT  23.472 31.141 24.312 31.381 ;
     RECT  25.344 30.851 25.368 31.381 ;
     RECT  45.216 30.709 45.912 31.427 ;
     RECT  53.28 31.285 54.744 31.427 ;
     RECT  45.6 31.427 45.912 31.621 ;
     RECT  48.3 30.275 49.272 31.621 ;
     RECT  51 30.275 51.312 31.621 ;
     RECT  64.5 30.803 66.12 31.715 ;
     RECT  45.6 31.621 46.008 31.811 ;
     RECT  48.3 31.621 51.312 31.811 ;
     RECT  15.792 31.285 17.4 31.859 ;
     RECT  29.232 31.045 35.112 31.955 ;
     RECT  48.3 31.811 49.272 31.955 ;
     RECT  63.216 30.995 63.24 31.955 ;
     RECT  9.12 31.957 9.144 32.099 ;
     RECT  36.384 30.757 38.232 32.101 ;
     RECT  67.2 25.235 67.512 32.197 ;
     RECT  12.624 31.139 13.608 32.243 ;
     RECT  23.472 31.381 25.368 32.243 ;
     RECT  26.7 30.851 27.144 32.341 ;
     RECT  20.544 30.613 22.152 32.437 ;
     RECT  17.376 31.859 17.4 32.483 ;
     RECT  41.904 30.803 41.928 32.531 ;
     RECT  5.1 31.139 5.544 32.725 ;
     RECT  12.768 32.243 13.608 32.725 ;
     RECT  34.608 31.955 35.112 32.771 ;
     RECT  36.384 32.101 38.568 32.869 ;
     RECT  24 32.243 25.368 32.915 ;
     RECT  45.6 31.811 45.912 33.013 ;
     RECT  72.6 27.923 72.912 33.061 ;
     RECT  58.56 30.805 59.412 33.155 ;
     RECT  12.768 32.725 13.752 33.203 ;
     RECT  15.792 31.859 16.344 33.253 ;
     RECT  69.9 31.283 70.212 33.253 ;
     RECT  39.888 30.563 40.824 33.349 ;
     RECT  36.384 32.869 38.76 33.493 ;
     RECT  39.888 33.349 40.92 33.493 ;
     RECT  29.232 31.955 33.576 33.539 ;
     RECT  46.992 31.765 47.016 33.539 ;
     RECT  10.5 28.835 10.812 33.589 ;
     RECT  19.92 32.437 22.152 33.589 ;
     RECT  19.92 33.589 22.2 33.635 ;
     RECT  72.24 33.061 72.912 33.635 ;
     RECT  24 32.915 25.08 33.683 ;
     RECT  36.384 33.493 40.92 33.683 ;
     RECT  26.7 32.341 27.336 33.875 ;
     RECT  53.28 31.427 54.012 33.877 ;
     RECT  15.792 33.253 16.392 34.067 ;
     RECT  5.1 32.725 5.592 34.069 ;
     RECT  51 31.811 51.312 34.117 ;
     RECT  58.656 33.155 59.412 34.117 ;
     RECT  10.272 33.589 10.812 34.211 ;
     RECT  72.48 33.635 72.912 34.211 ;
     RECT  20.832 33.635 22.2 34.355 ;
     RECT  39.312 33.683 40.92 34.499 ;
     RECT  66.432 32.197 67.512 34.643 ;
     RECT  15.792 34.067 16.212 34.741 ;
     RECT  20.832 34.355 22.104 34.741 ;
     RECT  24 33.683 24.408 34.741 ;
     RECT  29.232 33.539 30.264 34.741 ;
     RECT  34.704 32.771 35.112 34.741 ;
     RECT  48.3 31.955 48.612 34.741 ;
     RECT  56.304 31.331 56.712 34.741 ;
     RECT  69.9 33.253 70.344 34.741 ;
     RECT  58.56 34.117 59.412 34.787 ;
     RECT  39.312 34.499 40.824 34.835 ;
     RECT  50.112 34.117 51.312 34.835 ;
     RECT  15.648 34.741 16.212 34.885 ;
     RECT  23.904 34.741 24.408 34.933 ;
     RECT  25.488 34.213 25.512 34.933 ;
     RECT  60.96 31.285 62.112 34.933 ;
     RECT  5.1 34.069 6.552 34.979 ;
     RECT  23.904 34.933 25.512 35.219 ;
     RECT  10.5 34.211 10.812 35.317 ;
     RECT  18.6 23.363 18.912 35.317 ;
     RECT  44.64 33.013 45.912 35.363 ;
     RECT  31.728 33.539 33.576 35.459 ;
     RECT  56.304 34.741 56.904 35.459 ;
     RECT  60.768 34.933 62.112 35.459 ;
     RECT  64.5 31.715 65.352 35.459 ;
     RECT  68.832 35.461 68.856 35.509 ;
     RECT  69.9 34.741 70.584 35.509 ;
     RECT  45.504 35.363 45.912 35.555 ;
     RECT  18.048 35.317 18.912 35.605 ;
     RECT  32.1 35.459 33.576 35.651 ;
     RECT  25.488 35.219 25.512 35.747 ;
     RECT  28.512 34.741 30.264 35.747 ;
     RECT  56.304 35.459 56.712 35.747 ;
     RECT  7.8 31.379 8.112 35.845 ;
     RECT  39.888 34.835 40.824 35.845 ;
     RECT  53.28 33.877 54.12 35.845 ;
     RECT  23.904 35.219 24.408 35.939 ;
     RECT  63.456 35.077 63.48 35.939 ;
     RECT  68.832 35.509 70.584 35.939 ;
     RECT  18.048 35.605 19.032 36.037 ;
     RECT  10.272 35.317 10.812 36.275 ;
     RECT  34.656 34.741 35.112 36.323 ;
     RECT  7.8 35.845 9.096 36.419 ;
     RECT  36.384 33.683 37.812 36.469 ;
     RECT  39.648 35.845 40.824 36.469 ;
     RECT  15.408 34.885 16.212 36.515 ;
     RECT  20.448 34.741 22.104 36.515 ;
     RECT  23.904 35.939 24.312 36.515 ;
     RECT  69.9 35.939 70.584 36.517 ;
     RECT  6.528 34.979 6.552 36.563 ;
     RECT  60.768 35.459 60.792 36.803 ;
     RECT  67.2 34.643 67.512 36.853 ;
     RECT  68.832 35.939 68.856 36.853 ;
     RECT  9.12 36.613 9.144 36.899 ;
     RECT  7.8 36.419 8.112 36.901 ;
     RECT  24 36.515 24.312 36.901 ;
     RECT  29.4 35.747 30.264 36.901 ;
     RECT  12.768 33.203 13.608 36.947 ;
     RECT  39.648 36.469 41.544 36.949 ;
     RECT  58.656 34.787 59.412 36.949 ;
     RECT  67.2 36.853 68.856 36.995 ;
     RECT  26.7 33.875 27.012 36.997 ;
     RECT  34.8 36.323 35.112 36.997 ;
     RECT  42.9 30.803 43.212 36.997 ;
     RECT  48.096 34.741 48.612 36.997 ;
     RECT  7.392 36.901 8.112 37.043 ;
     RECT  12.96 36.947 13.608 37.043 ;
     RECT  18.048 36.037 19.368 37.043 ;
     RECT  5.1 34.979 5.544 37.045 ;
     RECT  47.904 36.997 48.612 37.045 ;
     RECT  56.4 35.747 56.712 37.045 ;
     RECT  18.6 37.043 19.368 37.091 ;
     RECT  53.28 35.845 54.744 37.091 ;
     RECT  29.28 36.901 30.264 37.093 ;
     RECT  32.1 35.651 33.096 37.093 ;
     RECT  51 34.835 51.312 37.093 ;
     RECT  53.28 37.091 54.12 37.093 ;
     RECT  34.8 36.997 35.304 37.139 ;
     RECT  15.648 36.515 16.212 37.187 ;
     RECT  47.904 37.045 49.032 37.235 ;
     RECT  52.944 37.093 54.12 37.283 ;
     RECT  15.9 37.187 16.212 37.429 ;
     RECT  42.9 36.997 43.896 37.429 ;
     RECT  15.9 37.429 16.536 37.477 ;
     RECT  5.1 37.045 6.024 37.859 ;
     RECT  26.7 36.997 27.144 37.907 ;
     RECT  50.688 37.093 51.312 37.907 ;
     RECT  51 37.907 51.312 38.005 ;
     RECT  38.784 36.949 41.544 38.147 ;
     RECT  53.28 37.283 54.12 38.147 ;
     RECT  7.8 37.043 8.112 38.149 ;
     RECT  10.5 36.275 10.812 38.149 ;
     RECT  53.568 38.147 54.12 38.149 ;
     RECT  57.792 36.949 59.412 38.195 ;
     RECT  21.3 36.515 22.104 38.197 ;
     RECT  6.864 38.149 8.112 38.387 ;
     RECT  67.2 36.995 68.76 38.435 ;
     RECT  61.8 35.459 62.112 38.581 ;
     RECT  47.904 37.235 48.612 38.677 ;
     RECT  61.8 38.581 62.232 38.677 ;
     RECT  42.9 37.429 43.944 38.723 ;
     RECT  60.816 38.677 62.232 38.723 ;
     RECT  15.9 37.477 16.872 38.725 ;
     RECT  29.28 37.093 33.096 38.819 ;
     RECT  55.872 37.045 56.712 38.819 ;
     RECT  12.96 37.043 13.512 38.821 ;
     RECT  34.8 37.139 35.112 38.917 ;
     RECT  36.288 36.469 37.812 38.963 ;
     RECT  28.224 38.533 28.248 38.965 ;
     RECT  29.28 38.819 30.264 38.965 ;
     RECT  32.1 38.819 33.096 38.965 ;
     RECT  67.2 38.435 67.944 38.965 ;
     RECT  42.9 38.723 43.896 39.059 ;
     RECT  65.808 38.149 65.832 39.059 ;
     RECT  69.9 36.517 70.68 39.061 ;
     RECT  72.6 34.211 72.912 39.061 ;
     RECT  38.784 38.147 40.728 39.203 ;
     RECT  67.104 38.965 67.944 39.251 ;
     RECT  21.3 38.197 22.344 39.253 ;
     RECT  51 38.005 52.008 39.253 ;
     RECT  47.472 38.677 48.612 39.299 ;
     RECT  50.88 39.253 52.008 39.301 ;
     RECT  28.224 38.965 30.264 39.347 ;
     RECT  7.152 38.387 8.112 39.395 ;
     RECT  50.592 39.301 52.008 39.395 ;
     RECT  60.816 38.723 62.112 39.395 ;
     RECT  28.224 39.347 28.248 39.491 ;
     RECT  53.568 38.149 54.504 39.491 ;
     RECT  34.8 38.917 35.208 39.539 ;
     RECT  67.104 39.251 67.608 39.539 ;
     RECT  15.36 38.725 16.872 39.683 ;
     RECT  69.9 39.061 72.912 39.683 ;
     RECT  10.5 38.149 11.208 39.779 ;
     RECT  63.504 38.725 63.528 39.779 ;
     RECT  67.2 39.539 67.608 39.779 ;
     RECT  7.8 39.395 8.112 39.829 ;
     RECT  9.264 37.573 9.288 39.829 ;
     RECT  21.3 39.253 22.776 39.971 ;
     RECT  38.784 39.203 38.808 40.019 ;
     RECT  48.048 39.299 48.612 40.019 ;
     RECT  15.36 39.683 16.536 40.357 ;
     RECT  69.9 39.683 71.064 40.403 ;
     RECT  10.5 39.779 10.812 40.405 ;
     RECT  45.6 35.555 45.912 40.405 ;
     RECT  12.672 38.821 13.512 40.451 ;
     RECT  7.8 39.829 9.288 40.499 ;
     RECT  55.2 40.549 55.224 40.597 ;
     RECT  64.5 35.459 64.812 40.597 ;
     RECT  53.568 39.491 54.12 40.691 ;
     RECT  53.568 40.691 54.012 40.789 ;
     RECT  36.384 38.963 37.812 40.981 ;
     RECT  48.3 40.019 48.612 40.981 ;
     RECT  52.848 40.789 54.012 41.027 ;
     RECT  18.6 37.091 19.032 41.029 ;
     RECT  3.984 40.405 4.008 41.075 ;
     RECT  14.832 40.357 16.536 41.075 ;
     RECT  21.3 39.971 22.104 41.221 ;
     RECT  67.2 39.779 67.512 41.221 ;
     RECT  39.888 39.203 40.728 41.365 ;
     RECT  36.384 40.981 38.184 41.411 ;
     RECT  12.96 40.451 13.512 41.557 ;
     RECT  32.1 38.965 33.624 41.557 ;
     RECT  34.8 39.539 35.112 41.557 ;
     RECT  47.856 40.981 48.612 41.557 ;
     RECT  69.9 40.403 70.68 41.605 ;
     RECT  18.288 41.029 19.032 41.651 ;
     RECT  66 40.693 66.024 41.651 ;
     RECT  10.368 40.405 10.812 41.699 ;
     RECT  6.72 40.405 6.744 41.747 ;
     RECT  18.6 41.651 19.032 41.747 ;
     RECT  55.104 40.597 55.224 41.891 ;
     RECT  45.456 40.405 45.912 41.987 ;
     RECT  14.832 41.075 16.44 42.037 ;
     RECT  21.3 41.221 22.152 42.133 ;
     RECT  47.856 41.557 49.56 42.133 ;
     RECT  50.592 39.395 51.312 42.133 ;
     RECT  31.92 41.557 35.112 42.179 ;
     RECT  64.368 40.597 64.812 42.227 ;
     RECT  67.2 41.221 67.608 42.227 ;
     RECT  12.96 41.557 13.656 42.659 ;
     RECT  12.96 42.659 13.608 42.709 ;
     RECT  18.6 41.747 18.912 42.709 ;
     RECT  32.1 42.179 35.112 42.709 ;
     RECT  36.384 41.411 37.812 42.709 ;
     RECT  14.832 42.037 16.536 42.755 ;
     RECT  47.376 42.133 49.56 42.755 ;
     RECT  14.832 42.755 14.856 42.803 ;
     RECT  55.2 41.891 55.224 42.803 ;
     RECT  42.9 39.059 43.212 43.045 ;
     RECT  53.7 41.027 54.012 43.285 ;
     RECT  9.264 40.499 9.288 43.379 ;
     RECT  20.592 42.133 22.152 43.379 ;
     RECT  32.1 42.709 37.812 43.523 ;
     RECT  7.8 40.499 8.112 43.525 ;
     RECT  50.592 42.133 51.96 43.619 ;
     RECT  18.48 42.709 18.912 43.667 ;
     RECT  10.5 41.699 10.812 43.717 ;
     RECT  12 42.709 13.608 43.717 ;
     RECT  32.1 43.523 33.624 43.763 ;
     RECT  5.1 37.859 5.544 43.861 ;
     RECT  34.8 43.523 37.812 43.907 ;
     RECT  58.56 38.195 59.412 43.955 ;
     RECT  69.9 41.605 70.776 43.955 ;
     RECT  42.768 43.045 43.212 44.099 ;
     RECT  50.592 43.619 51.312 44.099 ;
     RECT  53.7 43.285 54.984 44.099 ;
     RECT  66 42.997 66.024 44.099 ;
     RECT  61.536 39.395 62.112 44.339 ;
     RECT  18.6 43.667 18.912 44.389 ;
     RECT  32.1 43.763 32.808 44.437 ;
     RECT  39.888 41.365 41.112 44.437 ;
     RECT  56.4 38.819 56.712 44.437 ;
     RECT  10.5 43.717 13.608 44.483 ;
     RECT  24 36.901 24.696 44.483 ;
     RECT  48.3 42.755 49.56 44.483 ;
     RECT  6.816 43.525 8.112 44.723 ;
     RECT  39.312 44.437 41.112 44.819 ;
     RECT  51 44.099 51.312 44.917 ;
     RECT  5.1 43.861 5.688 45.059 ;
     RECT  31.872 44.437 32.808 45.059 ;
     RECT  58.656 43.955 59.412 45.059 ;
     RECT  26.7 37.907 27.012 45.205 ;
     RECT  31.968 45.059 32.808 45.205 ;
     RECT  29.4 39.347 30.264 45.299 ;
     RECT  18.6 44.389 19.032 45.443 ;
     RECT  34.8 43.907 35.112 45.493 ;
     RECT  7.8 44.723 8.112 45.541 ;
     RECT  39.888 44.819 41.112 45.635 ;
     RECT  69.9 43.955 70.68 45.683 ;
     RECT  25.68 39.253 25.704 45.731 ;
     RECT  31.968 45.205 33.096 45.731 ;
     RECT  51 44.917 52.2 46.211 ;
     RECT  56.4 44.437 57.624 46.211 ;
     RECT  15.9 42.755 16.536 46.259 ;
     RECT  21.168 43.379 22.152 46.259 ;
     RECT  26.7 45.205 27.192 46.259 ;
     RECT  12.096 44.483 13.512 46.355 ;
     RECT  7.8 45.541 8.808 46.547 ;
     RECT  45.6 41.987 45.912 46.693 ;
     RECT  69.9 45.683 70.344 46.693 ;
     RECT  69.552 46.693 70.344 46.751 ;
     RECT  56.4 46.211 56.808 46.789 ;
     RECT  15.9 46.259 16.212 46.837 ;
     RECT  12.096 46.355 12.12 46.933 ;
     RECT  69.552 46.751 70.392 46.933 ;
     RECT  69.552 46.933 70.488 47.029 ;
     RECT  69.264 47.029 70.488 47.075 ;
     RECT  11.904 46.933 12.12 47.123 ;
     RECT  69.264 47.075 70.392 47.123 ;
     RECT  24 44.483 24.312 47.173 ;
     RECT  26.7 46.259 27.012 47.221 ;
     RECT  21.3 46.259 22.152 47.269 ;
     RECT  29.4 45.299 29.712 47.269 ;
     RECT  39.888 45.635 41.016 47.269 ;
     RECT  72.6 39.683 72.912 47.269 ;
     RECT  34.176 45.493 35.112 47.315 ;
     RECT  64.5 42.227 64.812 47.317 ;
     RECT  39.168 47.269 41.016 47.363 ;
     RECT  44.88 46.693 45.912 47.363 ;
     RECT  31.968 45.731 32.412 47.413 ;
     RECT  7.8 46.547 8.112 47.557 ;
     RECT  51 46.211 51.912 47.603 ;
     RECT  31.968 47.413 32.664 47.651 ;
     RECT  18.6 45.443 18.912 47.701 ;
     RECT  21.3 47.269 22.728 47.701 ;
     RECT  13.2 46.355 13.512 47.749 ;
     RECT  59.1 45.059 59.412 47.749 ;
     RECT  55.632 46.789 56.808 47.843 ;
     RECT  5.1 45.059 5.412 47.845 ;
     RECT  7.392 47.557 8.112 47.845 ;
     RECT  36.384 43.907 37.812 47.845 ;
     RECT  39.168 47.363 40.728 47.845 ;
     RECT  42.9 44.099 43.212 47.845 ;
     RECT  67.2 42.227 67.512 47.845 ;
     RECT  15.36 46.837 16.212 47.891 ;
     RECT  64.5 47.317 64.92 47.891 ;
     RECT  71.52 47.749 71.544 48.229 ;
     RECT  72.6 47.269 73.032 48.229 ;
     RECT  71.52 48.229 73.032 48.277 ;
     RECT  5.1 47.845 6.264 48.421 ;
     RECT  12.096 47.123 12.12 48.421 ;
     RECT  29.4 47.269 30.696 48.421 ;
     RECT  45.6 47.363 45.912 48.421 ;
     RECT  31.968 47.651 32.412 48.467 ;
     RECT  4.848 48.421 6.264 48.515 ;
     RECT  7.392 47.845 8.568 48.659 ;
     RECT  45.216 48.421 45.912 48.707 ;
     RECT  7.8 48.659 8.568 48.757 ;
     RECT  10.5 44.483 10.812 48.757 ;
     RECT  12.048 48.421 12.12 48.757 ;
     RECT  69.264 47.123 70.212 48.757 ;
     RECT  13.104 47.749 13.512 48.947 ;
     RECT  66.672 47.845 67.512 48.947 ;
     RECT  68.928 48.757 70.212 48.997 ;
     RECT  71.472 48.277 73.032 48.997 ;
     RECT  7.8 48.757 9.144 49.043 ;
     RECT  18.24 47.701 18.912 49.043 ;
     RECT  42.24 47.845 43.212 49.043 ;
     RECT  66.96 48.947 67.512 49.043 ;
     RECT  2.4 20.291 2.712 49.189 ;
     RECT  48.3 44.483 48.612 49.189 ;
     RECT  53.7 44.099 54.012 49.189 ;
     RECT  55.632 47.843 56.712 49.189 ;
     RECT  64.5 47.891 64.812 49.189 ;
     RECT  68.928 48.997 73.032 49.189 ;
     RECT  13.2 48.947 13.512 49.237 ;
     RECT  53.7 49.189 56.712 49.285 ;
     RECT  2.304 49.189 2.712 49.379 ;
     RECT  24 47.173 24.696 49.379 ;
     RECT  68.592 49.189 73.032 49.475 ;
     RECT  32.1 48.467 32.412 49.477 ;
     RECT  34.8 47.315 35.112 49.477 ;
     RECT  42.9 49.043 43.212 49.477 ;
     RECT  36.384 47.845 40.728 49.523 ;
     RECT  68.592 49.475 72.912 49.619 ;
     RECT  61.8 44.339 62.112 49.669 ;
     RECT  14.784 48.421 14.808 49.715 ;
     RECT  67.2 49.043 67.512 49.717 ;
     RECT  68.592 49.619 68.616 49.717 ;
     RECT  28.512 48.421 30.696 49.763 ;
     RECT  67.2 49.717 68.616 49.763 ;
     RECT  34.224 49.477 35.112 49.861 ;
     RECT  47.856 49.189 48.612 49.861 ;
     RECT  47.808 49.861 48.612 49.909 ;
     RECT  26.7 47.221 27.144 50.003 ;
     RECT  47.808 49.909 49.032 50.051 ;
     RECT  53.7 49.285 56.952 50.051 ;
     RECT  69.9 49.619 72.912 50.051 ;
     RECT  33.792 49.861 35.112 50.099 ;
     RECT  59.1 47.749 60.072 50.099 ;
     RECT  28.512 49.763 29.712 50.195 ;
     RECT  61.632 49.669 62.112 50.195 ;
     RECT  36.384 49.523 38.376 50.243 ;
     RECT  64.5 49.189 65.112 50.291 ;
     RECT  71.472 50.051 72.912 50.291 ;
     RECT  21.168 47.701 22.728 50.533 ;
     RECT  39.696 49.523 40.728 50.581 ;
     RECT  21.168 50.533 22.824 50.675 ;
     RECT  42.9 49.477 43.368 50.675 ;
     RECT  24 49.379 24.504 50.771 ;
     RECT  47.808 50.051 48.612 50.771 ;
     RECT  29.088 50.195 29.712 51.253 ;
     RECT  34.224 50.099 35.112 51.253 ;
     RECT  47.856 50.771 48.612 51.253 ;
     RECT  21.168 50.675 22.2 51.299 ;
     RECT  7.8 49.043 8.52 51.347 ;
     RECT  60.384 50.725 60.408 51.395 ;
     RECT  39.696 50.581 41.112 51.443 ;
     RECT  26.7 50.003 27.012 51.493 ;
     RECT  24 50.771 24.456 51.541 ;
     RECT  10.5 48.757 12.12 51.635 ;
     RECT  53.7 50.051 54.888 51.635 ;
     RECT  67.2 49.763 68.424 51.781 ;
     RECT  4.848 48.515 5.412 51.829 ;
     RECT  36.384 50.243 37.944 51.829 ;
     RECT  13.2 49.237 13.656 51.877 ;
     RECT  31.968 49.477 32.412 51.877 ;
     RECT  34.176 51.253 35.112 51.923 ;
     RECT  56.4 50.051 56.952 51.923 ;
     RECT  18.384 49.043 18.912 52.021 ;
     RECT  29.088 51.253 30.024 52.067 ;
     RECT  39.696 51.443 40.824 52.211 ;
     RECT  7.8 51.347 8.112 52.261 ;
     RECT  45.6 48.707 45.912 52.357 ;
     RECT  36.288 51.829 37.944 52.405 ;
     RECT  39.936 52.211 40.824 52.405 ;
     RECT  51 47.603 51.312 52.405 ;
     RECT  21.168 51.299 21.912 52.451 ;
     RECT  47.856 51.253 48.744 52.451 ;
     RECT  64.5 50.291 64.812 52.549 ;
     RECT  4.848 51.829 5.736 52.691 ;
     RECT  52.416 50.965 52.44 52.693 ;
     RECT  53.7 51.635 54.012 52.693 ;
     RECT  36.288 52.405 38.088 52.739 ;
     RECT  50.16 52.405 51.312 52.739 ;
     RECT  52.416 52.693 54.012 52.739 ;
     RECT  52.752 52.739 54.012 52.789 ;
     RECT  9.12 52.693 9.144 52.883 ;
     RECT  13.104 51.877 13.656 52.883 ;
     RECT  13.2 52.883 13.656 52.931 ;
     RECT  67.2 51.781 68.568 52.981 ;
     RECT  69.9 50.051 70.212 52.981 ;
     RECT  17.904 52.021 18.912 53.075 ;
     RECT  7.056 52.261 8.112 53.077 ;
     RECT  34.8 51.923 35.112 53.269 ;
     RECT  31.632 51.877 32.412 53.363 ;
     RECT  67.2 52.981 70.212 53.365 ;
     RECT  61.8 50.195 62.112 53.461 ;
     RECT  63.744 52.549 64.812 53.461 ;
     RECT  39.936 52.405 41.736 53.509 ;
     RECT  39.744 53.509 41.736 53.555 ;
     RECT  61.8 53.461 64.812 53.555 ;
     RECT  7.056 53.077 8.52 53.603 ;
     RECT  23.856 51.541 24.456 53.603 ;
     RECT  52.752 52.789 54.168 53.603 ;
     RECT  67.104 53.365 70.212 53.603 ;
     RECT  20.016 52.549 20.04 53.795 ;
     RECT  68.544 53.603 70.212 53.795 ;
     RECT  36.384 52.739 38.088 53.797 ;
     RECT  68.544 53.795 68.568 53.843 ;
     RECT  34.368 53.269 35.112 53.941 ;
     RECT  36.384 53.797 38.232 53.941 ;
     RECT  71.472 50.291 71.496 53.941 ;
     RECT  71.232 53.941 71.496 53.987 ;
     RECT  21.3 52.451 21.912 54.085 ;
     RECT  67.104 53.603 67.512 54.085 ;
     RECT  14.832 52.933 14.856 54.179 ;
     RECT  42.9 50.675 43.212 54.229 ;
     RECT  7.8 53.603 8.52 54.517 ;
     RECT  7.8 54.517 9.144 54.563 ;
     RECT  26.7 51.493 27.336 54.563 ;
     RECT  13.2 52.931 13.512 54.613 ;
     RECT  34.368 53.941 38.232 54.659 ;
     RECT  59.1 50.099 59.412 54.709 ;
     RECT  69.9 53.795 70.212 54.853 ;
     RECT  71.232 53.987 71.448 54.853 ;
     RECT  23.856 53.603 24.408 54.899 ;
     RECT  45.6 52.357 46.008 54.899 ;
     RECT  57.696 53.077 57.72 54.899 ;
     RECT  69.9 54.853 71.448 54.899 ;
     RECT  29.088 52.067 29.712 55.045 ;
     RECT  39.744 53.555 41.64 55.093 ;
     RECT  34.368 54.659 38.088 55.139 ;
     RECT  21.3 54.085 22.344 55.237 ;
     RECT  42.768 54.229 43.212 55.237 ;
     RECT  9.12 54.563 9.144 55.283 ;
     RECT  34.8 55.139 38.088 55.283 ;
     RECT  42.768 55.237 43.32 55.283 ;
     RECT  64.368 53.555 64.812 55.283 ;
     RECT  7.8 54.563 8.112 55.285 ;
     RECT  69.9 54.899 71.208 55.379 ;
     RECT  39.696 55.093 41.64 55.475 ;
     RECT  72.48 50.291 72.912 55.475 ;
     RECT  10.5 51.635 11.4 55.525 ;
     RECT  58.992 54.709 59.412 55.525 ;
     RECT  45.6 54.899 45.912 55.813 ;
     RECT  56.4 51.923 56.712 55.813 ;
     RECT  58.992 55.525 59.832 55.813 ;
     RECT  12.816 54.613 13.512 55.859 ;
     RECT  52.752 53.603 54.012 55.861 ;
     RECT  26.7 54.563 27.012 55.909 ;
     RECT  58.992 55.813 60.504 56.005 ;
     RECT  71.184 55.379 71.208 56.053 ;
     RECT  71.184 56.053 71.304 56.099 ;
     RECT  18.384 53.075 18.912 56.339 ;
     RECT  29.088 55.045 30.024 56.387 ;
     RECT  44.832 55.813 45.912 56.387 ;
     RECT  34.8 55.283 35.352 56.389 ;
     RECT  61.8 53.555 62.952 56.389 ;
     RECT  64.5 55.283 64.812 56.389 ;
     RECT  21.3 55.237 22.536 56.483 ;
     RECT  13.2 55.859 13.512 56.485 ;
     RECT  26.208 55.909 27.012 56.723 ;
     RECT  6.864 55.285 8.112 57.059 ;
     RECT  10.368 55.525 11.4 57.059 ;
     RECT  42.9 55.283 43.32 57.059 ;
     RECT  52.368 55.861 54.012 57.059 ;
     RECT  56.4 55.813 57.288 57.059 ;
     RECT  47.856 52.451 48.612 57.109 ;
     RECT  58.848 56.005 60.504 57.155 ;
     RECT  32.1 53.363 32.412 57.301 ;
     RECT  66.96 54.085 67.512 57.301 ;
     RECT  10.368 57.059 10.812 57.445 ;
     RECT  31.968 57.301 32.412 57.635 ;
     RECT  29.088 56.387 29.712 57.973 ;
     RECT  29.088 57.973 30.216 58.069 ;
     RECT  36.384 55.283 38.088 58.069 ;
     RECT  7.632 57.059 8.112 58.117 ;
     RECT  13.2 56.485 13.752 58.117 ;
     RECT  21.3 56.483 21.912 58.117 ;
     RECT  23.856 54.899 24.312 58.117 ;
     RECT  34.512 56.389 35.352 58.117 ;
     RECT  36.384 58.069 38.472 58.117 ;
     RECT  58.848 57.155 59.832 58.259 ;
     RECT  12.528 58.117 13.752 58.355 ;
     RECT  4.848 52.691 5.412 58.451 ;
     RECT  51 52.739 51.312 58.501 ;
     RECT  55.296 57.397 55.32 58.501 ;
     RECT  56.4 57.059 56.712 58.501 ;
     RECT  69.9 55.379 70.212 58.501 ;
     RECT  71.28 56.099 71.304 58.501 ;
     RECT  72.6 55.475 72.912 58.501 ;
     RECT  28.944 58.069 30.216 58.547 ;
     RECT  71.28 58.501 72.912 58.547 ;
     RECT  55.296 58.501 56.712 58.597 ;
     RECT  20.976 58.117 21.912 58.645 ;
     RECT  61.8 56.389 64.812 58.645 ;
     RECT  34.512 58.117 38.472 58.691 ;
     RECT  58.848 58.259 59.412 58.691 ;
     RECT  53.136 57.059 54.012 58.693 ;
     RECT  28.944 58.547 30.12 58.789 ;
     RECT  9.648 57.445 10.812 58.835 ;
     RECT  61.008 58.645 64.812 58.931 ;
     RECT  18.48 56.339 18.912 58.933 ;
     RECT  18.48 58.933 19.368 58.979 ;
     RECT  20.976 58.645 22.008 58.981 ;
     RECT  23.568 58.117 25.08 58.981 ;
     RECT  53.04 58.693 54.012 59.027 ;
     RECT  20.976 58.981 25.08 59.029 ;
     RECT  26.7 56.723 27.012 59.029 ;
     RECT  55.296 58.597 57.336 59.077 ;
     RECT  20.976 59.029 27.012 59.123 ;
     RECT  34.8 58.691 38.472 59.123 ;
     RECT  36.384 59.123 38.472 59.171 ;
     RECT  66.96 57.301 67.608 59.173 ;
     RECT  23.232 59.123 27.012 59.219 ;
     RECT  32.1 57.635 32.412 59.221 ;
     RECT  42.9 57.059 43.212 59.221 ;
     RECT  23.232 59.219 24.408 59.411 ;
     RECT  66.432 59.173 67.608 59.461 ;
     RECT  63.264 58.931 64.812 59.507 ;
     RECT  20.976 59.123 22.008 59.699 ;
     RECT  31.968 59.221 32.412 59.701 ;
     RECT  12.528 58.355 13.512 59.747 ;
     RECT  69.12 58.501 70.212 59.795 ;
     RECT  5.1 58.451 5.412 59.797 ;
     RECT  23.232 59.411 24.312 59.843 ;
     RECT  51 58.501 51.432 59.891 ;
     RECT  55.248 59.077 57.336 59.939 ;
     RECT  61.008 58.931 62.112 59.939 ;
     RECT  53.136 59.027 54.012 60.037 ;
     RECT  55.728 59.939 57.336 60.275 ;
     RECT  63.408 59.507 64.812 60.275 ;
     RECT  28.704 58.789 30.12 60.277 ;
     RECT  42.048 59.221 43.212 60.277 ;
     RECT  53.136 60.037 54.12 60.277 ;
     RECT  63.552 60.275 64.812 60.373 ;
     RECT  33.648 59.605 33.672 60.467 ;
     RECT  13.2 59.747 13.512 60.613 ;
     RECT  14.496 58.645 14.52 60.613 ;
     RECT  7.344 58.117 8.112 60.661 ;
     RECT  71.76 58.547 72.912 60.661 ;
     RECT  21.3 59.699 22.008 60.709 ;
     RECT  61.104 59.939 62.112 60.803 ;
     RECT  34.8 59.123 35.352 60.949 ;
     RECT  36.384 59.171 37.812 60.949 ;
     RECT  51 59.891 51.312 60.949 ;
     RECT  5.1 59.797 6.312 60.995 ;
     RECT  13.2 60.613 14.52 61.043 ;
     RECT  31.968 59.701 32.568 61.043 ;
     RECT  47.376 57.109 48.612 61.043 ;
     RECT  34.8 60.949 37.812 61.093 ;
     RECT  55.728 60.275 56.712 61.093 ;
     RECT  34.8 61.093 38.04 61.139 ;
     RECT  34.8 61.139 35.88 61.235 ;
     RECT  59.1 58.691 59.412 61.525 ;
     RECT  71.76 60.661 73.08 61.525 ;
     RECT  52.656 60.277 54.12 61.571 ;
     RECT  25.728 59.219 27.012 61.573 ;
     RECT  25.632 61.573 27.012 61.619 ;
     RECT  52.656 61.571 54.012 61.619 ;
     RECT  71.76 61.525 73.512 61.717 ;
     RECT  42.048 60.277 43.32 61.763 ;
     RECT  71.28 61.717 73.512 61.763 ;
     RECT  58.128 61.525 59.412 61.765 ;
     RECT  44.496 59.797 44.52 61.861 ;
     RECT  45.6 56.387 45.912 61.861 ;
     RECT  48.3 61.043 48.612 61.861 ;
     RECT  63.552 60.373 65.016 62.005 ;
     RECT  66.432 59.461 67.656 62.005 ;
     RECT  63.552 62.005 67.656 62.051 ;
     RECT  21.3 60.709 22.968 62.195 ;
     RECT  42.048 61.763 43.212 62.195 ;
     RECT  64.5 62.051 67.656 62.197 ;
     RECT  55.296 61.093 56.712 62.293 ;
     RECT  55.296 62.293 56.808 62.339 ;
     RECT  58.128 61.765 60.264 62.339 ;
     RECT  28.416 60.277 30.12 62.341 ;
     RECT  10.5 58.835 10.812 62.437 ;
     RECT  31.968 61.043 32.412 62.579 ;
     RECT  39.696 55.475 40.92 62.629 ;
     RECT  25.632 61.619 25.656 62.677 ;
     RECT  26.7 61.619 27.012 62.677 ;
     RECT  32.1 62.579 32.412 62.677 ;
     RECT  37.008 61.139 38.04 62.677 ;
     RECT  39.6 62.629 40.92 62.677 ;
     RECT  37.008 62.677 40.92 62.725 ;
     RECT  59.1 62.339 60.264 62.771 ;
     RECT  37.008 62.725 40.968 62.819 ;
     RECT  24 59.843 24.312 62.821 ;
     RECT  44.496 61.861 45.912 62.867 ;
     RECT  44.496 62.867 44.52 62.915 ;
     RECT  28.176 62.341 30.12 63.013 ;
     RECT  21.3 62.195 22.824 63.059 ;
     RECT  53.136 61.619 54.012 63.059 ;
     RECT  7.344 60.661 8.232 63.203 ;
     RECT  53.568 63.059 54.012 63.205 ;
     RECT  55.728 62.339 56.808 63.395 ;
     RECT  61.488 60.803 62.112 63.493 ;
     RECT  34.8 61.235 35.112 63.541 ;
     RECT  37.008 62.819 37.812 63.541 ;
     RECT  15.9 47.891 16.212 63.589 ;
     RECT  61.488 63.493 62.232 63.589 ;
     RECT  48.3 61.861 48.792 63.635 ;
     RECT  7.344 63.203 8.112 63.779 ;
     RECT  25.632 62.677 27.012 63.779 ;
     RECT  28.176 63.013 30.84 63.779 ;
     RECT  18.6 58.979 19.368 63.827 ;
     RECT  50.64 60.949 51.312 64.067 ;
     RECT  18.6 63.827 18.912 64.069 ;
     RECT  42.72 62.195 43.212 64.213 ;
     RECT  26.16 63.779 27.012 64.309 ;
     RECT  24 62.821 24.552 64.355 ;
     RECT  26.16 64.309 27.384 64.355 ;
     RECT  32.1 62.677 33.24 64.355 ;
     RECT  36.432 63.541 37.812 64.355 ;
     RECT  53.568 63.205 54.744 64.355 ;
     RECT  21.3 63.059 22.008 64.357 ;
     RECT  64.5 62.197 67.704 64.357 ;
     RECT  28.704 63.779 30.84 64.403 ;
     RECT  69.9 59.795 70.212 64.405 ;
     RECT  71.28 61.763 71.304 64.405 ;
     RECT  10.5 62.437 11.784 64.595 ;
     RECT  63.552 64.357 67.8 64.595 ;
     RECT  42.72 64.213 43.992 64.597 ;
     RECT  72.6 61.763 73.512 64.643 ;
     RECT  13.2 61.043 14.376 64.693 ;
     RECT  39.6 62.819 40.968 64.741 ;
     RECT  48.3 63.635 48.612 64.933 ;
     RECT  13.2 64.693 14.664 64.979 ;
     RECT  17.952 64.069 18.912 64.979 ;
     RECT  53.568 64.355 54.12 65.125 ;
     RECT  66.24 64.595 67.8 65.219 ;
     RECT  13.2 64.979 14.568 65.411 ;
     RECT  37.056 64.355 37.812 65.459 ;
     RECT  63.552 64.595 65.208 65.459 ;
     RECT  45.6 62.867 45.912 65.509 ;
     RECT  69.9 64.405 71.304 65.603 ;
     RECT  39.6 64.741 41.016 65.651 ;
     RECT  52.992 65.125 54.12 65.651 ;
     RECT  42.576 64.597 43.992 65.653 ;
     RECT  61.488 63.589 62.28 65.795 ;
     RECT  48.3 64.933 48.744 65.939 ;
     RECT  7.68 63.779 8.112 65.941 ;
     RECT  66.24 65.219 67.608 66.083 ;
     RECT  59.1 62.771 59.412 66.085 ;
     RECT  63.696 65.459 65.208 66.085 ;
     RECT  66.24 66.083 67.512 66.085 ;
     RECT  39.6 65.651 40.968 66.179 ;
     RECT  39.6 66.179 40.512 66.325 ;
     RECT  10.5 64.595 10.812 66.373 ;
     RECT  71.28 65.603 71.304 66.469 ;
     RECT  71.28 66.469 71.448 66.515 ;
     RECT  21.3 64.357 22.392 66.565 ;
     RECT  21.168 66.565 22.392 66.611 ;
     RECT  26.7 64.355 27.384 66.707 ;
     RECT  42.576 65.653 44.472 66.755 ;
     RECT  72.6 64.643 72.912 66.757 ;
     RECT  28.704 64.403 30.12 66.803 ;
     RECT  21.168 66.611 22.008 66.901 ;
     RECT  13.2 65.411 14.376 67.141 ;
     RECT  7.392 65.941 8.112 67.187 ;
     RECT  18.6 64.979 18.912 67.189 ;
     RECT  24 64.355 24.312 67.189 ;
     RECT  48.3 65.939 48.612 67.189 ;
     RECT  45.6 65.509 46.776 67.235 ;
     RECT  15.9 63.589 16.344 67.283 ;
     RECT  34.608 63.541 35.112 67.283 ;
     RECT  52.992 65.651 54.012 67.283 ;
     RECT  61.488 65.795 62.232 67.283 ;
     RECT  34.8 67.283 35.112 67.285 ;
     RECT  42.576 66.755 43.212 67.285 ;
     RECT  23.856 67.189 24.312 67.333 ;
     RECT  63.696 66.085 67.512 67.573 ;
     RECT  63.696 67.573 67.8 67.619 ;
     RECT  58.704 66.085 59.412 67.765 ;
     RECT  72.6 66.757 73.128 67.811 ;
     RECT  21.12 66.901 22.008 67.859 ;
     RECT  44.448 66.755 44.472 67.859 ;
     RECT  48.3 67.189 49.512 67.859 ;
     RECT  61.536 67.283 62.232 67.859 ;
     RECT  63.696 67.619 65.496 67.859 ;
     RECT  71.424 66.515 71.448 67.859 ;
     RECT  10.5 66.373 10.968 67.907 ;
     RECT  13.008 67.141 14.376 67.907 ;
     RECT  21.168 67.859 22.008 67.955 ;
     RECT  67.104 67.619 67.8 67.955 ;
     RECT  34.8 67.285 35.784 68.099 ;
     RECT  55.728 63.395 56.712 68.245 ;
     RECT  7.44 67.187 8.112 68.339 ;
     RECT  23.328 67.333 24.312 68.341 ;
     RECT  32.1 64.355 32.412 68.341 ;
     RECT  18.6 67.189 19.896 68.387 ;
     RECT  32.1 68.341 32.52 68.389 ;
     RECT  58.128 67.765 59.412 68.531 ;
     RECT  21.3 67.955 22.008 68.581 ;
     RECT  23.328 68.341 25.128 68.581 ;
     RECT  21.3 68.581 25.128 68.723 ;
     RECT  69.9 65.603 70.212 68.773 ;
     RECT  26.7 66.707 27.012 68.821 ;
     RECT  45.6 67.235 45.912 68.821 ;
     RECT  13.104 67.907 14.376 68.869 ;
     RECT  31.488 68.389 32.52 68.869 ;
     RECT  53.7 67.283 54.012 68.869 ;
     RECT  55.056 68.245 56.712 68.869 ;
     RECT  23.328 68.723 25.128 68.915 ;
     RECT  5.1 60.995 5.412 68.917 ;
     RECT  13.104 68.869 14.856 68.917 ;
     RECT  26.112 68.821 27.012 68.917 ;
     RECT  28.704 66.803 29.712 68.917 ;
     RECT  24 68.915 25.128 68.963 ;
     RECT  31.344 68.869 32.52 69.011 ;
     RECT  21.3 68.723 22.008 69.251 ;
     RECT  45.36 68.821 45.912 69.251 ;
     RECT  72.6 67.811 72.912 69.301 ;
     RECT  37.248 65.459 37.812 69.349 ;
     RECT  39.12 66.325 40.512 69.349 ;
     RECT  69.36 68.773 70.212 69.349 ;
     RECT  69.36 69.349 70.872 69.445 ;
     RECT  7.8 68.339 8.112 69.493 ;
     RECT  46.992 68.341 47.016 69.493 ;
     RECT  61.536 67.859 62.112 69.493 ;
     RECT  46.992 69.493 47.304 69.539 ;
     RECT  41.664 67.285 43.212 69.541 ;
     RECT  26.112 68.917 29.712 69.683 ;
     RECT  58.992 68.531 59.412 69.781 ;
     RECT  61.536 69.493 62.76 69.829 ;
     RECT  67.2 67.955 67.8 69.829 ;
     RECT  64.5 67.859 65.496 69.973 ;
     RECT  31.344 69.011 32.412 70.021 ;
     RECT  69.36 69.445 71.4 70.021 ;
     RECT  72.48 69.301 72.912 70.021 ;
     RECT  47.28 69.539 47.304 70.067 ;
     RECT  53.7 68.869 56.712 70.067 ;
     RECT  7.68 69.493 8.112 70.069 ;
     RECT  41.568 69.541 43.212 70.117 ;
     RECT  69.36 70.021 72.912 70.117 ;
     RECT  12.24 68.917 14.856 70.163 ;
     RECT  18.6 68.387 19.128 70.259 ;
     RECT  66.528 69.829 67.8 70.259 ;
     RECT  61.536 69.829 62.952 70.261 ;
     RECT  7.68 70.069 8.568 70.307 ;
     RECT  67.2 70.259 67.8 70.307 ;
     RECT  61.056 70.261 62.952 70.309 ;
     RECT  64.5 69.973 65.544 70.309 ;
     RECT  18.6 70.259 18.912 70.405 ;
     RECT  34.8 68.099 35.112 70.405 ;
     RECT  68.928 70.117 72.912 70.451 ;
     RECT  61.056 70.309 65.544 70.453 ;
     RECT  41.568 70.117 44.184 70.499 ;
     RECT  55.2 70.067 56.712 70.549 ;
     RECT  69.792 70.451 72.912 70.597 ;
     RECT  75.3 2.151 75.612 70.597 ;
     RECT  5.1 68.917 5.544 70.645 ;
     RECT  69.792 70.597 73.272 70.645 ;
     RECT  74.592 70.597 75.612 70.645 ;
     RECT  69.792 70.645 75.612 70.691 ;
     RECT  48.3 67.859 48.612 70.693 ;
     RECT  37.248 69.349 40.512 70.739 ;
     RECT  42.048 70.499 44.184 70.739 ;
     RECT  26.208 69.683 29.712 70.741 ;
     RECT  7.68 70.307 8.112 70.789 ;
     RECT  4.992 70.645 5.544 70.835 ;
     RECT  25.584 70.741 29.712 70.837 ;
     RECT  61.056 70.453 66.168 70.979 ;
     RECT  39.36 70.739 40.512 70.981 ;
     RECT  58.992 69.781 59.688 71.077 ;
     RECT  55.2 70.549 57.624 71.123 ;
     RECT  2.4 49.379 2.712 71.221 ;
     RECT  17.616 70.405 18.912 71.221 ;
     RECT  58.944 71.077 59.688 71.221 ;
     RECT  25.584 70.837 30.264 71.267 ;
     RECT  31.344 70.021 32.904 71.267 ;
     RECT  61.632 70.979 66.168 71.315 ;
     RECT  61.632 71.315 64.968 71.363 ;
     RECT  45.6 69.251 45.912 71.461 ;
     RECT  67.2 70.307 67.512 71.461 ;
     RECT  68.592 70.837 68.616 71.461 ;
     RECT  14.832 70.163 14.856 71.603 ;
     RECT  53.7 70.067 54.216 71.605 ;
     RECT  39.36 70.981 40.632 71.651 ;
     RECT  67.2 71.461 68.616 71.749 ;
     RECT  26.208 71.267 30.264 71.795 ;
     RECT  12.24 70.163 13.512 71.797 ;
     RECT  53.52 71.605 54.216 71.797 ;
     RECT  48.3 70.693 49.512 71.843 ;
     RECT  52.656 71.797 54.216 71.843 ;
     RECT  71.616 70.691 75.612 71.843 ;
     RECT  7.296 70.789 8.112 71.891 ;
     RECT  31.584 71.267 32.904 71.891 ;
     RECT  71.616 71.843 73.752 71.891 ;
     RECT  40.2 71.651 40.632 71.893 ;
     RECT  44.976 71.461 45.912 71.893 ;
     RECT  12.24 71.797 13.752 71.939 ;
     RECT  17.616 71.221 19.032 71.939 ;
     RECT  2.4 71.221 2.952 71.989 ;
     RECT  24 68.963 24.312 71.989 ;
     RECT  67.2 71.749 68.712 72.179 ;
     RECT  10.5 67.907 10.812 72.325 ;
     RECT  40.2 71.893 40.92 72.371 ;
     RECT  2.4 71.989 3.864 72.419 ;
     RECT  26.208 71.795 27.288 72.419 ;
     RECT  66.144 71.315 66.168 72.419 ;
     RECT  69.792 70.691 70.212 72.419 ;
     RECT  34.176 70.405 35.112 72.421 ;
     RECT  44.976 71.893 46.056 72.467 ;
     RECT  28.704 71.795 30.264 72.517 ;
     RECT  10.368 72.325 10.812 72.661 ;
     RECT  22.896 72.373 22.92 72.661 ;
     RECT  52.656 71.843 54.012 72.707 ;
     RECT  42.048 70.739 43.896 72.803 ;
     RECT  22.8 72.661 22.92 72.851 ;
     RECT  37.248 70.739 37.812 72.853 ;
     RECT  7.8 71.891 8.112 72.901 ;
     RECT  45.264 72.467 46.056 72.901 ;
     RECT  71.616 71.891 73.416 72.901 ;
     RECT  47.28 71.077 47.304 72.949 ;
     RECT  48.3 71.843 49.32 72.949 ;
     RECT  26.496 72.419 27.288 72.995 ;
     RECT  42.048 72.803 43.8 72.995 ;
     RECT  63.84 71.363 64.968 73.043 ;
     RECT  67.2 72.179 67.8 73.043 ;
     RECT  13.2 71.939 13.752 73.093 ;
     RECT  47.28 72.949 49.32 73.093 ;
     RECT  45.264 72.901 46.104 73.139 ;
     RECT  3.84 72.419 3.864 73.235 ;
     RECT  53.52 72.707 54.012 73.237 ;
     RECT  55.2 71.123 56.712 73.283 ;
     RECT  5.1 70.835 5.544 73.477 ;
     RECT  7.056 72.901 8.112 73.477 ;
     RECT  15.9 67.283 16.212 73.477 ;
     RECT  21.3 69.251 21.612 73.477 ;
     RECT  37.248 72.853 37.992 73.477 ;
     RECT  51 64.067 51.312 73.477 ;
     RECT  61.632 71.363 62.112 73.477 ;
     RECT  47.28 73.093 49.56 73.525 ;
     RECT  51 73.477 52.008 73.525 ;
     RECT  24 71.989 24.408 73.571 ;
     RECT  71.616 72.901 73.512 73.571 ;
     RECT  61.632 73.477 62.808 73.765 ;
     RECT  63.84 73.043 64.812 73.765 ;
     RECT  6.864 73.477 8.112 73.811 ;
     RECT  15.792 73.477 16.212 73.811 ;
     RECT  45.264 73.139 46.056 73.813 ;
     RECT  69.9 72.419 70.212 73.909 ;
     RECT  28.704 72.517 30.696 74.053 ;
     RECT  37.248 73.477 38.088 74.053 ;
     RECT  53.52 73.237 54.12 74.053 ;
     RECT  58.8 71.221 59.688 74.053 ;
     RECT  47.28 73.525 52.008 74.147 ;
     RECT  58.8 74.053 60.312 74.147 ;
     RECT  61.632 73.765 64.812 74.147 ;
     RECT  28.704 74.053 30.84 74.245 ;
     RECT  55.728 73.283 56.712 74.293 ;
     RECT  57.696 72.853 57.72 74.293 ;
     RECT  47.28 74.147 51.312 74.579 ;
     RECT  55.728 74.293 57.72 74.579 ;
     RECT  34.128 72.421 35.112 74.581 ;
     RECT  69.9 73.909 70.584 74.581 ;
     RECT  71.616 73.571 73.128 74.581 ;
     RECT  55.728 74.579 57 74.627 ;
     RECT  26.496 72.995 27.012 74.629 ;
     RECT  69.9 74.581 73.128 74.629 ;
     RECT  13.2 73.093 14.232 74.675 ;
     RECT  4.752 73.477 5.544 74.677 ;
     RECT  40.2 72.371 40.632 74.677 ;
     RECT  32.1 71.891 32.904 74.723 ;
     RECT  44.592 73.813 46.056 74.723 ;
     RECT  61.68 74.147 64.812 74.723 ;
     RECT  61.68 74.723 63.288 74.771 ;
     RECT  22.752 72.901 22.776 74.867 ;
     RECT  15.9 73.811 16.212 74.869 ;
     RECT  9.696 72.661 10.812 74.965 ;
     RECT  53.52 74.053 54.744 75.011 ;
     RECT  64.5 74.723 64.812 75.109 ;
     RECT  28.656 74.245 30.84 75.157 ;
     RECT  37.248 74.053 38.52 75.157 ;
     RECT  40.08 74.677 40.632 75.157 ;
     RECT  42.048 72.995 43.212 75.157 ;
     RECT  37.248 75.157 40.632 75.203 ;
     RECT  59.1 74.147 60.312 75.203 ;
     RECT  9.696 74.965 10.92 75.205 ;
     RECT  67.2 73.043 67.512 75.205 ;
     RECT  28.512 75.157 30.84 75.251 ;
     RECT  45.264 74.723 46.056 75.251 ;
     RECT  63.264 74.771 63.288 75.299 ;
     RECT  47.28 74.579 49.56 75.395 ;
     RECT  24 73.571 24.312 75.397 ;
     RECT  42.048 75.157 43.944 75.397 ;
     RECT  9.12 75.205 10.92 75.539 ;
     RECT  66.672 75.205 67.512 75.539 ;
     RECT  45.264 75.251 46.008 75.731 ;
     RECT  41.616 75.397 43.944 75.779 ;
     RECT  7.8 73.811 8.112 75.781 ;
     RECT  32.1 74.723 32.412 75.781 ;
     RECT  34.128 74.581 35.928 75.781 ;
     RECT  32.1 75.781 35.928 76.117 ;
     RECT  69.792 74.629 73.128 76.117 ;
     RECT  19.968 75.205 19.992 76.163 ;
     RECT  21.168 73.477 21.612 76.165 ;
     RECT  17.616 71.939 18.912 76.259 ;
     RECT  69.792 76.117 73.992 76.259 ;
     RECT  69.9 76.259 73.992 76.309 ;
     RECT  28.512 75.251 30.696 76.357 ;
     RECT  39.264 75.203 40.632 76.357 ;
     RECT  41.616 75.779 41.64 76.357 ;
     RECT  47.28 75.395 49.32 76.357 ;
     RECT  53.52 75.011 54.12 76.357 ;
     RECT  25.92 74.629 27.012 76.403 ;
     RECT  42.9 75.779 43.944 76.403 ;
     RECT  64.5 75.109 65.688 76.453 ;
     RECT  4.752 74.677 6.312 76.499 ;
     RECT  7.296 75.781 8.112 76.595 ;
     RECT  64.5 76.453 65.976 76.597 ;
     RECT  67.2 75.539 67.512 76.597 ;
     RECT  59.1 75.203 59.412 76.789 ;
     RECT  23.136 75.397 24.312 76.931 ;
     RECT  39.264 76.357 41.64 76.931 ;
     RECT  32.1 76.117 35.976 76.933 ;
     RECT  28.464 76.357 30.696 76.979 ;
     RECT  31.872 76.933 35.976 76.979 ;
     RECT  39.264 76.931 40.512 76.979 ;
     RECT  13.2 74.675 13.656 77.075 ;
     RECT  44.448 76.885 44.472 77.315 ;
     RECT  45.6 75.731 46.008 77.315 ;
     RECT  24 76.931 24.312 77.317 ;
     RECT  57.792 76.981 57.816 77.317 ;
     RECT  59.1 76.789 60.072 77.317 ;
     RECT  53.088 76.357 54.12 77.363 ;
     RECT  18.48 76.259 18.912 77.555 ;
     RECT  47.28 76.357 49.56 77.555 ;
     RECT  53.52 77.363 54.12 77.555 ;
     RECT  61.68 74.771 62.112 77.555 ;
     RECT  64.5 76.597 67.512 77.555 ;
     RECT  15.9 74.869 16.584 77.557 ;
     RECT  28.704 76.979 30.696 77.603 ;
     RECT  69.9 76.309 74.088 77.651 ;
     RECT  61.8 77.555 62.112 77.845 ;
     RECT  51 74.579 51.312 77.941 ;
     RECT  4.752 76.499 5.544 78.037 ;
     RECT  37.248 75.203 38.088 78.037 ;
     RECT  42.9 76.403 43.212 78.037 ;
     RECT  55.728 74.627 56.712 78.037 ;
     RECT  57.792 77.317 60.072 78.037 ;
     RECT  65.808 77.555 67.512 78.083 ;
     RECT  69.9 77.651 74.04 78.131 ;
     RECT  57.792 78.037 60.552 78.179 ;
     RECT  22.8 77.413 22.824 78.277 ;
     RECT  24 77.317 24.888 78.277 ;
     RECT  69.9 78.131 73.368 78.419 ;
     RECT  31.872 76.979 35.352 78.611 ;
     RECT  20.592 76.165 21.612 78.613 ;
     RECT  28.704 77.603 30.648 78.613 ;
     RECT  47.28 77.555 49.32 78.613 ;
     RECT  51 77.941 52.296 78.613 ;
     RECT  67.2 78.083 67.512 78.613 ;
     RECT  53.52 77.555 54.012 78.659 ;
     RECT  71.28 78.419 73.368 78.707 ;
     RECT  9.12 75.539 10.812 78.755 ;
     RECT  47.28 78.613 52.296 78.755 ;
     RECT  55.296 78.037 56.712 78.755 ;
     RECT  15.9 77.557 17.016 78.899 ;
     RECT  22.8 78.277 24.888 78.899 ;
     RECT  42.9 78.037 43.896 78.899 ;
     RECT  9.6 78.755 10.812 79.045 ;
     RECT  71.28 78.707 73.32 79.139 ;
     RECT  24 78.899 24.888 79.141 ;
     RECT  39.792 76.979 40.512 79.141 ;
     RECT  41.616 76.931 41.64 79.141 ;
     RECT  39.792 79.141 41.64 79.187 ;
     RECT  57.792 78.179 59.412 79.187 ;
     RECT  18.6 77.555 18.912 79.189 ;
     RECT  20.448 78.613 21.612 79.189 ;
     RECT  65.808 78.083 65.832 79.189 ;
     RECT  67.2 78.613 68.424 79.189 ;
     RECT  69.9 78.419 70.212 79.189 ;
     RECT  22.8 78.899 22.824 79.235 ;
     RECT  60.528 78.179 60.552 79.235 ;
     RECT  15.9 78.899 16.728 79.237 ;
     RECT  37.248 78.037 38.664 79.283 ;
     RECT  47.28 78.755 51.312 79.283 ;
     RECT  55.824 78.755 56.712 79.331 ;
     RECT  65.808 79.189 68.424 79.477 ;
     RECT  69.456 79.189 70.212 79.477 ;
     RECT  65.808 79.477 70.212 79.523 ;
     RECT  68.832 79.523 70.212 79.669 ;
     RECT  71.28 79.139 73.272 79.669 ;
     RECT  58.128 79.187 59.412 79.715 ;
     RECT  9.6 79.045 11.208 79.763 ;
     RECT  32.1 78.611 35.352 79.763 ;
     RECT  7.8 76.595 8.112 79.765 ;
     RECT  13.2 77.075 13.512 79.765 ;
     RECT  33.744 79.763 35.352 79.813 ;
     RECT  18.6 79.189 21.612 79.859 ;
     RECT  33.744 79.813 36.216 79.859 ;
     RECT  58.464 79.715 59.412 80.101 ;
     RECT  15.216 79.237 16.728 80.243 ;
     RECT  26.7 76.403 27.012 80.245 ;
     RECT  28.464 78.613 30.648 80.245 ;
     RECT  26.7 80.245 30.648 80.291 ;
     RECT  68.832 79.669 73.272 80.291 ;
     RECT  4.56 78.037 5.544 80.293 ;
     RECT  26.7 80.291 27.912 80.293 ;
     RECT  56.208 79.331 56.712 80.293 ;
     RECT  9.696 79.763 11.208 80.339 ;
     RECT  71.328 80.291 73.272 80.341 ;
     RECT  4.56 80.293 6.312 80.531 ;
     RECT  7.392 79.765 8.112 80.531 ;
     RECT  39.792 79.187 41.448 80.531 ;
     RECT  68.832 80.291 70.344 80.531 ;
     RECT  29.088 80.291 30.648 80.533 ;
     RECT  32.1 79.763 32.412 80.533 ;
     RECT  33.744 79.859 35.112 80.579 ;
     RECT  69.792 80.531 70.344 80.579 ;
     RECT  71.328 80.341 73.32 80.677 ;
     RECT  7.8 80.531 8.112 80.773 ;
     RECT  9.696 80.339 10.812 80.773 ;
     RECT  53.568 78.659 54.012 80.773 ;
     RECT  65.808 79.523 67.512 80.821 ;
     RECT  65.808 80.821 68.424 80.867 ;
     RECT  12.24 79.765 13.512 80.869 ;
     RECT  7.8 80.773 10.812 80.963 ;
     RECT  36.192 79.859 36.216 81.011 ;
     RECT  66.096 80.867 68.424 81.011 ;
     RECT  12.144 80.869 13.512 81.059 ;
     RECT  55.728 80.293 56.712 81.059 ;
     RECT  53.568 80.773 54.12 81.155 ;
     RECT  71.328 80.677 73.512 81.205 ;
     RECT  9.696 80.963 10.812 81.251 ;
     RECT  48.3 79.283 51.312 81.251 ;
     RECT  66.096 81.011 66.12 81.251 ;
     RECT  26.064 80.293 27.912 81.443 ;
     RECT  26.7 81.443 27.912 81.445 ;
     RECT  29.088 80.533 32.412 81.445 ;
     RECT  71.328 81.205 74.28 81.445 ;
     RECT  40.08 80.531 41.448 81.491 ;
     RECT  58.464 80.101 59.544 81.493 ;
     RECT  26.7 81.445 32.412 81.635 ;
     RECT  67.2 81.011 68.424 81.733 ;
     RECT  5.1 80.531 6.312 81.875 ;
     RECT  14.832 81.685 14.856 81.875 ;
     RECT  55.776 81.059 56.712 81.923 ;
     RECT  53.568 81.155 54.012 81.973 ;
     RECT  20.448 79.859 21.612 82.021 ;
     RECT  48.3 81.251 49.32 82.021 ;
     RECT  61.8 77.845 62.28 82.021 ;
     RECT  69.792 80.579 70.212 82.021 ;
     RECT  28.512 81.635 32.412 82.067 ;
     RECT  31.92 82.067 32.412 82.069 ;
     RECT  47.904 82.021 49.32 82.115 ;
     RECT  12.144 81.059 12.168 82.163 ;
     RECT  71.232 81.445 74.28 82.213 ;
     RECT  75.3 71.843 75.612 82.213 ;
     RECT  34.032 80.579 35.112 82.309 ;
     RECT  61.8 82.021 62.52 82.309 ;
     RECT  61.008 82.309 62.52 82.499 ;
     RECT  34.032 82.309 35.208 82.643 ;
     RECT  13.2 81.059 13.512 82.645 ;
     RECT  20.448 82.021 22.44 82.691 ;
     RECT  31.92 82.069 32.52 82.691 ;
     RECT  69.696 82.021 70.212 82.691 ;
     RECT  71.232 82.213 75.612 82.691 ;
     RECT  28.512 82.067 30.648 82.739 ;
     RECT  71.232 82.691 73.512 82.739 ;
     RECT  18.6 79.859 19.128 82.979 ;
     RECT  7.8 80.963 8.52 83.029 ;
     RECT  58.272 81.493 59.544 83.075 ;
     RECT  37.248 79.283 37.992 83.173 ;
     RECT  45.6 77.315 45.912 83.173 ;
     RECT  24 79.141 24.984 83.267 ;
     RECT  71.232 82.739 72.912 83.267 ;
     RECT  58.272 83.075 59.412 83.315 ;
     RECT  15.9 80.243 16.728 83.363 ;
     RECT  31.968 82.691 32.52 83.363 ;
     RECT  47.904 82.115 48.984 83.363 ;
     RECT  37.152 83.173 37.992 83.555 ;
     RECT  5.1 81.875 5.688 83.605 ;
     RECT  20.448 82.691 21.612 83.653 ;
     RECT  37.248 83.555 37.992 83.653 ;
     RECT  5.1 83.605 6.264 83.749 ;
     RECT  7.8 83.029 8.904 83.749 ;
     RECT  45.264 83.173 45.912 83.749 ;
     RECT  52.848 81.973 54.012 83.749 ;
     RECT  64.5 77.555 64.812 83.749 ;
     RECT  69.744 82.691 70.212 83.749 ;
     RECT  56.208 81.923 56.712 83.795 ;
     RECT  71.424 83.267 72.912 83.795 ;
     RECT  12.528 82.645 13.512 83.843 ;
     RECT  40.2 81.491 41.448 83.843 ;
     RECT  10.5 81.251 10.812 84.037 ;
     RECT  50.688 81.251 51.312 84.037 ;
     RECT  42.9 78.899 43.212 84.085 ;
     RECT  47.904 83.363 48.612 84.085 ;
     RECT  5.1 83.749 8.904 84.133 ;
     RECT  10.5 84.037 10.92 84.133 ;
     RECT  58.992 83.315 59.412 84.181 ;
     RECT  72.24 83.795 72.912 84.181 ;
     RECT  15.9 83.363 16.344 84.325 ;
     RECT  31.968 83.363 32.412 84.325 ;
     RECT  34.032 82.643 35.112 84.325 ;
     RECT  61.8 82.499 62.52 84.325 ;
     RECT  72.24 84.181 73.512 84.419 ;
     RECT  20.448 83.653 22.44 84.611 ;
     RECT  47.232 84.085 48.612 84.611 ;
     RECT  50.016 84.037 51.312 84.611 ;
     RECT  52.848 83.749 54.504 84.611 ;
     RECT  24 83.267 24.552 84.709 ;
     RECT  31.968 84.325 35.112 84.805 ;
     RECT  45.264 83.749 46.056 84.853 ;
     RECT  20.448 84.611 21.612 84.901 ;
     RECT  72.288 84.419 73.512 84.995 ;
     RECT  53.28 84.611 54.504 85.043 ;
     RECT  72.6 84.995 73.512 85.043 ;
     RECT  5.1 84.133 10.92 85.139 ;
     RECT  5.1 85.139 10.812 85.187 ;
     RECT  18.6 82.979 18.912 85.189 ;
     RECT  19.92 84.901 21.612 85.189 ;
     RECT  5.1 85.187 6.264 85.379 ;
     RECT  42.72 84.085 43.212 85.427 ;
     RECT  13.2 83.843 13.512 85.477 ;
     RECT  14.496 84.901 14.52 85.477 ;
     RECT  15.792 84.325 16.344 85.477 ;
     RECT  31.92 84.805 35.112 85.477 ;
     RECT  56.4 83.795 56.712 85.477 ;
     RECT  22.752 84.757 22.776 85.523 ;
     RECT  31.296 85.477 35.112 85.523 ;
     RECT  45.072 84.853 46.056 85.523 ;
     RECT  69.744 83.749 70.392 85.523 ;
     RECT  69.792 85.523 70.392 85.621 ;
     RECT  26.7 81.635 27.012 85.669 ;
     RECT  24 84.709 25.512 85.715 ;
     RECT  13.2 85.477 14.52 85.717 ;
     RECT  15.792 85.477 16.392 85.717 ;
     RECT  67.2 81.733 68.712 85.765 ;
     RECT  69.792 85.621 71.256 85.811 ;
     RECT  72.6 85.043 72.912 85.957 ;
     RECT  13.2 85.717 16.392 86.003 ;
     RECT  26.7 85.669 27.72 86.053 ;
     RECT  11.952 83.893 11.976 86.099 ;
     RECT  40.2 83.843 41.4 86.099 ;
     RECT  47.232 84.611 47.256 86.099 ;
     RECT  58.992 84.181 59.88 86.099 ;
     RECT  55.776 85.477 57.576 86.149 ;
     RECT  13.2 86.003 14.52 86.339 ;
     RECT  18.6 85.189 21.612 86.531 ;
     RECT  67.104 85.765 68.712 86.581 ;
     RECT  40.2 86.099 40.776 86.675 ;
     RECT  67.056 86.581 68.712 86.675 ;
     RECT  72.48 85.957 72.912 86.675 ;
     RECT  9.36 85.187 10.812 86.723 ;
     RECT  29.04 82.739 29.712 86.723 ;
     RECT  24 85.715 24.408 86.725 ;
     RECT  25.488 85.715 25.512 86.725 ;
     RECT  45.6 85.523 46.056 86.725 ;
     RECT  47.184 86.341 47.208 86.725 ;
     RECT  7.392 85.187 8.112 86.771 ;
     RECT  13.2 86.339 14.28 86.771 ;
     RECT  34.032 85.523 35.112 86.771 ;
     RECT  69.9 85.811 71.256 86.771 ;
     RECT  58.992 86.099 59.412 86.819 ;
     RECT  24 86.725 25.512 86.867 ;
     RECT  15.792 86.003 16.392 86.915 ;
     RECT  42.9 85.427 43.212 87.013 ;
     RECT  18.6 86.531 19.512 87.059 ;
     RECT  24 86.867 24.408 87.059 ;
     RECT  37.248 83.653 38.76 87.251 ;
     RECT  42.672 87.013 43.212 87.251 ;
     RECT  63.504 85.957 63.528 87.251 ;
     RECT  17.424 85.477 17.448 87.299 ;
     RECT  25.488 86.867 25.512 87.299 ;
     RECT  31.296 85.523 32.412 87.539 ;
     RECT  50.064 84.611 51.312 87.683 ;
     RECT  67.056 86.675 68.232 87.683 ;
     RECT  34.8 86.771 35.112 87.733 ;
     RECT  36.144 86.581 36.168 87.733 ;
     RECT  69.9 86.771 70.344 87.733 ;
     RECT  37.5 87.251 38.76 87.779 ;
     RECT  9.792 86.723 10.812 87.827 ;
     RECT  29.088 86.723 29.712 87.827 ;
     RECT  64.5 83.749 64.92 87.827 ;
     RECT  61.68 84.325 62.52 87.875 ;
     RECT  15.792 86.915 16.212 87.877 ;
     RECT  53.28 85.043 54.012 87.925 ;
     RECT  42.9 87.251 43.212 88.117 ;
     RECT  40.2 86.675 40.512 88.213 ;
     RECT  24 87.059 24.312 88.261 ;
     RECT  72.6 86.675 72.912 88.261 ;
     RECT  18.6 87.059 18.912 88.309 ;
     RECT  39.36 88.213 40.512 88.309 ;
     RECT  26.7 86.053 27.912 88.355 ;
     RECT  50.688 87.683 51.312 88.355 ;
     RECT  67.056 87.683 67.512 88.355 ;
     RECT  34.8 87.733 36.168 88.403 ;
     RECT  37.5 87.779 37.944 88.403 ;
     RECT  61.68 87.875 62.112 88.403 ;
     RECT  68.928 87.733 70.344 88.403 ;
     RECT  48.3 84.611 48.612 88.741 ;
     RECT  52.848 87.925 54.012 88.789 ;
     RECT  55.584 86.149 57.576 88.789 ;
     RECT  52.848 88.789 57.576 88.835 ;
     RECT  5.1 85.379 6.072 88.883 ;
     RECT  68.928 88.403 70.212 88.883 ;
     RECT  10.5 87.827 10.812 88.885 ;
     RECT  13.2 86.771 13.512 88.885 ;
     RECT  23.088 88.261 24.312 88.931 ;
     RECT  67.2 88.355 67.512 88.933 ;
     RECT  42.9 88.117 43.944 88.979 ;
     RECT  53.568 88.835 57.576 88.979 ;
     RECT  71.424 88.309 71.448 88.979 ;
     RECT  20.784 86.531 21.612 89.027 ;
     RECT  45.6 86.725 47.208 89.027 ;
     RECT  72.6 88.261 73.512 89.027 ;
     RECT  15.744 87.877 16.212 89.173 ;
     RECT  13.104 88.885 13.512 89.459 ;
     RECT  31.536 87.539 32.412 89.459 ;
     RECT  53.568 88.979 56.712 89.459 ;
     RECT  15.456 89.173 16.212 89.699 ;
     RECT  53.568 89.459 54.012 89.843 ;
     RECT  10.5 88.885 11.16 89.987 ;
     RECT  36.144 88.403 36.168 90.035 ;
     RECT  18.6 88.309 19.8 90.083 ;
     RECT  26.7 88.355 27.624 90.083 ;
     RECT  45.6 89.027 46.584 90.083 ;
     RECT  48.3 88.741 49.128 90.083 ;
     RECT  39.36 88.309 41.064 90.371 ;
     RECT  67.2 88.933 67.8 90.371 ;
     RECT  40.2 90.371 41.064 90.515 ;
     RECT  55.584 89.459 56.712 90.515 ;
     RECT  2.4 72.419 2.712 90.729 ;
     RECT  5.1 88.883 5.412 90.729 ;
     RECT  7.8 86.771 8.112 90.729 ;
     RECT  10.5 89.987 10.812 90.729 ;
     RECT  13.2 89.459 13.512 90.729 ;
     RECT  15.9 89.699 16.212 90.729 ;
     RECT  18.6 90.083 18.912 90.729 ;
     RECT  21.3 89.027 21.612 90.729 ;
     RECT  24 88.931 24.312 90.729 ;
     RECT  26.7 90.083 27.012 90.729 ;
     RECT  29.4 87.827 29.712 90.729 ;
     RECT  32.1 89.459 32.412 90.729 ;
     RECT  34.8 88.403 35.112 90.729 ;
     RECT  37.5 88.403 37.812 90.729 ;
     RECT  40.2 90.515 40.512 90.729 ;
     RECT  42.9 88.979 43.212 90.729 ;
     RECT  45.6 90.083 45.912 90.729 ;
     RECT  48.3 90.083 48.612 90.729 ;
     RECT  51 88.355 51.312 90.729 ;
     RECT  53.7 89.843 54.012 90.729 ;
     RECT  56.4 90.515 56.712 90.729 ;
     RECT  59.1 86.819 59.412 90.729 ;
     RECT  61.8 88.403 62.112 90.729 ;
     RECT  64.5 87.827 64.812 90.729 ;
     RECT  67.2 90.371 67.512 90.729 ;
     RECT  69.9 88.883 70.212 90.729 ;
     RECT  72.6 89.027 72.912 90.729 ;
     RECT  75.3 82.691 75.612 90.729 ;
     RECT  2.4 90.729 2.52 90.743 ;
     RECT  5.1 90.729 5.22 90.743 ;
     RECT  7.8 90.729 7.92 90.743 ;
     RECT  10.5 90.729 10.62 90.743 ;
     RECT  13.2 90.729 13.32 90.743 ;
     RECT  15.9 90.729 16.02 90.743 ;
     RECT  18.6 90.729 18.72 90.743 ;
     RECT  21.3 90.729 21.42 90.743 ;
     RECT  24 90.729 24.12 90.743 ;
     RECT  26.7 90.729 26.82 90.743 ;
     RECT  29.4 90.729 29.52 90.743 ;
     RECT  32.1 90.729 32.22 90.743 ;
     RECT  34.8 90.729 34.92 90.743 ;
     RECT  37.5 90.729 37.62 90.743 ;
     RECT  40.2 90.729 40.32 90.743 ;
     RECT  42.9 90.729 43.02 90.743 ;
     RECT  45.6 90.729 45.72 90.743 ;
     RECT  48.3 90.729 48.42 90.743 ;
     RECT  51 90.729 51.12 90.743 ;
     RECT  53.7 90.729 53.82 90.743 ;
     RECT  56.4 90.729 56.52 90.743 ;
     RECT  59.1 90.729 59.22 90.743 ;
     RECT  61.8 90.729 61.92 90.743 ;
     RECT  64.5 90.729 64.62 90.743 ;
     RECT  67.2 90.729 67.32 90.743 ;
     RECT  69.9 90.729 70.02 90.743 ;
     RECT  72.6 90.729 72.72 90.743 ;
     RECT  75.3 90.729 75.42 90.743 ;
     RECT  37.812 2.197 38.88 3.301 ;
     RECT  38.904 2.197 40.2 4.261 ;
     RECT  30.888 2.485 32.1 3.539 ;
     RECT  14.904 2.677 15.9 2.821 ;
     RECT  40.512 2.725 41.616 3.443 ;
     RECT  41.64 2.725 42.9 3.443 ;
     RECT  9.096 2.821 10.5 4.451 ;
     RECT  42.576 3.443 42.9 4.549 ;
     RECT  44.832 3.443 45.6 4.357 ;
     RECT  48.612 3.443 48.744 4.405 ;
     RECT  21.612 3.637 22.8 4.499 ;
     RECT  22.824 3.637 24 3.829 ;
     RECT  64.968 3.925 66.144 5.171 ;
     RECT  66.168 3.971 67.2 5.171 ;
     RECT  3.432 3.973 4.512 4.691 ;
     RECT  11.16 3.973 12.432 4.163 ;
     RECT  27.96 3.973 29.4 5.363 ;
     RECT  14.136 4.115 15.408 4.595 ;
     RECT  11.112 4.163 12.432 4.307 ;
     RECT  11.064 4.307 12.432 5.075 ;
     RECT  44.136 4.357 45.6 4.549 ;
     RECT  17.064 4.453 18.24 4.691 ;
     RECT  21.612 4.499 23.28 5.749 ;
     RECT  54.168 4.499 54.264 5.653 ;
     RECT  59.832 4.499 60.024 5.461 ;
     RECT  57.288 4.501 58.656 5.507 ;
     RECT  14.136 4.595 15.9 5.797 ;
     RECT  71.808 4.595 72.6 5.605 ;
     RECT  17.064 4.691 18.6 5.267 ;
     RECT  10.92 5.075 12.432 5.123 ;
     RECT  10.92 5.123 11.4 6.181 ;
     RECT  16.344 5.267 18.6 5.461 ;
     RECT  28.944 5.363 29.4 6.805 ;
     RECT  19.8 5.365 21.168 6.755 ;
     RECT  16.344 5.461 17.568 5.747 ;
     RECT  17.592 5.461 18.6 5.747 ;
     RECT  59.928 5.461 60.024 5.701 ;
     RECT  57.288 5.507 59.1 6.517 ;
     RECT  70.584 5.605 72.6 5.893 ;
     RECT  55.032 5.653 56.4 6.277 ;
     RECT  59.928 5.701 61.008 5.893 ;
     RECT  16.344 5.747 18.6 6.805 ;
     RECT  21.612 5.749 22.8 6.083 ;
     RECT  14.52 5.797 15.9 6.323 ;
     RECT  71.4 5.893 72.6 6.229 ;
     RECT  21.612 6.083 23.136 6.949 ;
     RECT  37.812 6.083 37.992 7.381 ;
     RECT  51.624 6.085 52.896 6.275 ;
     RECT  44.232 6.131 45.6 8.389 ;
     RECT  48.612 6.179 49.416 6.229 ;
     RECT  48.612 6.229 50.784 6.805 ;
     RECT  55.416 6.277 56.4 7.043 ;
     RECT  14.136 6.323 15.9 6.659 ;
     RECT  60.744 6.323 61.8 7.139 ;
     RECT  57.288 6.517 58.464 6.563 ;
     RECT  13.512 6.659 15.9 7.429 ;
     RECT  16.824 6.805 18.6 6.949 ;
     RECT  48.612 6.805 50.064 8.243 ;
     RECT  2.712 6.853 3.936 7.475 ;
     RECT  22.104 6.949 23.136 7.907 ;
     RECT  55.032 7.043 56.4 11.365 ;
     RECT  17.112 7.379 18.24 7.955 ;
     RECT  9.096 7.429 10.5 13.093 ;
     RECT  13.512 7.429 14.832 7.571 ;
     RECT  14.856 7.429 15.9 7.571 ;
     RECT  13.512 7.571 15.9 8.197 ;
     RECT  21.612 7.907 23.136 8.195 ;
     RECT  40.512 7.909 41.568 8.483 ;
     RECT  41.592 7.909 42.9 8.483 ;
     RECT  62.112 8.149 63.504 8.675 ;
     RECT  63.528 8.149 64.5 8.675 ;
     RECT  14.232 8.197 15.9 8.965 ;
     RECT  10.812 8.243 10.92 9.541 ;
     RECT  44.328 8.389 45.6 8.437 ;
     RECT  44.424 8.437 45.6 10.741 ;
     RECT  56.712 8.437 58.032 10.165 ;
     RECT  43.212 8.483 44.304 9.155 ;
     RECT  6.312 8.533 7.8 10.259 ;
     RECT  32.52 8.963 33.984 11.845 ;
     RECT  14.232 8.965 15.408 10.883 ;
     RECT  43.212 9.155 44.4 10.981 ;
     RECT  11.592 9.541 12.96 11.749 ;
     RECT  64.92 9.827 64.968 11.317 ;
     RECT  2.712 10.069 3.984 10.979 ;
     RECT  56.904 10.165 58.032 10.883 ;
     RECT  51.312 10.597 52.416 12.227 ;
     RECT  52.44 10.597 53.7 11.461 ;
     RECT  54.012 10.643 55.008 13.525 ;
     RECT  56.712 10.883 58.032 12.229 ;
     RECT  63.144 10.981 64.5 12.371 ;
     RECT  22.824 11.267 24 13.715 ;
     RECT  55.176 11.365 56.4 11.795 ;
     RECT  59.64 11.365 60.816 13.043 ;
     RECT  52.488 11.461 53.7 14.149 ;
     RECT  27.012 11.653 28.512 12.659 ;
     RECT  55.032 11.795 56.4 13.571 ;
     RECT  32.76 11.845 33.984 12.515 ;
     RECT  43.32 12.131 44.4 13.139 ;
     RECT  51.312 12.227 52.464 14.675 ;
     RECT  57.624 12.275 58.704 12.515 ;
     RECT  63.048 12.371 64.5 13.573 ;
     RECT  32.412 12.515 33.984 13.045 ;
     RECT  35.112 12.515 35.304 13.621 ;
     RECT  21.612 12.563 22.752 14.387 ;
     RECT  40.512 12.563 41.16 13.957 ;
     RECT  27.012 12.659 28.896 12.853 ;
     RECT  27.384 12.853 28.896 14.485 ;
     RECT  13.512 12.949 14.832 13.235 ;
     RECT  14.856 12.949 15.9 13.235 ;
     RECT  59.64 13.043 59.88 13.381 ;
     RECT  32.412 13.045 33.648 14.339 ;
     RECT  65.832 13.045 67.104 13.715 ;
     RECT  9.144 13.093 10.5 13.283 ;
     RECT  43.32 13.139 44.736 15.251 ;
     RECT  13.512 13.235 15.9 13.813 ;
     RECT  9.096 13.283 10.5 13.621 ;
     RECT  56.304 13.571 56.4 14.917 ;
     RECT  63.336 13.573 64.5 16.021 ;
     RECT  9.096 13.621 10.32 15.493 ;
     RECT  22.776 13.715 24 14.387 ;
     RECT  13.512 13.813 14.688 15.733 ;
     RECT  14.712 13.813 15.9 16.019 ;
     RECT  30.264 13.813 31.344 15.779 ;
     RECT  25.464 14.053 26.7 15.107 ;
     RECT  2.712 14.101 4.08 15.539 ;
     RECT  41.256 14.101 42.768 14.917 ;
     RECT  70.488 14.291 71.856 15.443 ;
     RECT  67.104 14.339 67.2 15.589 ;
     RECT  27.384 14.485 28.512 14.867 ;
     RECT  34.272 14.531 34.704 15.637 ;
     RECT  46.152 14.773 47.328 15.589 ;
     RECT  48.612 14.773 49.584 18.133 ;
     RECT  49.608 14.773 50.688 16.019 ;
     RECT  27.012 14.867 28.512 17.075 ;
     RECT  41.544 14.917 42.768 16.019 ;
     RECT  40.512 14.963 41.52 16.547 ;
     RECT  25.272 15.107 26.7 16.211 ;
     RECT  43.32 15.251 45.6 16.501 ;
     RECT  35.976 15.349 37.5 16.355 ;
     RECT  9.144 15.493 10.32 15.875 ;
     RECT  65.736 15.589 67.2 16.835 ;
     RECT  30.264 15.779 31.728 19.045 ;
     RECT  9.096 15.875 10.32 16.019 ;
     RECT  19.944 15.973 21.3 17.651 ;
     RECT  8.112 16.019 8.232 17.173 ;
     RECT  14.424 16.019 15.9 19.811 ;
     RECT  41.544 16.019 42.9 16.547 ;
     RECT  46.872 16.019 48.3 17.845 ;
     RECT  49.608 16.019 51 18.469 ;
     RECT  63.336 16.021 64.368 16.499 ;
     RECT  36.768 16.355 37.5 17.077 ;
     RECT  63.048 16.499 64.368 16.979 ;
     RECT  44.136 16.501 45.6 17.795 ;
     RECT  51.312 16.549 52.512 17.029 ;
     RECT  16.92 16.789 18.24 17.123 ;
     RECT  65.064 16.835 67.2 18.181 ;
     RECT  63.048 16.979 64.5 18.709 ;
     RECT  51.312 17.029 52.464 17.747 ;
     RECT  54.744 17.029 56.064 17.747 ;
     RECT  27.012 17.075 28.896 18.037 ;
     RECT  59.412 17.077 60.72 17.219 ;
     RECT  34.224 17.171 34.272 18.565 ;
     RECT  52.536 17.219 53.7 18.419 ;
     RECT  59.412 17.219 61.584 17.939 ;
     RECT  38.808 17.605 40.2 20.339 ;
     RECT  5.412 17.701 6.864 17.987 ;
     RECT  51.312 17.747 52.512 18.419 ;
     RECT  47.016 17.845 48.3 18.805 ;
     RECT  59.412 17.939 61.8 18.469 ;
     RECT  27.624 18.037 28.896 18.851 ;
     RECT  65.736 18.181 67.2 21.589 ;
     RECT  53.472 18.419 53.7 19.669 ;
     RECT  49.896 18.469 51 19.237 ;
     RECT  60.36 18.469 61.8 18.851 ;
     RECT  32.412 18.565 33.408 18.949 ;
     RECT  56.712 18.565 57.936 19.333 ;
     RECT  63.048 18.709 64.368 19.667 ;
     RECT  47.112 18.805 48.3 19.045 ;
     RECT  8.112 18.851 8.232 20.293 ;
     RECT  60.312 18.851 61.8 21.683 ;
     RECT  30.36 19.045 31.728 23.939 ;
     RECT  47.256 19.045 48.3 20.197 ;
     RECT  32.664 19.379 34.272 20.485 ;
     RECT  16.212 19.381 17.664 21.349 ;
     RECT  19.32 19.381 20.64 20.579 ;
     RECT  48.612 19.427 49.872 19.475 ;
     RECT  48.612 19.475 50.784 20.965 ;
     RECT  63.048 19.667 64.5 21.155 ;
     RECT  25.56 19.909 26.7 21.971 ;
     RECT  47.304 20.197 48.3 21.683 ;
     RECT  32.664 20.485 34.176 21.155 ;
     RECT  19.32 20.579 21.168 21.637 ;
     RECT  48.612 20.965 49.824 23.701 ;
     RECT  5.412 21.059 5.544 21.301 ;
     RECT  32.664 21.155 34.272 21.205 ;
     RECT  32.856 21.205 34.272 21.779 ;
     RECT  5.412 21.301 6.864 21.637 ;
     RECT  16.212 21.349 17.568 22.547 ;
     RECT  17.592 21.395 18.6 22.547 ;
     RECT  22.536 21.541 24 24.083 ;
     RECT  66.168 21.589 67.2 23.363 ;
     RECT  64.92 21.635 66.144 22.499 ;
     RECT  5.412 21.637 6.816 22.501 ;
     RECT  19.992 21.637 21.168 23.269 ;
     RECT  27.72 21.637 28.896 24.469 ;
     RECT  46.872 21.683 48.3 23.845 ;
     RECT  56.712 21.683 57.936 22.835 ;
     RECT  68.424 22.069 69.9 22.741 ;
     RECT  43.944 22.165 44.976 23.891 ;
     RECT  35.88 22.261 37.392 22.787 ;
     RECT  64.812 22.499 66.144 23.363 ;
     RECT  6.312 22.547 7.8 23.555 ;
     RECT  16.212 22.547 18.6 23.317 ;
     RECT  2.712 22.741 3.984 23.891 ;
     RECT  4.008 22.741 5.1 23.891 ;
     RECT  62.112 22.741 63.168 23.795 ;
     RECT  63.192 22.741 64.5 23.795 ;
     RECT  16.212 23.317 17.472 28.213 ;
     RECT  17.496 23.317 18.6 29.699 ;
     RECT  49.848 23.507 51 23.843 ;
     RECT  14.424 23.701 15.456 23.747 ;
     RECT  14.424 23.747 15.9 26.627 ;
     RECT  62.112 23.795 62.232 25.285 ;
     RECT  63.84 23.795 64.5 25.093 ;
     RECT  49.512 23.843 51 25.331 ;
     RECT  25.176 23.845 26.7 24.515 ;
     RECT  46.872 23.845 47.952 25.715 ;
     RECT  43.944 23.891 45.6 24.131 ;
     RECT  30.264 23.939 31.728 26.725 ;
     RECT  45.024 24.131 45.6 25.045 ;
     RECT  35.112 24.419 35.208 24.469 ;
     RECT  35.112 24.469 36.432 25.667 ;
     RECT  24.312 24.515 26.7 25.285 ;
     RECT  58.656 24.563 58.848 25.573 ;
     RECT  33.672 24.757 34.8 27.347 ;
     RECT  24.312 25.285 25.536 25.573 ;
     RECT  25.56 25.285 26.7 28.453 ;
     RECT  28.248 25.331 29.232 25.523 ;
     RECT  50.16 25.331 51 26.677 ;
     RECT  2.712 25.477 3.936 25.763 ;
     RECT  3.96 25.477 5.1 25.763 ;
     RECT  27.72 25.523 29.232 29.363 ;
     RECT  24.408 25.573 25.536 25.861 ;
     RECT  21.72 25.621 22.752 26.819 ;
     RECT  22.776 25.621 24 26.819 ;
     RECT  46.872 25.715 48 27.491 ;
     RECT  15.792 26.627 15.9 26.869 ;
     RECT  30.264 26.725 31.344 28.115 ;
     RECT  37.152 26.771 37.248 28.261 ;
     RECT  23.328 26.819 24 27.301 ;
     RECT  33.336 27.347 34.8 29.605 ;
     RECT  57.624 27.349 58.656 28.163 ;
     RECT  50.16 27.395 51 27.589 ;
     RECT  46.872 27.491 48.3 30.275 ;
     RECT  49.272 27.589 51 28.453 ;
     RECT  40.512 27.685 41.904 28.213 ;
     RECT  11.448 27.829 12.624 28.835 ;
     RECT  30.264 28.115 31.728 31.045 ;
     RECT  16.212 28.213 17.376 28.789 ;
     RECT  40.872 28.213 41.904 28.451 ;
     RECT  37.152 28.451 37.248 29.605 ;
     RECT  40.512 28.451 41.904 29.413 ;
     RECT  24.312 28.547 25.536 30.181 ;
     RECT  54.012 28.547 54.168 29.701 ;
     RECT  35.112 28.691 35.208 29.605 ;
     RECT  9.144 28.741 10.5 29.027 ;
     RECT  16.212 28.931 17.376 30.037 ;
     RECT  37.812 29.123 37.944 30.421 ;
     RECT  27.144 29.363 29.232 29.605 ;
     RECT  14.232 29.365 15.552 29.605 ;
     RECT  27.144 29.605 28.368 30.611 ;
     RECT  33.672 29.605 34.8 30.853 ;
     RECT  35.112 29.605 36.384 36.469 ;
     RECT  23.328 29.651 23.712 30.083 ;
     RECT  17.4 29.699 18.6 32.483 ;
     RECT  54.744 29.701 55.92 29.843 ;
     RECT  54.012 29.843 55.92 31.285 ;
     RECT  63.144 30.037 64.5 30.661 ;
     RECT  23.328 30.083 24 30.613 ;
     RECT  62.112 30.083 63.12 30.995 ;
     RECT  24.312 30.181 25.344 31.381 ;
     RECT  16.344 30.227 17.376 31.285 ;
     RECT  45.912 30.275 48.3 31.621 ;
     RECT  49.272 30.275 51 31.621 ;
     RECT  40.824 30.563 41.904 32.531 ;
     RECT  22.152 30.613 24 31.141 ;
     RECT  63.144 30.661 64.368 30.803 ;
     RECT  66.12 30.709 67.2 31.715 ;
     RECT  41.928 30.803 42.9 32.531 ;
     RECT  63.144 30.803 64.5 30.949 ;
     RECT  25.368 30.851 26.7 32.915 ;
     RECT  8.112 30.947 8.664 31.957 ;
     RECT  63.24 30.949 64.5 31.955 ;
     RECT  62.112 30.995 63.216 31.955 ;
     RECT  22.152 31.141 23.472 32.243 ;
     RECT  54.744 31.285 55.92 31.331 ;
     RECT  46.008 31.621 48.3 31.765 ;
     RECT  65.352 31.715 67.2 32.197 ;
     RECT  46.008 31.765 46.992 31.811 ;
     RECT  47.016 31.765 48.3 33.539 ;
     RECT  45.912 31.811 46.992 33.539 ;
     RECT  16.344 31.859 17.376 32.483 ;
     RECT  33.576 31.955 34.608 32.771 ;
     RECT  8.112 31.957 9.12 32.099 ;
     RECT  9.144 31.957 10.5 32.099 ;
     RECT  10.272 32.099 10.5 33.589 ;
     RECT  38.568 32.101 39.888 32.869 ;
     RECT  65.352 32.197 66.432 34.643 ;
     RECT  22.152 32.243 22.2 33.589 ;
     RECT  18.912 32.437 19.92 33.635 ;
     RECT  16.344 32.483 16.392 33.253 ;
     RECT  40.824 32.531 40.92 33.349 ;
     RECT  33.576 32.771 34.704 34.741 ;
     RECT  38.76 32.869 39.888 33.493 ;
     RECT  25.08 32.915 26.7 33.683 ;
     RECT  43.212 33.013 44.64 35.363 ;
     RECT  58.56 33.155 58.656 34.117 ;
     RECT  30.264 33.539 31.728 35.459 ;
     RECT  48.096 33.539 48.3 34.741 ;
     RECT  20.448 33.635 20.832 34.741 ;
     RECT  24.408 33.683 26.7 34.213 ;
     RECT  37.812 33.683 39.312 34.835 ;
     RECT  27.012 33.875 27.336 34.741 ;
     RECT  6.552 34.069 7.8 36.563 ;
     RECT  48.612 34.117 50.112 34.835 ;
     RECT  10.272 34.211 10.5 35.317 ;
     RECT  24.408 34.213 25.488 34.933 ;
     RECT  25.512 34.213 26.7 35.747 ;
     RECT  27.012 34.741 28.512 35.747 ;
     RECT  33.576 34.741 34.656 35.651 ;
     RECT  39.648 34.835 39.888 35.845 ;
     RECT  59.412 34.933 60.768 36.803 ;
     RECT  5.544 34.979 6.528 36.563 ;
     RECT  62.112 35.077 63.456 35.939 ;
     RECT  63.48 35.077 64.5 35.939 ;
     RECT  24.408 35.219 25.488 35.747 ;
     RECT  56.712 35.459 56.904 36.949 ;
     RECT  60.792 35.459 61.8 36.803 ;
     RECT  67.512 35.461 68.832 36.853 ;
     RECT  68.856 35.461 69.9 35.509 ;
     RECT  19.032 35.605 20.448 36.037 ;
     RECT  24.408 35.747 24.696 35.939 ;
     RECT  27.012 35.747 27.144 36.997 ;
     RECT  29.28 35.747 29.4 36.901 ;
     RECT  56.304 35.747 56.4 37.045 ;
     RECT  9.096 35.845 10.272 36.275 ;
     RECT  24.312 35.939 24.696 36.901 ;
     RECT  68.856 35.939 69.9 36.995 ;
     RECT  19.368 36.037 20.448 36.515 ;
     RECT  9.096 36.275 10.5 36.419 ;
     RECT  8.112 36.419 10.5 36.613 ;
     RECT  35.112 36.469 36.288 36.997 ;
     RECT  41.544 36.469 42.9 38.147 ;
     RECT  5.544 36.563 7.8 36.901 ;
     RECT  8.112 36.613 9.12 36.899 ;
     RECT  9.144 36.613 10.5 36.899 ;
     RECT  8.112 36.899 10.5 37.573 ;
     RECT  5.544 36.901 7.392 37.043 ;
     RECT  37.812 36.949 38.784 40.019 ;
     RECT  56.712 36.949 57.792 38.195 ;
     RECT  68.76 36.995 69.9 38.435 ;
     RECT  35.304 36.997 36.288 37.139 ;
     RECT  5.544 37.043 7.8 37.045 ;
     RECT  6.024 37.045 7.8 37.859 ;
     RECT  54.744 37.045 55.872 37.091 ;
     RECT  54.12 37.091 55.872 38.149 ;
     RECT  35.112 37.139 36.288 38.917 ;
     RECT  52.944 37.283 53.28 38.005 ;
     RECT  8.112 37.573 9.264 39.829 ;
     RECT  9.288 37.573 10.5 40.405 ;
     RECT  5.544 37.859 7.8 38.149 ;
     RECT  27.012 37.907 27.144 38.533 ;
     RECT  50.688 37.907 51 39.253 ;
     RECT  52.008 38.005 53.28 38.147 ;
     RECT  5.544 38.149 6.864 38.387 ;
     RECT  54.504 38.149 55.872 38.819 ;
     RECT  64.812 38.149 65.808 39.059 ;
     RECT  65.832 38.149 67.2 38.965 ;
     RECT  27.012 38.533 28.224 39.491 ;
     RECT  28.248 38.533 29.28 38.965 ;
     RECT  59.412 38.677 60.816 39.395 ;
     RECT  62.112 38.723 62.232 38.725 ;
     RECT  62.112 38.725 63.504 39.779 ;
     RECT  63.528 38.725 64.5 39.779 ;
     RECT  11.208 38.821 12.672 39.779 ;
     RECT  35.208 38.917 36.288 38.963 ;
     RECT  35.208 38.963 36.384 39.539 ;
     RECT  33.624 38.965 34.8 41.557 ;
     RECT  65.832 38.965 67.104 39.059 ;
     RECT  38.808 39.203 39.888 40.019 ;
     RECT  22.776 39.253 24 39.971 ;
     RECT  24.696 39.253 25.68 44.483 ;
     RECT  25.704 39.253 26.7 45.731 ;
     RECT  50.688 39.253 50.88 39.301 ;
     RECT  28.248 39.347 29.4 39.491 ;
     RECT  7.152 39.395 7.8 40.405 ;
     RECT  54.12 39.491 54.504 40.549 ;
     RECT  35.112 39.539 36.384 42.709 ;
     RECT  67.104 39.539 67.2 40.693 ;
     RECT  64.368 39.779 64.5 40.597 ;
     RECT  67.512 39.779 67.608 41.221 ;
     RECT  22.104 39.971 22.152 41.221 ;
     RECT  37.812 40.019 38.184 40.981 ;
     RECT  48.048 40.019 48.3 40.981 ;
     RECT  13.512 40.357 14.832 41.557 ;
     RECT  70.68 40.403 70.776 41.605 ;
     RECT  2.712 40.405 3.984 41.075 ;
     RECT  4.008 40.405 5.1 41.075 ;
     RECT  5.544 40.405 6.72 41.747 ;
     RECT  6.744 40.405 7.8 41.747 ;
     RECT  9.288 40.405 10.368 41.699 ;
     RECT  8.112 40.499 9.264 43.379 ;
     RECT  54.12 40.549 55.2 40.597 ;
     RECT  55.224 40.549 56.4 42.803 ;
     RECT  54.12 40.597 55.104 40.691 ;
     RECT  54.012 40.691 55.104 41.891 ;
     RECT  64.812 40.693 66 41.651 ;
     RECT  66.024 40.693 67.2 41.651 ;
     RECT  16.44 41.075 16.536 42.037 ;
     RECT  13.656 41.557 14.832 42.659 ;
     RECT  49.56 41.557 50.592 44.099 ;
     RECT  18.48 41.651 18.6 42.709 ;
     RECT  64.812 41.651 67.2 42.997 ;
     RECT  9.288 41.699 10.5 43.379 ;
     RECT  54.012 41.891 55.2 42.803 ;
     RECT  45.912 42.133 47.376 42.755 ;
     RECT  13.608 42.659 14.832 42.803 ;
     RECT  10.812 42.709 12 43.717 ;
     RECT  14.856 42.755 15.9 42.803 ;
     RECT  54.012 42.803 56.4 43.285 ;
     RECT  64.812 42.997 66 44.099 ;
     RECT  66.024 42.997 67.2 44.099 ;
     RECT  54.984 43.285 56.4 44.099 ;
     RECT  33.624 43.523 34.8 43.763 ;
     RECT  5.544 43.525 6.816 43.861 ;
     RECT  51.312 43.619 51.96 44.917 ;
     RECT  32.808 43.763 33.096 45.205 ;
     RECT  5.688 43.861 6.816 44.723 ;
     RECT  35.112 43.907 36.384 51.829 ;
     RECT  58.56 43.955 58.656 44.437 ;
     RECT  49.56 44.099 51 44.483 ;
     RECT  37.812 44.437 39.312 44.819 ;
     RECT  57.624 44.437 58.656 45.059 ;
     RECT  10.812 44.483 12.096 46.933 ;
     RECT  24.312 44.483 25.68 45.731 ;
     RECT  52.2 44.917 53.7 46.211 ;
     RECT  57.624 45.059 59.1 46.211 ;
     RECT  33.096 45.493 34.176 45.731 ;
     RECT  70.344 45.683 70.488 46.751 ;
     RECT  24.312 45.731 24.696 47.173 ;
     RECT  21.168 46.259 21.3 47.701 ;
     RECT  27.012 46.259 27.144 47.221 ;
     RECT  12.12 46.355 13.2 47.749 ;
     RECT  8.112 46.547 8.568 47.845 ;
     RECT  70.392 46.751 70.488 46.933 ;
     RECT  10.812 46.933 11.904 47.123 ;
     RECT  70.392 47.075 70.488 47.123 ;
     RECT  10.812 47.123 12.096 48.421 ;
     RECT  70.212 47.123 70.488 47.749 ;
     RECT  22.728 47.269 24 50.533 ;
     RECT  30.696 47.269 31.968 48.467 ;
     RECT  37.812 47.269 39.168 47.845 ;
     RECT  40.728 47.363 41.016 47.845 ;
     RECT  45.216 47.363 45.6 48.421 ;
     RECT  12.12 47.749 13.104 48.947 ;
     RECT  70.212 47.749 71.52 48.277 ;
     RECT  71.544 47.749 72.6 48.229 ;
     RECT  56.712 47.843 56.808 49.285 ;
     RECT  6.264 47.845 7.392 48.515 ;
     RECT  40.728 47.845 42.24 49.043 ;
     RECT  15.36 47.891 15.9 48.421 ;
     RECT  64.812 47.891 64.92 49.189 ;
     RECT  70.212 48.277 71.472 48.997 ;
     RECT  10.812 48.421 12.048 48.757 ;
     RECT  13.512 48.421 14.784 49.237 ;
     RECT  14.808 48.421 15.9 49.715 ;
     RECT  27.144 48.421 28.512 50.003 ;
     RECT  30.696 48.467 32.1 49.477 ;
     RECT  9.144 48.757 10.5 49.043 ;
     RECT  67.512 48.757 68.928 49.189 ;
     RECT  12.12 48.947 13.2 51.635 ;
     RECT  67.512 49.189 68.592 49.717 ;
     RECT  13.656 49.237 14.784 49.715 ;
     RECT  30.696 49.477 31.968 49.763 ;
     RECT  38.376 49.523 39.696 50.243 ;
     RECT  68.616 49.619 69.9 49.763 ;
     RECT  29.712 49.763 30.024 51.253 ;
     RECT  68.424 49.763 69.9 51.781 ;
     RECT  32.412 49.861 33.792 50.099 ;
     RECT  27.012 50.003 28.512 50.195 ;
     RECT  48.612 50.051 48.744 51.253 ;
     RECT  54.888 50.051 56.4 51.635 ;
     RECT  70.212 50.051 71.472 53.941 ;
     RECT  34.176 50.099 34.224 51.253 ;
     RECT  59.412 50.099 60.072 50.725 ;
     RECT  27.012 50.195 27.336 51.493 ;
     RECT  61.632 50.195 61.8 50.725 ;
     RECT  71.496 50.291 72.48 53.987 ;
     RECT  22.824 50.533 24 50.675 ;
     RECT  23.856 50.675 24 51.541 ;
     RECT  59.412 50.725 60.384 51.395 ;
     RECT  60.408 50.725 61.8 51.395 ;
     RECT  51.312 50.965 52.416 52.739 ;
     RECT  52.44 50.965 53.7 52.693 ;
     RECT  8.112 51.347 8.52 52.693 ;
     RECT  40.824 51.443 41.112 52.405 ;
     RECT  13.104 51.635 13.2 51.877 ;
     RECT  54.012 51.635 54.168 52.789 ;
     RECT  68.568 51.781 69.9 52.981 ;
     RECT  35.112 51.829 36.288 52.739 ;
     RECT  34.368 51.923 34.8 53.269 ;
     RECT  56.712 51.923 56.952 53.077 ;
     RECT  39.744 52.211 39.936 53.509 ;
     RECT  5.736 52.261 7.056 52.691 ;
     RECT  41.736 52.405 42.9 53.555 ;
     RECT  48.744 52.405 50.16 52.451 ;
     RECT  21.168 52.451 21.3 52.549 ;
     RECT  18.912 52.549 20.016 53.795 ;
     RECT  20.04 52.549 21.3 53.795 ;
     RECT  8.112 52.693 9.12 52.883 ;
     RECT  9.144 52.693 10.5 52.883 ;
     RECT  35.112 52.739 36.384 53.941 ;
     RECT  51.312 52.739 52.752 55.861 ;
     RECT  8.112 52.883 8.52 53.077 ;
     RECT  13.512 52.931 13.656 52.933 ;
     RECT  13.512 52.933 14.832 54.179 ;
     RECT  14.856 52.933 15.9 54.179 ;
     RECT  56.712 53.077 57.696 54.899 ;
     RECT  57.72 53.077 59.1 54.709 ;
     RECT  41.64 53.555 42.9 54.229 ;
     RECT  62.952 53.555 64.368 55.283 ;
     RECT  67.512 53.603 68.544 53.843 ;
     RECT  68.568 53.795 69.9 53.843 ;
     RECT  38.232 53.797 39.744 54.659 ;
     RECT  70.212 53.941 71.232 54.853 ;
     RECT  71.448 53.987 72.48 54.899 ;
     RECT  22.344 54.085 23.856 55.237 ;
     RECT  41.64 54.229 42.768 55.283 ;
     RECT  9.144 54.517 10.5 55.283 ;
     RECT  8.112 54.563 9.12 55.283 ;
     RECT  11.4 54.613 12.816 55.859 ;
     RECT  39.696 54.659 39.744 55.093 ;
     RECT  57.72 54.709 58.992 54.899 ;
     RECT  56.712 54.899 57.288 55.813 ;
     RECT  58.848 54.899 58.992 56.005 ;
     RECT  71.208 54.899 72.48 55.475 ;
     RECT  34.512 55.139 34.8 56.389 ;
     RECT  22.536 55.237 23.856 56.483 ;
     RECT  10.368 55.283 10.5 55.525 ;
     RECT  35.352 55.283 36.384 58.117 ;
     RECT  41.64 55.283 42.9 55.475 ;
     RECT  62.952 55.283 64.5 56.389 ;
     RECT  5.412 55.285 6.864 57.059 ;
     RECT  70.212 55.379 71.184 56.099 ;
     RECT  71.208 55.475 72.6 56.053 ;
     RECT  43.32 55.813 44.832 56.387 ;
     RECT  60.504 55.813 61.8 57.155 ;
     RECT  51.312 55.861 52.368 57.059 ;
     RECT  71.304 56.053 72.6 58.501 ;
     RECT  70.212 56.099 71.28 58.547 ;
     RECT  7.344 57.059 7.632 58.117 ;
     RECT  51.312 57.059 51.432 58.501 ;
     RECT  45.912 57.109 47.376 61.043 ;
     RECT  59.832 57.155 61.8 58.259 ;
     RECT  54.012 57.397 55.296 59.077 ;
     RECT  55.32 57.397 56.4 58.501 ;
     RECT  38.472 58.069 39.696 59.171 ;
     RECT  61.008 58.259 61.8 58.645 ;
     RECT  13.512 58.355 13.752 58.645 ;
     RECT  67.608 58.501 69.12 59.461 ;
     RECT  57.336 58.597 58.848 58.691 ;
     RECT  13.512 58.645 14.496 60.613 ;
     RECT  14.52 58.645 15.9 61.043 ;
     RECT  34.512 58.691 34.8 59.605 ;
     RECT  62.112 58.931 63.264 59.507 ;
     RECT  53.04 59.027 53.136 60.277 ;
     RECT  54.012 59.077 55.248 59.939 ;
     RECT  22.008 59.123 23.232 59.843 ;
     RECT  35.352 59.123 36.384 60.949 ;
     RECT  24.408 59.219 25.728 59.411 ;
     RECT  40.92 59.221 42.048 62.195 ;
     RECT  24.312 59.411 25.728 61.573 ;
     RECT  67.656 59.461 69.12 59.795 ;
     RECT  62.112 59.507 63.408 60.275 ;
     RECT  32.412 59.605 33.648 59.701 ;
     RECT  33.672 59.605 34.8 60.467 ;
     RECT  32.568 59.701 33.648 60.467 ;
     RECT  6.312 59.797 7.344 60.995 ;
     RECT  43.212 59.797 44.496 60.277 ;
     RECT  44.52 59.797 45.6 61.861 ;
     RECT  22.008 59.843 24 60.709 ;
     RECT  51.312 59.891 51.432 60.277 ;
     RECT  54.012 59.939 55.728 60.037 ;
     RECT  54.12 60.037 55.728 61.093 ;
     RECT  56.712 60.275 57.336 61.525 ;
     RECT  62.112 60.275 63.552 62.051 ;
     RECT  27.012 60.277 28.416 62.341 ;
     RECT  43.32 60.277 44.496 61.763 ;
     RECT  51.312 60.277 52.656 61.619 ;
     RECT  65.016 60.373 66.432 62.005 ;
     RECT  22.968 60.709 24 62.195 ;
     RECT  61.104 60.803 61.488 61.765 ;
     RECT  14.376 61.043 15.9 64.693 ;
     RECT  54.12 61.093 55.296 61.571 ;
     RECT  35.88 61.139 37.008 61.235 ;
     RECT  56.712 61.525 58.128 62.293 ;
     RECT  54.012 61.571 55.296 62.339 ;
     RECT  24.312 61.573 25.632 62.821 ;
     RECT  25.656 61.619 26.7 62.677 ;
     RECT  70.212 61.717 71.28 64.405 ;
     RECT  43.212 61.763 44.496 62.915 ;
     RECT  71.304 61.763 72.6 66.469 ;
     RECT  60.264 61.765 61.488 62.771 ;
     RECT  62.112 62.051 62.232 63.493 ;
     RECT  22.824 62.195 24 63.059 ;
     RECT  40.92 62.195 40.968 62.725 ;
     RECT  56.808 62.293 58.128 62.339 ;
     RECT  54.012 62.339 55.728 63.205 ;
     RECT  27.012 62.341 28.176 63.779 ;
     RECT  11.784 62.437 13.2 64.595 ;
     RECT  31.968 62.579 32.1 63.013 ;
     RECT  24.552 62.821 25.632 63.779 ;
     RECT  44.52 62.867 45.6 62.915 ;
     RECT  43.212 62.915 43.992 64.213 ;
     RECT  30.84 63.013 32.1 64.403 ;
     RECT  22.008 63.059 22.392 64.357 ;
     RECT  54.744 63.205 55.728 64.355 ;
     RECT  33.24 63.541 34.608 64.355 ;
     RECT  35.112 63.541 36.432 64.355 ;
     RECT  48.612 63.635 48.744 64.933 ;
     RECT  27.012 63.779 28.704 64.309 ;
     RECT  27.384 64.309 28.704 66.707 ;
     RECT  62.28 64.357 63.552 65.459 ;
     RECT  65.208 64.595 66.24 66.085 ;
     RECT  14.664 64.693 15.9 64.979 ;
     RECT  14.568 64.979 15.9 65.411 ;
     RECT  14.376 65.411 15.9 68.869 ;
     RECT  62.28 65.459 63.696 65.795 ;
     RECT  46.776 65.509 48.3 67.235 ;
     RECT  70.212 65.603 71.28 66.515 ;
     RECT  44.472 65.653 45.6 67.859 ;
     RECT  62.232 65.795 63.696 67.859 ;
     RECT  48.612 65.939 48.744 67.189 ;
     RECT  67.512 66.083 67.608 67.573 ;
     RECT  40.512 66.179 40.968 67.285 ;
     RECT  37.812 66.325 39.12 69.349 ;
     RECT  71.448 66.469 72.6 67.859 ;
     RECT  70.212 66.515 71.424 67.859 ;
     RECT  22.008 66.611 22.392 67.189 ;
     RECT  43.212 66.755 44.448 67.859 ;
     RECT  19.896 67.189 21.12 67.859 ;
     RECT  22.008 67.189 23.856 67.333 ;
     RECT  49.512 67.189 51 67.859 ;
     RECT  45.912 67.235 48.3 68.341 ;
     RECT  35.784 67.285 37.248 68.099 ;
     RECT  40.512 67.285 41.664 69.541 ;
     RECT  22.008 67.333 23.328 68.581 ;
     RECT  56.712 67.765 58.128 68.531 ;
     RECT  19.896 67.859 21.168 67.955 ;
     RECT  45.36 67.859 45.6 68.821 ;
     RECT  70.212 67.859 70.872 69.349 ;
     RECT  72.48 67.859 72.6 69.301 ;
     RECT  10.812 67.907 10.968 68.917 ;
     RECT  13.008 67.907 13.104 68.917 ;
     RECT  19.896 67.955 21.3 68.387 ;
     RECT  54.012 68.245 55.056 68.869 ;
     RECT  7.68 68.339 7.8 69.493 ;
     RECT  45.912 68.341 46.992 69.539 ;
     RECT  47.016 68.341 48.3 69.493 ;
     RECT  22.008 68.723 23.328 68.915 ;
     RECT  25.128 68.821 26.112 68.963 ;
     RECT  14.856 68.869 15.9 71.603 ;
     RECT  10.812 68.917 12.24 71.939 ;
     RECT  32.412 69.011 32.52 70.021 ;
     RECT  45.36 69.251 45.6 70.117 ;
     RECT  71.4 69.445 72.48 70.021 ;
     RECT  47.304 69.493 48.3 70.067 ;
     RECT  45.912 69.539 47.28 70.067 ;
     RECT  40.512 69.541 41.568 70.499 ;
     RECT  26.112 69.683 26.208 70.741 ;
     RECT  65.496 69.829 66.528 69.973 ;
     RECT  65.544 69.973 66.528 70.259 ;
     RECT  45.912 70.067 48.3 71.077 ;
     RECT  54.216 70.067 55.2 71.843 ;
     RECT  44.184 70.117 45.6 70.739 ;
     RECT  67.8 70.117 68.928 70.307 ;
     RECT  13.512 70.163 14.832 71.603 ;
     RECT  18.912 70.259 19.032 71.221 ;
     RECT  65.544 70.259 67.2 70.453 ;
     RECT  59.688 70.261 61.056 70.979 ;
     RECT  67.512 70.307 68.928 70.451 ;
     RECT  16.212 70.405 17.616 74.869 ;
     RECT  32.904 70.405 34.176 72.421 ;
     RECT  67.512 70.451 69.792 70.837 ;
     RECT  66.168 70.453 67.2 72.419 ;
     RECT  40.512 70.499 42.048 70.981 ;
     RECT  57.624 70.549 58.992 71.077 ;
     RECT  73.272 70.597 74.592 70.645 ;
     RECT  70.212 70.691 71.616 73.909 ;
     RECT  49.512 70.693 51 71.843 ;
     RECT  43.896 70.739 45.6 71.461 ;
     RECT  24.312 70.741 25.584 71.267 ;
     RECT  4.992 70.835 5.1 71.989 ;
     RECT  30.264 70.837 31.344 71.267 ;
     RECT  67.512 70.837 68.592 71.461 ;
     RECT  68.616 70.837 69.792 71.749 ;
     RECT  40.632 70.981 42.048 71.893 ;
     RECT  45.912 71.077 47.28 71.893 ;
     RECT  47.304 71.077 48.3 72.949 ;
     RECT  57.624 71.077 58.944 71.123 ;
     RECT  58.8 71.123 58.944 71.221 ;
     RECT  24.312 71.267 24.408 71.989 ;
     RECT  30.264 71.267 31.584 71.891 ;
     RECT  64.968 71.315 66.144 72.419 ;
     RECT  43.896 71.461 44.976 72.467 ;
     RECT  13.512 71.603 14.232 71.797 ;
     RECT  68.712 71.749 69.792 72.179 ;
     RECT  27.288 71.795 28.704 72.995 ;
     RECT  13.752 71.797 14.232 73.093 ;
     RECT  51.312 71.797 52.656 72.707 ;
     RECT  49.32 71.843 51 73.093 ;
     RECT  54.012 71.843 55.2 73.237 ;
     RECT  7.296 71.891 7.8 72.901 ;
     RECT  30.264 71.891 32.1 72.517 ;
     RECT  73.416 71.891 73.512 72.901 ;
     RECT  40.92 71.893 42.048 72.371 ;
     RECT  46.056 71.893 47.28 72.901 ;
     RECT  3.864 71.989 5.1 73.235 ;
     RECT  40.632 72.371 42.048 75.397 ;
     RECT  21.612 72.373 22.896 72.661 ;
     RECT  22.92 72.373 24 72.851 ;
     RECT  2.712 72.419 3.84 73.235 ;
     RECT  32.904 72.421 34.128 74.723 ;
     RECT  43.896 72.467 45.264 72.803 ;
     RECT  30.696 72.517 32.1 74.053 ;
     RECT  21.612 72.661 22.8 72.851 ;
     RECT  51.312 72.707 53.52 73.477 ;
     RECT  43.8 72.803 45.264 72.995 ;
     RECT  21.612 72.851 24 72.901 ;
     RECT  56.712 72.853 57.696 74.293 ;
     RECT  57.72 72.853 58.8 74.147 ;
     RECT  5.544 72.901 7.056 73.477 ;
     RECT  21.612 72.901 22.752 74.867 ;
     RECT  22.776 72.901 24 74.867 ;
     RECT  46.104 72.901 47.28 73.139 ;
     RECT  28.656 72.995 28.704 74.245 ;
     RECT  43.212 72.995 45.264 73.813 ;
     RECT  49.56 73.093 51 73.525 ;
     RECT  46.056 73.139 47.28 75.251 ;
     RECT  4.752 73.235 5.1 73.477 ;
     RECT  54.12 73.237 55.2 73.283 ;
     RECT  54.12 73.283 55.728 74.053 ;
     RECT  5.544 73.477 6.864 73.811 ;
     RECT  52.008 73.477 53.52 74.147 ;
     RECT  62.808 73.477 63.84 73.765 ;
     RECT  5.544 73.811 7.8 74.677 ;
     RECT  43.212 73.813 44.592 74.723 ;
     RECT  70.584 73.909 71.616 74.581 ;
     RECT  30.84 74.053 32.1 75.251 ;
     RECT  54.744 74.053 55.728 75.011 ;
     RECT  60.312 74.053 61.632 74.147 ;
     RECT  57.72 74.147 59.1 74.579 ;
     RECT  60.312 74.147 61.68 75.203 ;
     RECT  49.56 74.579 51 75.395 ;
     RECT  35.928 74.581 37.248 76.117 ;
     RECT  6.312 74.677 7.8 75.781 ;
     RECT  32.412 74.723 34.128 75.781 ;
     RECT  43.212 74.723 45.264 75.157 ;
     RECT  63.288 74.723 64.5 75.299 ;
     RECT  62.112 74.771 63.264 75.299 ;
     RECT  21.612 74.867 24 75.397 ;
     RECT  16.584 74.869 17.616 76.259 ;
     RECT  65.688 75.109 67.2 75.205 ;
     RECT  27.012 75.157 28.512 76.357 ;
     RECT  43.944 75.157 45.264 75.731 ;
     RECT  38.088 75.203 39.264 76.979 ;
     RECT  8.112 75.205 9.12 78.755 ;
     RECT  18.912 75.205 19.968 76.163 ;
     RECT  19.992 75.205 21.168 76.163 ;
     RECT  65.688 75.205 66.672 75.539 ;
     RECT  30.696 75.251 32.1 76.933 ;
     RECT  46.008 75.251 47.28 77.315 ;
     RECT  49.32 75.395 51 76.357 ;
     RECT  21.612 75.397 23.136 76.931 ;
     RECT  40.632 75.397 41.616 76.357 ;
     RECT  65.688 75.539 67.2 76.453 ;
     RECT  43.944 75.731 45.6 76.403 ;
     RECT  41.64 75.779 42.9 79.187 ;
     RECT  6.312 75.781 7.296 76.499 ;
     RECT  35.976 76.117 37.248 76.979 ;
     RECT  73.992 76.117 75.3 76.309 ;
     RECT  20.592 76.163 21.168 76.165 ;
     RECT  16.584 76.259 18.48 77.555 ;
     RECT  74.088 76.309 75.3 77.651 ;
     RECT  27.012 76.357 28.464 76.979 ;
     RECT  49.56 76.357 51 77.555 ;
     RECT  43.212 76.403 45.6 76.885 ;
     RECT  65.976 76.453 67.2 76.597 ;
     RECT  43.212 76.885 44.448 77.315 ;
     RECT  44.472 76.885 45.6 77.315 ;
     RECT  21.612 76.931 24 77.413 ;
     RECT  40.512 76.931 41.616 79.141 ;
     RECT  30.696 76.933 31.872 77.603 ;
     RECT  38.088 76.979 39.792 78.037 ;
     RECT  56.712 76.981 57.792 79.187 ;
     RECT  57.816 76.981 59.1 77.317 ;
     RECT  43.212 77.315 43.896 78.037 ;
     RECT  45.912 77.315 47.28 79.283 ;
     RECT  53.088 77.363 53.52 77.941 ;
     RECT  21.612 77.413 22.8 79.235 ;
     RECT  22.824 77.413 24 78.277 ;
     RECT  16.584 77.555 17.016 77.557 ;
     RECT  49.32 77.555 51 78.613 ;
     RECT  54.012 77.555 54.12 78.037 ;
     RECT  61.68 77.555 61.8 78.037 ;
     RECT  64.812 77.555 65.808 80.867 ;
     RECT  30.648 77.603 31.872 78.611 ;
     RECT  74.04 77.651 75.3 78.131 ;
     RECT  52.296 77.941 53.52 78.659 ;
     RECT  38.664 78.037 39.792 79.283 ;
     RECT  54.012 78.037 55.296 78.755 ;
     RECT  60.552 78.037 61.8 79.235 ;
     RECT  65.832 78.083 67.2 79.189 ;
     RECT  59.412 78.179 60.528 79.235 ;
     RECT  70.212 78.419 71.28 79.669 ;
     RECT  30.648 78.611 32.1 80.533 ;
     RECT  27.012 78.613 28.464 80.245 ;
     RECT  68.424 78.613 69.9 79.189 ;
     RECT  52.296 78.659 53.568 78.755 ;
     RECT  8.112 78.755 9.6 79.763 ;
     RECT  22.824 78.899 24 79.235 ;
     RECT  73.272 79.139 73.32 80.341 ;
     RECT  41.448 79.187 42.9 83.843 ;
     RECT  56.712 79.187 58.128 79.715 ;
     RECT  68.424 79.189 69.456 79.477 ;
     RECT  59.412 79.235 59.544 80.101 ;
     RECT  55.824 79.331 56.208 80.293 ;
     RECT  67.512 79.523 68.832 80.531 ;
     RECT  8.112 79.763 9.696 80.773 ;
     RECT  32.412 79.763 33.744 80.579 ;
     RECT  11.208 79.765 12.24 80.339 ;
     RECT  36.216 79.813 37.248 81.011 ;
     RECT  19.128 79.859 20.448 82.979 ;
     RECT  35.112 79.859 36.192 81.011 ;
     RECT  15.216 80.243 15.9 81.685 ;
     RECT  27.912 80.291 29.088 81.445 ;
     RECT  70.344 80.291 71.328 80.579 ;
     RECT  6.312 80.293 7.392 80.531 ;
     RECT  24.984 80.293 26.064 81.443 ;
     RECT  10.812 80.339 12.24 80.869 ;
     RECT  6.312 80.531 7.8 81.875 ;
     RECT  67.512 80.531 69.792 80.821 ;
     RECT  32.412 80.579 34.032 82.069 ;
     RECT  70.212 80.579 71.328 81.445 ;
     RECT  68.424 80.821 69.792 81.733 ;
     RECT  64.812 80.867 66.096 81.251 ;
     RECT  10.812 80.869 12.144 82.163 ;
     RECT  8.52 80.963 9.696 81.251 ;
     RECT  35.112 81.011 35.208 82.309 ;
     RECT  66.12 81.011 67.2 81.251 ;
     RECT  12.168 81.059 13.2 82.163 ;
     RECT  74.28 81.205 75.3 82.213 ;
     RECT  49.32 81.251 50.688 82.115 ;
     RECT  70.212 81.445 71.232 83.267 ;
     RECT  27.012 81.635 28.512 82.739 ;
     RECT  13.512 81.685 14.832 81.875 ;
     RECT  14.856 81.685 15.9 81.875 ;
     RECT  68.712 81.733 69.792 82.021 ;
     RECT  68.712 82.021 69.696 82.691 ;
     RECT  30.648 82.067 31.92 82.691 ;
     RECT  32.52 82.069 34.032 83.363 ;
     RECT  12.528 82.163 13.2 82.645 ;
     RECT  59.544 82.309 61.008 82.499 ;
     RECT  21.612 82.691 22.44 83.653 ;
     RECT  30.648 82.691 31.968 82.739 ;
     RECT  68.712 82.691 69.744 85.523 ;
     RECT  72.912 82.739 73.512 84.181 ;
     RECT  59.412 83.075 59.544 84.181 ;
     RECT  24.552 83.267 24.984 84.709 ;
     RECT  70.212 83.267 71.424 83.749 ;
     RECT  32.412 83.363 34.032 84.325 ;
     RECT  48.612 83.363 48.984 84.037 ;
     RECT  38.76 83.653 40.2 87.779 ;
     RECT  70.392 83.749 71.424 83.795 ;
     RECT  12.528 83.843 13.2 83.893 ;
     RECT  41.4 83.843 42.9 84.085 ;
     RECT  10.812 83.893 11.952 84.037 ;
     RECT  11.976 83.893 13.2 86.099 ;
     RECT  10.92 84.037 11.952 85.139 ;
     RECT  48.612 84.037 50.016 84.611 ;
     RECT  41.4 84.085 42.72 85.427 ;
     RECT  46.056 84.085 47.232 86.099 ;
     RECT  72.24 84.419 72.288 84.995 ;
     RECT  21.612 84.611 22.44 84.757 ;
     RECT  47.256 84.611 48.3 86.099 ;
     RECT  48.612 84.611 50.064 87.683 ;
     RECT  25.512 84.709 26.7 87.299 ;
     RECT  21.612 84.757 22.752 85.523 ;
     RECT  22.776 84.757 24 85.523 ;
     RECT  13.512 84.901 14.496 85.477 ;
     RECT  14.52 84.901 15.792 85.717 ;
     RECT  18.912 84.901 19.92 85.189 ;
     RECT  72.24 84.995 72.6 85.621 ;
     RECT  10.812 85.139 11.952 86.099 ;
     RECT  6.264 85.187 7.392 85.379 ;
     RECT  8.112 85.187 9.36 86.723 ;
     RECT  6.072 85.379 7.392 86.771 ;
     RECT  41.4 85.427 42.9 86.099 ;
     RECT  16.392 85.477 17.424 86.915 ;
     RECT  17.448 85.477 18.6 87.299 ;
     RECT  57.576 85.477 58.992 86.819 ;
     RECT  68.712 85.523 69.792 85.811 ;
     RECT  71.256 85.621 72.6 85.957 ;
     RECT  27.72 85.669 29.04 86.053 ;
     RECT  24.408 85.715 25.488 86.725 ;
     RECT  68.712 85.811 69.9 86.675 ;
     RECT  62.52 85.957 63.504 87.251 ;
     RECT  63.528 85.957 64.5 87.251 ;
     RECT  71.256 85.957 72.48 86.675 ;
     RECT  14.52 86.003 15.792 86.339 ;
     RECT  27.912 86.053 29.04 86.723 ;
     RECT  42.672 86.099 42.9 87.013 ;
     RECT  46.056 86.099 48.3 86.341 ;
     RECT  14.28 86.339 15.792 86.771 ;
     RECT  46.056 86.341 47.184 86.725 ;
     RECT  47.208 86.341 48.3 89.027 ;
     RECT  19.512 86.531 20.784 87.059 ;
     RECT  35.112 86.581 36.144 87.733 ;
     RECT  36.168 86.581 37.248 87.251 ;
     RECT  68.232 86.675 69.9 87.683 ;
     RECT  71.256 86.675 72.6 86.771 ;
     RECT  27.912 86.723 29.088 87.827 ;
     RECT  15.744 86.771 15.792 87.877 ;
     RECT  57.576 86.819 59.1 88.979 ;
     RECT  24.408 86.867 25.488 87.059 ;
     RECT  16.212 86.915 17.424 87.299 ;
     RECT  18.912 87.059 20.784 88.309 ;
     RECT  24.312 87.059 25.488 87.299 ;
     RECT  36.168 87.251 37.5 90.035 ;
     RECT  48.612 87.683 49.128 88.741 ;
     RECT  67.512 87.683 69.9 87.733 ;
     RECT  67.512 87.733 68.928 88.883 ;
     RECT  37.944 87.779 40.2 88.213 ;
     RECT  27.912 87.827 29.4 88.355 ;
     RECT  37.944 88.213 39.36 88.403 ;
     RECT  21.612 88.261 23.088 88.931 ;
     RECT  19.8 88.309 20.784 89.027 ;
     RECT  70.344 88.309 71.424 88.403 ;
     RECT  71.448 88.309 72.6 88.979 ;
     RECT  35.112 88.403 36.144 90.035 ;
     RECT  70.212 88.403 71.424 88.979 ;
     RECT  67.512 88.883 67.8 88.933 ;
     RECT  19.8 89.027 21.3 90.083 ;
  END
END dsfd_l2r_vr_512x1__hq_SW
END LIBRARY
